VERSION 5.8 ;
BUSBITCHARS "[]" ;
DIVIDERCHAR "/" ;
UNITS
    DATABASE MICRONS 1000 ;
END UNITS

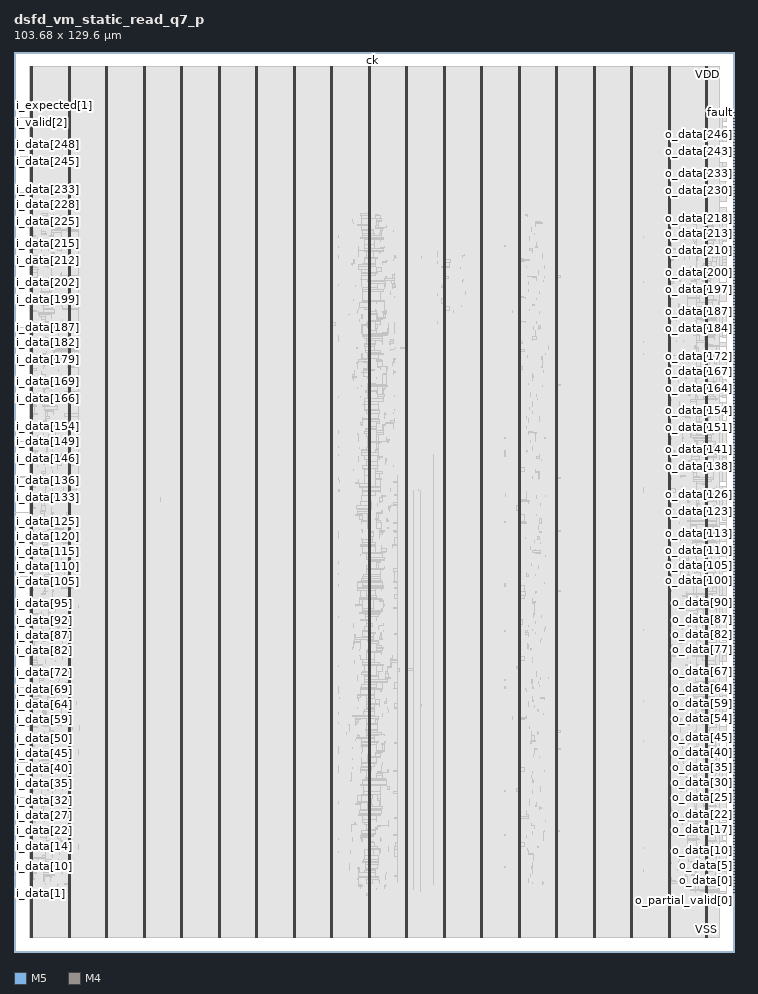
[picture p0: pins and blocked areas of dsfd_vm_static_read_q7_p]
MACRO dsfd_vm_static_read_q7_p
  FOREIGN dsfd_vm_static_read_q7_p 0 0 ;
  CLASS BLOCK ;
  SIZE 103.68 BY 129.6 ;
  PIN ck
    DIRECTION INPUT ;
    USE SIGNAL ;
    PORT
      LAYER M5 ;
        RECT  51.6 129.516 51.624 129.6 ;
    END
  END ck
  PIN fault
    DIRECTION OUTPUT ;
    USE SIGNAL ;
    PORT
      LAYER M4 ;
        RECT  103.596 120.912 103.68 120.936 ;
    END
  END fault
  PIN i_data[0]
    DIRECTION INPUT ;
    USE SIGNAL ;
    PORT
      LAYER M4 ;
        RECT  0 7.968 0.084 7.992 ;
    END
  END i_data[0]
  PIN i_data[100]
    DIRECTION INPUT ;
    USE SIGNAL ;
    PORT
      LAYER M4 ;
        RECT  0 51.168 0.084 51.192 ;
    END
  END i_data[100]
  PIN i_data[101]
    DIRECTION INPUT ;
    USE SIGNAL ;
    PORT
      LAYER M4 ;
        RECT  0 51.6 0.084 51.624 ;
    END
  END i_data[101]
  PIN i_data[102]
    DIRECTION INPUT ;
    USE SIGNAL ;
    PORT
      LAYER M4 ;
        RECT  0 52.032 0.084 52.056 ;
    END
  END i_data[102]
  PIN i_data[103]
    DIRECTION INPUT ;
    USE SIGNAL ;
    PORT
      LAYER M4 ;
        RECT  0 52.464 0.084 52.488 ;
    END
  END i_data[103]
  PIN i_data[104]
    DIRECTION INPUT ;
    USE SIGNAL ;
    PORT
      LAYER M4 ;
        RECT  0 52.896 0.084 52.92 ;
    END
  END i_data[104]
  PIN i_data[105]
    DIRECTION INPUT ;
    USE SIGNAL ;
    PORT
      LAYER M4 ;
        RECT  0 53.328 0.084 53.352 ;
    END
  END i_data[105]
  PIN i_data[106]
    DIRECTION INPUT ;
    USE SIGNAL ;
    PORT
      LAYER M4 ;
        RECT  0 53.76 0.084 53.784 ;
    END
  END i_data[106]
  PIN i_data[107]
    DIRECTION INPUT ;
    USE SIGNAL ;
    PORT
      LAYER M4 ;
        RECT  0 54.192 0.084 54.216 ;
    END
  END i_data[107]
  PIN i_data[108]
    DIRECTION INPUT ;
    USE SIGNAL ;
    PORT
      LAYER M4 ;
        RECT  0 54.624 0.084 54.648 ;
    END
  END i_data[108]
  PIN i_data[109]
    DIRECTION INPUT ;
    USE SIGNAL ;
    PORT
      LAYER M4 ;
        RECT  0 55.056 0.084 55.08 ;
    END
  END i_data[109]
  PIN i_data[10]
    DIRECTION INPUT ;
    USE SIGNAL ;
    PORT
      LAYER M4 ;
        RECT  0 12.288 0.084 12.312 ;
    END
  END i_data[10]
  PIN i_data[110]
    DIRECTION INPUT ;
    USE SIGNAL ;
    PORT
      LAYER M4 ;
        RECT  0 55.488 0.084 55.512 ;
    END
  END i_data[110]
  PIN i_data[111]
    DIRECTION INPUT ;
    USE SIGNAL ;
    PORT
      LAYER M4 ;
        RECT  0 55.92 0.084 55.944 ;
    END
  END i_data[111]
  PIN i_data[112]
    DIRECTION INPUT ;
    USE SIGNAL ;
    PORT
      LAYER M4 ;
        RECT  0 56.352 0.084 56.376 ;
    END
  END i_data[112]
  PIN i_data[113]
    DIRECTION INPUT ;
    USE SIGNAL ;
    PORT
      LAYER M4 ;
        RECT  0 56.784 0.084 56.808 ;
    END
  END i_data[113]
  PIN i_data[114]
    DIRECTION INPUT ;
    USE SIGNAL ;
    PORT
      LAYER M4 ;
        RECT  0 57.216 0.084 57.24 ;
    END
  END i_data[114]
  PIN i_data[115]
    DIRECTION INPUT ;
    USE SIGNAL ;
    PORT
      LAYER M4 ;
        RECT  0 57.648 0.084 57.672 ;
    END
  END i_data[115]
  PIN i_data[116]
    DIRECTION INPUT ;
    USE SIGNAL ;
    PORT
      LAYER M4 ;
        RECT  0 58.08 0.084 58.104 ;
    END
  END i_data[116]
  PIN i_data[117]
    DIRECTION INPUT ;
    USE SIGNAL ;
    PORT
      LAYER M4 ;
        RECT  0 58.512 0.084 58.536 ;
    END
  END i_data[117]
  PIN i_data[118]
    DIRECTION INPUT ;
    USE SIGNAL ;
    PORT
      LAYER M4 ;
        RECT  0 58.944 0.084 58.968 ;
    END
  END i_data[118]
  PIN i_data[119]
    DIRECTION INPUT ;
    USE SIGNAL ;
    PORT
      LAYER M4 ;
        RECT  0 59.376 0.084 59.4 ;
    END
  END i_data[119]
  PIN i_data[11]
    DIRECTION INPUT ;
    USE SIGNAL ;
    PORT
      LAYER M4 ;
        RECT  0 12.72 0.084 12.744 ;
    END
  END i_data[11]
  PIN i_data[120]
    DIRECTION INPUT ;
    USE SIGNAL ;
    PORT
      LAYER M4 ;
        RECT  0 59.808 0.084 59.832 ;
    END
  END i_data[120]
  PIN i_data[121]
    DIRECTION INPUT ;
    USE SIGNAL ;
    PORT
      LAYER M4 ;
        RECT  0 60.24 0.084 60.264 ;
    END
  END i_data[121]
  PIN i_data[122]
    DIRECTION INPUT ;
    USE SIGNAL ;
    PORT
      LAYER M4 ;
        RECT  0 60.672 0.084 60.696 ;
    END
  END i_data[122]
  PIN i_data[123]
    DIRECTION INPUT ;
    USE SIGNAL ;
    PORT
      LAYER M4 ;
        RECT  0 61.104 0.084 61.128 ;
    END
  END i_data[123]
  PIN i_data[124]
    DIRECTION INPUT ;
    USE SIGNAL ;
    PORT
      LAYER M4 ;
        RECT  0 61.536 0.084 61.56 ;
    END
  END i_data[124]
  PIN i_data[125]
    DIRECTION INPUT ;
    USE SIGNAL ;
    PORT
      LAYER M4 ;
        RECT  0 61.968 0.084 61.992 ;
    END
  END i_data[125]
  PIN i_data[126]
    DIRECTION INPUT ;
    USE SIGNAL ;
    PORT
      LAYER M4 ;
        RECT  0 62.4 0.084 62.424 ;
    END
  END i_data[126]
  PIN i_data[127]
    DIRECTION INPUT ;
    USE SIGNAL ;
    PORT
      LAYER M4 ;
        RECT  0 62.832 0.084 62.856 ;
    END
  END i_data[127]
  PIN i_data[128]
    DIRECTION INPUT ;
    USE SIGNAL ;
    PORT
      LAYER M4 ;
        RECT  0 63.264 0.084 63.288 ;
    END
  END i_data[128]
  PIN i_data[129]
    DIRECTION INPUT ;
    USE SIGNAL ;
    PORT
      LAYER M4 ;
        RECT  0 63.696 0.084 63.72 ;
    END
  END i_data[129]
  PIN i_data[12]
    DIRECTION INPUT ;
    USE SIGNAL ;
    PORT
      LAYER M4 ;
        RECT  0 13.152 0.084 13.176 ;
    END
  END i_data[12]
  PIN i_data[130]
    DIRECTION INPUT ;
    USE SIGNAL ;
    PORT
      LAYER M4 ;
        RECT  0 64.128 0.084 64.152 ;
    END
  END i_data[130]
  PIN i_data[131]
    DIRECTION INPUT ;
    USE SIGNAL ;
    PORT
      LAYER M4 ;
        RECT  0 64.56 0.084 64.584 ;
    END
  END i_data[131]
  PIN i_data[132]
    DIRECTION INPUT ;
    USE SIGNAL ;
    PORT
      LAYER M4 ;
        RECT  0 64.992 0.084 65.016 ;
    END
  END i_data[132]
  PIN i_data[133]
    DIRECTION INPUT ;
    USE SIGNAL ;
    PORT
      LAYER M4 ;
        RECT  0 65.424 0.084 65.448 ;
    END
  END i_data[133]
  PIN i_data[134]
    DIRECTION INPUT ;
    USE SIGNAL ;
    PORT
      LAYER M4 ;
        RECT  0 65.856 0.084 65.88 ;
    END
  END i_data[134]
  PIN i_data[135]
    DIRECTION INPUT ;
    USE SIGNAL ;
    PORT
      LAYER M4 ;
        RECT  0 66.288 0.084 66.312 ;
    END
  END i_data[135]
  PIN i_data[136]
    DIRECTION INPUT ;
    USE SIGNAL ;
    PORT
      LAYER M4 ;
        RECT  0 66.72 0.084 66.744 ;
    END
  END i_data[136]
  PIN i_data[137]
    DIRECTION INPUT ;
    USE SIGNAL ;
    PORT
      LAYER M4 ;
        RECT  0 67.152 0.084 67.176 ;
    END
  END i_data[137]
  PIN i_data[138]
    DIRECTION INPUT ;
    USE SIGNAL ;
    PORT
      LAYER M4 ;
        RECT  0 67.584 0.084 67.608 ;
    END
  END i_data[138]
  PIN i_data[139]
    DIRECTION INPUT ;
    USE SIGNAL ;
    PORT
      LAYER M4 ;
        RECT  0 68.016 0.084 68.04 ;
    END
  END i_data[139]
  PIN i_data[13]
    DIRECTION INPUT ;
    USE SIGNAL ;
    PORT
      LAYER M4 ;
        RECT  0 13.584 0.084 13.608 ;
    END
  END i_data[13]
  PIN i_data[140]
    DIRECTION INPUT ;
    USE SIGNAL ;
    PORT
      LAYER M4 ;
        RECT  0 68.448 0.084 68.472 ;
    END
  END i_data[140]
  PIN i_data[141]
    DIRECTION INPUT ;
    USE SIGNAL ;
    PORT
      LAYER M4 ;
        RECT  0 68.88 0.084 68.904 ;
    END
  END i_data[141]
  PIN i_data[142]
    DIRECTION INPUT ;
    USE SIGNAL ;
    PORT
      LAYER M4 ;
        RECT  0 69.312 0.084 69.336 ;
    END
  END i_data[142]
  PIN i_data[143]
    DIRECTION INPUT ;
    USE SIGNAL ;
    PORT
      LAYER M4 ;
        RECT  0 69.744 0.084 69.768 ;
    END
  END i_data[143]
  PIN i_data[144]
    DIRECTION INPUT ;
    USE SIGNAL ;
    PORT
      LAYER M4 ;
        RECT  0 70.176 0.084 70.2 ;
    END
  END i_data[144]
  PIN i_data[145]
    DIRECTION INPUT ;
    USE SIGNAL ;
    PORT
      LAYER M4 ;
        RECT  0 70.608 0.084 70.632 ;
    END
  END i_data[145]
  PIN i_data[146]
    DIRECTION INPUT ;
    USE SIGNAL ;
    PORT
      LAYER M4 ;
        RECT  0 71.04 0.084 71.064 ;
    END
  END i_data[146]
  PIN i_data[147]
    DIRECTION INPUT ;
    USE SIGNAL ;
    PORT
      LAYER M4 ;
        RECT  0 71.472 0.084 71.496 ;
    END
  END i_data[147]
  PIN i_data[148]
    DIRECTION INPUT ;
    USE SIGNAL ;
    PORT
      LAYER M4 ;
        RECT  0 71.904 0.084 71.928 ;
    END
  END i_data[148]
  PIN i_data[149]
    DIRECTION INPUT ;
    USE SIGNAL ;
    PORT
      LAYER M4 ;
        RECT  0 72.336 0.084 72.36 ;
    END
  END i_data[149]
  PIN i_data[14]
    DIRECTION INPUT ;
    USE SIGNAL ;
    PORT
      LAYER M4 ;
        RECT  0 14.016 0.084 14.04 ;
    END
  END i_data[14]
  PIN i_data[150]
    DIRECTION INPUT ;
    USE SIGNAL ;
    PORT
      LAYER M4 ;
        RECT  0 72.768 0.084 72.792 ;
    END
  END i_data[150]
  PIN i_data[151]
    DIRECTION INPUT ;
    USE SIGNAL ;
    PORT
      LAYER M4 ;
        RECT  0 73.2 0.084 73.224 ;
    END
  END i_data[151]
  PIN i_data[152]
    DIRECTION INPUT ;
    USE SIGNAL ;
    PORT
      LAYER M4 ;
        RECT  0 73.632 0.084 73.656 ;
    END
  END i_data[152]
  PIN i_data[153]
    DIRECTION INPUT ;
    USE SIGNAL ;
    PORT
      LAYER M4 ;
        RECT  0 74.064 0.084 74.088 ;
    END
  END i_data[153]
  PIN i_data[154]
    DIRECTION INPUT ;
    USE SIGNAL ;
    PORT
      LAYER M4 ;
        RECT  0 74.496 0.084 74.52 ;
    END
  END i_data[154]
  PIN i_data[155]
    DIRECTION INPUT ;
    USE SIGNAL ;
    PORT
      LAYER M4 ;
        RECT  0 74.928 0.084 74.952 ;
    END
  END i_data[155]
  PIN i_data[156]
    DIRECTION INPUT ;
    USE SIGNAL ;
    PORT
      LAYER M4 ;
        RECT  0 75.36 0.084 75.384 ;
    END
  END i_data[156]
  PIN i_data[157]
    DIRECTION INPUT ;
    USE SIGNAL ;
    PORT
      LAYER M4 ;
        RECT  0 75.792 0.084 75.816 ;
    END
  END i_data[157]
  PIN i_data[158]
    DIRECTION INPUT ;
    USE SIGNAL ;
    PORT
      LAYER M4 ;
        RECT  0 76.224 0.084 76.248 ;
    END
  END i_data[158]
  PIN i_data[159]
    DIRECTION INPUT ;
    USE SIGNAL ;
    PORT
      LAYER M4 ;
        RECT  0 76.656 0.084 76.68 ;
    END
  END i_data[159]
  PIN i_data[15]
    DIRECTION INPUT ;
    USE SIGNAL ;
    PORT
      LAYER M4 ;
        RECT  0 14.448 0.084 14.472 ;
    END
  END i_data[15]
  PIN i_data[160]
    DIRECTION INPUT ;
    USE SIGNAL ;
    PORT
      LAYER M4 ;
        RECT  0 77.088 0.084 77.112 ;
    END
  END i_data[160]
  PIN i_data[161]
    DIRECTION INPUT ;
    USE SIGNAL ;
    PORT
      LAYER M4 ;
        RECT  0 77.52 0.084 77.544 ;
    END
  END i_data[161]
  PIN i_data[162]
    DIRECTION INPUT ;
    USE SIGNAL ;
    PORT
      LAYER M4 ;
        RECT  0 77.952 0.084 77.976 ;
    END
  END i_data[162]
  PIN i_data[163]
    DIRECTION INPUT ;
    USE SIGNAL ;
    PORT
      LAYER M4 ;
        RECT  0 78.384 0.084 78.408 ;
    END
  END i_data[163]
  PIN i_data[164]
    DIRECTION INPUT ;
    USE SIGNAL ;
    PORT
      LAYER M4 ;
        RECT  0 78.816 0.084 78.84 ;
    END
  END i_data[164]
  PIN i_data[165]
    DIRECTION INPUT ;
    USE SIGNAL ;
    PORT
      LAYER M4 ;
        RECT  0 79.248 0.084 79.272 ;
    END
  END i_data[165]
  PIN i_data[166]
    DIRECTION INPUT ;
    USE SIGNAL ;
    PORT
      LAYER M4 ;
        RECT  0 79.68 0.084 79.704 ;
    END
  END i_data[166]
  PIN i_data[167]
    DIRECTION INPUT ;
    USE SIGNAL ;
    PORT
      LAYER M4 ;
        RECT  0 80.112 0.084 80.136 ;
    END
  END i_data[167]
  PIN i_data[168]
    DIRECTION INPUT ;
    USE SIGNAL ;
    PORT
      LAYER M4 ;
        RECT  0 80.544 0.084 80.568 ;
    END
  END i_data[168]
  PIN i_data[169]
    DIRECTION INPUT ;
    USE SIGNAL ;
    PORT
      LAYER M4 ;
        RECT  0 80.976 0.084 81 ;
    END
  END i_data[169]
  PIN i_data[16]
    DIRECTION INPUT ;
    USE SIGNAL ;
    PORT
      LAYER M4 ;
        RECT  0 14.88 0.084 14.904 ;
    END
  END i_data[16]
  PIN i_data[170]
    DIRECTION INPUT ;
    USE SIGNAL ;
    PORT
      LAYER M4 ;
        RECT  0 81.408 0.084 81.432 ;
    END
  END i_data[170]
  PIN i_data[171]
    DIRECTION INPUT ;
    USE SIGNAL ;
    PORT
      LAYER M4 ;
        RECT  0 81.84 0.084 81.864 ;
    END
  END i_data[171]
  PIN i_data[172]
    DIRECTION INPUT ;
    USE SIGNAL ;
    PORT
      LAYER M4 ;
        RECT  0 82.272 0.084 82.296 ;
    END
  END i_data[172]
  PIN i_data[173]
    DIRECTION INPUT ;
    USE SIGNAL ;
    PORT
      LAYER M4 ;
        RECT  0 82.704 0.084 82.728 ;
    END
  END i_data[173]
  PIN i_data[174]
    DIRECTION INPUT ;
    USE SIGNAL ;
    PORT
      LAYER M4 ;
        RECT  0 83.136 0.084 83.16 ;
    END
  END i_data[174]
  PIN i_data[175]
    DIRECTION INPUT ;
    USE SIGNAL ;
    PORT
      LAYER M4 ;
        RECT  0 83.568 0.084 83.592 ;
    END
  END i_data[175]
  PIN i_data[176]
    DIRECTION INPUT ;
    USE SIGNAL ;
    PORT
      LAYER M4 ;
        RECT  0 84 0.084 84.024 ;
    END
  END i_data[176]
  PIN i_data[177]
    DIRECTION INPUT ;
    USE SIGNAL ;
    PORT
      LAYER M4 ;
        RECT  0 84.432 0.084 84.456 ;
    END
  END i_data[177]
  PIN i_data[178]
    DIRECTION INPUT ;
    USE SIGNAL ;
    PORT
      LAYER M4 ;
        RECT  0 84.864 0.084 84.888 ;
    END
  END i_data[178]
  PIN i_data[179]
    DIRECTION INPUT ;
    USE SIGNAL ;
    PORT
      LAYER M4 ;
        RECT  0 85.296 0.084 85.32 ;
    END
  END i_data[179]
  PIN i_data[17]
    DIRECTION INPUT ;
    USE SIGNAL ;
    PORT
      LAYER M4 ;
        RECT  0 15.312 0.084 15.336 ;
    END
  END i_data[17]
  PIN i_data[180]
    DIRECTION INPUT ;
    USE SIGNAL ;
    PORT
      LAYER M4 ;
        RECT  0 85.728 0.084 85.752 ;
    END
  END i_data[180]
  PIN i_data[181]
    DIRECTION INPUT ;
    USE SIGNAL ;
    PORT
      LAYER M4 ;
        RECT  0 86.16 0.084 86.184 ;
    END
  END i_data[181]
  PIN i_data[182]
    DIRECTION INPUT ;
    USE SIGNAL ;
    PORT
      LAYER M4 ;
        RECT  0 86.592 0.084 86.616 ;
    END
  END i_data[182]
  PIN i_data[183]
    DIRECTION INPUT ;
    USE SIGNAL ;
    PORT
      LAYER M4 ;
        RECT  0 87.024 0.084 87.048 ;
    END
  END i_data[183]
  PIN i_data[184]
    DIRECTION INPUT ;
    USE SIGNAL ;
    PORT
      LAYER M4 ;
        RECT  0 87.456 0.084 87.48 ;
    END
  END i_data[184]
  PIN i_data[185]
    DIRECTION INPUT ;
    USE SIGNAL ;
    PORT
      LAYER M4 ;
        RECT  0 87.888 0.084 87.912 ;
    END
  END i_data[185]
  PIN i_data[186]
    DIRECTION INPUT ;
    USE SIGNAL ;
    PORT
      LAYER M4 ;
        RECT  0 88.32 0.084 88.344 ;
    END
  END i_data[186]
  PIN i_data[187]
    DIRECTION INPUT ;
    USE SIGNAL ;
    PORT
      LAYER M4 ;
        RECT  0 88.752 0.084 88.776 ;
    END
  END i_data[187]
  PIN i_data[188]
    DIRECTION INPUT ;
    USE SIGNAL ;
    PORT
      LAYER M4 ;
        RECT  0 89.184 0.084 89.208 ;
    END
  END i_data[188]
  PIN i_data[189]
    DIRECTION INPUT ;
    USE SIGNAL ;
    PORT
      LAYER M4 ;
        RECT  0 89.616 0.084 89.64 ;
    END
  END i_data[189]
  PIN i_data[18]
    DIRECTION INPUT ;
    USE SIGNAL ;
    PORT
      LAYER M4 ;
        RECT  0 15.744 0.084 15.768 ;
    END
  END i_data[18]
  PIN i_data[190]
    DIRECTION INPUT ;
    USE SIGNAL ;
    PORT
      LAYER M4 ;
        RECT  0 90.048 0.084 90.072 ;
    END
  END i_data[190]
  PIN i_data[191]
    DIRECTION INPUT ;
    USE SIGNAL ;
    PORT
      LAYER M4 ;
        RECT  0 90.48 0.084 90.504 ;
    END
  END i_data[191]
  PIN i_data[192]
    DIRECTION INPUT ;
    USE SIGNAL ;
    PORT
      LAYER M4 ;
        RECT  0 90.912 0.084 90.936 ;
    END
  END i_data[192]
  PIN i_data[193]
    DIRECTION INPUT ;
    USE SIGNAL ;
    PORT
      LAYER M4 ;
        RECT  0 91.344 0.084 91.368 ;
    END
  END i_data[193]
  PIN i_data[194]
    DIRECTION INPUT ;
    USE SIGNAL ;
    PORT
      LAYER M4 ;
        RECT  0 91.776 0.084 91.8 ;
    END
  END i_data[194]
  PIN i_data[195]
    DIRECTION INPUT ;
    USE SIGNAL ;
    PORT
      LAYER M4 ;
        RECT  0 92.208 0.084 92.232 ;
    END
  END i_data[195]
  PIN i_data[196]
    DIRECTION INPUT ;
    USE SIGNAL ;
    PORT
      LAYER M4 ;
        RECT  0 92.64 0.084 92.664 ;
    END
  END i_data[196]
  PIN i_data[197]
    DIRECTION INPUT ;
    USE SIGNAL ;
    PORT
      LAYER M4 ;
        RECT  0 93.072 0.084 93.096 ;
    END
  END i_data[197]
  PIN i_data[198]
    DIRECTION INPUT ;
    USE SIGNAL ;
    PORT
      LAYER M4 ;
        RECT  0 93.504 0.084 93.528 ;
    END
  END i_data[198]
  PIN i_data[199]
    DIRECTION INPUT ;
    USE SIGNAL ;
    PORT
      LAYER M4 ;
        RECT  0 93.936 0.084 93.96 ;
    END
  END i_data[199]
  PIN i_data[19]
    DIRECTION INPUT ;
    USE SIGNAL ;
    PORT
      LAYER M4 ;
        RECT  0 16.176 0.084 16.2 ;
    END
  END i_data[19]
  PIN i_data[1]
    DIRECTION INPUT ;
    USE SIGNAL ;
    PORT
      LAYER M4 ;
        RECT  0 8.4 0.084 8.424 ;
    END
  END i_data[1]
  PIN i_data[200]
    DIRECTION INPUT ;
    USE SIGNAL ;
    PORT
      LAYER M4 ;
        RECT  0 94.368 0.084 94.392 ;
    END
  END i_data[200]
  PIN i_data[201]
    DIRECTION INPUT ;
    USE SIGNAL ;
    PORT
      LAYER M4 ;
        RECT  0 94.8 0.084 94.824 ;
    END
  END i_data[201]
  PIN i_data[202]
    DIRECTION INPUT ;
    USE SIGNAL ;
    PORT
      LAYER M4 ;
        RECT  0 95.232 0.084 95.256 ;
    END
  END i_data[202]
  PIN i_data[203]
    DIRECTION INPUT ;
    USE SIGNAL ;
    PORT
      LAYER M4 ;
        RECT  0 95.664 0.084 95.688 ;
    END
  END i_data[203]
  PIN i_data[204]
    DIRECTION INPUT ;
    USE SIGNAL ;
    PORT
      LAYER M4 ;
        RECT  0 96.096 0.084 96.12 ;
    END
  END i_data[204]
  PIN i_data[205]
    DIRECTION INPUT ;
    USE SIGNAL ;
    PORT
      LAYER M4 ;
        RECT  0 96.528 0.084 96.552 ;
    END
  END i_data[205]
  PIN i_data[206]
    DIRECTION INPUT ;
    USE SIGNAL ;
    PORT
      LAYER M4 ;
        RECT  0 96.96 0.084 96.984 ;
    END
  END i_data[206]
  PIN i_data[207]
    DIRECTION INPUT ;
    USE SIGNAL ;
    PORT
      LAYER M4 ;
        RECT  0 97.392 0.084 97.416 ;
    END
  END i_data[207]
  PIN i_data[208]
    DIRECTION INPUT ;
    USE SIGNAL ;
    PORT
      LAYER M4 ;
        RECT  0 97.824 0.084 97.848 ;
    END
  END i_data[208]
  PIN i_data[209]
    DIRECTION INPUT ;
    USE SIGNAL ;
    PORT
      LAYER M4 ;
        RECT  0 98.256 0.084 98.28 ;
    END
  END i_data[209]
  PIN i_data[20]
    DIRECTION INPUT ;
    USE SIGNAL ;
    PORT
      LAYER M4 ;
        RECT  0 16.608 0.084 16.632 ;
    END
  END i_data[20]
  PIN i_data[210]
    DIRECTION INPUT ;
    USE SIGNAL ;
    PORT
      LAYER M4 ;
        RECT  0 98.688 0.084 98.712 ;
    END
  END i_data[210]
  PIN i_data[211]
    DIRECTION INPUT ;
    USE SIGNAL ;
    PORT
      LAYER M4 ;
        RECT  0 99.12 0.084 99.144 ;
    END
  END i_data[211]
  PIN i_data[212]
    DIRECTION INPUT ;
    USE SIGNAL ;
    PORT
      LAYER M4 ;
        RECT  0 99.552 0.084 99.576 ;
    END
  END i_data[212]
  PIN i_data[213]
    DIRECTION INPUT ;
    USE SIGNAL ;
    PORT
      LAYER M4 ;
        RECT  0 99.984 0.084 100.008 ;
    END
  END i_data[213]
  PIN i_data[214]
    DIRECTION INPUT ;
    USE SIGNAL ;
    PORT
      LAYER M4 ;
        RECT  0 100.416 0.084 100.44 ;
    END
  END i_data[214]
  PIN i_data[215]
    DIRECTION INPUT ;
    USE SIGNAL ;
    PORT
      LAYER M4 ;
        RECT  0 100.848 0.084 100.872 ;
    END
  END i_data[215]
  PIN i_data[216]
    DIRECTION INPUT ;
    USE SIGNAL ;
    PORT
      LAYER M4 ;
        RECT  0 101.28 0.084 101.304 ;
    END
  END i_data[216]
  PIN i_data[217]
    DIRECTION INPUT ;
    USE SIGNAL ;
    PORT
      LAYER M4 ;
        RECT  0 101.712 0.084 101.736 ;
    END
  END i_data[217]
  PIN i_data[218]
    DIRECTION INPUT ;
    USE SIGNAL ;
    PORT
      LAYER M4 ;
        RECT  0 102.144 0.084 102.168 ;
    END
  END i_data[218]
  PIN i_data[219]
    DIRECTION INPUT ;
    USE SIGNAL ;
    PORT
      LAYER M4 ;
        RECT  0 102.576 0.084 102.6 ;
    END
  END i_data[219]
  PIN i_data[21]
    DIRECTION INPUT ;
    USE SIGNAL ;
    PORT
      LAYER M4 ;
        RECT  0 17.04 0.084 17.064 ;
    END
  END i_data[21]
  PIN i_data[220]
    DIRECTION INPUT ;
    USE SIGNAL ;
    PORT
      LAYER M4 ;
        RECT  0 103.008 0.084 103.032 ;
    END
  END i_data[220]
  PIN i_data[221]
    DIRECTION INPUT ;
    USE SIGNAL ;
    PORT
      LAYER M4 ;
        RECT  0 103.44 0.084 103.464 ;
    END
  END i_data[221]
  PIN i_data[222]
    DIRECTION INPUT ;
    USE SIGNAL ;
    PORT
      LAYER M4 ;
        RECT  0 103.872 0.084 103.896 ;
    END
  END i_data[222]
  PIN i_data[223]
    DIRECTION INPUT ;
    USE SIGNAL ;
    PORT
      LAYER M4 ;
        RECT  0 104.304 0.084 104.328 ;
    END
  END i_data[223]
  PIN i_data[224]
    DIRECTION INPUT ;
    USE SIGNAL ;
    PORT
      LAYER M4 ;
        RECT  0 104.736 0.084 104.76 ;
    END
  END i_data[224]
  PIN i_data[225]
    DIRECTION INPUT ;
    USE SIGNAL ;
    PORT
      LAYER M4 ;
        RECT  0 105.168 0.084 105.192 ;
    END
  END i_data[225]
  PIN i_data[226]
    DIRECTION INPUT ;
    USE SIGNAL ;
    PORT
      LAYER M4 ;
        RECT  0 105.6 0.084 105.624 ;
    END
  END i_data[226]
  PIN i_data[227]
    DIRECTION INPUT ;
    USE SIGNAL ;
    PORT
      LAYER M4 ;
        RECT  0 106.032 0.084 106.056 ;
    END
  END i_data[227]
  PIN i_data[228]
    DIRECTION INPUT ;
    USE SIGNAL ;
    PORT
      LAYER M4 ;
        RECT  0 106.464 0.084 106.488 ;
    END
  END i_data[228]
  PIN i_data[229]
    DIRECTION INPUT ;
    USE SIGNAL ;
    PORT
      LAYER M4 ;
        RECT  0 106.896 0.084 106.92 ;
    END
  END i_data[229]
  PIN i_data[22]
    DIRECTION INPUT ;
    USE SIGNAL ;
    PORT
      LAYER M4 ;
        RECT  0 17.472 0.084 17.496 ;
    END
  END i_data[22]
  PIN i_data[230]
    DIRECTION INPUT ;
    USE SIGNAL ;
    PORT
      LAYER M4 ;
        RECT  0 107.328 0.084 107.352 ;
    END
  END i_data[230]
  PIN i_data[231]
    DIRECTION INPUT ;
    USE SIGNAL ;
    PORT
      LAYER M4 ;
        RECT  0 107.76 0.084 107.784 ;
    END
  END i_data[231]
  PIN i_data[232]
    DIRECTION INPUT ;
    USE SIGNAL ;
    PORT
      LAYER M4 ;
        RECT  0 108.192 0.084 108.216 ;
    END
  END i_data[232]
  PIN i_data[233]
    DIRECTION INPUT ;
    USE SIGNAL ;
    PORT
      LAYER M4 ;
        RECT  0 108.624 0.084 108.648 ;
    END
  END i_data[233]
  PIN i_data[234]
    DIRECTION INPUT ;
    USE SIGNAL ;
    PORT
      LAYER M4 ;
        RECT  0 109.056 0.084 109.08 ;
    END
  END i_data[234]
  PIN i_data[235]
    DIRECTION INPUT ;
    USE SIGNAL ;
    PORT
      LAYER M4 ;
        RECT  0 109.488 0.084 109.512 ;
    END
  END i_data[235]
  PIN i_data[236]
    DIRECTION INPUT ;
    USE SIGNAL ;
    PORT
      LAYER M4 ;
        RECT  0 109.92 0.084 109.944 ;
    END
  END i_data[236]
  PIN i_data[237]
    DIRECTION INPUT ;
    USE SIGNAL ;
    PORT
      LAYER M4 ;
        RECT  0 110.352 0.084 110.376 ;
    END
  END i_data[237]
  PIN i_data[238]
    DIRECTION INPUT ;
    USE SIGNAL ;
    PORT
      LAYER M4 ;
        RECT  0 110.784 0.084 110.808 ;
    END
  END i_data[238]
  PIN i_data[239]
    DIRECTION INPUT ;
    USE SIGNAL ;
    PORT
      LAYER M4 ;
        RECT  0 111.216 0.084 111.24 ;
    END
  END i_data[239]
  PIN i_data[23]
    DIRECTION INPUT ;
    USE SIGNAL ;
    PORT
      LAYER M4 ;
        RECT  0 17.904 0.084 17.928 ;
    END
  END i_data[23]
  PIN i_data[240]
    DIRECTION INPUT ;
    USE SIGNAL ;
    PORT
      LAYER M4 ;
        RECT  0 111.648 0.084 111.672 ;
    END
  END i_data[240]
  PIN i_data[241]
    DIRECTION INPUT ;
    USE SIGNAL ;
    PORT
      LAYER M4 ;
        RECT  0 112.08 0.084 112.104 ;
    END
  END i_data[241]
  PIN i_data[242]
    DIRECTION INPUT ;
    USE SIGNAL ;
    PORT
      LAYER M4 ;
        RECT  0 112.512 0.084 112.536 ;
    END
  END i_data[242]
  PIN i_data[243]
    DIRECTION INPUT ;
    USE SIGNAL ;
    PORT
      LAYER M4 ;
        RECT  0 112.944 0.084 112.968 ;
    END
  END i_data[243]
  PIN i_data[244]
    DIRECTION INPUT ;
    USE SIGNAL ;
    PORT
      LAYER M4 ;
        RECT  0 113.376 0.084 113.4 ;
    END
  END i_data[244]
  PIN i_data[245]
    DIRECTION INPUT ;
    USE SIGNAL ;
    PORT
      LAYER M4 ;
        RECT  0 113.808 0.084 113.832 ;
    END
  END i_data[245]
  PIN i_data[246]
    DIRECTION INPUT ;
    USE SIGNAL ;
    PORT
      LAYER M4 ;
        RECT  0 114.24 0.084 114.264 ;
    END
  END i_data[246]
  PIN i_data[247]
    DIRECTION INPUT ;
    USE SIGNAL ;
    PORT
      LAYER M4 ;
        RECT  0 114.672 0.084 114.696 ;
    END
  END i_data[247]
  PIN i_data[248]
    DIRECTION INPUT ;
    USE SIGNAL ;
    PORT
      LAYER M4 ;
        RECT  0 115.104 0.084 115.128 ;
    END
  END i_data[248]
  PIN i_data[249]
    DIRECTION INPUT ;
    USE SIGNAL ;
    PORT
      LAYER M4 ;
        RECT  0 115.536 0.084 115.56 ;
    END
  END i_data[249]
  PIN i_data[24]
    DIRECTION INPUT ;
    USE SIGNAL ;
    PORT
      LAYER M4 ;
        RECT  0 18.336 0.084 18.36 ;
    END
  END i_data[24]
  PIN i_data[250]
    DIRECTION INPUT ;
    USE SIGNAL ;
    PORT
      LAYER M4 ;
        RECT  0 115.968 0.084 115.992 ;
    END
  END i_data[250]
  PIN i_data[251]
    DIRECTION INPUT ;
    USE SIGNAL ;
    PORT
      LAYER M4 ;
        RECT  0 116.4 0.084 116.424 ;
    END
  END i_data[251]
  PIN i_data[252]
    DIRECTION INPUT ;
    USE SIGNAL ;
    PORT
      LAYER M4 ;
        RECT  0 116.832 0.084 116.856 ;
    END
  END i_data[252]
  PIN i_data[253]
    DIRECTION INPUT ;
    USE SIGNAL ;
    PORT
      LAYER M4 ;
        RECT  0 117.264 0.084 117.288 ;
    END
  END i_data[253]
  PIN i_data[254]
    DIRECTION INPUT ;
    USE SIGNAL ;
    PORT
      LAYER M4 ;
        RECT  0 117.696 0.084 117.72 ;
    END
  END i_data[254]
  PIN i_data[255]
    DIRECTION INPUT ;
    USE SIGNAL ;
    PORT
      LAYER M4 ;
        RECT  0 118.128 0.084 118.152 ;
    END
  END i_data[255]
  PIN i_data[25]
    DIRECTION INPUT ;
    USE SIGNAL ;
    PORT
      LAYER M4 ;
        RECT  0 18.768 0.084 18.792 ;
    END
  END i_data[25]
  PIN i_data[26]
    DIRECTION INPUT ;
    USE SIGNAL ;
    PORT
      LAYER M4 ;
        RECT  0 19.2 0.084 19.224 ;
    END
  END i_data[26]
  PIN i_data[27]
    DIRECTION INPUT ;
    USE SIGNAL ;
    PORT
      LAYER M4 ;
        RECT  0 19.632 0.084 19.656 ;
    END
  END i_data[27]
  PIN i_data[28]
    DIRECTION INPUT ;
    USE SIGNAL ;
    PORT
      LAYER M4 ;
        RECT  0 20.064 0.084 20.088 ;
    END
  END i_data[28]
  PIN i_data[29]
    DIRECTION INPUT ;
    USE SIGNAL ;
    PORT
      LAYER M4 ;
        RECT  0 20.496 0.084 20.52 ;
    END
  END i_data[29]
  PIN i_data[2]
    DIRECTION INPUT ;
    USE SIGNAL ;
    PORT
      LAYER M4 ;
        RECT  0 8.832 0.084 8.856 ;
    END
  END i_data[2]
  PIN i_data[30]
    DIRECTION INPUT ;
    USE SIGNAL ;
    PORT
      LAYER M4 ;
        RECT  0 20.928 0.084 20.952 ;
    END
  END i_data[30]
  PIN i_data[31]
    DIRECTION INPUT ;
    USE SIGNAL ;
    PORT
      LAYER M4 ;
        RECT  0 21.36 0.084 21.384 ;
    END
  END i_data[31]
  PIN i_data[32]
    DIRECTION INPUT ;
    USE SIGNAL ;
    PORT
      LAYER M4 ;
        RECT  0 21.792 0.084 21.816 ;
    END
  END i_data[32]
  PIN i_data[33]
    DIRECTION INPUT ;
    USE SIGNAL ;
    PORT
      LAYER M4 ;
        RECT  0 22.224 0.084 22.248 ;
    END
  END i_data[33]
  PIN i_data[34]
    DIRECTION INPUT ;
    USE SIGNAL ;
    PORT
      LAYER M4 ;
        RECT  0 22.656 0.084 22.68 ;
    END
  END i_data[34]
  PIN i_data[35]
    DIRECTION INPUT ;
    USE SIGNAL ;
    PORT
      LAYER M4 ;
        RECT  0 23.088 0.084 23.112 ;
    END
  END i_data[35]
  PIN i_data[36]
    DIRECTION INPUT ;
    USE SIGNAL ;
    PORT
      LAYER M4 ;
        RECT  0 23.52 0.084 23.544 ;
    END
  END i_data[36]
  PIN i_data[37]
    DIRECTION INPUT ;
    USE SIGNAL ;
    PORT
      LAYER M4 ;
        RECT  0 23.952 0.084 23.976 ;
    END
  END i_data[37]
  PIN i_data[38]
    DIRECTION INPUT ;
    USE SIGNAL ;
    PORT
      LAYER M4 ;
        RECT  0 24.384 0.084 24.408 ;
    END
  END i_data[38]
  PIN i_data[39]
    DIRECTION INPUT ;
    USE SIGNAL ;
    PORT
      LAYER M4 ;
        RECT  0 24.816 0.084 24.84 ;
    END
  END i_data[39]
  PIN i_data[3]
    DIRECTION INPUT ;
    USE SIGNAL ;
    PORT
      LAYER M4 ;
        RECT  0 9.264 0.084 9.288 ;
    END
  END i_data[3]
  PIN i_data[40]
    DIRECTION INPUT ;
    USE SIGNAL ;
    PORT
      LAYER M4 ;
        RECT  0 25.248 0.084 25.272 ;
    END
  END i_data[40]
  PIN i_data[41]
    DIRECTION INPUT ;
    USE SIGNAL ;
    PORT
      LAYER M4 ;
        RECT  0 25.68 0.084 25.704 ;
    END
  END i_data[41]
  PIN i_data[42]
    DIRECTION INPUT ;
    USE SIGNAL ;
    PORT
      LAYER M4 ;
        RECT  0 26.112 0.084 26.136 ;
    END
  END i_data[42]
  PIN i_data[43]
    DIRECTION INPUT ;
    USE SIGNAL ;
    PORT
      LAYER M4 ;
        RECT  0 26.544 0.084 26.568 ;
    END
  END i_data[43]
  PIN i_data[44]
    DIRECTION INPUT ;
    USE SIGNAL ;
    PORT
      LAYER M4 ;
        RECT  0 26.976 0.084 27 ;
    END
  END i_data[44]
  PIN i_data[45]
    DIRECTION INPUT ;
    USE SIGNAL ;
    PORT
      LAYER M4 ;
        RECT  0 27.408 0.084 27.432 ;
    END
  END i_data[45]
  PIN i_data[46]
    DIRECTION INPUT ;
    USE SIGNAL ;
    PORT
      LAYER M4 ;
        RECT  0 27.84 0.084 27.864 ;
    END
  END i_data[46]
  PIN i_data[47]
    DIRECTION INPUT ;
    USE SIGNAL ;
    PORT
      LAYER M4 ;
        RECT  0 28.272 0.084 28.296 ;
    END
  END i_data[47]
  PIN i_data[48]
    DIRECTION INPUT ;
    USE SIGNAL ;
    PORT
      LAYER M4 ;
        RECT  0 28.704 0.084 28.728 ;
    END
  END i_data[48]
  PIN i_data[49]
    DIRECTION INPUT ;
    USE SIGNAL ;
    PORT
      LAYER M4 ;
        RECT  0 29.136 0.084 29.16 ;
    END
  END i_data[49]
  PIN i_data[4]
    DIRECTION INPUT ;
    USE SIGNAL ;
    PORT
      LAYER M4 ;
        RECT  0 9.696 0.084 9.72 ;
    END
  END i_data[4]
  PIN i_data[50]
    DIRECTION INPUT ;
    USE SIGNAL ;
    PORT
      LAYER M4 ;
        RECT  0 29.568 0.084 29.592 ;
    END
  END i_data[50]
  PIN i_data[51]
    DIRECTION INPUT ;
    USE SIGNAL ;
    PORT
      LAYER M4 ;
        RECT  0 30 0.084 30.024 ;
    END
  END i_data[51]
  PIN i_data[52]
    DIRECTION INPUT ;
    USE SIGNAL ;
    PORT
      LAYER M4 ;
        RECT  0 30.432 0.084 30.456 ;
    END
  END i_data[52]
  PIN i_data[53]
    DIRECTION INPUT ;
    USE SIGNAL ;
    PORT
      LAYER M4 ;
        RECT  0 30.864 0.084 30.888 ;
    END
  END i_data[53]
  PIN i_data[54]
    DIRECTION INPUT ;
    USE SIGNAL ;
    PORT
      LAYER M4 ;
        RECT  0 31.296 0.084 31.32 ;
    END
  END i_data[54]
  PIN i_data[55]
    DIRECTION INPUT ;
    USE SIGNAL ;
    PORT
      LAYER M4 ;
        RECT  0 31.728 0.084 31.752 ;
    END
  END i_data[55]
  PIN i_data[56]
    DIRECTION INPUT ;
    USE SIGNAL ;
    PORT
      LAYER M4 ;
        RECT  0 32.16 0.084 32.184 ;
    END
  END i_data[56]
  PIN i_data[57]
    DIRECTION INPUT ;
    USE SIGNAL ;
    PORT
      LAYER M4 ;
        RECT  0 32.592 0.084 32.616 ;
    END
  END i_data[57]
  PIN i_data[58]
    DIRECTION INPUT ;
    USE SIGNAL ;
    PORT
      LAYER M4 ;
        RECT  0 33.024 0.084 33.048 ;
    END
  END i_data[58]
  PIN i_data[59]
    DIRECTION INPUT ;
    USE SIGNAL ;
    PORT
      LAYER M4 ;
        RECT  0 33.456 0.084 33.48 ;
    END
  END i_data[59]
  PIN i_data[5]
    DIRECTION INPUT ;
    USE SIGNAL ;
    PORT
      LAYER M4 ;
        RECT  0 10.128 0.084 10.152 ;
    END
  END i_data[5]
  PIN i_data[60]
    DIRECTION INPUT ;
    USE SIGNAL ;
    PORT
      LAYER M4 ;
        RECT  0 33.888 0.084 33.912 ;
    END
  END i_data[60]
  PIN i_data[61]
    DIRECTION INPUT ;
    USE SIGNAL ;
    PORT
      LAYER M4 ;
        RECT  0 34.32 0.084 34.344 ;
    END
  END i_data[61]
  PIN i_data[62]
    DIRECTION INPUT ;
    USE SIGNAL ;
    PORT
      LAYER M4 ;
        RECT  0 34.752 0.084 34.776 ;
    END
  END i_data[62]
  PIN i_data[63]
    DIRECTION INPUT ;
    USE SIGNAL ;
    PORT
      LAYER M4 ;
        RECT  0 35.184 0.084 35.208 ;
    END
  END i_data[63]
  PIN i_data[64]
    DIRECTION INPUT ;
    USE SIGNAL ;
    PORT
      LAYER M4 ;
        RECT  0 35.616 0.084 35.64 ;
    END
  END i_data[64]
  PIN i_data[65]
    DIRECTION INPUT ;
    USE SIGNAL ;
    PORT
      LAYER M4 ;
        RECT  0 36.048 0.084 36.072 ;
    END
  END i_data[65]
  PIN i_data[66]
    DIRECTION INPUT ;
    USE SIGNAL ;
    PORT
      LAYER M4 ;
        RECT  0 36.48 0.084 36.504 ;
    END
  END i_data[66]
  PIN i_data[67]
    DIRECTION INPUT ;
    USE SIGNAL ;
    PORT
      LAYER M4 ;
        RECT  0 36.912 0.084 36.936 ;
    END
  END i_data[67]
  PIN i_data[68]
    DIRECTION INPUT ;
    USE SIGNAL ;
    PORT
      LAYER M4 ;
        RECT  0 37.344 0.084 37.368 ;
    END
  END i_data[68]
  PIN i_data[69]
    DIRECTION INPUT ;
    USE SIGNAL ;
    PORT
      LAYER M4 ;
        RECT  0 37.776 0.084 37.8 ;
    END
  END i_data[69]
  PIN i_data[6]
    DIRECTION INPUT ;
    USE SIGNAL ;
    PORT
      LAYER M4 ;
        RECT  0 10.56 0.084 10.584 ;
    END
  END i_data[6]
  PIN i_data[70]
    DIRECTION INPUT ;
    USE SIGNAL ;
    PORT
      LAYER M4 ;
        RECT  0 38.208 0.084 38.232 ;
    END
  END i_data[70]
  PIN i_data[71]
    DIRECTION INPUT ;
    USE SIGNAL ;
    PORT
      LAYER M4 ;
        RECT  0 38.64 0.084 38.664 ;
    END
  END i_data[71]
  PIN i_data[72]
    DIRECTION INPUT ;
    USE SIGNAL ;
    PORT
      LAYER M4 ;
        RECT  0 39.072 0.084 39.096 ;
    END
  END i_data[72]
  PIN i_data[73]
    DIRECTION INPUT ;
    USE SIGNAL ;
    PORT
      LAYER M4 ;
        RECT  0 39.504 0.084 39.528 ;
    END
  END i_data[73]
  PIN i_data[74]
    DIRECTION INPUT ;
    USE SIGNAL ;
    PORT
      LAYER M4 ;
        RECT  0 39.936 0.084 39.96 ;
    END
  END i_data[74]
  PIN i_data[75]
    DIRECTION INPUT ;
    USE SIGNAL ;
    PORT
      LAYER M4 ;
        RECT  0 40.368 0.084 40.392 ;
    END
  END i_data[75]
  PIN i_data[76]
    DIRECTION INPUT ;
    USE SIGNAL ;
    PORT
      LAYER M4 ;
        RECT  0 40.8 0.084 40.824 ;
    END
  END i_data[76]
  PIN i_data[77]
    DIRECTION INPUT ;
    USE SIGNAL ;
    PORT
      LAYER M4 ;
        RECT  0 41.232 0.084 41.256 ;
    END
  END i_data[77]
  PIN i_data[78]
    DIRECTION INPUT ;
    USE SIGNAL ;
    PORT
      LAYER M4 ;
        RECT  0 41.664 0.084 41.688 ;
    END
  END i_data[78]
  PIN i_data[79]
    DIRECTION INPUT ;
    USE SIGNAL ;
    PORT
      LAYER M4 ;
        RECT  0 42.096 0.084 42.12 ;
    END
  END i_data[79]
  PIN i_data[7]
    DIRECTION INPUT ;
    USE SIGNAL ;
    PORT
      LAYER M4 ;
        RECT  0 10.992 0.084 11.016 ;
    END
  END i_data[7]
  PIN i_data[80]
    DIRECTION INPUT ;
    USE SIGNAL ;
    PORT
      LAYER M4 ;
        RECT  0 42.528 0.084 42.552 ;
    END
  END i_data[80]
  PIN i_data[81]
    DIRECTION INPUT ;
    USE SIGNAL ;
    PORT
      LAYER M4 ;
        RECT  0 42.96 0.084 42.984 ;
    END
  END i_data[81]
  PIN i_data[82]
    DIRECTION INPUT ;
    USE SIGNAL ;
    PORT
      LAYER M4 ;
        RECT  0 43.392 0.084 43.416 ;
    END
  END i_data[82]
  PIN i_data[83]
    DIRECTION INPUT ;
    USE SIGNAL ;
    PORT
      LAYER M4 ;
        RECT  0 43.824 0.084 43.848 ;
    END
  END i_data[83]
  PIN i_data[84]
    DIRECTION INPUT ;
    USE SIGNAL ;
    PORT
      LAYER M4 ;
        RECT  0 44.256 0.084 44.28 ;
    END
  END i_data[84]
  PIN i_data[85]
    DIRECTION INPUT ;
    USE SIGNAL ;
    PORT
      LAYER M4 ;
        RECT  0 44.688 0.084 44.712 ;
    END
  END i_data[85]
  PIN i_data[86]
    DIRECTION INPUT ;
    USE SIGNAL ;
    PORT
      LAYER M4 ;
        RECT  0 45.12 0.084 45.144 ;
    END
  END i_data[86]
  PIN i_data[87]
    DIRECTION INPUT ;
    USE SIGNAL ;
    PORT
      LAYER M4 ;
        RECT  0 45.552 0.084 45.576 ;
    END
  END i_data[87]
  PIN i_data[88]
    DIRECTION INPUT ;
    USE SIGNAL ;
    PORT
      LAYER M4 ;
        RECT  0 45.984 0.084 46.008 ;
    END
  END i_data[88]
  PIN i_data[89]
    DIRECTION INPUT ;
    USE SIGNAL ;
    PORT
      LAYER M4 ;
        RECT  0 46.416 0.084 46.44 ;
    END
  END i_data[89]
  PIN i_data[8]
    DIRECTION INPUT ;
    USE SIGNAL ;
    PORT
      LAYER M4 ;
        RECT  0 11.424 0.084 11.448 ;
    END
  END i_data[8]
  PIN i_data[90]
    DIRECTION INPUT ;
    USE SIGNAL ;
    PORT
      LAYER M4 ;
        RECT  0 46.848 0.084 46.872 ;
    END
  END i_data[90]
  PIN i_data[91]
    DIRECTION INPUT ;
    USE SIGNAL ;
    PORT
      LAYER M4 ;
        RECT  0 47.28 0.084 47.304 ;
    END
  END i_data[91]
  PIN i_data[92]
    DIRECTION INPUT ;
    USE SIGNAL ;
    PORT
      LAYER M4 ;
        RECT  0 47.712 0.084 47.736 ;
    END
  END i_data[92]
  PIN i_data[93]
    DIRECTION INPUT ;
    USE SIGNAL ;
    PORT
      LAYER M4 ;
        RECT  0 48.144 0.084 48.168 ;
    END
  END i_data[93]
  PIN i_data[94]
    DIRECTION INPUT ;
    USE SIGNAL ;
    PORT
      LAYER M4 ;
        RECT  0 48.576 0.084 48.6 ;
    END
  END i_data[94]
  PIN i_data[95]
    DIRECTION INPUT ;
    USE SIGNAL ;
    PORT
      LAYER M4 ;
        RECT  0 49.008 0.084 49.032 ;
    END
  END i_data[95]
  PIN i_data[96]
    DIRECTION INPUT ;
    USE SIGNAL ;
    PORT
      LAYER M4 ;
        RECT  0 49.44 0.084 49.464 ;
    END
  END i_data[96]
  PIN i_data[97]
    DIRECTION INPUT ;
    USE SIGNAL ;
    PORT
      LAYER M4 ;
        RECT  0 49.872 0.084 49.896 ;
    END
  END i_data[97]
  PIN i_data[98]
    DIRECTION INPUT ;
    USE SIGNAL ;
    PORT
      LAYER M4 ;
        RECT  0 50.304 0.084 50.328 ;
    END
  END i_data[98]
  PIN i_data[99]
    DIRECTION INPUT ;
    USE SIGNAL ;
    PORT
      LAYER M4 ;
        RECT  0 50.736 0.084 50.76 ;
    END
  END i_data[99]
  PIN i_data[9]
    DIRECTION INPUT ;
    USE SIGNAL ;
    PORT
      LAYER M4 ;
        RECT  0 11.856 0.084 11.88 ;
    END
  END i_data[9]
  PIN i_expected[0]
    DIRECTION INPUT ;
    USE SIGNAL ;
    PORT
      LAYER M4 ;
        RECT  0 120.288 0.084 120.312 ;
    END
  END i_expected[0]
  PIN i_expected[1]
    DIRECTION INPUT ;
    USE SIGNAL ;
    PORT
      LAYER M4 ;
        RECT  0 120.72 0.084 120.744 ;
    END
  END i_expected[1]
  PIN i_expected[2]
    DIRECTION INPUT ;
    USE SIGNAL ;
    PORT
      LAYER M4 ;
        RECT  0 121.152 0.084 121.176 ;
    END
  END i_expected[2]
  PIN i_expected[3]
    DIRECTION INPUT ;
    USE SIGNAL ;
    PORT
      LAYER M4 ;
        RECT  0 121.584 0.084 121.608 ;
    END
  END i_expected[3]
  PIN i_valid[0]
    DIRECTION INPUT ;
    USE SIGNAL ;
    PORT
      LAYER M4 ;
        RECT  0 118.56 0.084 118.584 ;
    END
  END i_valid[0]
  PIN i_valid[1]
    DIRECTION INPUT ;
    USE SIGNAL ;
    PORT
      LAYER M4 ;
        RECT  0 118.992 0.084 119.016 ;
    END
  END i_valid[1]
  PIN i_valid[2]
    DIRECTION INPUT ;
    USE SIGNAL ;
    PORT
      LAYER M4 ;
        RECT  0 119.424 0.084 119.448 ;
    END
  END i_valid[2]
  PIN i_valid[3]
    DIRECTION INPUT ;
    USE SIGNAL ;
    PORT
      LAYER M4 ;
        RECT  0 119.856 0.084 119.88 ;
    END
  END i_valid[3]
  PIN o_data[0]
    DIRECTION OUTPUT ;
    USE SIGNAL ;
    PORT
      LAYER M4 ;
        RECT  103.596 10.32 103.68 10.344 ;
    END
  END o_data[0]
  PIN o_data[100]
    DIRECTION OUTPUT ;
    USE SIGNAL ;
    PORT
      LAYER M4 ;
        RECT  103.596 53.52 103.68 53.544 ;
    END
  END o_data[100]
  PIN o_data[101]
    DIRECTION OUTPUT ;
    USE SIGNAL ;
    PORT
      LAYER M4 ;
        RECT  103.596 53.952 103.68 53.976 ;
    END
  END o_data[101]
  PIN o_data[102]
    DIRECTION OUTPUT ;
    USE SIGNAL ;
    PORT
      LAYER M4 ;
        RECT  103.596 54.384 103.68 54.408 ;
    END
  END o_data[102]
  PIN o_data[103]
    DIRECTION OUTPUT ;
    USE SIGNAL ;
    PORT
      LAYER M4 ;
        RECT  103.596 54.816 103.68 54.84 ;
    END
  END o_data[103]
  PIN o_data[104]
    DIRECTION OUTPUT ;
    USE SIGNAL ;
    PORT
      LAYER M4 ;
        RECT  103.596 55.248 103.68 55.272 ;
    END
  END o_data[104]
  PIN o_data[105]
    DIRECTION OUTPUT ;
    USE SIGNAL ;
    PORT
      LAYER M4 ;
        RECT  103.596 55.68 103.68 55.704 ;
    END
  END o_data[105]
  PIN o_data[106]
    DIRECTION OUTPUT ;
    USE SIGNAL ;
    PORT
      LAYER M4 ;
        RECT  103.596 56.112 103.68 56.136 ;
    END
  END o_data[106]
  PIN o_data[107]
    DIRECTION OUTPUT ;
    USE SIGNAL ;
    PORT
      LAYER M4 ;
        RECT  103.596 56.544 103.68 56.568 ;
    END
  END o_data[107]
  PIN o_data[108]
    DIRECTION OUTPUT ;
    USE SIGNAL ;
    PORT
      LAYER M4 ;
        RECT  103.596 56.976 103.68 57 ;
    END
  END o_data[108]
  PIN o_data[109]
    DIRECTION OUTPUT ;
    USE SIGNAL ;
    PORT
      LAYER M4 ;
        RECT  103.596 57.408 103.68 57.432 ;
    END
  END o_data[109]
  PIN o_data[10]
    DIRECTION OUTPUT ;
    USE SIGNAL ;
    PORT
      LAYER M4 ;
        RECT  103.596 14.64 103.68 14.664 ;
    END
  END o_data[10]
  PIN o_data[110]
    DIRECTION OUTPUT ;
    USE SIGNAL ;
    PORT
      LAYER M4 ;
        RECT  103.596 57.84 103.68 57.864 ;
    END
  END o_data[110]
  PIN o_data[111]
    DIRECTION OUTPUT ;
    USE SIGNAL ;
    PORT
      LAYER M4 ;
        RECT  103.596 58.272 103.68 58.296 ;
    END
  END o_data[111]
  PIN o_data[112]
    DIRECTION OUTPUT ;
    USE SIGNAL ;
    PORT
      LAYER M4 ;
        RECT  103.596 58.704 103.68 58.728 ;
    END
  END o_data[112]
  PIN o_data[113]
    DIRECTION OUTPUT ;
    USE SIGNAL ;
    PORT
      LAYER M4 ;
        RECT  103.596 59.136 103.68 59.16 ;
    END
  END o_data[113]
  PIN o_data[114]
    DIRECTION OUTPUT ;
    USE SIGNAL ;
    PORT
      LAYER M4 ;
        RECT  103.596 59.568 103.68 59.592 ;
    END
  END o_data[114]
  PIN o_data[115]
    DIRECTION OUTPUT ;
    USE SIGNAL ;
    PORT
      LAYER M4 ;
        RECT  103.596 60 103.68 60.024 ;
    END
  END o_data[115]
  PIN o_data[116]
    DIRECTION OUTPUT ;
    USE SIGNAL ;
    PORT
      LAYER M4 ;
        RECT  103.596 60.432 103.68 60.456 ;
    END
  END o_data[116]
  PIN o_data[117]
    DIRECTION OUTPUT ;
    USE SIGNAL ;
    PORT
      LAYER M4 ;
        RECT  103.596 60.864 103.68 60.888 ;
    END
  END o_data[117]
  PIN o_data[118]
    DIRECTION OUTPUT ;
    USE SIGNAL ;
    PORT
      LAYER M4 ;
        RECT  103.596 61.296 103.68 61.32 ;
    END
  END o_data[118]
  PIN o_data[119]
    DIRECTION OUTPUT ;
    USE SIGNAL ;
    PORT
      LAYER M4 ;
        RECT  103.596 61.728 103.68 61.752 ;
    END
  END o_data[119]
  PIN o_data[11]
    DIRECTION OUTPUT ;
    USE SIGNAL ;
    PORT
      LAYER M4 ;
        RECT  103.596 15.072 103.68 15.096 ;
    END
  END o_data[11]
  PIN o_data[120]
    DIRECTION OUTPUT ;
    USE SIGNAL ;
    PORT
      LAYER M4 ;
        RECT  103.596 62.16 103.68 62.184 ;
    END
  END o_data[120]
  PIN o_data[121]
    DIRECTION OUTPUT ;
    USE SIGNAL ;
    PORT
      LAYER M4 ;
        RECT  103.596 62.592 103.68 62.616 ;
    END
  END o_data[121]
  PIN o_data[122]
    DIRECTION OUTPUT ;
    USE SIGNAL ;
    PORT
      LAYER M4 ;
        RECT  103.596 63.024 103.68 63.048 ;
    END
  END o_data[122]
  PIN o_data[123]
    DIRECTION OUTPUT ;
    USE SIGNAL ;
    PORT
      LAYER M4 ;
        RECT  103.596 63.456 103.68 63.48 ;
    END
  END o_data[123]
  PIN o_data[124]
    DIRECTION OUTPUT ;
    USE SIGNAL ;
    PORT
      LAYER M4 ;
        RECT  103.596 63.888 103.68 63.912 ;
    END
  END o_data[124]
  PIN o_data[125]
    DIRECTION OUTPUT ;
    USE SIGNAL ;
    PORT
      LAYER M4 ;
        RECT  103.596 64.32 103.68 64.344 ;
    END
  END o_data[125]
  PIN o_data[126]
    DIRECTION OUTPUT ;
    USE SIGNAL ;
    PORT
      LAYER M4 ;
        RECT  103.596 64.752 103.68 64.776 ;
    END
  END o_data[126]
  PIN o_data[127]
    DIRECTION OUTPUT ;
    USE SIGNAL ;
    PORT
      LAYER M4 ;
        RECT  103.596 65.184 103.68 65.208 ;
    END
  END o_data[127]
  PIN o_data[128]
    DIRECTION OUTPUT ;
    USE SIGNAL ;
    PORT
      LAYER M4 ;
        RECT  103.596 65.616 103.68 65.64 ;
    END
  END o_data[128]
  PIN o_data[129]
    DIRECTION OUTPUT ;
    USE SIGNAL ;
    PORT
      LAYER M4 ;
        RECT  103.596 66.048 103.68 66.072 ;
    END
  END o_data[129]
  PIN o_data[12]
    DIRECTION OUTPUT ;
    USE SIGNAL ;
    PORT
      LAYER M4 ;
        RECT  103.596 15.504 103.68 15.528 ;
    END
  END o_data[12]
  PIN o_data[130]
    DIRECTION OUTPUT ;
    USE SIGNAL ;
    PORT
      LAYER M4 ;
        RECT  103.596 66.48 103.68 66.504 ;
    END
  END o_data[130]
  PIN o_data[131]
    DIRECTION OUTPUT ;
    USE SIGNAL ;
    PORT
      LAYER M4 ;
        RECT  103.596 66.912 103.68 66.936 ;
    END
  END o_data[131]
  PIN o_data[132]
    DIRECTION OUTPUT ;
    USE SIGNAL ;
    PORT
      LAYER M4 ;
        RECT  103.596 67.344 103.68 67.368 ;
    END
  END o_data[132]
  PIN o_data[133]
    DIRECTION OUTPUT ;
    USE SIGNAL ;
    PORT
      LAYER M4 ;
        RECT  103.596 67.776 103.68 67.8 ;
    END
  END o_data[133]
  PIN o_data[134]
    DIRECTION OUTPUT ;
    USE SIGNAL ;
    PORT
      LAYER M4 ;
        RECT  103.596 68.208 103.68 68.232 ;
    END
  END o_data[134]
  PIN o_data[135]
    DIRECTION OUTPUT ;
    USE SIGNAL ;
    PORT
      LAYER M4 ;
        RECT  103.596 68.64 103.68 68.664 ;
    END
  END o_data[135]
  PIN o_data[136]
    DIRECTION OUTPUT ;
    USE SIGNAL ;
    PORT
      LAYER M4 ;
        RECT  103.596 69.072 103.68 69.096 ;
    END
  END o_data[136]
  PIN o_data[137]
    DIRECTION OUTPUT ;
    USE SIGNAL ;
    PORT
      LAYER M4 ;
        RECT  103.596 69.504 103.68 69.528 ;
    END
  END o_data[137]
  PIN o_data[138]
    DIRECTION OUTPUT ;
    USE SIGNAL ;
    PORT
      LAYER M4 ;
        RECT  103.596 69.936 103.68 69.96 ;
    END
  END o_data[138]
  PIN o_data[139]
    DIRECTION OUTPUT ;
    USE SIGNAL ;
    PORT
      LAYER M4 ;
        RECT  103.596 70.368 103.68 70.392 ;
    END
  END o_data[139]
  PIN o_data[13]
    DIRECTION OUTPUT ;
    USE SIGNAL ;
    PORT
      LAYER M4 ;
        RECT  103.596 15.936 103.68 15.96 ;
    END
  END o_data[13]
  PIN o_data[140]
    DIRECTION OUTPUT ;
    USE SIGNAL ;
    PORT
      LAYER M4 ;
        RECT  103.596 70.8 103.68 70.824 ;
    END
  END o_data[140]
  PIN o_data[141]
    DIRECTION OUTPUT ;
    USE SIGNAL ;
    PORT
      LAYER M4 ;
        RECT  103.596 71.232 103.68 71.256 ;
    END
  END o_data[141]
  PIN o_data[142]
    DIRECTION OUTPUT ;
    USE SIGNAL ;
    PORT
      LAYER M4 ;
        RECT  103.596 71.664 103.68 71.688 ;
    END
  END o_data[142]
  PIN o_data[143]
    DIRECTION OUTPUT ;
    USE SIGNAL ;
    PORT
      LAYER M4 ;
        RECT  103.596 72.096 103.68 72.12 ;
    END
  END o_data[143]
  PIN o_data[144]
    DIRECTION OUTPUT ;
    USE SIGNAL ;
    PORT
      LAYER M4 ;
        RECT  103.596 72.528 103.68 72.552 ;
    END
  END o_data[144]
  PIN o_data[145]
    DIRECTION OUTPUT ;
    USE SIGNAL ;
    PORT
      LAYER M4 ;
        RECT  103.596 72.96 103.68 72.984 ;
    END
  END o_data[145]
  PIN o_data[146]
    DIRECTION OUTPUT ;
    USE SIGNAL ;
    PORT
      LAYER M4 ;
        RECT  103.596 73.392 103.68 73.416 ;
    END
  END o_data[146]
  PIN o_data[147]
    DIRECTION OUTPUT ;
    USE SIGNAL ;
    PORT
      LAYER M4 ;
        RECT  103.596 73.824 103.68 73.848 ;
    END
  END o_data[147]
  PIN o_data[148]
    DIRECTION OUTPUT ;
    USE SIGNAL ;
    PORT
      LAYER M4 ;
        RECT  103.596 74.256 103.68 74.28 ;
    END
  END o_data[148]
  PIN o_data[149]
    DIRECTION OUTPUT ;
    USE SIGNAL ;
    PORT
      LAYER M4 ;
        RECT  103.596 74.688 103.68 74.712 ;
    END
  END o_data[149]
  PIN o_data[14]
    DIRECTION OUTPUT ;
    USE SIGNAL ;
    PORT
      LAYER M4 ;
        RECT  103.596 16.368 103.68 16.392 ;
    END
  END o_data[14]
  PIN o_data[150]
    DIRECTION OUTPUT ;
    USE SIGNAL ;
    PORT
      LAYER M4 ;
        RECT  103.596 75.12 103.68 75.144 ;
    END
  END o_data[150]
  PIN o_data[151]
    DIRECTION OUTPUT ;
    USE SIGNAL ;
    PORT
      LAYER M4 ;
        RECT  103.596 75.552 103.68 75.576 ;
    END
  END o_data[151]
  PIN o_data[152]
    DIRECTION OUTPUT ;
    USE SIGNAL ;
    PORT
      LAYER M4 ;
        RECT  103.596 75.984 103.68 76.008 ;
    END
  END o_data[152]
  PIN o_data[153]
    DIRECTION OUTPUT ;
    USE SIGNAL ;
    PORT
      LAYER M4 ;
        RECT  103.596 76.416 103.68 76.44 ;
    END
  END o_data[153]
  PIN o_data[154]
    DIRECTION OUTPUT ;
    USE SIGNAL ;
    PORT
      LAYER M4 ;
        RECT  103.596 76.848 103.68 76.872 ;
    END
  END o_data[154]
  PIN o_data[155]
    DIRECTION OUTPUT ;
    USE SIGNAL ;
    PORT
      LAYER M4 ;
        RECT  103.596 77.28 103.68 77.304 ;
    END
  END o_data[155]
  PIN o_data[156]
    DIRECTION OUTPUT ;
    USE SIGNAL ;
    PORT
      LAYER M4 ;
        RECT  103.596 77.712 103.68 77.736 ;
    END
  END o_data[156]
  PIN o_data[157]
    DIRECTION OUTPUT ;
    USE SIGNAL ;
    PORT
      LAYER M4 ;
        RECT  103.596 78.144 103.68 78.168 ;
    END
  END o_data[157]
  PIN o_data[158]
    DIRECTION OUTPUT ;
    USE SIGNAL ;
    PORT
      LAYER M4 ;
        RECT  103.596 78.576 103.68 78.6 ;
    END
  END o_data[158]
  PIN o_data[159]
    DIRECTION OUTPUT ;
    USE SIGNAL ;
    PORT
      LAYER M4 ;
        RECT  103.596 79.008 103.68 79.032 ;
    END
  END o_data[159]
  PIN o_data[15]
    DIRECTION OUTPUT ;
    USE SIGNAL ;
    PORT
      LAYER M4 ;
        RECT  103.596 16.8 103.68 16.824 ;
    END
  END o_data[15]
  PIN o_data[160]
    DIRECTION OUTPUT ;
    USE SIGNAL ;
    PORT
      LAYER M4 ;
        RECT  103.596 79.44 103.68 79.464 ;
    END
  END o_data[160]
  PIN o_data[161]
    DIRECTION OUTPUT ;
    USE SIGNAL ;
    PORT
      LAYER M4 ;
        RECT  103.596 79.872 103.68 79.896 ;
    END
  END o_data[161]
  PIN o_data[162]
    DIRECTION OUTPUT ;
    USE SIGNAL ;
    PORT
      LAYER M4 ;
        RECT  103.596 80.304 103.68 80.328 ;
    END
  END o_data[162]
  PIN o_data[163]
    DIRECTION OUTPUT ;
    USE SIGNAL ;
    PORT
      LAYER M4 ;
        RECT  103.596 80.736 103.68 80.76 ;
    END
  END o_data[163]
  PIN o_data[164]
    DIRECTION OUTPUT ;
    USE SIGNAL ;
    PORT
      LAYER M4 ;
        RECT  103.596 81.168 103.68 81.192 ;
    END
  END o_data[164]
  PIN o_data[165]
    DIRECTION OUTPUT ;
    USE SIGNAL ;
    PORT
      LAYER M4 ;
        RECT  103.596 81.6 103.68 81.624 ;
    END
  END o_data[165]
  PIN o_data[166]
    DIRECTION OUTPUT ;
    USE SIGNAL ;
    PORT
      LAYER M4 ;
        RECT  103.596 82.032 103.68 82.056 ;
    END
  END o_data[166]
  PIN o_data[167]
    DIRECTION OUTPUT ;
    USE SIGNAL ;
    PORT
      LAYER M4 ;
        RECT  103.596 82.464 103.68 82.488 ;
    END
  END o_data[167]
  PIN o_data[168]
    DIRECTION OUTPUT ;
    USE SIGNAL ;
    PORT
      LAYER M4 ;
        RECT  103.596 82.896 103.68 82.92 ;
    END
  END o_data[168]
  PIN o_data[169]
    DIRECTION OUTPUT ;
    USE SIGNAL ;
    PORT
      LAYER M4 ;
        RECT  103.596 83.328 103.68 83.352 ;
    END
  END o_data[169]
  PIN o_data[16]
    DIRECTION OUTPUT ;
    USE SIGNAL ;
    PORT
      LAYER M4 ;
        RECT  103.596 17.232 103.68 17.256 ;
    END
  END o_data[16]
  PIN o_data[170]
    DIRECTION OUTPUT ;
    USE SIGNAL ;
    PORT
      LAYER M4 ;
        RECT  103.596 83.76 103.68 83.784 ;
    END
  END o_data[170]
  PIN o_data[171]
    DIRECTION OUTPUT ;
    USE SIGNAL ;
    PORT
      LAYER M4 ;
        RECT  103.596 84.192 103.68 84.216 ;
    END
  END o_data[171]
  PIN o_data[172]
    DIRECTION OUTPUT ;
    USE SIGNAL ;
    PORT
      LAYER M4 ;
        RECT  103.596 84.624 103.68 84.648 ;
    END
  END o_data[172]
  PIN o_data[173]
    DIRECTION OUTPUT ;
    USE SIGNAL ;
    PORT
      LAYER M4 ;
        RECT  103.596 85.056 103.68 85.08 ;
    END
  END o_data[173]
  PIN o_data[174]
    DIRECTION OUTPUT ;
    USE SIGNAL ;
    PORT
      LAYER M4 ;
        RECT  103.596 85.488 103.68 85.512 ;
    END
  END o_data[174]
  PIN o_data[175]
    DIRECTION OUTPUT ;
    USE SIGNAL ;
    PORT
      LAYER M4 ;
        RECT  103.596 85.92 103.68 85.944 ;
    END
  END o_data[175]
  PIN o_data[176]
    DIRECTION OUTPUT ;
    USE SIGNAL ;
    PORT
      LAYER M4 ;
        RECT  103.596 86.352 103.68 86.376 ;
    END
  END o_data[176]
  PIN o_data[177]
    DIRECTION OUTPUT ;
    USE SIGNAL ;
    PORT
      LAYER M4 ;
        RECT  103.596 86.784 103.68 86.808 ;
    END
  END o_data[177]
  PIN o_data[178]
    DIRECTION OUTPUT ;
    USE SIGNAL ;
    PORT
      LAYER M4 ;
        RECT  103.596 87.216 103.68 87.24 ;
    END
  END o_data[178]
  PIN o_data[179]
    DIRECTION OUTPUT ;
    USE SIGNAL ;
    PORT
      LAYER M4 ;
        RECT  103.596 87.648 103.68 87.672 ;
    END
  END o_data[179]
  PIN o_data[17]
    DIRECTION OUTPUT ;
    USE SIGNAL ;
    PORT
      LAYER M4 ;
        RECT  103.596 17.664 103.68 17.688 ;
    END
  END o_data[17]
  PIN o_data[180]
    DIRECTION OUTPUT ;
    USE SIGNAL ;
    PORT
      LAYER M4 ;
        RECT  103.596 88.08 103.68 88.104 ;
    END
  END o_data[180]
  PIN o_data[181]
    DIRECTION OUTPUT ;
    USE SIGNAL ;
    PORT
      LAYER M4 ;
        RECT  103.596 88.512 103.68 88.536 ;
    END
  END o_data[181]
  PIN o_data[182]
    DIRECTION OUTPUT ;
    USE SIGNAL ;
    PORT
      LAYER M4 ;
        RECT  103.596 88.944 103.68 88.968 ;
    END
  END o_data[182]
  PIN o_data[183]
    DIRECTION OUTPUT ;
    USE SIGNAL ;
    PORT
      LAYER M4 ;
        RECT  103.596 89.376 103.68 89.4 ;
    END
  END o_data[183]
  PIN o_data[184]
    DIRECTION OUTPUT ;
    USE SIGNAL ;
    PORT
      LAYER M4 ;
        RECT  103.596 89.808 103.68 89.832 ;
    END
  END o_data[184]
  PIN o_data[185]
    DIRECTION OUTPUT ;
    USE SIGNAL ;
    PORT
      LAYER M4 ;
        RECT  103.596 90.24 103.68 90.264 ;
    END
  END o_data[185]
  PIN o_data[186]
    DIRECTION OUTPUT ;
    USE SIGNAL ;
    PORT
      LAYER M4 ;
        RECT  103.596 90.672 103.68 90.696 ;
    END
  END o_data[186]
  PIN o_data[187]
    DIRECTION OUTPUT ;
    USE SIGNAL ;
    PORT
      LAYER M4 ;
        RECT  103.596 91.104 103.68 91.128 ;
    END
  END o_data[187]
  PIN o_data[188]
    DIRECTION OUTPUT ;
    USE SIGNAL ;
    PORT
      LAYER M4 ;
        RECT  103.596 91.536 103.68 91.56 ;
    END
  END o_data[188]
  PIN o_data[189]
    DIRECTION OUTPUT ;
    USE SIGNAL ;
    PORT
      LAYER M4 ;
        RECT  103.596 91.968 103.68 91.992 ;
    END
  END o_data[189]
  PIN o_data[18]
    DIRECTION OUTPUT ;
    USE SIGNAL ;
    PORT
      LAYER M4 ;
        RECT  103.596 18.096 103.68 18.12 ;
    END
  END o_data[18]
  PIN o_data[190]
    DIRECTION OUTPUT ;
    USE SIGNAL ;
    PORT
      LAYER M4 ;
        RECT  103.596 92.4 103.68 92.424 ;
    END
  END o_data[190]
  PIN o_data[191]
    DIRECTION OUTPUT ;
    USE SIGNAL ;
    PORT
      LAYER M4 ;
        RECT  103.596 92.832 103.68 92.856 ;
    END
  END o_data[191]
  PIN o_data[192]
    DIRECTION OUTPUT ;
    USE SIGNAL ;
    PORT
      LAYER M4 ;
        RECT  103.596 93.264 103.68 93.288 ;
    END
  END o_data[192]
  PIN o_data[193]
    DIRECTION OUTPUT ;
    USE SIGNAL ;
    PORT
      LAYER M4 ;
        RECT  103.596 93.696 103.68 93.72 ;
    END
  END o_data[193]
  PIN o_data[194]
    DIRECTION OUTPUT ;
    USE SIGNAL ;
    PORT
      LAYER M4 ;
        RECT  103.596 94.128 103.68 94.152 ;
    END
  END o_data[194]
  PIN o_data[195]
    DIRECTION OUTPUT ;
    USE SIGNAL ;
    PORT
      LAYER M4 ;
        RECT  103.596 94.56 103.68 94.584 ;
    END
  END o_data[195]
  PIN o_data[196]
    DIRECTION OUTPUT ;
    USE SIGNAL ;
    PORT
      LAYER M4 ;
        RECT  103.596 94.992 103.68 95.016 ;
    END
  END o_data[196]
  PIN o_data[197]
    DIRECTION OUTPUT ;
    USE SIGNAL ;
    PORT
      LAYER M4 ;
        RECT  103.596 95.424 103.68 95.448 ;
    END
  END o_data[197]
  PIN o_data[198]
    DIRECTION OUTPUT ;
    USE SIGNAL ;
    PORT
      LAYER M4 ;
        RECT  103.596 95.856 103.68 95.88 ;
    END
  END o_data[198]
  PIN o_data[199]
    DIRECTION OUTPUT ;
    USE SIGNAL ;
    PORT
      LAYER M4 ;
        RECT  103.596 96.288 103.68 96.312 ;
    END
  END o_data[199]
  PIN o_data[19]
    DIRECTION OUTPUT ;
    USE SIGNAL ;
    PORT
      LAYER M4 ;
        RECT  103.596 18.528 103.68 18.552 ;
    END
  END o_data[19]
  PIN o_data[1]
    DIRECTION OUTPUT ;
    USE SIGNAL ;
    PORT
      LAYER M4 ;
        RECT  103.596 10.752 103.68 10.776 ;
    END
  END o_data[1]
  PIN o_data[200]
    DIRECTION OUTPUT ;
    USE SIGNAL ;
    PORT
      LAYER M4 ;
        RECT  103.596 96.72 103.68 96.744 ;
    END
  END o_data[200]
  PIN o_data[201]
    DIRECTION OUTPUT ;
    USE SIGNAL ;
    PORT
      LAYER M4 ;
        RECT  103.596 97.152 103.68 97.176 ;
    END
  END o_data[201]
  PIN o_data[202]
    DIRECTION OUTPUT ;
    USE SIGNAL ;
    PORT
      LAYER M4 ;
        RECT  103.596 97.584 103.68 97.608 ;
    END
  END o_data[202]
  PIN o_data[203]
    DIRECTION OUTPUT ;
    USE SIGNAL ;
    PORT
      LAYER M4 ;
        RECT  103.596 98.016 103.68 98.04 ;
    END
  END o_data[203]
  PIN o_data[204]
    DIRECTION OUTPUT ;
    USE SIGNAL ;
    PORT
      LAYER M4 ;
        RECT  103.596 98.448 103.68 98.472 ;
    END
  END o_data[204]
  PIN o_data[205]
    DIRECTION OUTPUT ;
    USE SIGNAL ;
    PORT
      LAYER M4 ;
        RECT  103.596 98.88 103.68 98.904 ;
    END
  END o_data[205]
  PIN o_data[206]
    DIRECTION OUTPUT ;
    USE SIGNAL ;
    PORT
      LAYER M4 ;
        RECT  103.596 99.312 103.68 99.336 ;
    END
  END o_data[206]
  PIN o_data[207]
    DIRECTION OUTPUT ;
    USE SIGNAL ;
    PORT
      LAYER M4 ;
        RECT  103.596 99.744 103.68 99.768 ;
    END
  END o_data[207]
  PIN o_data[208]
    DIRECTION OUTPUT ;
    USE SIGNAL ;
    PORT
      LAYER M4 ;
        RECT  103.596 100.176 103.68 100.2 ;
    END
  END o_data[208]
  PIN o_data[209]
    DIRECTION OUTPUT ;
    USE SIGNAL ;
    PORT
      LAYER M4 ;
        RECT  103.596 100.608 103.68 100.632 ;
    END
  END o_data[209]
  PIN o_data[20]
    DIRECTION OUTPUT ;
    USE SIGNAL ;
    PORT
      LAYER M4 ;
        RECT  103.596 18.96 103.68 18.984 ;
    END
  END o_data[20]
  PIN o_data[210]
    DIRECTION OUTPUT ;
    USE SIGNAL ;
    PORT
      LAYER M4 ;
        RECT  103.596 101.04 103.68 101.064 ;
    END
  END o_data[210]
  PIN o_data[211]
    DIRECTION OUTPUT ;
    USE SIGNAL ;
    PORT
      LAYER M4 ;
        RECT  103.596 101.472 103.68 101.496 ;
    END
  END o_data[211]
  PIN o_data[212]
    DIRECTION OUTPUT ;
    USE SIGNAL ;
    PORT
      LAYER M4 ;
        RECT  103.596 101.904 103.68 101.928 ;
    END
  END o_data[212]
  PIN o_data[213]
    DIRECTION OUTPUT ;
    USE SIGNAL ;
    PORT
      LAYER M4 ;
        RECT  103.596 102.336 103.68 102.36 ;
    END
  END o_data[213]
  PIN o_data[214]
    DIRECTION OUTPUT ;
    USE SIGNAL ;
    PORT
      LAYER M4 ;
        RECT  103.596 102.768 103.68 102.792 ;
    END
  END o_data[214]
  PIN o_data[215]
    DIRECTION OUTPUT ;
    USE SIGNAL ;
    PORT
      LAYER M4 ;
        RECT  103.596 103.2 103.68 103.224 ;
    END
  END o_data[215]
  PIN o_data[216]
    DIRECTION OUTPUT ;
    USE SIGNAL ;
    PORT
      LAYER M4 ;
        RECT  103.596 103.632 103.68 103.656 ;
    END
  END o_data[216]
  PIN o_data[217]
    DIRECTION OUTPUT ;
    USE SIGNAL ;
    PORT
      LAYER M4 ;
        RECT  103.596 104.064 103.68 104.088 ;
    END
  END o_data[217]
  PIN o_data[218]
    DIRECTION OUTPUT ;
    USE SIGNAL ;
    PORT
      LAYER M4 ;
        RECT  103.596 104.496 103.68 104.52 ;
    END
  END o_data[218]
  PIN o_data[219]
    DIRECTION OUTPUT ;
    USE SIGNAL ;
    PORT
      LAYER M4 ;
        RECT  103.596 104.928 103.68 104.952 ;
    END
  END o_data[219]
  PIN o_data[21]
    DIRECTION OUTPUT ;
    USE SIGNAL ;
    PORT
      LAYER M4 ;
        RECT  103.596 19.392 103.68 19.416 ;
    END
  END o_data[21]
  PIN o_data[220]
    DIRECTION OUTPUT ;
    USE SIGNAL ;
    PORT
      LAYER M4 ;
        RECT  103.596 105.36 103.68 105.384 ;
    END
  END o_data[220]
  PIN o_data[221]
    DIRECTION OUTPUT ;
    USE SIGNAL ;
    PORT
      LAYER M4 ;
        RECT  103.596 105.792 103.68 105.816 ;
    END
  END o_data[221]
  PIN o_data[222]
    DIRECTION OUTPUT ;
    USE SIGNAL ;
    PORT
      LAYER M4 ;
        RECT  103.596 106.224 103.68 106.248 ;
    END
  END o_data[222]
  PIN o_data[223]
    DIRECTION OUTPUT ;
    USE SIGNAL ;
    PORT
      LAYER M4 ;
        RECT  103.596 106.656 103.68 106.68 ;
    END
  END o_data[223]
  PIN o_data[224]
    DIRECTION OUTPUT ;
    USE SIGNAL ;
    PORT
      LAYER M4 ;
        RECT  103.596 107.088 103.68 107.112 ;
    END
  END o_data[224]
  PIN o_data[225]
    DIRECTION OUTPUT ;
    USE SIGNAL ;
    PORT
      LAYER M4 ;
        RECT  103.596 107.52 103.68 107.544 ;
    END
  END o_data[225]
  PIN o_data[226]
    DIRECTION OUTPUT ;
    USE SIGNAL ;
    PORT
      LAYER M4 ;
        RECT  103.596 107.952 103.68 107.976 ;
    END
  END o_data[226]
  PIN o_data[227]
    DIRECTION OUTPUT ;
    USE SIGNAL ;
    PORT
      LAYER M4 ;
        RECT  103.596 108.384 103.68 108.408 ;
    END
  END o_data[227]
  PIN o_data[228]
    DIRECTION OUTPUT ;
    USE SIGNAL ;
    PORT
      LAYER M4 ;
        RECT  103.596 108.816 103.68 108.84 ;
    END
  END o_data[228]
  PIN o_data[229]
    DIRECTION OUTPUT ;
    USE SIGNAL ;
    PORT
      LAYER M4 ;
        RECT  103.596 109.248 103.68 109.272 ;
    END
  END o_data[229]
  PIN o_data[22]
    DIRECTION OUTPUT ;
    USE SIGNAL ;
    PORT
      LAYER M4 ;
        RECT  103.596 19.824 103.68 19.848 ;
    END
  END o_data[22]
  PIN o_data[230]
    DIRECTION OUTPUT ;
    USE SIGNAL ;
    PORT
      LAYER M4 ;
        RECT  103.596 109.68 103.68 109.704 ;
    END
  END o_data[230]
  PIN o_data[231]
    DIRECTION OUTPUT ;
    USE SIGNAL ;
    PORT
      LAYER M4 ;
        RECT  103.596 110.112 103.68 110.136 ;
    END
  END o_data[231]
  PIN o_data[232]
    DIRECTION OUTPUT ;
    USE SIGNAL ;
    PORT
      LAYER M4 ;
        RECT  103.596 110.544 103.68 110.568 ;
    END
  END o_data[232]
  PIN o_data[233]
    DIRECTION OUTPUT ;
    USE SIGNAL ;
    PORT
      LAYER M4 ;
        RECT  103.596 110.976 103.68 111 ;
    END
  END o_data[233]
  PIN o_data[234]
    DIRECTION OUTPUT ;
    USE SIGNAL ;
    PORT
      LAYER M4 ;
        RECT  103.596 111.408 103.68 111.432 ;
    END
  END o_data[234]
  PIN o_data[235]
    DIRECTION OUTPUT ;
    USE SIGNAL ;
    PORT
      LAYER M4 ;
        RECT  103.596 111.84 103.68 111.864 ;
    END
  END o_data[235]
  PIN o_data[236]
    DIRECTION OUTPUT ;
    USE SIGNAL ;
    PORT
      LAYER M4 ;
        RECT  103.596 112.272 103.68 112.296 ;
    END
  END o_data[236]
  PIN o_data[237]
    DIRECTION OUTPUT ;
    USE SIGNAL ;
    PORT
      LAYER M4 ;
        RECT  103.596 112.704 103.68 112.728 ;
    END
  END o_data[237]
  PIN o_data[238]
    DIRECTION OUTPUT ;
    USE SIGNAL ;
    PORT
      LAYER M4 ;
        RECT  103.596 113.136 103.68 113.16 ;
    END
  END o_data[238]
  PIN o_data[239]
    DIRECTION OUTPUT ;
    USE SIGNAL ;
    PORT
      LAYER M4 ;
        RECT  103.596 113.568 103.68 113.592 ;
    END
  END o_data[239]
  PIN o_data[23]
    DIRECTION OUTPUT ;
    USE SIGNAL ;
    PORT
      LAYER M4 ;
        RECT  103.596 20.256 103.68 20.28 ;
    END
  END o_data[23]
  PIN o_data[240]
    DIRECTION OUTPUT ;
    USE SIGNAL ;
    PORT
      LAYER M4 ;
        RECT  103.596 114 103.68 114.024 ;
    END
  END o_data[240]
  PIN o_data[241]
    DIRECTION OUTPUT ;
    USE SIGNAL ;
    PORT
      LAYER M4 ;
        RECT  103.596 114.432 103.68 114.456 ;
    END
  END o_data[241]
  PIN o_data[242]
    DIRECTION OUTPUT ;
    USE SIGNAL ;
    PORT
      LAYER M4 ;
        RECT  103.596 114.864 103.68 114.888 ;
    END
  END o_data[242]
  PIN o_data[243]
    DIRECTION OUTPUT ;
    USE SIGNAL ;
    PORT
      LAYER M4 ;
        RECT  103.596 115.296 103.68 115.32 ;
    END
  END o_data[243]
  PIN o_data[244]
    DIRECTION OUTPUT ;
    USE SIGNAL ;
    PORT
      LAYER M4 ;
        RECT  103.596 115.728 103.68 115.752 ;
    END
  END o_data[244]
  PIN o_data[245]
    DIRECTION OUTPUT ;
    USE SIGNAL ;
    PORT
      LAYER M4 ;
        RECT  103.596 116.16 103.68 116.184 ;
    END
  END o_data[245]
  PIN o_data[246]
    DIRECTION OUTPUT ;
    USE SIGNAL ;
    PORT
      LAYER M4 ;
        RECT  103.596 116.592 103.68 116.616 ;
    END
  END o_data[246]
  PIN o_data[247]
    DIRECTION OUTPUT ;
    USE SIGNAL ;
    PORT
      LAYER M4 ;
        RECT  103.596 117.024 103.68 117.048 ;
    END
  END o_data[247]
  PIN o_data[248]
    DIRECTION OUTPUT ;
    USE SIGNAL ;
    PORT
      LAYER M4 ;
        RECT  103.596 117.456 103.68 117.48 ;
    END
  END o_data[248]
  PIN o_data[249]
    DIRECTION OUTPUT ;
    USE SIGNAL ;
    PORT
      LAYER M4 ;
        RECT  103.596 117.888 103.68 117.912 ;
    END
  END o_data[249]
  PIN o_data[24]
    DIRECTION OUTPUT ;
    USE SIGNAL ;
    PORT
      LAYER M4 ;
        RECT  103.596 20.688 103.68 20.712 ;
    END
  END o_data[24]
  PIN o_data[250]
    DIRECTION OUTPUT ;
    USE SIGNAL ;
    PORT
      LAYER M4 ;
        RECT  103.596 118.32 103.68 118.344 ;
    END
  END o_data[250]
  PIN o_data[251]
    DIRECTION OUTPUT ;
    USE SIGNAL ;
    PORT
      LAYER M4 ;
        RECT  103.596 118.752 103.68 118.776 ;
    END
  END o_data[251]
  PIN o_data[252]
    DIRECTION OUTPUT ;
    USE SIGNAL ;
    PORT
      LAYER M4 ;
        RECT  103.596 119.184 103.68 119.208 ;
    END
  END o_data[252]
  PIN o_data[253]
    DIRECTION OUTPUT ;
    USE SIGNAL ;
    PORT
      LAYER M4 ;
        RECT  103.596 119.616 103.68 119.64 ;
    END
  END o_data[253]
  PIN o_data[254]
    DIRECTION OUTPUT ;
    USE SIGNAL ;
    PORT
      LAYER M4 ;
        RECT  103.596 120.048 103.68 120.072 ;
    END
  END o_data[254]
  PIN o_data[255]
    DIRECTION OUTPUT ;
    USE SIGNAL ;
    PORT
      LAYER M4 ;
        RECT  103.596 120.48 103.68 120.504 ;
    END
  END o_data[255]
  PIN o_data[25]
    DIRECTION OUTPUT ;
    USE SIGNAL ;
    PORT
      LAYER M4 ;
        RECT  103.596 21.12 103.68 21.144 ;
    END
  END o_data[25]
  PIN o_data[26]
    DIRECTION OUTPUT ;
    USE SIGNAL ;
    PORT
      LAYER M4 ;
        RECT  103.596 21.552 103.68 21.576 ;
    END
  END o_data[26]
  PIN o_data[27]
    DIRECTION OUTPUT ;
    USE SIGNAL ;
    PORT
      LAYER M4 ;
        RECT  103.596 21.984 103.68 22.008 ;
    END
  END o_data[27]
  PIN o_data[28]
    DIRECTION OUTPUT ;
    USE SIGNAL ;
    PORT
      LAYER M4 ;
        RECT  103.596 22.416 103.68 22.44 ;
    END
  END o_data[28]
  PIN o_data[29]
    DIRECTION OUTPUT ;
    USE SIGNAL ;
    PORT
      LAYER M4 ;
        RECT  103.596 22.848 103.68 22.872 ;
    END
  END o_data[29]
  PIN o_data[2]
    DIRECTION OUTPUT ;
    USE SIGNAL ;
    PORT
      LAYER M4 ;
        RECT  103.596 11.184 103.68 11.208 ;
    END
  END o_data[2]
  PIN o_data[30]
    DIRECTION OUTPUT ;
    USE SIGNAL ;
    PORT
      LAYER M4 ;
        RECT  103.596 23.28 103.68 23.304 ;
    END
  END o_data[30]
  PIN o_data[31]
    DIRECTION OUTPUT ;
    USE SIGNAL ;
    PORT
      LAYER M4 ;
        RECT  103.596 23.712 103.68 23.736 ;
    END
  END o_data[31]
  PIN o_data[32]
    DIRECTION OUTPUT ;
    USE SIGNAL ;
    PORT
      LAYER M4 ;
        RECT  103.596 24.144 103.68 24.168 ;
    END
  END o_data[32]
  PIN o_data[33]
    DIRECTION OUTPUT ;
    USE SIGNAL ;
    PORT
      LAYER M4 ;
        RECT  103.596 24.576 103.68 24.6 ;
    END
  END o_data[33]
  PIN o_data[34]
    DIRECTION OUTPUT ;
    USE SIGNAL ;
    PORT
      LAYER M4 ;
        RECT  103.596 25.008 103.68 25.032 ;
    END
  END o_data[34]
  PIN o_data[35]
    DIRECTION OUTPUT ;
    USE SIGNAL ;
    PORT
      LAYER M4 ;
        RECT  103.596 25.44 103.68 25.464 ;
    END
  END o_data[35]
  PIN o_data[36]
    DIRECTION OUTPUT ;
    USE SIGNAL ;
    PORT
      LAYER M4 ;
        RECT  103.596 25.872 103.68 25.896 ;
    END
  END o_data[36]
  PIN o_data[37]
    DIRECTION OUTPUT ;
    USE SIGNAL ;
    PORT
      LAYER M4 ;
        RECT  103.596 26.304 103.68 26.328 ;
    END
  END o_data[37]
  PIN o_data[38]
    DIRECTION OUTPUT ;
    USE SIGNAL ;
    PORT
      LAYER M4 ;
        RECT  103.596 26.736 103.68 26.76 ;
    END
  END o_data[38]
  PIN o_data[39]
    DIRECTION OUTPUT ;
    USE SIGNAL ;
    PORT
      LAYER M4 ;
        RECT  103.596 27.168 103.68 27.192 ;
    END
  END o_data[39]
  PIN o_data[3]
    DIRECTION OUTPUT ;
    USE SIGNAL ;
    PORT
      LAYER M4 ;
        RECT  103.596 11.616 103.68 11.64 ;
    END
  END o_data[3]
  PIN o_data[40]
    DIRECTION OUTPUT ;
    USE SIGNAL ;
    PORT
      LAYER M4 ;
        RECT  103.596 27.6 103.68 27.624 ;
    END
  END o_data[40]
  PIN o_data[41]
    DIRECTION OUTPUT ;
    USE SIGNAL ;
    PORT
      LAYER M4 ;
        RECT  103.596 28.032 103.68 28.056 ;
    END
  END o_data[41]
  PIN o_data[42]
    DIRECTION OUTPUT ;
    USE SIGNAL ;
    PORT
      LAYER M4 ;
        RECT  103.596 28.464 103.68 28.488 ;
    END
  END o_data[42]
  PIN o_data[43]
    DIRECTION OUTPUT ;
    USE SIGNAL ;
    PORT
      LAYER M4 ;
        RECT  103.596 28.896 103.68 28.92 ;
    END
  END o_data[43]
  PIN o_data[44]
    DIRECTION OUTPUT ;
    USE SIGNAL ;
    PORT
      LAYER M4 ;
        RECT  103.596 29.328 103.68 29.352 ;
    END
  END o_data[44]
  PIN o_data[45]
    DIRECTION OUTPUT ;
    USE SIGNAL ;
    PORT
      LAYER M4 ;
        RECT  103.596 29.76 103.68 29.784 ;
    END
  END o_data[45]
  PIN o_data[46]
    DIRECTION OUTPUT ;
    USE SIGNAL ;
    PORT
      LAYER M4 ;
        RECT  103.596 30.192 103.68 30.216 ;
    END
  END o_data[46]
  PIN o_data[47]
    DIRECTION OUTPUT ;
    USE SIGNAL ;
    PORT
      LAYER M4 ;
        RECT  103.596 30.624 103.68 30.648 ;
    END
  END o_data[47]
  PIN o_data[48]
    DIRECTION OUTPUT ;
    USE SIGNAL ;
    PORT
      LAYER M4 ;
        RECT  103.596 31.056 103.68 31.08 ;
    END
  END o_data[48]
  PIN o_data[49]
    DIRECTION OUTPUT ;
    USE SIGNAL ;
    PORT
      LAYER M4 ;
        RECT  103.596 31.488 103.68 31.512 ;
    END
  END o_data[49]
  PIN o_data[4]
    DIRECTION OUTPUT ;
    USE SIGNAL ;
    PORT
      LAYER M4 ;
        RECT  103.596 12.048 103.68 12.072 ;
    END
  END o_data[4]
  PIN o_data[50]
    DIRECTION OUTPUT ;
    USE SIGNAL ;
    PORT
      LAYER M4 ;
        RECT  103.596 31.92 103.68 31.944 ;
    END
  END o_data[50]
  PIN o_data[51]
    DIRECTION OUTPUT ;
    USE SIGNAL ;
    PORT
      LAYER M4 ;
        RECT  103.596 32.352 103.68 32.376 ;
    END
  END o_data[51]
  PIN o_data[52]
    DIRECTION OUTPUT ;
    USE SIGNAL ;
    PORT
      LAYER M4 ;
        RECT  103.596 32.784 103.68 32.808 ;
    END
  END o_data[52]
  PIN o_data[53]
    DIRECTION OUTPUT ;
    USE SIGNAL ;
    PORT
      LAYER M4 ;
        RECT  103.596 33.216 103.68 33.24 ;
    END
  END o_data[53]
  PIN o_data[54]
    DIRECTION OUTPUT ;
    USE SIGNAL ;
    PORT
      LAYER M4 ;
        RECT  103.596 33.648 103.68 33.672 ;
    END
  END o_data[54]
  PIN o_data[55]
    DIRECTION OUTPUT ;
    USE SIGNAL ;
    PORT
      LAYER M4 ;
        RECT  103.596 34.08 103.68 34.104 ;
    END
  END o_data[55]
  PIN o_data[56]
    DIRECTION OUTPUT ;
    USE SIGNAL ;
    PORT
      LAYER M4 ;
        RECT  103.596 34.512 103.68 34.536 ;
    END
  END o_data[56]
  PIN o_data[57]
    DIRECTION OUTPUT ;
    USE SIGNAL ;
    PORT
      LAYER M4 ;
        RECT  103.596 34.944 103.68 34.968 ;
    END
  END o_data[57]
  PIN o_data[58]
    DIRECTION OUTPUT ;
    USE SIGNAL ;
    PORT
      LAYER M4 ;
        RECT  103.596 35.376 103.68 35.4 ;
    END
  END o_data[58]
  PIN o_data[59]
    DIRECTION OUTPUT ;
    USE SIGNAL ;
    PORT
      LAYER M4 ;
        RECT  103.596 35.808 103.68 35.832 ;
    END
  END o_data[59]
  PIN o_data[5]
    DIRECTION OUTPUT ;
    USE SIGNAL ;
    PORT
      LAYER M4 ;
        RECT  103.596 12.48 103.68 12.504 ;
    END
  END o_data[5]
  PIN o_data[60]
    DIRECTION OUTPUT ;
    USE SIGNAL ;
    PORT
      LAYER M4 ;
        RECT  103.596 36.24 103.68 36.264 ;
    END
  END o_data[60]
  PIN o_data[61]
    DIRECTION OUTPUT ;
    USE SIGNAL ;
    PORT
      LAYER M4 ;
        RECT  103.596 36.672 103.68 36.696 ;
    END
  END o_data[61]
  PIN o_data[62]
    DIRECTION OUTPUT ;
    USE SIGNAL ;
    PORT
      LAYER M4 ;
        RECT  103.596 37.104 103.68 37.128 ;
    END
  END o_data[62]
  PIN o_data[63]
    DIRECTION OUTPUT ;
    USE SIGNAL ;
    PORT
      LAYER M4 ;
        RECT  103.596 37.536 103.68 37.56 ;
    END
  END o_data[63]
  PIN o_data[64]
    DIRECTION OUTPUT ;
    USE SIGNAL ;
    PORT
      LAYER M4 ;
        RECT  103.596 37.968 103.68 37.992 ;
    END
  END o_data[64]
  PIN o_data[65]
    DIRECTION OUTPUT ;
    USE SIGNAL ;
    PORT
      LAYER M4 ;
        RECT  103.596 38.4 103.68 38.424 ;
    END
  END o_data[65]
  PIN o_data[66]
    DIRECTION OUTPUT ;
    USE SIGNAL ;
    PORT
      LAYER M4 ;
        RECT  103.596 38.832 103.68 38.856 ;
    END
  END o_data[66]
  PIN o_data[67]
    DIRECTION OUTPUT ;
    USE SIGNAL ;
    PORT
      LAYER M4 ;
        RECT  103.596 39.264 103.68 39.288 ;
    END
  END o_data[67]
  PIN o_data[68]
    DIRECTION OUTPUT ;
    USE SIGNAL ;
    PORT
      LAYER M4 ;
        RECT  103.596 39.696 103.68 39.72 ;
    END
  END o_data[68]
  PIN o_data[69]
    DIRECTION OUTPUT ;
    USE SIGNAL ;
    PORT
      LAYER M4 ;
        RECT  103.596 40.128 103.68 40.152 ;
    END
  END o_data[69]
  PIN o_data[6]
    DIRECTION OUTPUT ;
    USE SIGNAL ;
    PORT
      LAYER M4 ;
        RECT  103.596 12.912 103.68 12.936 ;
    END
  END o_data[6]
  PIN o_data[70]
    DIRECTION OUTPUT ;
    USE SIGNAL ;
    PORT
      LAYER M4 ;
        RECT  103.596 40.56 103.68 40.584 ;
    END
  END o_data[70]
  PIN o_data[71]
    DIRECTION OUTPUT ;
    USE SIGNAL ;
    PORT
      LAYER M4 ;
        RECT  103.596 40.992 103.68 41.016 ;
    END
  END o_data[71]
  PIN o_data[72]
    DIRECTION OUTPUT ;
    USE SIGNAL ;
    PORT
      LAYER M4 ;
        RECT  103.596 41.424 103.68 41.448 ;
    END
  END o_data[72]
  PIN o_data[73]
    DIRECTION OUTPUT ;
    USE SIGNAL ;
    PORT
      LAYER M4 ;
        RECT  103.596 41.856 103.68 41.88 ;
    END
  END o_data[73]
  PIN o_data[74]
    DIRECTION OUTPUT ;
    USE SIGNAL ;
    PORT
      LAYER M4 ;
        RECT  103.596 42.288 103.68 42.312 ;
    END
  END o_data[74]
  PIN o_data[75]
    DIRECTION OUTPUT ;
    USE SIGNAL ;
    PORT
      LAYER M4 ;
        RECT  103.596 42.72 103.68 42.744 ;
    END
  END o_data[75]
  PIN o_data[76]
    DIRECTION OUTPUT ;
    USE SIGNAL ;
    PORT
      LAYER M4 ;
        RECT  103.596 43.152 103.68 43.176 ;
    END
  END o_data[76]
  PIN o_data[77]
    DIRECTION OUTPUT ;
    USE SIGNAL ;
    PORT
      LAYER M4 ;
        RECT  103.596 43.584 103.68 43.608 ;
    END
  END o_data[77]
  PIN o_data[78]
    DIRECTION OUTPUT ;
    USE SIGNAL ;
    PORT
      LAYER M4 ;
        RECT  103.596 44.016 103.68 44.04 ;
    END
  END o_data[78]
  PIN o_data[79]
    DIRECTION OUTPUT ;
    USE SIGNAL ;
    PORT
      LAYER M4 ;
        RECT  103.596 44.448 103.68 44.472 ;
    END
  END o_data[79]
  PIN o_data[7]
    DIRECTION OUTPUT ;
    USE SIGNAL ;
    PORT
      LAYER M4 ;
        RECT  103.596 13.344 103.68 13.368 ;
    END
  END o_data[7]
  PIN o_data[80]
    DIRECTION OUTPUT ;
    USE SIGNAL ;
    PORT
      LAYER M4 ;
        RECT  103.596 44.88 103.68 44.904 ;
    END
  END o_data[80]
  PIN o_data[81]
    DIRECTION OUTPUT ;
    USE SIGNAL ;
    PORT
      LAYER M4 ;
        RECT  103.596 45.312 103.68 45.336 ;
    END
  END o_data[81]
  PIN o_data[82]
    DIRECTION OUTPUT ;
    USE SIGNAL ;
    PORT
      LAYER M4 ;
        RECT  103.596 45.744 103.68 45.768 ;
    END
  END o_data[82]
  PIN o_data[83]
    DIRECTION OUTPUT ;
    USE SIGNAL ;
    PORT
      LAYER M4 ;
        RECT  103.596 46.176 103.68 46.2 ;
    END
  END o_data[83]
  PIN o_data[84]
    DIRECTION OUTPUT ;
    USE SIGNAL ;
    PORT
      LAYER M4 ;
        RECT  103.596 46.608 103.68 46.632 ;
    END
  END o_data[84]
  PIN o_data[85]
    DIRECTION OUTPUT ;
    USE SIGNAL ;
    PORT
      LAYER M4 ;
        RECT  103.596 47.04 103.68 47.064 ;
    END
  END o_data[85]
  PIN o_data[86]
    DIRECTION OUTPUT ;
    USE SIGNAL ;
    PORT
      LAYER M4 ;
        RECT  103.596 47.472 103.68 47.496 ;
    END
  END o_data[86]
  PIN o_data[87]
    DIRECTION OUTPUT ;
    USE SIGNAL ;
    PORT
      LAYER M4 ;
        RECT  103.596 47.904 103.68 47.928 ;
    END
  END o_data[87]
  PIN o_data[88]
    DIRECTION OUTPUT ;
    USE SIGNAL ;
    PORT
      LAYER M4 ;
        RECT  103.596 48.336 103.68 48.36 ;
    END
  END o_data[88]
  PIN o_data[89]
    DIRECTION OUTPUT ;
    USE SIGNAL ;
    PORT
      LAYER M4 ;
        RECT  103.596 48.768 103.68 48.792 ;
    END
  END o_data[89]
  PIN o_data[8]
    DIRECTION OUTPUT ;
    USE SIGNAL ;
    PORT
      LAYER M4 ;
        RECT  103.596 13.776 103.68 13.8 ;
    END
  END o_data[8]
  PIN o_data[90]
    DIRECTION OUTPUT ;
    USE SIGNAL ;
    PORT
      LAYER M4 ;
        RECT  103.596 49.2 103.68 49.224 ;
    END
  END o_data[90]
  PIN o_data[91]
    DIRECTION OUTPUT ;
    USE SIGNAL ;
    PORT
      LAYER M4 ;
        RECT  103.596 49.632 103.68 49.656 ;
    END
  END o_data[91]
  PIN o_data[92]
    DIRECTION OUTPUT ;
    USE SIGNAL ;
    PORT
      LAYER M4 ;
        RECT  103.596 50.064 103.68 50.088 ;
    END
  END o_data[92]
  PIN o_data[93]
    DIRECTION OUTPUT ;
    USE SIGNAL ;
    PORT
      LAYER M4 ;
        RECT  103.596 50.496 103.68 50.52 ;
    END
  END o_data[93]
  PIN o_data[94]
    DIRECTION OUTPUT ;
    USE SIGNAL ;
    PORT
      LAYER M4 ;
        RECT  103.596 50.928 103.68 50.952 ;
    END
  END o_data[94]
  PIN o_data[95]
    DIRECTION OUTPUT ;
    USE SIGNAL ;
    PORT
      LAYER M4 ;
        RECT  103.596 51.36 103.68 51.384 ;
    END
  END o_data[95]
  PIN o_data[96]
    DIRECTION OUTPUT ;
    USE SIGNAL ;
    PORT
      LAYER M4 ;
        RECT  103.596 51.792 103.68 51.816 ;
    END
  END o_data[96]
  PIN o_data[97]
    DIRECTION OUTPUT ;
    USE SIGNAL ;
    PORT
      LAYER M4 ;
        RECT  103.596 52.224 103.68 52.248 ;
    END
  END o_data[97]
  PIN o_data[98]
    DIRECTION OUTPUT ;
    USE SIGNAL ;
    PORT
      LAYER M4 ;
        RECT  103.596 52.656 103.68 52.68 ;
    END
  END o_data[98]
  PIN o_data[99]
    DIRECTION OUTPUT ;
    USE SIGNAL ;
    PORT
      LAYER M4 ;
        RECT  103.596 53.088 103.68 53.112 ;
    END
  END o_data[99]
  PIN o_data[9]
    DIRECTION OUTPUT ;
    USE SIGNAL ;
    PORT
      LAYER M4 ;
        RECT  103.596 14.208 103.68 14.232 ;
    END
  END o_data[9]
  PIN o_partial_valid[0]
    DIRECTION OUTPUT ;
    USE SIGNAL ;
    PORT
      LAYER M4 ;
        RECT  103.596 8.592 103.68 8.616 ;
    END
  END o_partial_valid[0]
  PIN o_partial_valid[1]
    DIRECTION OUTPUT ;
    USE SIGNAL ;
    PORT
      LAYER M4 ;
        RECT  103.596 9.024 103.68 9.048 ;
    END
  END o_partial_valid[1]
  PIN o_partial_valid[2]
    DIRECTION OUTPUT ;
    USE SIGNAL ;
    PORT
      LAYER M4 ;
        RECT  103.596 9.456 103.68 9.48 ;
    END
  END o_partial_valid[2]
  PIN o_partial_valid[3]
    DIRECTION OUTPUT ;
    USE SIGNAL ;
    PORT
      LAYER M4 ;
        RECT  103.596 9.888 103.68 9.912 ;
    END
  END o_partial_valid[3]
  PIN rst_n
    DIRECTION INPUT ;
    USE SIGNAL ;
    PORT
      LAYER M5 ;
        RECT  52.032 129.516 52.056 129.6 ;
    END
  END rst_n
  PIN VDD
    DIRECTION INOUT ;
    USE POWER ;
    PORT
      LAYER M5 ;
        RECT  99.792 2.151 99.912 127.449 ;
        RECT  94.392 2.151 94.512 127.449 ;
        RECT  88.992 2.151 89.112 127.449 ;
        RECT  83.592 2.151 83.712 127.449 ;
        RECT  78.192 2.151 78.312 127.449 ;
        RECT  72.792 2.151 72.912 127.449 ;
        RECT  67.392 2.151 67.512 127.449 ;
        RECT  61.992 2.151 62.112 127.449 ;
        RECT  56.592 2.151 56.712 127.449 ;
        RECT  51.192 2.151 51.312 127.449 ;
        RECT  45.792 2.151 45.912 127.449 ;
        RECT  40.392 2.151 40.512 127.449 ;
        RECT  34.992 2.151 35.112 127.449 ;
        RECT  29.592 2.151 29.712 127.449 ;
        RECT  24.192 2.151 24.312 127.449 ;
        RECT  18.792 2.151 18.912 127.449 ;
        RECT  13.392 2.151 13.512 127.449 ;
        RECT  7.992 2.151 8.112 127.449 ;
        RECT  2.592 2.151 2.712 127.449 ;
    END
  END VDD
  PIN VSS
    DIRECTION INOUT ;
    USE GROUND ;
    PORT
      LAYER M5 ;
        RECT  99.6 2.137 99.72 127.463 ;
        RECT  94.2 2.137 94.32 127.463 ;
        RECT  88.8 2.137 88.92 127.463 ;
        RECT  83.4 2.137 83.52 127.463 ;
        RECT  78 2.137 78.12 127.463 ;
        RECT  72.6 2.137 72.72 127.463 ;
        RECT  67.2 2.137 67.32 127.463 ;
        RECT  61.8 2.137 61.92 127.463 ;
        RECT  56.4 2.137 56.52 127.463 ;
        RECT  51 2.137 51.12 127.463 ;
        RECT  45.6 2.137 45.72 127.463 ;
        RECT  40.2 2.137 40.32 127.463 ;
        RECT  34.8 2.137 34.92 127.463 ;
        RECT  29.4 2.137 29.52 127.463 ;
        RECT  24 2.137 24.12 127.463 ;
        RECT  18.6 2.137 18.72 127.463 ;
        RECT  13.2 2.137 13.32 127.463 ;
        RECT  7.8 2.137 7.92 127.463 ;
        RECT  2.4 2.137 2.52 127.463 ;
    END
  END VSS
  # OT_OBS_CLOSED layer=M5 d_um=1.536 added=145
  OBS
    LAYER RVTN ;
     RECT  2.16 2.16 101.52 2.295 ;
     RECT  2.16 2.565 101.52 2.835 ;
     RECT  2.16 3.105 101.52 3.375 ;
     RECT  2.16 3.645 101.52 3.915 ;
     RECT  2.16 4.185 101.52 4.455 ;
     RECT  2.16 4.725 101.52 4.995 ;
     RECT  2.16 5.265 101.52 5.535 ;
     RECT  2.16 5.805 101.52 6.075 ;
     RECT  2.16 6.345 101.52 6.615 ;
     RECT  2.16 6.885 101.52 7.155 ;
     RECT  2.16 7.425 101.52 7.695 ;
     RECT  2.16 7.965 101.52 8.235 ;
     RECT  2.16 8.505 101.52 8.775 ;
     RECT  2.16 9.045 101.52 9.315 ;
     RECT  2.16 9.585 101.52 9.855 ;
     RECT  2.16 10.125 101.52 10.395 ;
     RECT  2.16 10.665 101.52 10.935 ;
     RECT  2.16 11.205 101.52 11.475 ;
     RECT  2.16 11.745 101.52 12.015 ;
     RECT  2.16 12.285 101.52 12.555 ;
     RECT  2.16 12.825 101.52 13.095 ;
     RECT  2.16 13.365 101.52 13.635 ;
     RECT  2.16 13.905 101.52 14.175 ;
     RECT  2.16 14.445 101.52 14.715 ;
     RECT  2.16 14.985 101.52 15.255 ;
     RECT  2.16 15.525 101.52 15.795 ;
     RECT  2.16 16.065 101.52 16.335 ;
     RECT  2.16 16.605 101.52 16.875 ;
     RECT  2.16 17.145 101.52 17.415 ;
     RECT  2.16 17.685 101.52 17.955 ;
     RECT  2.16 18.225 101.52 18.495 ;
     RECT  2.16 18.765 101.52 19.035 ;
     RECT  2.16 19.305 101.52 19.575 ;
     RECT  2.16 19.845 101.52 20.115 ;
     RECT  2.16 20.385 101.52 20.655 ;
     RECT  2.16 20.925 101.52 21.195 ;
     RECT  2.16 21.465 101.52 21.735 ;
     RECT  2.16 22.005 101.52 22.275 ;
     RECT  2.16 22.545 101.52 22.815 ;
     RECT  2.16 23.085 101.52 23.355 ;
     RECT  2.16 23.625 101.52 23.895 ;
     RECT  2.16 24.165 101.52 24.435 ;
     RECT  2.16 24.705 101.52 24.975 ;
     RECT  2.16 25.245 101.52 25.515 ;
     RECT  2.16 25.785 101.52 26.055 ;
     RECT  2.16 26.325 101.52 26.595 ;
     RECT  2.16 26.865 101.52 27.135 ;
     RECT  2.16 27.405 101.52 27.675 ;
     RECT  2.16 27.945 101.52 28.215 ;
     RECT  2.16 28.485 101.52 28.755 ;
     RECT  2.16 29.025 101.52 29.295 ;
     RECT  2.16 29.565 101.52 29.835 ;
     RECT  2.16 30.105 101.52 30.375 ;
     RECT  2.16 30.645 101.52 30.915 ;
     RECT  2.16 31.185 101.52 31.455 ;
     RECT  2.16 31.725 101.52 31.995 ;
     RECT  2.16 32.265 101.52 32.535 ;
     RECT  2.16 32.805 101.52 33.075 ;
     RECT  2.16 33.345 101.52 33.615 ;
     RECT  2.16 33.885 101.52 34.155 ;
     RECT  2.16 34.425 101.52 34.695 ;
     RECT  2.16 34.965 101.52 35.235 ;
     RECT  2.16 35.505 101.52 35.775 ;
     RECT  2.16 36.045 101.52 36.315 ;
     RECT  2.16 36.585 101.52 36.855 ;
     RECT  2.16 37.125 101.52 37.395 ;
     RECT  2.16 37.665 101.52 37.935 ;
     RECT  2.16 38.205 101.52 38.475 ;
     RECT  2.16 38.745 101.52 39.015 ;
     RECT  2.16 39.285 101.52 39.555 ;
     RECT  2.16 39.825 101.52 40.095 ;
     RECT  2.16 40.365 101.52 40.635 ;
     RECT  2.16 40.905 101.52 41.175 ;
     RECT  2.16 41.445 101.52 41.715 ;
     RECT  2.16 41.985 101.52 42.255 ;
     RECT  2.16 42.525 101.52 42.795 ;
     RECT  2.16 43.065 101.52 43.335 ;
     RECT  2.16 43.605 101.52 43.875 ;
     RECT  2.16 44.145 101.52 44.415 ;
     RECT  2.16 44.685 101.52 44.955 ;
     RECT  2.16 45.225 101.52 45.495 ;
     RECT  2.16 45.765 101.52 46.035 ;
     RECT  2.16 46.305 101.52 46.575 ;
     RECT  2.16 46.845 101.52 47.115 ;
     RECT  2.16 47.385 101.52 47.655 ;
     RECT  2.16 47.925 101.52 48.195 ;
     RECT  2.16 48.465 101.52 48.735 ;
     RECT  2.16 49.005 101.52 49.275 ;
     RECT  2.16 49.545 101.52 49.815 ;
     RECT  2.16 50.085 101.52 50.355 ;
     RECT  2.16 50.625 101.52 50.895 ;
     RECT  2.16 51.165 101.52 51.435 ;
     RECT  2.16 51.705 101.52 51.975 ;
     RECT  2.16 52.245 101.52 52.515 ;
     RECT  2.16 52.785 101.52 53.055 ;
     RECT  2.16 53.325 101.52 53.595 ;
     RECT  2.16 53.865 101.52 54.135 ;
     RECT  2.16 54.405 101.52 54.675 ;
     RECT  2.16 54.945 101.52 55.215 ;
     RECT  2.16 55.485 101.52 55.755 ;
     RECT  2.16 56.025 101.52 56.295 ;
     RECT  2.16 56.565 101.52 56.835 ;
     RECT  2.16 57.105 101.52 57.375 ;
     RECT  2.16 57.645 101.52 57.915 ;
     RECT  2.16 58.185 101.52 58.455 ;
     RECT  2.16 58.725 101.52 58.995 ;
     RECT  2.16 59.265 101.52 59.535 ;
     RECT  2.16 59.805 101.52 60.075 ;
     RECT  2.16 60.345 101.52 60.615 ;
     RECT  2.16 60.885 101.52 61.155 ;
     RECT  2.16 61.425 101.52 61.695 ;
     RECT  2.16 61.965 101.52 62.235 ;
     RECT  2.16 62.505 101.52 62.775 ;
     RECT  2.16 63.045 101.52 63.315 ;
     RECT  2.16 63.585 101.52 63.855 ;
     RECT  2.16 64.125 101.52 64.395 ;
     RECT  2.16 64.665 101.52 64.935 ;
     RECT  2.16 65.205 101.52 65.475 ;
     RECT  2.16 65.745 101.52 66.015 ;
     RECT  2.16 66.285 101.52 66.555 ;
     RECT  2.16 66.825 101.52 67.095 ;
     RECT  2.16 67.365 101.52 67.635 ;
     RECT  2.16 67.905 101.52 68.175 ;
     RECT  2.16 68.445 101.52 68.715 ;
     RECT  2.16 68.985 101.52 69.255 ;
     RECT  2.16 69.525 101.52 69.795 ;
     RECT  2.16 70.065 101.52 70.335 ;
     RECT  2.16 70.605 101.52 70.875 ;
     RECT  2.16 71.145 101.52 71.415 ;
     RECT  2.16 71.685 101.52 71.955 ;
     RECT  2.16 72.225 101.52 72.495 ;
     RECT  2.16 72.765 101.52 73.035 ;
     RECT  2.16 73.305 101.52 73.575 ;
     RECT  2.16 73.845 101.52 74.115 ;
     RECT  2.16 74.385 101.52 74.655 ;
     RECT  2.16 74.925 101.52 75.195 ;
     RECT  2.16 75.465 101.52 75.735 ;
     RECT  2.16 76.005 101.52 76.275 ;
     RECT  2.16 76.545 101.52 76.815 ;
     RECT  2.16 77.085 101.52 77.355 ;
     RECT  2.16 77.625 101.52 77.895 ;
     RECT  2.16 78.165 101.52 78.435 ;
     RECT  2.16 78.705 101.52 78.975 ;
     RECT  2.16 79.245 101.52 79.515 ;
     RECT  2.16 79.785 101.52 80.055 ;
     RECT  2.16 80.325 101.52 80.595 ;
     RECT  2.16 80.865 101.52 81.135 ;
     RECT  2.16 81.405 101.52 81.675 ;
     RECT  2.16 81.945 101.52 82.215 ;
     RECT  2.16 82.485 101.52 82.755 ;
     RECT  2.16 83.025 101.52 83.295 ;
     RECT  2.16 83.565 101.52 83.835 ;
     RECT  2.16 84.105 101.52 84.375 ;
     RECT  2.16 84.645 101.52 84.915 ;
     RECT  2.16 85.185 101.52 85.455 ;
     RECT  2.16 85.725 101.52 85.995 ;
     RECT  2.16 86.265 101.52 86.535 ;
     RECT  2.16 86.805 101.52 87.075 ;
     RECT  2.16 87.345 101.52 87.615 ;
     RECT  2.16 87.885 101.52 88.155 ;
     RECT  2.16 88.425 101.52 88.695 ;
     RECT  2.16 88.965 101.52 89.235 ;
     RECT  2.16 89.505 101.52 89.775 ;
     RECT  2.16 90.045 101.52 90.315 ;
     RECT  2.16 90.585 101.52 90.855 ;
     RECT  2.16 91.125 101.52 91.395 ;
     RECT  2.16 91.665 101.52 91.935 ;
     RECT  2.16 92.205 101.52 92.475 ;
     RECT  2.16 92.745 101.52 93.015 ;
     RECT  2.16 93.285 101.52 93.555 ;
     RECT  2.16 93.825 101.52 94.095 ;
     RECT  2.16 94.365 101.52 94.635 ;
     RECT  2.16 94.905 101.52 95.175 ;
     RECT  2.16 95.445 101.52 95.715 ;
     RECT  2.16 95.985 101.52 96.255 ;
     RECT  2.16 96.525 101.52 96.795 ;
     RECT  2.16 97.065 101.52 97.335 ;
     RECT  2.16 97.605 101.52 97.875 ;
     RECT  2.16 98.145 101.52 98.415 ;
     RECT  2.16 98.685 101.52 98.955 ;
     RECT  2.16 99.225 101.52 99.495 ;
     RECT  2.16 99.765 101.52 100.035 ;
     RECT  2.16 100.305 101.52 100.575 ;
     RECT  2.16 100.845 101.52 101.115 ;
     RECT  2.16 101.385 101.52 101.655 ;
     RECT  2.16 101.925 101.52 102.195 ;
     RECT  2.16 102.465 101.52 102.735 ;
     RECT  2.16 103.005 101.52 103.275 ;
     RECT  2.16 103.545 101.52 103.815 ;
     RECT  2.16 104.085 101.52 104.355 ;
     RECT  2.16 104.625 101.52 104.895 ;
     RECT  2.16 105.165 101.52 105.435 ;
     RECT  2.16 105.705 101.52 105.975 ;
     RECT  2.16 106.245 101.52 106.515 ;
     RECT  2.16 106.785 101.52 107.055 ;
     RECT  2.16 107.325 101.52 107.595 ;
     RECT  2.16 107.865 101.52 108.135 ;
     RECT  2.16 108.405 101.52 108.675 ;
     RECT  2.16 108.945 101.52 109.215 ;
     RECT  2.16 109.485 101.52 109.755 ;
     RECT  2.16 110.025 101.52 110.295 ;
     RECT  2.16 110.565 101.52 110.835 ;
     RECT  2.16 111.105 101.52 111.375 ;
     RECT  2.16 111.645 101.52 111.915 ;
     RECT  2.16 112.185 101.52 112.455 ;
     RECT  2.16 112.725 101.52 112.995 ;
     RECT  2.16 113.265 101.52 113.535 ;
     RECT  2.16 113.805 101.52 114.075 ;
     RECT  2.16 114.345 101.52 114.615 ;
     RECT  2.16 114.885 101.52 115.155 ;
     RECT  2.16 115.425 101.52 115.695 ;
     RECT  2.16 115.965 101.52 116.235 ;
     RECT  2.16 116.505 101.52 116.775 ;
     RECT  2.16 117.045 101.52 117.315 ;
     RECT  2.16 117.585 101.52 117.855 ;
     RECT  2.16 118.125 101.52 118.395 ;
     RECT  2.16 118.665 101.52 118.935 ;
     RECT  2.16 119.205 101.52 119.475 ;
     RECT  2.16 119.745 101.52 120.015 ;
     RECT  2.16 120.285 101.52 120.555 ;
     RECT  2.16 120.825 101.52 121.095 ;
     RECT  2.16 121.365 101.52 121.635 ;
     RECT  2.16 121.905 101.52 122.175 ;
     RECT  2.16 122.445 101.52 122.715 ;
     RECT  2.16 122.985 101.52 123.255 ;
     RECT  2.16 123.525 101.52 123.795 ;
     RECT  2.16 124.065 101.52 124.335 ;
     RECT  2.16 124.605 101.52 124.875 ;
     RECT  2.16 125.145 101.52 125.415 ;
     RECT  2.16 125.685 101.52 125.955 ;
     RECT  2.16 126.225 101.52 126.495 ;
     RECT  2.16 126.765 101.52 127.035 ;
     RECT  2.16 127.305 101.52 127.44 ;
    LAYER RVTP ;
     RECT  2.16 2.295 101.52 2.565 ;
     RECT  2.16 2.835 101.52 3.105 ;
     RECT  2.16 3.375 101.52 3.645 ;
     RECT  2.16 3.915 101.52 4.185 ;
     RECT  2.16 4.455 101.52 4.725 ;
     RECT  2.16 4.995 101.52 5.265 ;
     RECT  2.16 5.535 101.52 5.805 ;
     RECT  2.16 6.075 101.52 6.345 ;
     RECT  2.16 6.615 101.52 6.885 ;
     RECT  2.16 7.155 101.52 7.425 ;
     RECT  2.16 7.695 101.52 7.965 ;
     RECT  2.16 8.235 101.52 8.505 ;
     RECT  2.16 8.775 101.52 9.045 ;
     RECT  2.16 9.315 101.52 9.585 ;
     RECT  2.16 9.855 101.52 10.125 ;
     RECT  2.16 10.395 101.52 10.665 ;
     RECT  2.16 10.935 101.52 11.205 ;
     RECT  2.16 11.475 101.52 11.745 ;
     RECT  2.16 12.015 101.52 12.285 ;
     RECT  2.16 12.555 101.52 12.825 ;
     RECT  2.16 13.095 101.52 13.365 ;
     RECT  2.16 13.635 101.52 13.905 ;
     RECT  2.16 14.175 101.52 14.445 ;
     RECT  2.16 14.715 101.52 14.985 ;
     RECT  2.16 15.255 101.52 15.525 ;
     RECT  2.16 15.795 101.52 16.065 ;
     RECT  2.16 16.335 101.52 16.605 ;
     RECT  2.16 16.875 101.52 17.145 ;
     RECT  2.16 17.415 101.52 17.685 ;
     RECT  2.16 17.955 101.52 18.225 ;
     RECT  2.16 18.495 101.52 18.765 ;
     RECT  2.16 19.035 101.52 19.305 ;
     RECT  2.16 19.575 101.52 19.845 ;
     RECT  2.16 20.115 101.52 20.385 ;
     RECT  2.16 20.655 101.52 20.925 ;
     RECT  2.16 21.195 101.52 21.465 ;
     RECT  2.16 21.735 101.52 22.005 ;
     RECT  2.16 22.275 101.52 22.545 ;
     RECT  2.16 22.815 101.52 23.085 ;
     RECT  2.16 23.355 101.52 23.625 ;
     RECT  2.16 23.895 101.52 24.165 ;
     RECT  2.16 24.435 101.52 24.705 ;
     RECT  2.16 24.975 101.52 25.245 ;
     RECT  2.16 25.515 101.52 25.785 ;
     RECT  2.16 26.055 101.52 26.325 ;
     RECT  2.16 26.595 101.52 26.865 ;
     RECT  2.16 27.135 101.52 27.405 ;
     RECT  2.16 27.675 101.52 27.945 ;
     RECT  2.16 28.215 101.52 28.485 ;
     RECT  2.16 28.755 101.52 29.025 ;
     RECT  2.16 29.295 101.52 29.565 ;
     RECT  2.16 29.835 101.52 30.105 ;
     RECT  2.16 30.375 101.52 30.645 ;
     RECT  2.16 30.915 101.52 31.185 ;
     RECT  2.16 31.455 101.52 31.725 ;
     RECT  2.16 31.995 101.52 32.265 ;
     RECT  2.16 32.535 101.52 32.805 ;
     RECT  2.16 33.075 101.52 33.345 ;
     RECT  2.16 33.615 101.52 33.885 ;
     RECT  2.16 34.155 101.52 34.425 ;
     RECT  2.16 34.695 101.52 34.965 ;
     RECT  2.16 35.235 101.52 35.505 ;
     RECT  2.16 35.775 101.52 36.045 ;
     RECT  2.16 36.315 101.52 36.585 ;
     RECT  2.16 36.855 101.52 37.125 ;
     RECT  2.16 37.395 101.52 37.665 ;
     RECT  2.16 37.935 101.52 38.205 ;
     RECT  2.16 38.475 101.52 38.745 ;
     RECT  2.16 39.015 101.52 39.285 ;
     RECT  2.16 39.555 101.52 39.825 ;
     RECT  2.16 40.095 101.52 40.365 ;
     RECT  2.16 40.635 101.52 40.905 ;
     RECT  2.16 41.175 101.52 41.445 ;
     RECT  2.16 41.715 101.52 41.985 ;
     RECT  2.16 42.255 101.52 42.525 ;
     RECT  2.16 42.795 101.52 43.065 ;
     RECT  2.16 43.335 101.52 43.605 ;
     RECT  2.16 43.875 101.52 44.145 ;
     RECT  2.16 44.415 101.52 44.685 ;
     RECT  2.16 44.955 101.52 45.225 ;
     RECT  2.16 45.495 101.52 45.765 ;
     RECT  2.16 46.035 101.52 46.305 ;
     RECT  2.16 46.575 101.52 46.845 ;
     RECT  2.16 47.115 101.52 47.385 ;
     RECT  2.16 47.655 101.52 47.925 ;
     RECT  2.16 48.195 101.52 48.465 ;
     RECT  2.16 48.735 101.52 49.005 ;
     RECT  2.16 49.275 101.52 49.545 ;
     RECT  2.16 49.815 101.52 50.085 ;
     RECT  2.16 50.355 101.52 50.625 ;
     RECT  2.16 50.895 101.52 51.165 ;
     RECT  2.16 51.435 101.52 51.705 ;
     RECT  2.16 51.975 101.52 52.245 ;
     RECT  2.16 52.515 101.52 52.785 ;
     RECT  2.16 53.055 101.52 53.325 ;
     RECT  2.16 53.595 101.52 53.865 ;
     RECT  2.16 54.135 101.52 54.405 ;
     RECT  2.16 54.675 101.52 54.945 ;
     RECT  2.16 55.215 101.52 55.485 ;
     RECT  2.16 55.755 101.52 56.025 ;
     RECT  2.16 56.295 101.52 56.565 ;
     RECT  2.16 56.835 101.52 57.105 ;
     RECT  2.16 57.375 101.52 57.645 ;
     RECT  2.16 57.915 101.52 58.185 ;
     RECT  2.16 58.455 101.52 58.725 ;
     RECT  2.16 58.995 101.52 59.265 ;
     RECT  2.16 59.535 101.52 59.805 ;
     RECT  2.16 60.075 101.52 60.345 ;
     RECT  2.16 60.615 101.52 60.885 ;
     RECT  2.16 61.155 101.52 61.425 ;
     RECT  2.16 61.695 101.52 61.965 ;
     RECT  2.16 62.235 101.52 62.505 ;
     RECT  2.16 62.775 101.52 63.045 ;
     RECT  2.16 63.315 101.52 63.585 ;
     RECT  2.16 63.855 101.52 64.125 ;
     RECT  2.16 64.395 101.52 64.665 ;
     RECT  2.16 64.935 101.52 65.205 ;
     RECT  2.16 65.475 101.52 65.745 ;
     RECT  2.16 66.015 101.52 66.285 ;
     RECT  2.16 66.555 101.52 66.825 ;
     RECT  2.16 67.095 101.52 67.365 ;
     RECT  2.16 67.635 101.52 67.905 ;
     RECT  2.16 68.175 101.52 68.445 ;
     RECT  2.16 68.715 101.52 68.985 ;
     RECT  2.16 69.255 101.52 69.525 ;
     RECT  2.16 69.795 101.52 70.065 ;
     RECT  2.16 70.335 101.52 70.605 ;
     RECT  2.16 70.875 101.52 71.145 ;
     RECT  2.16 71.415 101.52 71.685 ;
     RECT  2.16 71.955 101.52 72.225 ;
     RECT  2.16 72.495 101.52 72.765 ;
     RECT  2.16 73.035 101.52 73.305 ;
     RECT  2.16 73.575 101.52 73.845 ;
     RECT  2.16 74.115 101.52 74.385 ;
     RECT  2.16 74.655 101.52 74.925 ;
     RECT  2.16 75.195 101.52 75.465 ;
     RECT  2.16 75.735 101.52 76.005 ;
     RECT  2.16 76.275 101.52 76.545 ;
     RECT  2.16 76.815 101.52 77.085 ;
     RECT  2.16 77.355 101.52 77.625 ;
     RECT  2.16 77.895 101.52 78.165 ;
     RECT  2.16 78.435 101.52 78.705 ;
     RECT  2.16 78.975 101.52 79.245 ;
     RECT  2.16 79.515 101.52 79.785 ;
     RECT  2.16 80.055 101.52 80.325 ;
     RECT  2.16 80.595 101.52 80.865 ;
     RECT  2.16 81.135 101.52 81.405 ;
     RECT  2.16 81.675 101.52 81.945 ;
     RECT  2.16 82.215 101.52 82.485 ;
     RECT  2.16 82.755 101.52 83.025 ;
     RECT  2.16 83.295 101.52 83.565 ;
     RECT  2.16 83.835 101.52 84.105 ;
     RECT  2.16 84.375 101.52 84.645 ;
     RECT  2.16 84.915 101.52 85.185 ;
     RECT  2.16 85.455 101.52 85.725 ;
     RECT  2.16 85.995 101.52 86.265 ;
     RECT  2.16 86.535 101.52 86.805 ;
     RECT  2.16 87.075 101.52 87.345 ;
     RECT  2.16 87.615 101.52 87.885 ;
     RECT  2.16 88.155 101.52 88.425 ;
     RECT  2.16 88.695 101.52 88.965 ;
     RECT  2.16 89.235 101.52 89.505 ;
     RECT  2.16 89.775 101.52 90.045 ;
     RECT  2.16 90.315 101.52 90.585 ;
     RECT  2.16 90.855 101.52 91.125 ;
     RECT  2.16 91.395 101.52 91.665 ;
     RECT  2.16 91.935 101.52 92.205 ;
     RECT  2.16 92.475 101.52 92.745 ;
     RECT  2.16 93.015 101.52 93.285 ;
     RECT  2.16 93.555 101.52 93.825 ;
     RECT  2.16 94.095 101.52 94.365 ;
     RECT  2.16 94.635 101.52 94.905 ;
     RECT  2.16 95.175 101.52 95.445 ;
     RECT  2.16 95.715 101.52 95.985 ;
     RECT  2.16 96.255 101.52 96.525 ;
     RECT  2.16 96.795 101.52 97.065 ;
     RECT  2.16 97.335 101.52 97.605 ;
     RECT  2.16 97.875 101.52 98.145 ;
     RECT  2.16 98.415 101.52 98.685 ;
     RECT  2.16 98.955 101.52 99.225 ;
     RECT  2.16 99.495 101.52 99.765 ;
     RECT  2.16 100.035 101.52 100.305 ;
     RECT  2.16 100.575 101.52 100.845 ;
     RECT  2.16 101.115 101.52 101.385 ;
     RECT  2.16 101.655 101.52 101.925 ;
     RECT  2.16 102.195 101.52 102.465 ;
     RECT  2.16 102.735 101.52 103.005 ;
     RECT  2.16 103.275 101.52 103.545 ;
     RECT  2.16 103.815 101.52 104.085 ;
     RECT  2.16 104.355 101.52 104.625 ;
     RECT  2.16 104.895 101.52 105.165 ;
     RECT  2.16 105.435 101.52 105.705 ;
     RECT  2.16 105.975 101.52 106.245 ;
     RECT  2.16 106.515 101.52 106.785 ;
     RECT  2.16 107.055 101.52 107.325 ;
     RECT  2.16 107.595 101.52 107.865 ;
     RECT  2.16 108.135 101.52 108.405 ;
     RECT  2.16 108.675 101.52 108.945 ;
     RECT  2.16 109.215 101.52 109.485 ;
     RECT  2.16 109.755 101.52 110.025 ;
     RECT  2.16 110.295 101.52 110.565 ;
     RECT  2.16 110.835 101.52 111.105 ;
     RECT  2.16 111.375 101.52 111.645 ;
     RECT  2.16 111.915 101.52 112.185 ;
     RECT  2.16 112.455 101.52 112.725 ;
     RECT  2.16 112.995 101.52 113.265 ;
     RECT  2.16 113.535 101.52 113.805 ;
     RECT  2.16 114.075 101.52 114.345 ;
     RECT  2.16 114.615 101.52 114.885 ;
     RECT  2.16 115.155 101.52 115.425 ;
     RECT  2.16 115.695 101.52 115.965 ;
     RECT  2.16 116.235 101.52 116.505 ;
     RECT  2.16 116.775 101.52 117.045 ;
     RECT  2.16 117.315 101.52 117.585 ;
     RECT  2.16 117.855 101.52 118.125 ;
     RECT  2.16 118.395 101.52 118.665 ;
     RECT  2.16 118.935 101.52 119.205 ;
     RECT  2.16 119.475 101.52 119.745 ;
     RECT  2.16 120.015 101.52 120.285 ;
     RECT  2.16 120.555 101.52 120.825 ;
     RECT  2.16 121.095 101.52 121.365 ;
     RECT  2.16 121.635 101.52 121.905 ;
     RECT  2.16 122.175 101.52 122.445 ;
     RECT  2.16 122.715 101.52 122.985 ;
     RECT  2.16 123.255 101.52 123.525 ;
     RECT  2.16 123.795 101.52 124.065 ;
     RECT  2.16 124.335 101.52 124.605 ;
     RECT  2.16 124.875 101.52 125.145 ;
     RECT  2.16 125.415 101.52 125.685 ;
     RECT  2.16 125.955 101.52 126.225 ;
     RECT  2.16 126.495 101.52 126.765 ;
     RECT  2.16 127.035 101.52 127.305 ;
    LAYER M1 ;
     RECT  2.16 2.151 101.52 127.449 ;
    LAYER M2 ;
     RECT  0.103 7.902 2.16 7.92 ;
     RECT  0.103 22.212 2.16 22.23 ;
     RECT  0.535 27.342 2.16 27.36 ;
     RECT  0.103 32.472 2.16 32.49 ;
     RECT  0.103 38.142 2.16 38.16 ;
     RECT  0.103 54.108 2.16 54.126 ;
     RECT  0.103 63.252 2.16 63.27 ;
     RECT  0.535 68.382 2.16 68.4 ;
     RECT  0.103 73.512 2.16 73.53 ;
     RECT  0.103 79.182 2.16 79.2 ;
     RECT  0.535 89.982 2.16 90 ;
     RECT  0.535 104.292 2.16 104.31 ;
     RECT  0.535 109.422 2.16 109.44 ;
     RECT  0.103 114.552 2.16 114.57 ;
     RECT  0.103 120.222 2.16 120.24 ;
     RECT  2.16 2.151 101.52 127.449 ;
     RECT  101.52 57.006 101.651 60.534 ;
     RECT  101.52 88.596 101.651 95.094 ;
     RECT  101.52 33.246 102.011 35.964 ;
     RECT  101.52 15.966 102.047 18.684 ;
     RECT  101.52 41.886 102.047 43.254 ;
     RECT  101.52 48.366 102.047 50.544 ;
     RECT  101.52 51.336 102.047 56.214 ;
     RECT  101.651 57.006 102.047 58.374 ;
     RECT  101.52 62.676 102.047 67.014 ;
     RECT  101.52 67.806 102.047 72.144 ;
     RECT  101.52 72.936 102.047 79.164 ;
     RECT  101.52 81.576 102.047 82.854 ;
     RECT  101.651 88.596 102.047 92.844 ;
     RECT  101.52 97.236 102.047 98.064 ;
     RECT  101.52 98.856 102.047 100.764 ;
     RECT  101.52 101.556 102.047 105.084 ;
     RECT  101.52 111.816 102.047 113.724 ;
     RECT  101.52 114.516 102.047 115.884 ;
     RECT  101.52 116.676 102.047 120.114 ;
     RECT  101.52 121.266 102.047 121.392 ;
     RECT  101.52 23.796 102.083 27.198 ;
     RECT  101.52 110.196 102.515 111.024 ;
     RECT  101.52 19.476 102.551 23.004 ;
     RECT  102.083 23.796 102.551 25.974 ;
     RECT  101.52 28.116 102.551 29.484 ;
     RECT  101.52 30.276 102.551 32.454 ;
     RECT  101.52 44.046 102.551 44.604 ;
     RECT  102.047 57.816 102.551 58.374 ;
     RECT  102.047 66.186 102.551 67.014 ;
     RECT  102.047 67.806 102.551 69.174 ;
     RECT  102.047 72.936 102.551 76.464 ;
     RECT  102.047 77.256 102.551 79.164 ;
     RECT  102.047 81.576 102.551 82.404 ;
     RECT  101.52 83.736 102.551 86.364 ;
     RECT  102.047 98.856 102.551 99.414 ;
     RECT  102.047 114.786 102.551 115.884 ;
     RECT  102.047 116.676 102.551 118.854 ;
     RECT  101.52 8.406 102.587 8.694 ;
     RECT  101.52 9.666 102.587 11.664 ;
     RECT  101.52 12.456 102.587 15.174 ;
     RECT  102.047 15.966 102.587 15.984 ;
     RECT  102.047 16.776 102.587 17.334 ;
     RECT  102.047 18.126 102.587 18.684 ;
     RECT  102.551 19.476 102.587 20.844 ;
     RECT  102.551 21.906 102.587 23.004 ;
     RECT  102.551 23.796 102.587 23.814 ;
     RECT  102.551 24.606 102.587 25.974 ;
     RECT  102.083 27.18 102.587 27.198 ;
     RECT  102.551 28.656 102.587 29.484 ;
     RECT  102.551 30.276 102.587 31.644 ;
     RECT  102.551 32.436 102.587 32.454 ;
     RECT  102.011 33.246 102.587 33.804 ;
     RECT  102.011 34.596 102.587 35.964 ;
     RECT  101.52 36.756 102.587 37.584 ;
     RECT  101.52 38.376 102.587 41.094 ;
     RECT  102.047 41.886 102.587 42.444 ;
     RECT  102.047 43.236 102.587 43.254 ;
     RECT  102.551 44.316 102.587 44.604 ;
     RECT  101.52 45.396 102.587 47.574 ;
     RECT  102.047 48.366 102.587 49.734 ;
     RECT  102.047 50.526 102.587 50.544 ;
     RECT  102.047 51.336 102.587 54.054 ;
     RECT  102.047 54.846 102.587 55.404 ;
     RECT  102.047 56.196 102.587 56.214 ;
     RECT  102.047 57.006 102.587 57.024 ;
     RECT  102.551 57.816 102.587 58.104 ;
     RECT  101.651 59.166 102.587 60.534 ;
     RECT  101.52 61.596 102.587 61.884 ;
     RECT  102.047 62.676 102.587 65.394 ;
     RECT  102.551 66.186 102.587 66.204 ;
     RECT  102.551 66.996 102.587 67.014 ;
     RECT  102.551 68.076 102.587 69.174 ;
     RECT  102.047 70.236 102.587 70.254 ;
     RECT  102.047 71.316 102.587 72.144 ;
     RECT  102.551 72.936 102.587 74.844 ;
     RECT  102.551 75.906 102.587 76.464 ;
     RECT  102.551 77.256 102.587 77.274 ;
     RECT  102.551 78.066 102.587 79.164 ;
     RECT  101.52 79.956 102.587 80.784 ;
     RECT  102.551 81.576 102.587 81.594 ;
     RECT  102.551 82.386 102.587 82.404 ;
     RECT  102.551 83.736 102.587 84.204 ;
     RECT  102.551 85.086 102.587 86.364 ;
     RECT  101.52 87.246 102.587 87.804 ;
     RECT  102.047 88.596 102.587 88.614 ;
     RECT  102.047 89.406 102.587 92.844 ;
     RECT  101.651 93.726 102.587 95.094 ;
     RECT  101.52 95.886 102.587 96.444 ;
     RECT  102.047 97.236 102.587 97.254 ;
     RECT  102.047 98.046 102.587 98.064 ;
     RECT  102.551 98.856 102.587 98.874 ;
     RECT  102.047 100.206 102.587 100.764 ;
     RECT  102.047 101.556 102.587 101.574 ;
     RECT  102.047 102.366 102.587 105.084 ;
     RECT  101.52 105.876 102.587 107.244 ;
     RECT  101.52 108.036 102.587 109.404 ;
     RECT  102.515 110.196 102.587 110.214 ;
     RECT  102.515 111.006 102.587 111.024 ;
     RECT  102.047 111.816 102.587 112.374 ;
     RECT  102.047 113.166 102.587 113.724 ;
     RECT  102.551 115.326 102.587 115.884 ;
     RECT  102.551 116.676 102.587 118.044 ;
     RECT  102.551 118.836 102.587 118.854 ;
     RECT  102.047 119.646 102.587 120.114 ;
     RECT  102.047 121.266 102.587 121.284 ;
     RECT  102.587 8.406 102.623 8.424 ;
     RECT  102.587 9.666 102.623 9.684 ;
     RECT  102.587 13.644 102.623 13.662 ;
     RECT  102.587 35.316 102.623 35.334 ;
     RECT  102.587 37.026 102.623 37.044 ;
     RECT  102.587 47.286 102.623 47.304 ;
     RECT  102.587 49.554 102.623 49.572 ;
     RECT  102.587 58.086 102.623 58.104 ;
     RECT  102.587 65.376 102.623 65.394 ;
     RECT  102.587 90.486 102.623 90.504 ;
     RECT  102.587 104.256 102.623 104.274 ;
    LAYER M3 ;
     RECT  2.415 2.143 2.505 2.413 ;
     RECT  7.815 2.143 7.905 2.413 ;
     RECT  13.215 2.143 13.305 2.413 ;
     RECT  18.615 2.143 18.705 2.413 ;
     RECT  24.015 2.143 24.105 2.413 ;
     RECT  29.415 2.143 29.505 2.413 ;
     RECT  34.815 2.143 34.905 2.413 ;
     RECT  40.215 2.143 40.305 2.413 ;
     RECT  45.615 2.143 45.705 2.413 ;
     RECT  51.015 2.143 51.105 2.413 ;
     RECT  56.415 2.143 56.505 2.413 ;
     RECT  61.815 2.143 61.905 2.413 ;
     RECT  67.215 2.143 67.305 2.413 ;
     RECT  72.615 2.143 72.705 2.413 ;
     RECT  78.015 2.143 78.105 2.413 ;
     RECT  83.415 2.143 83.505 2.413 ;
     RECT  88.815 2.143 88.905 2.413 ;
     RECT  94.215 2.143 94.305 2.413 ;
     RECT  99.615 2.143 99.705 2.413 ;
     RECT  0.108 7.897 0.126 7.997 ;
     RECT  51.015 2.413 51.297 8.131 ;
     RECT  3.744 7.861 3.762 8.195 ;
     RECT  101.196 8.275 101.214 8.311 ;
     RECT  2.415 2.413 2.697 8.395 ;
     RECT  101.196 8.311 101.394 8.401 ;
     RECT  50.724 8.131 51.297 8.429 ;
     RECT  51.015 8.429 51.297 8.509 ;
     RECT  99.615 2.413 99.897 8.509 ;
     RECT  100.728 8.401 101.394 8.509 ;
     RECT  4.176 8.275 4.266 8.581 ;
     RECT  99.615 8.509 101.394 8.581 ;
     RECT  102.6 8.401 102.618 8.587 ;
     RECT  4.176 8.581 4.914 8.699 ;
     RECT  102.564 8.587 102.618 8.699 ;
     RECT  4.176 8.699 4.194 8.735 ;
     RECT  99.576 8.581 101.394 8.779 ;
     RECT  98.892 8.779 101.394 8.851 ;
     RECT  98.1 8.581 98.118 8.923 ;
     RECT  98.856 8.851 101.394 8.923 ;
     RECT  97.416 8.923 101.394 8.969 ;
     RECT  98.1 8.969 101.394 9.041 ;
     RECT  5.688 8.401 5.706 9.085 ;
     RECT  52.236 9.067 52.254 9.113 ;
     RECT  5.364 9.085 5.706 9.149 ;
     RECT  5.364 9.149 5.382 9.275 ;
     RECT  53.28 9.121 53.298 9.355 ;
     RECT  49.932 9.121 49.95 9.391 ;
     RECT  53.28 9.355 53.406 9.391 ;
     RECT  99.615 9.041 101.394 9.485 ;
     RECT  49.644 9.391 50.166 9.509 ;
     RECT  53.28 9.391 53.478 9.545 ;
     RECT  6.264 9.247 6.282 9.661 ;
     RECT  7.815 2.413 8.097 9.661 ;
     RECT  51.015 8.509 51.354 9.661 ;
     RECT  49.644 9.509 49.986 9.677 ;
     RECT  6.264 9.661 6.354 9.689 ;
     RECT  6.336 9.689 6.354 9.779 ;
     RECT  53.46 9.545 53.478 9.779 ;
     RECT  99.615 9.485 101.214 9.779 ;
     RECT  4.536 9.661 4.554 9.815 ;
     RECT  51.015 9.661 51.39 9.823 ;
     RECT  7.2 9.661 8.097 9.851 ;
     RECT  94.215 2.413 94.497 9.872 ;
     RECT  95.4 9.859 95.418 9.872 ;
     RECT  94.215 9.872 95.418 9.883 ;
     RECT  50.724 9.823 51.39 9.895 ;
     RECT  94.212 9.883 95.418 9.895 ;
     RECT  102.6 8.699 102.618 9.917 ;
     RECT  76.068 9.787 76.086 9.931 ;
     RECT  98.1 9.041 98.514 9.931 ;
     RECT  74.664 9.931 74.682 10.049 ;
     RECT  76.068 9.931 76.266 10.049 ;
     RECT  76.068 10.049 76.086 10.085 ;
     RECT  94.212 9.895 96.102 10.085 ;
     RECT  94.215 10.085 96.102 10.129 ;
     RECT  2.304 8.395 2.697 10.157 ;
     RECT  2.34 10.157 2.697 10.193 ;
     RECT  4.284 10.165 4.41 10.201 ;
     RECT  99.615 9.779 101.178 10.201 ;
     RECT  94.215 10.129 96.606 10.205 ;
     RECT  95.976 10.205 96.606 10.219 ;
     RECT  94.215 10.205 95.202 10.253 ;
     RECT  52.56 9.931 52.578 10.315 ;
     RECT  52.416 10.315 52.578 10.319 ;
     RECT  94.215 10.253 95.022 10.355 ;
     RECT  95.976 10.219 97.038 10.355 ;
     RECT  2.415 10.193 2.697 10.471 ;
     RECT  49.644 9.677 49.662 10.471 ;
     RECT  50.724 9.895 51.606 10.471 ;
     RECT  52.416 10.319 52.434 10.471 ;
     RECT  49.5 10.471 49.662 10.589 ;
     RECT  99.432 10.201 101.178 10.589 ;
     RECT  2.415 10.471 2.934 10.625 ;
     RECT  74.124 10.057 74.142 10.625 ;
     RECT  99.432 10.589 101.034 10.661 ;
     RECT  49.572 10.589 49.662 10.669 ;
     RECT  50.724 10.471 52.434 10.669 ;
     RECT  0.108 10.555 0.126 10.685 ;
     RECT  5.256 10.201 5.274 10.705 ;
     RECT  94.215 10.355 94.662 10.733 ;
     RECT  98.064 9.931 98.514 10.741 ;
     RECT  99.432 10.661 100.062 10.741 ;
     RECT  49.572 10.669 52.434 10.829 ;
     RECT  4.176 10.201 4.41 10.831 ;
     RECT  5.256 10.705 5.382 10.831 ;
     RECT  55.26 10.021 55.278 10.831 ;
     RECT  96.66 10.355 97.038 10.859 ;
     RECT  98.064 10.741 100.062 10.859 ;
     RECT  98.064 10.859 98.55 10.895 ;
     RECT  2.415 10.625 2.862 10.987 ;
     RECT  4.176 10.831 5.382 11.011 ;
     RECT  98.064 10.895 98.262 11.011 ;
     RECT  54.72 10.831 55.278 11.039 ;
     RECT  4.176 11.011 5.814 11.165 ;
     RECT  53.424 10.471 53.442 11.165 ;
     RECT  74.376 10.831 74.394 11.165 ;
     RECT  97.596 11.011 98.262 11.165 ;
     RECT  6.768 11.245 6.786 11.281 ;
     RECT  6.768 11.281 6.966 11.309 ;
     RECT  2.34 10.987 2.862 11.371 ;
     RECT  6.948 11.309 6.966 11.399 ;
     RECT  53.568 11.281 53.586 11.399 ;
     RECT  101.016 10.661 101.034 11.399 ;
     RECT  2.34 11.371 3.294 11.407 ;
     RECT  4.248 11.165 5.814 11.435 ;
     RECT  49.572 10.829 52.038 11.453 ;
     RECT  99.615 10.859 100.062 11.641 ;
     RECT  2.304 11.407 3.294 11.669 ;
     RECT  5.688 11.435 5.814 11.669 ;
     RECT  50.508 11.453 52.038 11.705 ;
     RECT  74.664 11.371 74.682 11.705 ;
     RECT  96.66 10.859 96.822 11.749 ;
     RECT  90.648 11.641 90.666 11.813 ;
     RECT  96.3 11.749 96.822 11.821 ;
     RECT  95.508 11.677 95.526 11.885 ;
     RECT  99.615 11.641 100.602 11.911 ;
     RECT  48.24 11.677 48.258 11.939 ;
     RECT  50.58 11.705 52.038 11.939 ;
     RECT  96.3 11.821 97.074 11.939 ;
     RECT  2.304 11.669 2.697 11.975 ;
     RECT  96.444 11.939 97.074 11.975 ;
     RECT  97.02 11.975 97.074 11.981 ;
     RECT  50.616 11.939 52.038 12.055 ;
     RECT  4.248 11.435 4.446 12.091 ;
     RECT  49.572 11.453 49.77 12.091 ;
     RECT  74.628 11.911 74.646 12.091 ;
     RECT  49.392 12.091 49.77 12.209 ;
     RECT  74.448 12.091 74.646 12.209 ;
     RECT  4.14 12.091 4.446 12.245 ;
     RECT  74.448 12.209 74.61 12.245 ;
     RECT  99.432 11.911 100.602 12.245 ;
     RECT  98.064 11.165 98.262 12.325 ;
     RECT  70.704 12.217 70.722 12.353 ;
     RECT  5.688 11.669 5.706 12.361 ;
     RECT  99.432 12.245 99.897 12.361 ;
     RECT  102.564 10.315 102.582 12.475 ;
     RECT  5.472 12.361 5.706 12.631 ;
     RECT  50.616 12.055 52.398 12.631 ;
     RECT  5.4 12.631 6.354 12.659 ;
     RECT  2.415 11.975 2.697 12.715 ;
     RECT  94.215 10.733 94.497 12.721 ;
     RECT  48.348 11.947 48.366 12.749 ;
     RECT  4.536 12.361 4.554 12.785 ;
     RECT  96.588 12.715 96.606 12.785 ;
     RECT  99.072 12.361 99.897 12.785 ;
     RECT  74.592 12.245 74.61 12.821 ;
     RECT  49.176 12.856 49.194 12.893 ;
     RECT  94.215 12.721 94.662 12.893 ;
     RECT  50.616 12.631 52.542 12.901 ;
     RECT  97.668 12.325 98.262 12.901 ;
     RECT  50.112 12.901 52.542 12.929 ;
     RECT  97.524 12.901 98.262 12.991 ;
     RECT  99.615 12.785 99.897 12.991 ;
     RECT  100.908 12.361 101.178 12.991 ;
     RECT  50.112 12.929 52.47 13.055 ;
     RECT  95.724 12.715 95.742 13.055 ;
     RECT  97.164 12.991 98.262 13.055 ;
     RECT  5.4 12.659 5.418 13.063 ;
     RECT  6.3 12.659 6.354 13.063 ;
     RECT  6.3 13.063 6.39 13.085 ;
     RECT  98.244 13.055 98.262 13.099 ;
     RECT  6.372 13.085 6.39 13.289 ;
     RECT  95.868 13.171 95.886 13.289 ;
     RECT  102.528 12.475 102.582 13.289 ;
     RECT  4.572 13.063 5.418 13.325 ;
     RECT  50.364 13.055 52.47 13.325 ;
     RECT  97.164 13.055 97.182 13.325 ;
     RECT  2.304 12.715 2.697 13.441 ;
     RECT  3.564 12.901 3.582 13.441 ;
     RECT  102.564 13.289 102.582 13.469 ;
     RECT  2.304 13.441 3.582 13.525 ;
     RECT  4.572 13.325 4.59 13.525 ;
     RECT  2.304 13.525 4.59 13.559 ;
     RECT  2.304 13.559 3.042 13.631 ;
     RECT  99.615 12.991 101.178 13.675 ;
     RECT  55.26 11.039 55.278 13.801 ;
     RECT  74.772 13.171 74.79 13.801 ;
     RECT  102.6 13.639 102.618 13.805 ;
     RECT  99.615 13.675 101.214 13.829 ;
     RECT  4.032 13.559 4.59 13.865 ;
     RECT  50.4 13.325 52.47 13.865 ;
     RECT  99.615 13.829 100.746 13.901 ;
     RECT  74.772 13.801 74.826 14.071 ;
     RECT  98.244 13.099 98.766 14.071 ;
     RECT  99.615 13.901 100.35 14.071 ;
     RECT  74.124 14.071 74.826 14.135 ;
     RECT  98.244 14.071 100.35 14.215 ;
     RECT  97.56 14.215 100.35 14.251 ;
     RECT  6.48 13.981 6.498 14.279 ;
     RECT  97.236 14.251 100.35 14.285 ;
     RECT  5.544 13.675 5.562 14.341 ;
     RECT  7.815 9.851 8.097 14.341 ;
     RECT  52.632 13.981 52.65 14.341 ;
     RECT  48.42 14.251 48.438 14.369 ;
     RECT  5.292 14.341 5.562 14.381 ;
     RECT  46.764 14.377 46.782 14.477 ;
     RECT  74.124 14.135 74.142 14.611 ;
     RECT  5.292 14.381 5.454 14.639 ;
     RECT  48.492 14.521 48.51 14.639 ;
     RECT  52.632 14.341 52.758 14.647 ;
     RECT  4.464 13.865 4.482 14.675 ;
     RECT  7.815 14.341 8.298 14.675 ;
     RECT  73.908 14.611 74.142 14.675 ;
     RECT  5.292 14.639 5.382 14.791 ;
     RECT  7.815 14.675 8.097 14.791 ;
     RECT  50.4 13.865 51.786 14.791 ;
     RECT  52.632 14.647 52.794 14.791 ;
     RECT  98.244 14.285 100.35 14.791 ;
     RECT  50.4 14.791 52.794 14.813 ;
     RECT  54.72 13.801 55.278 14.819 ;
     RECT  94.215 12.893 94.497 14.827 ;
     RECT  7.38 14.791 8.097 14.909 ;
     RECT  51.015 14.813 52.794 14.909 ;
     RECT  98.244 14.791 100.674 14.909 ;
     RECT  51.015 14.909 52.65 14.945 ;
     RECT  73.908 14.675 73.926 14.945 ;
     RECT  94.215 14.827 94.878 14.945 ;
     RECT  97.236 14.285 97.254 14.957 ;
     RECT  90.684 14.881 90.702 15.053 ;
     RECT  75.312 15.025 75.33 15.061 ;
     RECT  51.015 14.945 52.362 15.179 ;
     RECT  53.964 14.521 53.982 15.179 ;
     RECT  75.312 15.061 75.51 15.179 ;
     RECT  2.304 13.631 2.697 15.215 ;
     RECT  75.312 15.179 75.33 15.215 ;
     RECT  96.696 15.025 96.714 15.215 ;
     RECT  72.615 2.413 72.897 15.223 ;
     RECT  54.792 14.819 55.278 15.251 ;
     RECT  4.068 15.151 4.194 15.295 ;
     RECT  2.415 15.215 2.697 15.307 ;
     RECT  4.032 15.295 4.194 15.307 ;
     RECT  53.82 15.295 53.838 15.341 ;
     RECT  98.244 14.909 100.602 15.359 ;
     RECT  2.415 15.307 4.194 15.389 ;
     RECT  2.415 15.389 3.33 15.485 ;
     RECT  4.068 15.389 4.194 15.485 ;
     RECT  9.252 14.791 9.27 15.485 ;
     RECT  5.004 14.791 5.382 15.601 ;
     RECT  51.015 15.179 51.93 15.719 ;
     RECT  54.9 15.251 55.278 15.755 ;
     RECT  72.615 15.223 73.566 15.755 ;
     RECT  51.015 15.719 51.786 15.869 ;
     RECT  99.615 15.359 100.602 15.871 ;
     RECT  102.564 14.203 102.582 15.931 ;
     RECT  50.148 15.871 50.166 15.961 ;
     RECT  6.336 15.601 6.354 15.979 ;
     RECT  55.152 15.755 55.278 15.989 ;
     RECT  4.716 15.601 5.382 16.025 ;
     RECT  6.336 15.979 6.966 16.025 ;
     RECT  99.615 15.871 101.142 16.025 ;
     RECT  102.024 15.931 102.582 16.097 ;
     RECT  52.74 15.871 52.758 16.105 ;
     RECT  96.912 15.691 96.93 16.105 ;
     RECT  98.244 15.359 98.262 16.105 ;
     RECT  96.912 16.105 98.262 16.141 ;
     RECT  2.415 15.485 2.697 16.171 ;
     RECT  47.808 16.141 47.826 16.259 ;
     RECT  52.74 16.105 52.866 16.259 ;
     RECT  96.912 16.141 98.658 16.259 ;
     RECT  6.336 16.025 6.75 16.295 ;
     RECT  52.74 16.259 52.794 16.295 ;
     RECT  96.912 16.259 98.586 16.295 ;
     RECT  50.004 15.961 50.166 16.339 ;
     RECT  46.764 16.267 46.782 16.367 ;
     RECT  49.968 16.339 50.166 16.411 ;
     RECT  4.5 16.411 4.698 16.501 ;
     RECT  49.932 16.411 50.166 16.501 ;
     RECT  51.015 15.869 51.39 16.501 ;
     RECT  48.78 15.961 48.798 16.529 ;
     RECT  52.776 16.295 52.794 16.529 ;
     RECT  49.932 16.501 51.39 16.681 ;
     RECT  94.215 14.945 94.497 16.795 ;
     RECT  6.228 16.411 6.246 16.799 ;
     RECT  49.932 16.681 51.822 16.799 ;
     RECT  96.912 16.295 98.262 16.799 ;
     RECT  3.852 16.501 4.698 16.835 ;
     RECT  73.836 16.501 73.854 16.835 ;
     RECT  96.912 16.799 96.93 16.835 ;
     RECT  55.26 15.989 55.278 16.843 ;
     RECT  50.004 16.799 51.822 16.915 ;
     RECT  70.704 16.843 70.722 16.943 ;
     RECT  54.684 16.843 55.278 16.979 ;
     RECT  99.615 16.025 101.034 17.041 ;
     RECT  97.776 16.799 98.262 17.069 ;
     RECT  102.528 16.097 102.582 17.069 ;
     RECT  95.58 16.951 95.598 17.105 ;
     RECT  97.848 17.069 98.262 17.105 ;
     RECT  50.004 16.915 52.038 17.117 ;
     RECT  76.176 15.997 76.194 17.311 ;
     RECT  94.215 16.795 94.662 17.311 ;
     RECT  5.472 16.501 5.49 17.339 ;
     RECT  4.176 16.835 4.698 17.347 ;
     RECT  94.215 17.311 94.698 17.347 ;
     RECT  99.615 17.041 101.178 17.371 ;
     RECT  2.304 16.171 2.697 17.375 ;
     RECT  74.664 16.915 74.682 17.375 ;
     RECT  76.176 17.311 76.374 17.375 ;
     RECT  78.015 2.413 78.297 17.383 ;
     RECT  99.324 17.371 101.178 17.411 ;
     RECT  76.356 17.375 76.374 17.447 ;
     RECT  2.412 17.375 2.697 17.455 ;
     RECT  50.076 17.117 52.038 17.491 ;
     RECT  2.412 17.455 2.79 17.501 ;
     RECT  4.176 17.347 5.418 17.501 ;
     RECT  50.076 17.491 52.11 17.519 ;
     RECT  78.015 17.383 78.606 17.519 ;
     RECT  48.528 17.347 48.546 17.581 ;
     RECT  50.724 17.519 52.11 17.581 ;
     RECT  4.932 17.501 5.418 17.609 ;
     RECT  48.528 17.581 48.618 17.609 ;
     RECT  94.215 17.347 94.77 17.609 ;
     RECT  4.176 17.501 4.194 17.645 ;
     RECT  5.004 17.609 5.418 17.645 ;
     RECT  50.724 17.581 52.29 17.681 ;
     RECT  7.815 14.909 8.097 17.761 ;
     RECT  52.092 17.681 52.29 17.761 ;
     RECT  52.092 17.761 52.362 17.915 ;
     RECT  6.588 17.725 6.606 18.031 ;
     RECT  7.74 17.761 8.097 18.031 ;
     RECT  52.344 17.915 52.362 18.031 ;
     RECT  97.416 17.803 97.434 18.031 ;
     RECT  98.208 17.105 98.262 18.031 ;
     RECT  99.324 17.411 101.142 18.031 ;
     RECT  102.564 17.069 102.582 18.031 ;
     RECT  6.588 18.031 6.75 18.077 ;
     RECT  52.344 18.031 52.542 18.121 ;
     RECT  102.024 18.031 102.582 18.125 ;
     RECT  6.732 18.077 6.75 18.149 ;
     RECT  97.416 18.031 101.142 18.149 ;
     RECT  52.344 18.121 52.722 18.157 ;
     RECT  53.856 18.121 53.874 18.157 ;
     RECT  74.988 17.851 75.006 18.157 ;
     RECT  5.004 17.645 5.022 18.185 ;
     RECT  74.448 18.157 75.006 18.185 ;
     RECT  99.615 18.149 101.142 18.185 ;
     RECT  52.344 18.157 53.874 18.221 ;
     RECT  99.615 18.185 100.422 18.221 ;
     RECT  53.136 18.221 53.874 18.257 ;
     RECT  48.6 17.609 48.618 18.301 ;
     RECT  48.6 18.301 49.302 18.329 ;
     RECT  2.412 17.501 2.697 18.331 ;
     RECT  50.724 17.681 51.297 18.391 ;
     RECT  7.524 18.031 8.097 18.419 ;
     RECT  48.996 18.329 49.302 18.419 ;
     RECT  53.856 18.257 53.874 18.419 ;
     RECT  74.448 18.185 74.466 18.455 ;
     RECT  96.264 18.379 96.282 18.455 ;
     RECT  97.416 18.149 98.874 18.571 ;
     RECT  2.304 18.331 2.697 18.661 ;
     RECT  50.472 18.391 51.297 18.661 ;
     RECT  48.996 18.419 49.158 18.689 ;
     RECT  49.14 18.689 49.158 18.701 ;
     RECT  2.304 18.661 3.15 18.761 ;
     RECT  97.2 18.571 98.874 18.811 ;
     RECT  102.564 18.125 102.582 18.955 ;
     RECT  76.572 18.841 76.59 18.959 ;
     RECT  53.964 18.571 53.982 18.995 ;
     RECT  4.32 18.805 4.338 19.111 ;
     RECT  50.184 18.661 51.297 19.111 ;
     RECT  52.128 18.841 52.146 19.111 ;
     RECT  97.092 18.811 98.874 19.201 ;
     RECT  99.615 18.221 100.242 19.201 ;
     RECT  3.996 19.111 4.482 19.229 ;
     RECT  2.304 18.761 2.97 19.265 ;
     RECT  3.996 19.229 4.014 19.265 ;
     RECT  55.26 16.979 55.278 19.273 ;
     RECT  72.615 15.755 72.897 19.273 ;
     RECT  74.124 19.237 74.142 19.273 ;
     RECT  97.092 19.201 100.242 19.345 ;
     RECT  54.792 19.273 55.278 19.373 ;
     RECT  7.815 18.419 8.097 19.381 ;
     RECT  97.092 19.345 100.746 19.381 ;
     RECT  97.092 19.381 101.178 19.409 ;
     RECT  5.256 19.111 5.274 19.471 ;
     RECT  2.415 19.265 2.97 19.499 ;
     RECT  96.336 19.201 96.354 19.499 ;
     RECT  97.344 19.409 101.178 19.499 ;
     RECT  72.615 19.273 74.142 19.535 ;
     RECT  99.615 19.499 101.178 19.535 ;
     RECT  102.024 18.955 102.582 19.607 ;
     RECT  50.184 19.111 52.218 19.615 ;
     RECT  50.184 19.615 52.542 19.651 ;
     RECT  97.344 19.499 98.766 19.709 ;
     RECT  6.444 19.387 6.462 19.741 ;
     RECT  7.416 19.381 8.097 19.741 ;
     RECT  6.444 19.741 8.097 19.769 ;
     RECT  49.536 19.651 52.758 19.769 ;
     RECT  4.932 19.471 5.274 19.805 ;
     RECT  73.8 19.535 74.142 19.805 ;
     RECT  5.112 19.805 5.274 19.915 ;
     RECT  49.752 19.769 52.758 19.921 ;
     RECT  97.668 19.709 98.766 19.949 ;
     RECT  98.172 19.949 98.766 20.039 ;
     RECT  5.112 19.915 5.346 20.048 ;
     RECT  7.164 19.769 8.097 20.075 ;
     RECT  98.172 20.039 98.658 20.075 ;
     RECT  2.415 19.499 2.826 20.093 ;
     RECT  4.14 20.011 4.158 20.191 ;
     RECT  94.215 17.609 94.497 20.191 ;
     RECT  7.308 20.075 8.097 20.309 ;
     RECT  49.752 19.921 52.866 20.309 ;
     RECT  94.215 20.191 94.878 20.309 ;
     RECT  5.112 20.048 5.13 20.345 ;
     RECT  73.8 19.805 73.818 20.345 ;
     RECT  95.652 20.191 95.67 20.345 ;
     RECT  2.415 20.093 2.697 20.491 ;
     RECT  49.86 20.309 52.866 20.525 ;
     RECT  50.832 20.525 52.866 20.731 ;
     RECT  75.672 20.551 75.69 20.731 ;
     RECT  99.615 19.535 100.998 20.731 ;
     RECT  94.215 20.309 94.662 20.759 ;
     RECT  75.672 20.731 75.906 20.849 ;
     RECT  50.832 20.731 53.01 20.885 ;
     RECT  75.672 20.849 75.69 20.885 ;
     RECT  52.596 20.885 53.01 20.957 ;
     RECT  99.504 20.731 100.998 20.965 ;
     RECT  3.96 20.191 4.302 21.001 ;
     RECT  98.172 20.075 98.262 21.001 ;
     RECT  99.504 20.965 101.214 21.001 ;
     RECT  75.06 20.929 75.258 21.119 ;
     RECT  99.216 21.001 101.214 21.119 ;
     RECT  3.924 21.001 4.554 21.271 ;
     RECT  49.86 20.525 49.878 21.271 ;
     RECT  50.832 20.885 51.678 21.293 ;
     RECT  49.176 21.271 49.878 21.361 ;
     RECT  5.94 21.271 5.958 21.389 ;
     RECT  49.176 21.361 50.058 21.389 ;
     RECT  2.304 20.491 2.697 21.425 ;
     RECT  3.924 21.271 4.59 21.425 ;
     RECT  49.464 21.389 50.058 21.499 ;
     RECT  50.832 21.293 51.462 21.499 ;
     RECT  98.028 21.001 98.262 21.505 ;
     RECT  4.176 21.425 4.59 21.541 ;
     RECT  5.76 21.505 5.778 21.541 ;
     RECT  99.216 21.119 101.034 21.541 ;
     RECT  102.564 19.607 102.582 21.541 ;
     RECT  75.24 21.119 75.258 21.569 ;
     RECT  102.528 21.541 102.582 21.581 ;
     RECT  46.764 21.397 46.782 21.659 ;
     RECT  49.464 21.499 51.462 21.659 ;
     RECT  52.596 20.957 52.794 21.659 ;
     RECT  49.464 21.659 50.238 21.682 ;
     RECT  99.108 21.541 101.034 21.695 ;
     RECT  2.415 21.425 2.697 21.775 ;
     RECT  52.596 21.659 52.758 21.811 ;
     RECT  2.415 21.775 2.826 21.821 ;
     RECT  95.688 21.643 95.706 21.901 ;
     RECT  4.176 21.541 5.778 21.929 ;
     RECT  4.176 21.929 4.554 21.965 ;
     RECT  74.268 21.091 74.286 21.965 ;
     RECT  52.344 21.811 52.758 22.073 ;
     RECT  51.015 21.659 51.462 22.081 ;
     RECT  97.56 21.505 98.262 22.081 ;
     RECT  95.688 21.901 95.85 22.199 ;
     RECT  97.056 22.081 98.262 22.199 ;
     RECT  99.615 21.695 101.034 22.199 ;
     RECT  5.472 21.929 5.778 22.235 ;
     RECT  0.108 22.207 0.126 22.253 ;
     RECT  5.472 22.235 5.706 22.469 ;
     RECT  4.464 21.965 4.554 22.505 ;
     RECT  49.464 21.682 50.058 22.577 ;
     RECT  50.004 22.577 50.058 22.585 ;
     RECT  51.015 22.081 51.57 22.585 ;
     RECT  50.004 22.585 51.57 22.613 ;
     RECT  50.292 22.613 51.57 22.621 ;
     RECT  97.56 22.199 98.262 22.621 ;
     RECT  99.615 22.199 100.026 22.621 ;
     RECT  6.696 22.351 6.714 22.649 ;
     RECT  2.415 21.821 2.697 22.651 ;
     RECT  50.292 22.621 51.606 22.711 ;
     RECT  52.344 22.073 52.722 22.711 ;
     RECT  75.672 22.621 75.69 22.739 ;
     RECT  97.56 22.621 100.026 22.739 ;
     RECT  101.016 22.199 101.034 22.739 ;
     RECT  2.304 22.651 2.697 22.775 ;
     RECT  97.56 22.739 98.694 22.775 ;
     RECT  55.26 19.373 55.278 22.891 ;
     RECT  94.215 20.759 94.497 22.891 ;
     RECT  54.648 22.891 55.278 23.045 ;
     RECT  98.244 22.775 98.694 23.045 ;
     RECT  72.615 19.535 72.897 23.053 ;
     RECT  2.415 22.775 2.697 23.083 ;
     RECT  54.792 23.045 55.278 23.117 ;
     RECT  50.292 22.711 52.722 23.161 ;
     RECT  95.94 23.125 95.958 23.161 ;
     RECT  5.472 22.469 5.526 23.251 ;
     RECT  70.704 23.161 70.722 23.279 ;
     RECT  2.415 23.083 2.754 23.315 ;
     RECT  74.592 22.891 74.61 23.315 ;
     RECT  4.788 23.251 5.706 23.317 ;
     RECT  4.788 23.317 6.03 23.357 ;
     RECT  95.94 23.161 96.102 23.371 ;
     RECT  96.876 23.161 96.894 23.371 ;
     RECT  95.94 23.371 96.894 23.405 ;
     RECT  99.615 22.739 100.026 23.431 ;
     RECT  2.415 23.315 2.697 23.515 ;
     RECT  2.304 23.515 2.697 23.585 ;
     RECT  72.396 23.053 72.897 23.585 ;
     RECT  3.996 22.783 4.014 23.665 ;
     RECT  4.788 23.357 4.806 23.665 ;
     RECT  98.244 23.045 98.262 23.701 ;
     RECT  99.615 23.431 100.602 23.701 ;
     RECT  102.564 21.581 102.582 23.707 ;
     RECT  53.712 23.431 54.018 23.819 ;
     RECT  96.624 23.405 96.894 23.819 ;
     RECT  3.996 23.665 4.806 23.855 ;
     RECT  53.712 23.819 53.838 23.855 ;
     RECT  75.816 23.161 75.834 23.855 ;
     RECT  76.788 23.791 76.806 23.891 ;
     RECT  94.215 22.891 94.662 23.891 ;
     RECT  98.064 23.701 98.262 23.899 ;
     RECT  96.624 23.819 96.642 23.933 ;
     RECT  50.292 23.161 52.794 23.971 ;
     RECT  7.02 23.323 7.038 23.999 ;
     RECT  49.86 23.971 53.622 24.089 ;
     RECT  102.528 23.707 102.582 24.089 ;
     RECT  97.488 23.899 98.262 24.205 ;
     RECT  4.248 23.855 4.806 24.241 ;
     RECT  5.688 23.357 5.706 24.241 ;
     RECT  97.488 24.205 98.874 24.269 ;
     RECT  5.688 24.241 5.742 24.331 ;
     RECT  4.248 24.241 4.95 24.359 ;
     RECT  2.412 23.585 2.697 24.367 ;
     RECT  4.248 24.359 4.266 24.395 ;
     RECT  97.488 24.269 98.262 24.395 ;
     RECT  74.664 24.367 74.682 24.403 ;
     RECT  5.688 24.331 6.246 24.475 ;
     RECT  99.615 23.701 101.178 24.475 ;
     RECT  5.256 24.475 6.894 24.512 ;
     RECT  99.18 24.475 101.178 24.571 ;
     RECT  48.456 24.511 48.474 24.629 ;
     RECT  50.184 24.089 53.622 24.629 ;
     RECT  74.664 24.403 74.754 24.665 ;
     RECT  99.18 24.571 101.718 24.665 ;
     RECT  50.184 24.629 53.586 24.773 ;
     RECT  5.256 24.512 6.642 24.809 ;
     RECT  99.576 24.665 101.718 24.809 ;
     RECT  2.34 24.367 2.697 24.811 ;
     RECT  50.616 24.773 53.586 24.899 ;
     RECT  2.304 24.811 2.697 24.935 ;
     RECT  50.616 24.899 53.442 24.935 ;
     RECT  74.664 24.665 74.682 24.935 ;
     RECT  99.576 24.809 101.07 24.935 ;
     RECT  7.815 20.309 8.097 25.051 ;
     RECT  50.616 24.935 51.297 25.079 ;
     RECT  6.228 24.809 6.642 25.085 ;
     RECT  97.02 24.871 97.038 25.099 ;
     RECT  6.228 25.085 6.246 25.169 ;
     RECT  95.796 25.099 95.814 25.169 ;
     RECT  96.84 25.099 97.038 25.169 ;
     RECT  5.256 24.809 5.274 25.205 ;
     RECT  96.84 25.169 96.858 25.205 ;
     RECT  97.992 24.395 98.262 25.321 ;
     RECT  52.164 24.935 53.01 25.439 ;
     RECT  95.94 25.321 95.958 25.439 ;
     RECT  74.484 25.141 74.502 25.475 ;
     RECT  96.732 25.321 96.75 25.475 ;
     RECT  97.812 25.321 98.262 25.475 ;
     RECT  2.415 24.935 2.697 25.675 ;
     RECT  99.615 24.935 101.07 25.681 ;
     RECT  3.924 25.321 3.942 25.745 ;
     RECT  7.56 25.051 8.097 25.745 ;
     RECT  52.2 25.439 53.01 25.745 ;
     RECT  99.615 25.681 101.178 25.781 ;
     RECT  52.272 25.745 53.01 25.789 ;
     RECT  99.615 25.781 101.034 25.825 ;
     RECT  52.272 25.789 53.658 25.861 ;
     RECT  48.564 24.745 48.582 25.889 ;
     RECT  52.272 25.861 53.946 25.889 ;
     RECT  98.244 25.475 98.262 25.915 ;
     RECT  52.272 25.889 52.938 25.979 ;
     RECT  102.564 24.089 102.582 25.979 ;
     RECT  55.26 23.117 55.278 25.987 ;
     RECT  72.615 23.585 72.897 25.987 ;
     RECT  2.304 25.675 2.697 26.015 ;
     RECT  53.784 25.889 53.946 26.015 ;
     RECT  74.664 25.753 74.682 26.015 ;
     RECT  54.684 25.987 55.278 26.087 ;
     RECT  4.788 25.675 4.806 26.131 ;
     RECT  50.724 25.079 51.297 26.131 ;
     RECT  99.288 25.825 101.034 26.131 ;
     RECT  76.356 25.987 76.374 26.159 ;
     RECT  5.724 26.131 5.742 26.203 ;
     RECT  49.824 25.825 49.842 26.203 ;
     RECT  50.58 26.131 51.462 26.203 ;
     RECT  98.244 25.915 98.298 26.203 ;
     RECT  99.216 26.131 101.034 26.203 ;
     RECT  5.724 26.203 6.03 26.221 ;
     RECT  49.824 26.203 51.462 26.237 ;
     RECT  53.82 26.015 53.946 26.249 ;
     RECT  4.392 26.131 4.95 26.285 ;
     RECT  53.82 26.249 53.838 26.285 ;
     RECT  5.724 26.221 6.102 26.519 ;
     RECT  48.78 26.401 48.798 26.519 ;
     RECT  49.932 26.237 51.462 26.519 ;
     RECT  98.244 26.203 101.034 26.519 ;
     RECT  2.34 26.015 2.697 26.527 ;
     RECT  72.615 25.987 73.53 26.555 ;
     RECT  2.34 26.527 2.826 26.573 ;
     RECT  99.615 26.519 101.034 26.635 ;
     RECT  4.5 26.285 4.95 26.671 ;
     RECT  5.724 26.519 6.03 26.671 ;
     RECT  49.968 26.519 51.462 26.671 ;
     RECT  97.452 26.203 97.47 26.671 ;
     RECT  6.804 26.527 6.858 26.699 ;
     RECT  4.5 26.671 6.03 26.789 ;
     RECT  46.764 25.789 46.782 26.789 ;
     RECT  97.128 26.671 97.47 26.789 ;
     RECT  98.244 26.519 98.73 26.789 ;
     RECT  102.024 26.299 102.078 26.789 ;
     RECT  52.884 25.979 52.902 26.825 ;
     RECT  2.34 26.573 2.697 26.971 ;
     RECT  6.804 26.699 6.822 27.059 ;
     RECT  95.472 26.443 95.49 27.059 ;
     RECT  2.304 26.971 2.697 27.095 ;
     RECT  97.128 26.789 97.146 27.095 ;
     RECT  99.615 26.635 101.142 27.175 ;
     RECT  53.028 26.941 53.046 27.203 ;
     RECT  4.5 26.789 5.274 27.211 ;
     RECT  49.968 26.671 51.858 27.211 ;
     RECT  98.244 26.789 98.262 27.211 ;
     RECT  49.968 27.211 52.218 27.329 ;
     RECT  53.1 27.211 53.118 27.329 ;
     RECT  95.616 27.211 95.634 27.329 ;
     RECT  98.136 27.211 98.262 27.329 ;
     RECT  96.408 27.211 96.426 27.365 ;
     RECT  0.54 27.337 0.558 27.437 ;
     RECT  98.244 27.329 98.262 27.595 ;
     RECT  3.708 27.211 5.274 27.635 ;
     RECT  6.264 27.607 6.282 27.751 ;
     RECT  99.615 27.175 101.178 27.751 ;
     RECT  3.96 27.635 5.238 27.779 ;
     RECT  2.415 27.095 2.697 27.835 ;
     RECT  48.78 27.751 48.798 27.869 ;
     RECT  2.304 27.835 2.697 27.905 ;
     RECT  7.815 25.745 8.097 27.931 ;
     RECT  49.968 27.329 49.986 27.965 ;
     RECT  50.94 27.329 52.218 28.021 ;
     RECT  94.215 23.891 94.497 28.021 ;
     RECT  102.564 27.163 102.582 28.027 ;
     RECT  50.94 28.021 52.722 28.139 ;
     RECT  75.708 28.021 75.726 28.139 ;
     RECT  94.215 28.021 94.662 28.139 ;
     RECT  3.96 27.779 3.978 28.175 ;
     RECT  98.244 27.595 98.334 28.183 ;
     RECT  98.136 28.183 98.334 28.211 ;
     RECT  2.415 27.905 2.697 28.291 ;
     RECT  6.192 27.751 6.282 28.291 ;
     RECT  99.252 27.751 101.178 28.291 ;
     RECT  6.156 28.291 6.282 28.381 ;
     RECT  2.415 28.291 2.79 28.409 ;
     RECT  7.815 27.931 8.298 28.445 ;
     RECT  50.94 28.139 51.297 28.445 ;
     RECT  74.772 28.111 74.79 28.445 ;
     RECT  97.128 28.411 97.146 28.451 ;
     RECT  102.528 28.027 102.582 28.453 ;
     RECT  101.988 28.453 102.582 28.493 ;
     RECT  52.02 28.139 52.722 28.561 ;
     RECT  98.136 28.211 98.262 28.561 ;
     RECT  6.156 28.381 6.822 28.589 ;
     RECT  6.804 28.589 6.822 28.679 ;
     RECT  50.04 28.561 50.058 28.679 ;
     RECT  5.112 27.779 5.238 28.715 ;
     RECT  52.02 28.561 52.758 28.715 ;
     RECT  99.108 28.291 101.178 28.715 ;
     RECT  52.128 28.715 52.758 28.759 ;
     RECT  3.996 28.789 4.374 28.831 ;
     RECT  52.128 28.759 53.118 28.921 ;
     RECT  3.996 28.831 4.518 28.985 ;
     RECT  52.128 28.921 53.406 28.985 ;
     RECT  74.916 28.651 74.934 29.101 ;
     RECT  99.108 28.715 101.034 29.101 ;
     RECT  2.415 28.409 2.697 29.131 ;
     RECT  9.288 28.417 9.306 29.219 ;
     RECT  74.916 29.101 75.402 29.219 ;
     RECT  99 29.101 101.034 29.219 ;
     RECT  78.015 17.519 78.297 29.227 ;
     RECT  74.916 29.219 75.222 29.255 ;
     RECT  78.015 29.227 78.642 29.327 ;
     RECT  98.1 28.561 98.262 29.335 ;
     RECT  98.1 29.335 98.874 29.371 ;
     RECT  5.292 28.831 5.31 29.399 ;
     RECT  50.112 28.831 50.13 29.461 ;
     RECT  48.744 29.371 48.762 29.489 ;
     RECT  97.92 29.371 98.874 29.525 ;
     RECT  2.304 29.131 2.697 29.563 ;
     RECT  46.764 28.525 46.782 29.597 ;
     RECT  99.615 29.219 101.034 29.605 ;
     RECT  50.004 29.461 50.13 29.641 ;
     RECT  51.015 28.445 51.297 29.641 ;
     RECT  96.192 29.335 96.21 29.645 ;
     RECT  98.244 29.525 98.874 29.645 ;
     RECT  49.968 29.641 51.297 29.755 ;
     RECT  99.615 29.605 101.214 29.759 ;
     RECT  2.304 29.563 3.006 29.795 ;
     RECT  4.536 29.605 4.554 29.795 ;
     RECT  49.824 29.755 51.297 29.795 ;
     RECT  50.004 29.795 51.297 29.875 ;
     RECT  52.128 28.985 52.146 29.875 ;
     RECT  53.064 28.985 53.406 29.911 ;
     RECT  97.164 29.371 97.182 29.995 ;
     RECT  5.652 29.461 5.706 30.001 ;
     RECT  2.304 29.795 2.697 30.065 ;
     RECT  52.92 29.911 53.406 30.065 ;
     RECT  97.164 29.995 97.362 30.065 ;
     RECT  55.26 26.087 55.278 30.073 ;
     RECT  74.376 30.037 74.394 30.073 ;
     RECT  99.615 29.759 101.034 30.109 ;
     RECT  5.652 30.001 6.246 30.136 ;
     RECT  50.004 29.875 52.146 30.145 ;
     RECT  53.316 30.065 53.406 30.145 ;
     RECT  5.652 30.136 6.75 30.173 ;
     RECT  4.788 29.911 4.806 30.181 ;
     RECT  5.652 30.173 6.606 30.181 ;
     RECT  7.815 28.445 8.097 30.181 ;
     RECT  102.564 28.493 102.582 30.187 ;
     RECT  54.792 30.073 55.278 30.209 ;
     RECT  94.215 28.139 94.497 30.271 ;
     RECT  94.215 30.271 94.662 30.283 ;
     RECT  4.788 30.181 6.606 30.299 ;
     RECT  50.004 30.145 52.542 30.299 ;
     RECT  53.316 30.145 53.478 30.299 ;
     RECT  4.788 30.299 5.526 30.335 ;
     RECT  50.004 30.299 52.47 30.335 ;
     RECT  53.316 30.299 53.334 30.335 ;
     RECT  74.376 30.073 74.466 30.335 ;
     RECT  94.215 30.283 95.202 30.335 ;
     RECT  99.324 30.109 101.034 30.335 ;
     RECT  74.448 30.335 74.466 30.343 ;
     RECT  74.448 30.343 75.114 30.371 ;
     RECT  98.244 29.645 98.586 30.379 ;
     RECT  99.324 30.335 100.962 30.379 ;
     RECT  102.024 30.187 102.582 30.407 ;
     RECT  74.556 30.371 75.114 30.443 ;
     RECT  96.912 30.181 96.93 30.451 ;
     RECT  6.588 30.299 6.606 30.479 ;
     RECT  90.648 30.343 90.666 30.479 ;
     RECT  49.176 30.451 49.194 30.569 ;
     RECT  96.12 30.451 96.93 30.569 ;
     RECT  98.244 30.379 100.962 30.569 ;
     RECT  96.12 30.569 96.138 30.605 ;
     RECT  96.912 30.569 96.93 30.677 ;
     RECT  98.244 30.569 100.062 30.677 ;
     RECT  50.004 30.335 51.858 30.721 ;
     RECT  49.248 30.721 51.858 30.845 ;
     RECT  3.816 30.721 3.834 30.875 ;
     RECT  7.668 30.181 8.097 30.875 ;
     RECT  5.508 30.335 5.526 30.911 ;
     RECT  49.248 30.845 49.77 30.911 ;
     RECT  98.244 30.677 98.37 30.949 ;
     RECT  4.572 30.685 4.734 30.991 ;
     RECT  49.392 30.911 49.77 31.109 ;
     RECT  98.208 30.949 98.37 31.109 ;
     RECT  4.284 30.991 4.734 31.145 ;
     RECT  74.556 30.443 74.934 31.145 ;
     RECT  99.144 30.677 100.062 31.145 ;
     RECT  4.356 31.145 4.734 31.225 ;
     RECT  50.796 30.845 51.858 31.225 ;
     RECT  100.944 30.569 100.962 31.225 ;
     RECT  4.356 31.225 5.274 31.253 ;
     RECT  49.392 31.109 49.41 31.253 ;
     RECT  50.796 31.225 52.47 31.261 ;
     RECT  53.316 31.189 53.334 31.261 ;
     RECT  2.412 30.065 2.697 31.291 ;
     RECT  99.504 31.145 100.062 31.351 ;
     RECT  100.944 31.225 101.07 31.351 ;
     RECT  6.084 31.261 6.102 31.379 ;
     RECT  50.796 31.261 53.334 31.379 ;
     RECT  99.504 31.351 101.07 31.379 ;
     RECT  99.504 31.379 100.422 31.451 ;
     RECT  75.312 31.351 75.33 31.531 ;
     RECT  98.208 31.109 98.262 31.531 ;
     RECT  50.796 31.379 52.974 31.559 ;
     RECT  78.015 29.327 78.297 31.621 ;
     RECT  47.916 31.387 47.934 31.649 ;
     RECT  75.312 31.531 75.51 31.649 ;
     RECT  97.02 31.495 97.038 31.661 ;
     RECT  4.356 31.253 4.374 31.685 ;
     RECT  74.556 31.145 74.574 31.685 ;
     RECT  75.312 31.649 75.33 31.685 ;
     RECT  97.956 31.531 98.262 31.685 ;
     RECT  94.215 30.335 94.662 31.793 ;
     RECT  5.112 31.253 5.274 31.801 ;
     RECT  78.015 31.621 78.642 31.829 ;
     RECT  50.796 31.559 52.326 31.915 ;
     RECT  5.112 31.801 5.706 31.955 ;
     RECT  98.136 31.685 98.262 31.955 ;
     RECT  99.504 31.451 100.134 31.955 ;
     RECT  7.815 30.875 8.097 32.035 ;
     RECT  50.652 31.915 52.326 32.063 ;
     RECT  2.304 31.291 2.697 32.225 ;
     RECT  7.815 32.035 8.478 32.333 ;
     RECT  2.415 32.225 2.697 32.341 ;
     RECT  99.615 31.955 100.134 32.341 ;
     RECT  101.16 32.305 101.178 32.341 ;
     RECT  102.564 30.407 102.582 32.341 ;
     RECT  102.528 32.341 102.582 32.381 ;
     RECT  4.248 32.431 4.266 32.443 ;
     RECT  5.112 31.955 5.31 32.443 ;
     RECT  2.415 32.341 3.33 32.459 ;
     RECT  74.268 32.197 74.286 32.495 ;
     RECT  4.248 32.443 5.31 32.611 ;
     RECT  6.84 32.443 6.858 32.611 ;
     RECT  0.108 32.467 0.126 32.621 ;
     RECT  9.396 31.891 9.414 32.639 ;
     RECT  94.215 31.793 94.497 32.701 ;
     RECT  48.24 31.801 48.258 32.728 ;
     RECT  3.96 32.611 5.31 32.729 ;
     RECT  48.096 32.728 48.258 32.729 ;
     RECT  49.104 32.611 49.122 32.729 ;
     RECT  97.056 32.611 97.254 32.729 ;
     RECT  99.615 32.341 101.178 32.729 ;
     RECT  50.724 32.063 52.326 32.737 ;
     RECT  3.96 32.729 5.13 32.765 ;
     RECT  48.096 32.729 48.114 32.765 ;
     RECT  97.056 32.729 97.074 32.765 ;
     RECT  99.615 32.729 101.142 32.809 ;
     RECT  50.724 32.737 52.398 32.873 ;
     RECT  6.3 32.611 6.858 32.881 ;
     RECT  49.176 32.731 49.338 32.881 ;
     RECT  6.228 32.881 6.858 32.971 ;
     RECT  4.248 32.765 5.13 32.999 ;
     RECT  46.764 32.881 46.782 32.999 ;
     RECT  98.244 31.955 98.262 33.007 ;
     RECT  99.072 32.809 101.142 33.007 ;
     RECT  4.248 32.999 4.266 33.035 ;
     RECT  102.564 32.381 102.582 33.211 ;
     RECT  49.176 32.881 49.41 33.241 ;
     RECT  6.192 32.971 6.858 33.269 ;
     RECT  5.112 32.999 5.13 33.305 ;
     RECT  97.812 33.007 101.142 33.305 ;
     RECT  99 33.305 101.142 33.341 ;
     RECT  49.176 33.241 49.662 33.421 ;
     RECT  2.415 32.459 2.697 33.451 ;
     RECT  52.02 32.873 52.398 33.511 ;
     RECT  72.615 26.555 72.897 33.511 ;
     RECT  95.94 31.627 95.958 33.511 ;
     RECT  97.812 33.305 98.262 33.583 ;
     RECT  49.176 33.421 49.878 33.595 ;
     RECT  50.724 32.873 51.297 33.595 ;
     RECT  94.215 32.701 94.662 33.611 ;
     RECT  95.94 33.511 96.138 33.643 ;
     RECT  97.596 33.583 98.262 33.643 ;
     RECT  95.58 33.643 96.138 33.677 ;
     RECT  49.176 33.595 51.297 33.691 ;
     RECT  52.02 33.511 52.542 33.691 ;
     RECT  72.615 33.511 73.53 33.691 ;
     RECT  97.38 33.643 98.262 33.739 ;
     RECT  72.615 33.691 73.854 33.809 ;
     RECT  97.056 33.739 98.262 33.809 ;
     RECT  49.176 33.691 52.542 33.845 ;
     RECT  71.82 33.547 71.838 33.845 ;
     RECT  101.16 33.781 101.178 33.881 ;
     RECT  6.84 33.269 6.858 33.961 ;
     RECT  7.815 32.333 8.097 33.961 ;
     RECT  49.176 33.845 51.858 33.961 ;
     RECT  48.744 33.961 51.858 33.989 ;
     RECT  95.58 33.677 95.598 34.051 ;
     RECT  102.024 33.211 102.582 34.075 ;
     RECT  6.84 33.961 8.097 34.079 ;
     RECT  48.744 33.989 49.338 34.079 ;
     RECT  95.508 34.051 95.598 34.079 ;
     RECT  49.32 34.079 49.338 34.115 ;
     RECT  73.836 33.809 73.854 34.115 ;
     RECT  97.272 33.809 98.262 34.115 ;
     RECT  101.988 34.075 102.582 34.115 ;
     RECT  4.536 34.087 4.554 34.123 ;
     RECT  95.508 34.079 95.526 34.151 ;
     RECT  99 33.341 100.278 34.159 ;
     RECT  98.064 34.115 98.262 34.171 ;
     RECT  99 34.159 101.034 34.171 ;
     RECT  4.536 34.123 4.626 34.231 ;
     RECT  5.472 33.961 5.49 34.231 ;
     RECT  4.284 34.231 4.626 34.321 ;
     RECT  76.248 34.231 76.266 34.349 ;
     RECT  53.1 33.961 53.118 34.385 ;
     RECT  97.272 34.115 97.29 34.385 ;
     RECT  46.764 34.231 46.782 34.457 ;
     RECT  98.064 34.171 101.034 34.493 ;
     RECT  4.212 34.321 4.626 34.501 ;
     RECT  5.472 34.231 5.526 34.591 ;
     RECT  4.032 34.501 4.626 34.619 ;
     RECT  50.328 33.989 51.858 34.655 ;
     RECT  99 34.493 101.034 34.735 ;
     RECT  75.492 34.627 75.51 34.771 ;
     RECT  4.032 34.619 4.554 34.829 ;
     RECT  5.472 34.591 5.886 34.889 ;
     RECT  50.472 34.655 51.858 34.889 ;
     RECT  53.928 34.501 53.946 34.889 ;
     RECT  75.312 34.771 75.51 34.889 ;
     RECT  99 34.735 101.214 34.889 ;
     RECT  75.312 34.889 75.33 34.925 ;
     RECT  99 34.889 101.178 34.925 ;
     RECT  50.76 34.889 51.858 35.041 ;
     RECT  55.26 30.209 55.278 35.041 ;
     RECT  5.472 34.889 5.562 35.069 ;
     RECT  49.428 35.041 49.446 35.159 ;
     RECT  53.748 35.005 53.766 35.165 ;
     RECT  3.96 35.041 3.978 35.195 ;
     RECT  6.84 34.079 6.858 35.195 ;
     RECT  50.76 35.041 51.93 35.195 ;
     RECT  54.72 35.041 55.278 35.195 ;
     RECT  99.216 34.925 100.242 35.195 ;
     RECT  7.815 34.079 8.097 35.311 ;
     RECT  102.564 34.115 102.582 35.311 ;
     RECT  98.064 34.493 98.262 35.357 ;
     RECT  58.5 8.671 58.518 35.401 ;
     RECT  102.564 35.311 102.618 35.405 ;
     RECT  74.952 35.167 74.97 35.429 ;
     RECT  5.544 35.069 5.562 35.465 ;
     RECT  50.796 35.195 51.93 35.581 ;
     RECT  52.668 35.311 52.686 35.581 ;
     RECT  58.5 35.401 58.698 35.609 ;
     RECT  7.776 35.311 8.097 35.699 ;
     RECT  8.928 35.581 9.018 35.699 ;
     RECT  50.796 35.581 52.686 35.735 ;
     RECT  54.792 35.195 55.278 35.735 ;
     RECT  99.216 35.195 99.897 35.735 ;
     RECT  94.215 33.611 94.497 35.947 ;
     RECT  8.928 35.699 8.946 36.005 ;
     RECT  53.388 35.851 53.694 36.005 ;
     RECT  74.124 35.401 74.142 36.005 ;
     RECT  94.215 35.947 94.59 36.077 ;
     RECT  3.816 35.947 3.834 36.121 ;
     RECT  50.796 35.735 51.297 36.121 ;
     RECT  101.088 34.925 101.178 36.121 ;
     RECT  74.664 36.049 74.862 36.149 ;
     RECT  90.648 36.049 90.666 36.149 ;
     RECT  102.564 35.405 102.582 36.235 ;
     RECT  100.728 36.121 101.178 36.239 ;
     RECT  53.64 36.005 53.694 36.275 ;
     RECT  95.22 36.121 95.238 36.275 ;
     RECT  52.02 35.735 52.614 36.311 ;
     RECT  99.288 35.735 99.897 36.355 ;
     RECT  100.728 36.239 100.926 36.355 ;
     RECT  2.304 33.451 2.697 36.391 ;
     RECT  3.564 36.121 3.978 36.391 ;
     RECT  49.572 36.121 49.59 36.475 ;
     RECT  76.356 36.391 76.374 36.481 ;
     RECT  98.244 35.357 98.262 36.481 ;
     RECT  53.676 36.275 53.694 36.509 ;
     RECT  98.1 36.481 98.262 36.517 ;
     RECT  2.304 36.391 3.978 36.545 ;
     RECT  50.724 36.121 51.297 36.553 ;
     RECT  46.8 36.481 46.818 36.581 ;
     RECT  75.852 36.481 76.374 36.617 ;
     RECT  4.752 36.121 4.77 36.625 ;
     RECT  5.868 36.475 5.886 36.625 ;
     RECT  98.028 36.517 98.262 36.625 ;
     RECT  99.288 36.355 100.926 36.625 ;
     RECT  75.852 36.617 76.05 36.653 ;
     RECT  49.5 36.475 49.59 36.661 ;
     RECT  6.84 36.589 6.858 36.689 ;
     RECT  76.032 36.653 76.05 36.689 ;
     RECT  98.028 36.625 100.926 36.751 ;
     RECT  97.92 36.751 100.926 36.763 ;
     RECT  2.415 36.545 3.978 36.779 ;
     RECT  4.752 36.625 5.886 36.779 ;
     RECT  5.868 36.779 5.886 36.815 ;
     RECT  74.664 36.149 74.682 36.815 ;
     RECT  7.815 35.699 8.097 36.907 ;
     RECT  3.42 36.779 3.978 36.931 ;
     RECT  49.5 36.661 49.95 36.931 ;
     RECT  50.724 36.553 51.93 36.931 ;
     RECT  102.024 36.235 102.582 36.959 ;
     RECT  3.42 36.931 4.014 37.021 ;
     RECT  6.804 36.931 6.822 37.021 ;
     RECT  102.564 36.959 102.582 37.021 ;
     RECT  6.012 36.931 6.03 37.049 ;
     RECT  7.815 36.907 8.442 37.049 ;
     RECT  49.5 36.931 51.93 37.049 ;
     RECT  97.848 36.763 100.926 37.049 ;
     RECT  102.564 37.021 102.618 37.133 ;
     RECT  6.768 37.021 6.822 37.193 ;
     RECT  7.815 37.049 8.37 37.229 ;
     RECT  6.768 37.193 6.786 37.319 ;
     RECT  101.016 37.165 101.142 37.319 ;
     RECT  52.704 37.471 52.722 37.561 ;
     RECT  96.408 37.561 96.426 37.579 ;
     RECT  3.42 37.021 4.59 37.589 ;
     RECT  96.408 37.579 96.498 37.625 ;
     RECT  96.408 37.625 96.426 37.733 ;
     RECT  3.924 37.589 4.59 37.741 ;
     RECT  73.836 37.561 73.854 37.741 ;
     RECT  2.415 36.779 2.697 37.771 ;
     RECT  49.932 37.049 51.93 37.831 ;
     RECT  52.704 37.561 52.974 37.831 ;
     RECT  73.62 37.741 73.854 37.859 ;
     RECT  101.016 37.319 101.034 37.859 ;
     RECT  2.304 37.771 2.697 37.895 ;
     RECT  49.932 37.831 53.118 37.895 ;
     RECT  73.62 37.859 73.638 37.895 ;
     RECT  98.244 37.049 100.278 37.895 ;
     RECT  55.26 35.735 55.278 37.903 ;
     RECT  97.488 37.561 97.506 37.975 ;
     RECT  98.244 37.895 100.062 37.975 ;
     RECT  54.684 37.903 55.278 38.003 ;
     RECT  70.776 37.903 70.794 38.011 ;
     RECT  6.264 37.975 6.282 38.107 ;
     RECT  49.932 37.895 52.254 38.129 ;
     RECT  74.664 38.011 74.826 38.129 ;
     RECT  3.924 37.741 4.878 38.137 ;
     RECT  3.924 38.137 5.346 38.165 ;
     RECT  70.704 38.011 70.794 38.165 ;
     RECT  5.328 38.165 5.346 38.189 ;
     RECT  46.764 37.165 46.782 38.201 ;
     RECT  0.108 38.137 0.126 38.237 ;
     RECT  6.264 38.107 6.426 38.281 ;
     RECT  7.815 37.229 8.097 38.281 ;
     RECT  102.564 37.133 102.582 38.395 ;
     RECT  6.228 38.281 6.426 38.399 ;
     RECT  75.708 38.281 75.726 38.399 ;
     RECT  4.536 38.165 4.554 38.435 ;
     RECT  74.664 38.129 74.682 38.435 ;
     RECT  50.004 38.129 52.254 38.579 ;
     RECT  2.415 37.895 2.697 38.635 ;
     RECT  2.304 38.635 2.697 38.705 ;
     RECT  54.72 38.003 55.278 38.741 ;
     RECT  97.488 37.975 100.062 38.749 ;
     RECT  97.236 38.749 100.062 38.777 ;
     RECT  50.472 38.579 52.254 38.821 ;
     RECT  52.992 37.895 53.118 38.821 ;
     RECT  98.172 38.777 100.062 38.821 ;
     RECT  101.16 38.371 101.178 38.821 ;
     RECT  7.344 38.281 8.097 38.849 ;
     RECT  3.6 38.641 3.618 38.939 ;
     RECT  6.408 38.399 6.426 38.939 ;
     RECT  50.472 38.821 53.73 38.939 ;
     RECT  75.564 38.677 75.582 38.975 ;
     RECT  98.172 38.821 101.178 39.011 ;
     RECT  97.236 38.777 97.254 39.101 ;
     RECT  6.516 39.091 6.534 39.209 ;
     RECT  70.704 39.091 70.722 39.209 ;
     RECT  102.528 38.395 102.582 39.209 ;
     RECT  5.22 39.091 5.238 39.245 ;
     RECT  50.508 38.939 53.73 39.245 ;
     RECT  74.448 38.641 74.646 39.245 ;
     RECT  53.244 39.245 53.73 39.281 ;
     RECT  74.556 39.245 74.646 39.281 ;
     RECT  3.708 39.163 4.23 39.361 ;
     RECT  53.424 39.281 53.73 39.361 ;
     RECT  53.424 39.361 54.162 39.479 ;
     RECT  76.968 39.361 76.986 39.479 ;
     RECT  95.76 39.253 95.778 39.479 ;
     RECT  2.415 38.705 2.697 39.487 ;
     RECT  3.708 39.361 4.374 39.515 ;
     RECT  75.816 39.181 75.834 39.515 ;
     RECT  2.415 39.487 2.79 39.533 ;
     RECT  98.172 39.011 100.746 39.631 ;
     RECT  98.136 39.631 100.746 39.632 ;
     RECT  5.184 39.289 5.202 39.659 ;
     RECT  50.508 39.245 52.434 39.721 ;
     RECT  49.464 39.091 49.482 39.739 ;
     RECT  50.436 39.721 52.434 39.749 ;
     RECT  98.136 39.632 98.55 39.749 ;
     RECT  99.432 39.632 100.746 39.749 ;
     RECT  4.14 39.515 4.374 39.785 ;
     RECT  97.2 39.631 97.218 39.785 ;
     RECT  49.464 39.739 49.518 39.857 ;
     RECT  99.468 39.749 100.746 39.865 ;
     RECT  96.264 39.595 96.282 39.883 ;
     RECT  7.815 38.849 8.097 39.901 ;
     RECT  4.212 39.785 4.374 39.917 ;
     RECT  96.264 39.883 96.642 39.917 ;
     RECT  2.415 39.533 2.697 39.931 ;
     RECT  50.436 39.749 51.297 39.991 ;
     RECT  99.468 39.865 101.034 40.019 ;
     RECT  99.468 40.019 100.818 40.091 ;
     RECT  53.424 39.479 53.91 40.127 ;
     RECT  7.488 39.901 8.097 40.171 ;
     RECT  50.04 39.991 51.297 40.289 ;
     RECT  4.824 40.171 4.842 40.325 ;
     RECT  53.424 40.127 53.838 40.325 ;
     RECT  75.24 39.721 75.258 40.325 ;
     RECT  99.468 40.091 100.062 40.325 ;
     RECT  50.112 40.289 51.297 40.361 ;
     RECT  6.48 40.171 6.642 40.405 ;
     RECT  7.416 40.171 8.097 40.405 ;
     RECT  6.48 40.405 8.097 40.433 ;
     RECT  7.056 40.433 8.097 40.441 ;
     RECT  52.2 39.749 52.434 40.441 ;
     RECT  7.056 40.441 8.154 40.445 ;
     RECT  96.624 39.917 96.642 40.445 ;
     RECT  55.26 38.741 55.278 40.459 ;
     RECT  56.415 2.413 56.697 40.555 ;
     RECT  57.564 9.013 57.582 40.555 ;
     RECT  6.228 40.441 6.246 40.559 ;
     RECT  5.364 40.441 5.382 40.595 ;
     RECT  7.416 40.445 8.154 40.829 ;
     RECT  55.26 40.459 55.566 40.829 ;
     RECT  72.615 33.809 72.897 40.873 ;
     RECT  56.415 40.555 57.582 40.877 ;
     RECT  53.82 40.325 53.838 40.945 ;
     RECT  100.8 40.091 100.818 40.945 ;
     RECT  53.82 40.945 53.982 40.981 ;
     RECT  3.564 40.981 3.582 41.035 ;
     RECT  99.54 40.325 100.062 41.071 ;
     RECT  100.8 40.945 101.178 41.071 ;
     RECT  102.564 39.209 102.582 41.099 ;
     RECT  7.815 40.829 8.154 41.135 ;
     RECT  53.82 40.981 54.306 41.135 ;
     RECT  72.396 40.873 72.897 41.135 ;
     RECT  99.54 41.071 101.178 41.135 ;
     RECT  50.436 40.361 51.297 41.215 ;
     RECT  2.304 39.931 2.697 41.251 ;
     RECT  3.564 41.035 3.906 41.251 ;
     RECT  50.184 41.215 51.297 41.251 ;
     RECT  52.2 40.441 53.046 41.251 ;
     RECT  98.244 39.749 98.55 41.251 ;
     RECT  2.304 41.251 4.05 41.261 ;
     RECT  46.764 41.107 46.782 41.279 ;
     RECT  95.796 41.251 95.814 41.309 ;
     RECT  2.415 41.261 4.05 41.369 ;
     RECT  50.184 41.251 53.226 41.369 ;
     RECT  98.244 41.251 98.586 41.369 ;
     RECT  99.612 41.135 101.178 41.369 ;
     RECT  2.415 41.369 3.582 41.405 ;
     RECT  50.184 41.369 53.046 41.405 ;
     RECT  96.732 41.251 97.038 41.405 ;
     RECT  54.144 41.135 54.306 41.521 ;
     RECT  54.144 41.521 54.378 41.647 ;
     RECT  2.415 41.405 3.402 41.675 ;
     RECT  54.144 41.647 54.522 41.683 ;
     RECT  55.26 40.829 55.278 41.683 ;
     RECT  98.244 41.369 98.262 41.735 ;
     RECT  50.184 41.405 52.614 41.747 ;
     RECT  97.38 41.521 97.47 41.789 ;
     RECT  102.024 41.419 102.042 41.851 ;
     RECT  94.215 36.077 94.497 41.881 ;
     RECT  5.904 41.791 5.922 41.909 ;
     RECT  48.996 41.611 49.014 41.909 ;
     RECT  2.415 41.675 3.33 41.945 ;
     RECT  54.144 41.683 55.278 41.945 ;
     RECT  74.664 41.683 74.682 41.945 ;
     RECT  72.615 41.135 72.897 41.953 ;
     RECT  99.612 41.369 101.034 41.989 ;
     RECT  54.252 41.945 55.278 42.053 ;
     RECT  50.184 41.747 51.93 42.061 ;
     RECT  2.415 41.945 3.186 42.091 ;
     RECT  4.572 41.611 4.59 42.173 ;
     RECT  49.932 42.061 51.93 42.179 ;
     RECT  54.252 42.053 54.522 42.215 ;
     RECT  74.628 42.331 74.646 42.449 ;
     RECT  96.912 42.331 96.93 42.449 ;
     RECT  5.364 42.151 5.382 42.485 ;
     RECT  72.615 41.953 73.566 42.485 ;
     RECT  94.215 41.881 94.662 42.565 ;
     RECT  99.18 41.989 101.034 42.565 ;
     RECT  94.215 42.565 95.022 42.601 ;
     RECT  98.208 41.735 98.262 42.601 ;
     RECT  99.18 42.565 101.178 42.601 ;
     RECT  49.932 42.179 49.95 42.691 ;
     RECT  49.788 42.691 49.95 42.719 ;
     RECT  54.504 42.215 54.522 42.719 ;
     RECT  94.215 42.601 95.202 42.719 ;
     RECT  49.788 42.719 49.806 42.749 ;
     RECT  94.215 42.719 95.022 42.749 ;
     RECT  96.732 42.565 96.75 42.749 ;
     RECT  102.024 41.851 102.582 42.749 ;
     RECT  95.976 42.601 95.994 42.755 ;
     RECT  97.704 42.601 101.178 42.755 ;
     RECT  2.304 42.091 3.186 42.961 ;
     RECT  96.048 42.871 96.066 42.989 ;
     RECT  2.304 42.961 3.258 43.025 ;
     RECT  2.415 43.025 3.258 43.105 ;
     RECT  2.415 43.105 3.978 43.141 ;
     RECT  50.724 42.179 51.93 43.141 ;
     RECT  52.956 42.871 52.974 43.141 ;
     RECT  7.02 42.187 7.038 43.231 ;
     RECT  2.415 43.141 4.698 43.259 ;
     RECT  6.84 43.231 7.038 43.259 ;
     RECT  2.415 43.259 4.662 43.295 ;
     RECT  50.724 43.141 52.974 43.325 ;
     RECT  5.472 43.291 5.49 43.331 ;
     RECT  98.244 42.755 101.178 43.331 ;
     RECT  6.84 43.259 7.002 43.339 ;
     RECT  50.724 43.325 51.297 43.367 ;
     RECT  52.2 43.325 52.974 43.375 ;
     RECT  98.244 43.331 100.746 43.483 ;
     RECT  4.644 43.295 4.662 43.529 ;
     RECT  49.752 43.411 49.77 43.529 ;
     RECT  50.832 43.367 51.297 43.529 ;
     RECT  74.34 43.411 74.358 43.537 ;
     RECT  94.215 42.749 94.497 43.537 ;
     RECT  50.94 43.529 51.297 43.601 ;
     RECT  6.336 43.339 7.002 43.673 ;
     RECT  52.2 43.375 53.046 43.681 ;
     RECT  74.34 43.537 74.538 43.709 ;
     RECT  6.516 43.673 7.002 43.799 ;
     RECT  48.78 43.537 48.798 43.799 ;
     RECT  2.415 43.295 3.87 43.835 ;
     RECT  52.2 43.681 53.19 43.835 ;
     RECT  97.74 43.483 100.746 43.835 ;
     RECT  50.976 43.601 51.297 43.853 ;
     RECT  102.564 42.749 102.582 44.011 ;
     RECT  52.2 43.835 52.866 44.069 ;
     RECT  102.528 44.011 102.582 44.069 ;
     RECT  52.2 44.069 52.722 44.105 ;
     RECT  6.984 43.799 7.002 44.221 ;
     RECT  7.815 41.135 8.097 44.221 ;
     RECT  94.215 43.537 94.662 44.221 ;
     RECT  2.415 43.835 3.006 44.251 ;
     RECT  6.984 44.221 8.154 44.339 ;
     RECT  73.908 43.771 74.106 44.339 ;
     RECT  94.215 44.221 94.77 44.339 ;
     RECT  98.244 43.835 100.746 44.339 ;
     RECT  3.96 44.221 3.978 44.375 ;
     RECT  73.908 44.339 73.926 44.375 ;
     RECT  5.58 43.622 5.598 44.455 ;
     RECT  51.015 43.853 51.297 44.455 ;
     RECT  52.2 44.105 52.47 44.455 ;
     RECT  48.888 43.843 48.906 44.491 ;
     RECT  95.868 44.383 95.886 44.491 ;
     RECT  7.815 44.339 8.154 44.519 ;
     RECT  48.888 44.491 49.014 44.581 ;
     RECT  49.86 43.681 49.878 44.581 ;
     RECT  99.615 44.339 100.746 44.581 ;
     RECT  5.256 44.455 5.598 44.609 ;
     RECT  95.868 44.491 96.102 44.609 ;
     RECT  95.868 44.609 95.886 44.645 ;
     RECT  97.488 44.419 97.506 44.645 ;
     RECT  48.888 44.581 49.878 44.717 ;
     RECT  2.304 44.251 3.006 44.753 ;
     RECT  2.412 44.753 3.006 44.761 ;
     RECT  51.015 44.455 52.47 44.761 ;
     RECT  102.564 44.069 102.582 44.875 ;
     RECT  98.244 44.339 98.838 44.879 ;
     RECT  2.412 44.761 3.366 44.915 ;
     RECT  50.832 44.761 52.47 44.915 ;
     RECT  75.78 44.581 75.798 44.915 ;
     RECT  48.996 44.717 49.878 44.971 ;
     RECT  50.832 44.915 51.822 44.971 ;
     RECT  6.984 44.339 7.002 45.031 ;
     RECT  6.552 45.031 7.002 45.149 ;
     RECT  75.996 45.031 76.014 45.149 ;
     RECT  98.244 44.879 98.658 45.149 ;
     RECT  2.412 44.915 3.15 45.185 ;
     RECT  6.984 45.149 7.002 45.185 ;
     RECT  52.668 44.995 53.01 45.185 ;
     RECT  4.14 44.761 4.482 45.301 ;
     RECT  5.472 44.609 5.598 45.301 ;
     RECT  7.815 44.519 8.097 45.301 ;
     RECT  99.615 44.581 101.178 45.301 ;
     RECT  2.415 45.185 3.15 45.329 ;
     RECT  48.996 44.971 51.822 45.329 ;
     RECT  98.244 45.149 98.514 45.341 ;
     RECT  7.164 45.301 8.097 45.419 ;
     RECT  48.996 45.329 49.23 45.419 ;
     RECT  52.668 45.185 52.938 45.419 ;
     RECT  4.14 45.301 4.59 45.455 ;
     RECT  50.184 45.329 51.822 45.455 ;
     RECT  99.432 45.301 101.214 45.455 ;
     RECT  5.472 45.301 5.778 45.599 ;
     RECT  102.024 44.875 102.582 45.599 ;
     RECT  55.26 42.053 55.278 45.661 ;
     RECT  74.124 45.391 74.142 45.661 ;
     RECT  49.068 45.419 49.23 45.689 ;
     RECT  49.068 45.689 49.086 45.725 ;
     RECT  54.72 45.661 55.278 45.797 ;
     RECT  4.14 45.455 4.302 45.841 ;
     RECT  51.015 45.455 51.822 45.841 ;
     RECT  3.636 45.841 4.302 45.959 ;
     RECT  75.06 45.841 75.078 45.959 ;
     RECT  97.02 45.841 97.038 45.959 ;
     RECT  2.415 45.329 2.697 45.967 ;
     RECT  51.015 45.841 52.002 45.995 ;
     RECT  52.776 45.419 52.938 45.995 ;
     RECT  73.692 45.661 74.142 45.995 ;
     RECT  6.228 45.967 6.246 46.069 ;
     RECT  98.244 45.341 98.262 46.111 ;
     RECT  99.432 45.455 101.07 46.111 ;
     RECT  96.84 46.075 96.858 46.205 ;
     RECT  50.184 45.455 50.202 46.219 ;
     RECT  51.015 45.995 51.39 46.219 ;
     RECT  3.708 45.959 4.302 46.229 ;
     RECT  7.344 45.419 8.097 46.229 ;
     RECT  53.172 46.111 53.19 46.229 ;
     RECT  95.256 46.171 95.274 46.229 ;
     RECT  3.708 46.229 3.906 46.265 ;
     RECT  50.184 46.219 51.39 46.265 ;
     RECT  73.692 45.995 73.89 46.265 ;
     RECT  98.244 46.111 101.07 46.265 ;
     RECT  70.704 46.201 70.722 46.337 ;
     RECT  73.872 46.265 73.89 46.337 ;
     RECT  99.108 46.265 101.07 46.345 ;
     RECT  74.664 46.309 74.682 46.409 ;
     RECT  90.648 46.309 90.666 46.409 ;
     RECT  76.392 46.201 76.41 46.535 ;
     RECT  96.192 46.381 96.21 46.535 ;
     RECT  2.304 45.967 2.697 46.651 ;
     RECT  6.228 46.069 6.426 46.741 ;
     RECT  2.304 46.651 2.862 46.769 ;
     RECT  50.4 46.265 51.39 46.805 ;
     RECT  52.416 46.381 52.434 46.805 ;
     RECT  5.076 45.841 5.274 46.849 ;
     RECT  6.228 46.741 6.534 46.849 ;
     RECT  94.215 44.339 94.497 46.849 ;
     RECT  76.572 46.651 76.59 46.877 ;
     RECT  50.724 46.805 51.39 46.885 ;
     RECT  50.724 46.885 51.534 46.921 ;
     RECT  97.164 46.747 97.182 46.921 ;
     RECT  98.244 46.265 98.262 46.921 ;
     RECT  52.596 46.921 52.614 47.011 ;
     RECT  97.164 46.921 97.362 47.039 ;
     RECT  3.888 46.265 3.906 47.075 ;
     RECT  52.596 47.011 53.226 47.075 ;
     RECT  74.052 46.849 74.07 47.075 ;
     RECT  98.136 46.921 98.262 47.075 ;
     RECT  99.108 46.345 101.178 47.075 ;
     RECT  99.504 47.075 101.178 47.147 ;
     RECT  5.076 46.849 6.534 47.191 ;
     RECT  72.615 42.485 72.897 47.191 ;
     RECT  98.244 47.075 98.262 47.281 ;
     RECT  102.564 45.599 102.582 47.281 ;
     RECT  5.076 47.191 6.822 47.309 ;
     RECT  48.852 46.777 48.87 47.309 ;
     RECT  3.996 47.191 4.014 47.345 ;
     RECT  50.724 46.921 51.606 47.345 ;
     RECT  53.208 47.075 53.226 47.345 ;
     RECT  49.644 47.317 49.662 47.357 ;
     RECT  6.228 47.309 6.822 47.461 ;
     RECT  7.815 46.229 8.097 47.461 ;
     RECT  94.215 46.849 94.662 47.467 ;
     RECT  96.48 47.425 96.642 47.501 ;
     RECT  102.564 47.281 102.618 47.501 ;
     RECT  6.228 47.461 8.097 47.579 ;
     RECT  96.624 47.501 96.642 47.579 ;
     RECT  4.536 47.461 4.554 47.615 ;
     RECT  75.096 47.281 75.114 47.615 ;
     RECT  50.724 47.345 51.297 47.695 ;
     RECT  6.804 47.579 8.097 47.723 ;
     RECT  6.804 47.723 6.822 47.759 ;
     RECT  2.304 46.769 2.697 47.821 ;
     RECT  49.932 47.695 51.297 47.849 ;
     RECT  72.615 47.191 73.206 47.885 ;
     RECT  94.215 47.467 94.77 47.885 ;
     RECT  94.215 47.885 94.698 47.993 ;
     RECT  98.244 47.281 98.658 48.043 ;
     RECT  95.76 47.821 95.778 48.155 ;
     RECT  2.304 47.821 2.862 48.271 ;
     RECT  50.58 47.849 51.297 48.271 ;
     RECT  52.2 47.731 52.254 48.271 ;
     RECT  98.244 48.043 98.838 48.271 ;
     RECT  99.576 47.147 101.178 48.271 ;
     RECT  46.764 48.127 46.782 48.299 ;
     RECT  50.58 48.271 52.254 48.361 ;
     RECT  98.244 48.271 101.502 48.365 ;
     RECT  4.248 48.379 4.266 48.425 ;
     RECT  75.888 48.127 75.906 48.425 ;
     RECT  98.244 48.365 101.178 48.425 ;
     RECT  98.244 48.425 101.106 48.497 ;
     RECT  2.304 48.271 3.474 48.541 ;
     RECT  5.004 48.379 5.022 48.541 ;
     RECT  50.58 48.361 52.47 48.541 ;
     RECT  50.58 48.541 52.686 48.619 ;
     RECT  2.304 48.541 4.194 48.659 ;
     RECT  74.772 48.163 74.79 48.667 ;
     RECT  2.304 48.659 3.978 48.695 ;
     RECT  74.772 48.667 74.97 48.695 ;
     RECT  50.4 48.619 52.686 48.811 ;
     RECT  97.452 48.001 97.47 48.811 ;
     RECT  98.244 48.497 98.478 48.811 ;
     RECT  5.004 48.541 5.202 48.839 ;
     RECT  49.752 48.811 52.794 48.929 ;
     RECT  3.888 48.695 3.906 48.965 ;
     RECT  50.148 48.929 52.794 49.081 ;
     RECT  74.952 48.695 74.97 49.171 ;
     RECT  97.452 48.811 98.478 49.207 ;
     RECT  50.148 49.081 53.118 49.235 ;
     RECT  96.768 49.207 98.478 49.235 ;
     RECT  5.94 49.081 5.958 49.351 ;
     RECT  98.244 49.235 98.478 49.351 ;
     RECT  99.324 48.497 101.106 49.351 ;
     RECT  55.26 45.797 55.278 49.441 ;
     RECT  74.952 49.171 75.006 49.441 ;
     RECT  50.148 49.235 51.822 49.469 ;
     RECT  2.304 48.695 2.697 49.505 ;
     RECT  52.884 49.235 53.118 49.505 ;
     RECT  74.88 49.441 75.006 49.505 ;
     RECT  98.244 49.351 101.106 49.505 ;
     RECT  7.815 47.723 8.097 49.531 ;
     RECT  102.564 47.501 102.582 49.549 ;
     RECT  7.815 49.531 8.298 49.577 ;
     RECT  54.684 49.441 55.278 49.577 ;
     RECT  96.768 49.235 96.822 49.577 ;
     RECT  102.564 49.549 102.618 49.661 ;
     RECT  5.004 48.839 5.022 49.711 ;
     RECT  5.94 49.351 5.994 49.711 ;
     RECT  5.004 49.711 5.994 49.747 ;
     RECT  94.215 47.993 94.497 49.747 ;
     RECT  3.564 49.621 3.582 49.775 ;
     RECT  5.004 49.747 6.138 49.811 ;
     RECT  5.436 49.811 6.138 49.891 ;
     RECT  49.212 49.747 49.23 49.891 ;
     RECT  50.148 49.469 50.202 49.891 ;
     RECT  53.208 49.621 53.226 49.891 ;
     RECT  9.288 49.549 9.306 49.919 ;
     RECT  5.436 49.891 6.678 50.009 ;
     RECT  49.212 49.891 50.202 50.009 ;
     RECT  53.208 49.891 53.37 50.009 ;
     RECT  94.215 49.747 94.662 50.009 ;
     RECT  4.572 49.891 4.626 50.045 ;
     RECT  74.88 49.505 74.898 50.251 ;
     RECT  74.664 50.251 74.898 50.287 ;
     RECT  98.244 49.505 98.442 50.287 ;
     RECT  5.436 50.009 5.598 50.315 ;
     RECT  99.216 49.505 101.106 50.315 ;
     RECT  99.54 50.315 101.106 50.395 ;
     RECT  53.208 50.009 53.262 50.431 ;
     RECT  102.564 49.661 102.582 50.431 ;
     RECT  74.664 50.287 75.078 50.459 ;
     RECT  102.024 50.431 102.582 50.525 ;
     RECT  52.596 50.431 53.262 50.549 ;
     RECT  4.608 50.045 4.626 50.585 ;
     RECT  99.54 50.395 101.142 50.665 ;
     RECT  49.716 50.009 50.202 50.701 ;
     RECT  51.015 49.469 51.822 50.701 ;
     RECT  52.596 50.549 53.046 50.701 ;
     RECT  2.415 49.505 2.697 50.731 ;
     RECT  96.768 49.577 96.786 50.791 ;
     RECT  49.716 50.701 53.046 50.819 ;
     RECT  99.54 50.665 101.178 50.819 ;
     RECT  6.372 50.009 6.678 50.855 ;
     RECT  49.716 50.819 52.866 50.855 ;
     RECT  74.664 50.459 74.682 50.855 ;
     RECT  55.26 49.577 55.278 50.863 ;
     RECT  72.615 47.885 72.897 50.863 ;
     RECT  6.372 50.855 6.39 50.891 ;
     RECT  7.815 49.577 8.097 50.971 ;
     RECT  7.815 50.971 8.442 51.089 ;
     RECT  49.716 50.855 52.218 51.089 ;
     RECT  7.815 51.089 8.097 51.097 ;
     RECT  7.488 51.097 8.097 51.149 ;
     RECT  96.768 50.791 96.93 51.241 ;
     RECT  98.244 50.287 98.478 51.241 ;
     RECT  99.54 50.819 100.602 51.241 ;
     RECT  102.564 50.525 102.582 51.355 ;
     RECT  50.724 51.089 52.218 51.359 ;
     RECT  72.615 50.863 73.566 51.394 ;
     RECT  50.724 51.359 52.11 51.395 ;
     RECT  96.3 51.241 96.93 51.395 ;
     RECT  54.72 50.863 55.278 51.503 ;
     RECT  96.876 51.395 96.93 51.511 ;
     RECT  98.244 51.241 100.602 51.511 ;
     RECT  96.876 51.511 100.602 51.601 ;
     RECT  96.876 51.601 101.178 51.629 ;
     RECT  102.528 51.355 102.582 51.629 ;
     RECT  2.304 50.731 2.697 51.665 ;
     RECT  3.96 51.511 4.59 51.665 ;
     RECT  96.876 51.629 98.262 51.665 ;
     RECT  99 51.629 101.178 51.665 ;
     RECT  75.096 51.601 75.114 51.709 ;
     RECT  4.284 51.665 4.59 51.883 ;
     RECT  5.58 50.315 5.598 51.883 ;
     RECT  75.096 51.709 75.222 51.899 ;
     RECT  4.284 51.883 4.806 51.935 ;
     RECT  72.615 51.394 73.602 51.935 ;
     RECT  75.096 51.899 75.114 51.935 ;
     RECT  96.876 51.665 96.894 51.935 ;
     RECT  99.54 51.665 101.178 51.935 ;
     RECT  78.015 31.829 78.297 51.943 ;
     RECT  94.215 50.009 94.497 51.943 ;
     RECT  2.415 51.665 2.697 52.051 ;
     RECT  49.896 51.089 49.914 52.051 ;
     RECT  50.724 51.395 52.002 52.051 ;
     RECT  78.015 51.943 78.642 52.079 ;
     RECT  94.215 51.943 94.662 52.079 ;
     RECT  2.415 52.051 2.826 52.169 ;
     RECT  52.92 52.051 52.938 52.285 ;
     RECT  5.58 51.883 5.634 52.321 ;
     RECT  7.815 51.149 8.097 52.321 ;
     RECT  49.428 52.051 52.002 52.321 ;
     RECT  52.92 52.285 53.154 52.321 ;
     RECT  55.26 51.503 55.278 52.321 ;
     RECT  5.544 52.321 5.67 52.411 ;
     RECT  6.804 52.321 6.822 52.411 ;
     RECT  7.815 52.321 8.406 52.411 ;
     RECT  6.804 52.411 8.406 52.439 ;
     RECT  49.428 52.321 53.154 52.439 ;
     RECT  54.72 52.321 55.278 52.439 ;
     RECT  100.62 51.935 101.178 52.439 ;
     RECT  2.415 52.169 2.697 52.447 ;
     RECT  99.54 51.935 99.897 52.475 ;
     RECT  6.804 52.439 8.262 52.589 ;
     RECT  50.184 52.439 53.154 52.591 ;
     RECT  7.815 52.589 8.262 52.592 ;
     RECT  5.544 52.411 5.742 52.709 ;
     RECT  6.804 52.589 6.822 52.709 ;
     RECT  7.815 52.592 8.154 52.709 ;
     RECT  9.18 52.591 9.27 52.709 ;
     RECT  50.184 52.591 53.226 52.709 ;
     RECT  5.544 52.709 5.562 52.745 ;
     RECT  72.615 51.935 73.566 52.745 ;
     RECT  99.615 52.475 99.897 52.789 ;
     RECT  97.848 51.665 98.262 52.861 ;
     RECT  46.764 52.591 46.782 52.889 ;
     RECT  2.412 52.447 2.697 52.891 ;
     RECT  9.18 52.709 9.198 52.979 ;
     RECT  97.632 52.861 98.874 52.979 ;
     RECT  96.696 52.825 96.714 52.987 ;
     RECT  2.304 52.891 2.697 53.015 ;
     RECT  70.704 52.681 70.722 53.015 ;
     RECT  97.632 52.979 98.262 53.015 ;
     RECT  96.084 52.987 96.714 53.021 ;
     RECT  94.215 52.079 94.497 53.131 ;
     RECT  49.428 52.439 49.446 53.221 ;
     RECT  50.184 52.709 53.046 53.221 ;
     RECT  55.26 52.439 55.278 53.221 ;
     RECT  4.428 51.935 4.59 53.249 ;
     RECT  5.364 53.131 5.382 53.249 ;
     RECT  76.32 53.131 76.338 53.249 ;
     RECT  96.876 53.131 96.894 53.249 ;
     RECT  3.564 53.131 3.582 53.285 ;
     RECT  49.428 53.221 53.046 53.285 ;
     RECT  96.084 53.021 96.102 53.285 ;
     RECT  2.415 53.015 2.697 53.32 ;
     RECT  99.615 52.789 100.17 53.32 ;
     RECT  2.415 53.32 2.79 53.357 ;
     RECT  54.684 53.221 55.278 53.357 ;
     RECT  99 53.32 100.17 53.357 ;
     RECT  49.428 53.285 52.974 53.393 ;
     RECT  4.428 53.249 4.446 53.401 ;
     RECT  99.615 53.357 100.17 53.401 ;
     RECT  50.004 53.393 52.974 53.519 ;
     RECT  99.615 53.401 100.206 53.527 ;
     RECT  101.16 52.439 101.178 53.527 ;
     RECT  99.615 53.527 101.178 53.635 ;
     RECT  50.004 53.519 52.758 53.789 ;
     RECT  99.615 53.635 101.214 53.789 ;
     RECT  3.6 53.401 4.446 53.825 ;
     RECT  72.615 52.745 72.99 53.825 ;
     RECT  98.244 53.015 98.262 53.941 ;
     RECT  7.815 52.709 8.097 54.031 ;
     RECT  4.356 53.825 4.446 54.043 ;
     RECT  5.4 53.941 5.418 54.043 ;
     RECT  3.6 53.825 3.618 54.059 ;
     RECT  50.22 53.789 52.758 54.059 ;
     RECT  97.956 53.941 98.838 54.059 ;
     RECT  102.564 51.629 102.582 54.059 ;
     RECT  74.124 54.031 74.142 54.067 ;
     RECT  6.3 54.043 6.318 54.095 ;
     RECT  97.956 54.059 98.802 54.095 ;
     RECT  97.02 53.755 97.038 54.211 ;
     RECT  0.108 54.103 0.126 54.221 ;
     RECT  6.372 54.103 6.39 54.329 ;
     RECT  50.364 54.059 52.758 54.329 ;
     RECT  75.024 54.211 75.042 54.329 ;
     RECT  97.02 54.211 97.254 54.329 ;
     RECT  4.356 54.043 5.418 54.365 ;
     RECT  73.836 54.067 74.142 54.365 ;
     RECT  97.02 54.329 97.11 54.365 ;
     RECT  46.764 54.373 46.782 54.473 ;
     RECT  98.028 54.095 98.802 54.599 ;
     RECT  102.024 54.379 102.042 54.599 ;
     RECT  2.415 53.357 2.697 54.607 ;
     RECT  94.215 53.131 94.662 54.607 ;
     RECT  99.615 53.789 100.71 54.607 ;
     RECT  73.836 54.365 73.854 54.635 ;
     RECT  98.028 54.599 98.262 54.635 ;
     RECT  2.415 54.607 2.826 54.653 ;
     RECT  94.215 54.607 94.77 54.701 ;
     RECT  97.092 54.365 97.11 54.749 ;
     RECT  54.792 53.357 55.278 54.751 ;
     RECT  95.976 54.571 95.994 54.751 ;
     RECT  7.236 54.031 8.097 54.869 ;
     RECT  95.976 54.751 96.21 54.869 ;
     RECT  3.996 54.751 4.014 54.905 ;
     RECT  95.976 54.869 95.994 54.905 ;
     RECT  99.615 54.607 100.998 54.985 ;
     RECT  4.896 54.365 5.418 55.021 ;
     RECT  50.724 54.329 52.758 55.021 ;
     RECT  2.415 54.653 2.697 55.051 ;
     RECT  4.896 55.021 5.598 55.111 ;
     RECT  50.724 55.021 53.226 55.175 ;
     RECT  54.684 54.751 55.278 55.175 ;
     RECT  4.464 55.111 5.598 55.319 ;
     RECT  75.528 55.291 75.546 55.409 ;
     RECT  4.464 55.319 4.914 55.445 ;
     RECT  53.388 55.291 53.406 55.445 ;
     RECT  98.244 54.635 98.262 55.525 ;
     RECT  99.615 54.985 101.07 55.525 ;
     RECT  97.128 55.525 97.146 55.561 ;
     RECT  98.208 55.525 98.262 55.561 ;
     RECT  99.615 55.525 101.178 55.561 ;
     RECT  97.128 55.561 97.29 55.565 ;
     RECT  50.724 55.175 51.297 55.679 ;
     RECT  97.272 55.565 97.29 55.679 ;
     RECT  99.18 55.561 101.178 55.679 ;
     RECT  2.304 55.051 2.697 55.715 ;
     RECT  75.456 55.417 75.474 55.715 ;
     RECT  98.064 55.561 98.262 55.715 ;
     RECT  98.136 55.715 98.262 55.831 ;
     RECT  99.18 55.679 100.782 55.831 ;
     RECT  5.832 55.561 5.85 55.921 ;
     RECT  98.136 55.831 100.782 55.949 ;
     RECT  5.832 55.921 6.138 55.957 ;
     RECT  74.484 55.651 74.502 55.985 ;
     RECT  99.18 55.949 100.782 55.985 ;
     RECT  4.536 55.445 4.914 55.997 ;
     RECT  7.815 54.869 8.097 56.029 ;
     RECT  5.832 55.957 6.21 56.093 ;
     RECT  2.415 55.715 2.697 56.101 ;
     RECT  52.128 55.175 52.542 56.101 ;
     RECT  102.564 54.811 102.582 56.101 ;
     RECT  5.832 56.093 5.85 56.129 ;
     RECT  7.164 56.029 8.097 56.129 ;
     RECT  102.024 56.101 102.582 56.141 ;
     RECT  94.215 54.701 94.497 56.155 ;
     RECT  96.444 56.101 96.462 56.189 ;
     RECT  52.128 56.101 52.83 56.191 ;
     RECT  94.215 56.155 94.734 56.219 ;
     RECT  97.38 56.101 97.398 56.255 ;
     RECT  50.976 55.679 51.297 56.263 ;
     RECT  52.02 56.191 52.83 56.263 ;
     RECT  46.764 55.957 46.782 56.291 ;
     RECT  99.615 55.985 100.782 56.291 ;
     RECT  50.976 56.263 52.83 56.371 ;
     RECT  94.215 56.219 94.497 56.371 ;
     RECT  6.804 56.227 6.858 56.489 ;
     RECT  94.068 56.371 94.497 56.489 ;
     RECT  5.328 56.371 5.346 56.525 ;
     RECT  50.976 56.371 53.334 56.533 ;
     RECT  4.428 56.605 4.518 56.641 ;
     RECT  6.84 56.489 6.858 56.669 ;
     RECT  96.84 56.443 97.182 56.717 ;
     RECT  2.415 56.101 2.718 56.767 ;
     RECT  4.068 56.641 4.518 56.795 ;
     RECT  50.796 56.533 53.334 56.795 ;
     RECT  95.76 56.371 95.778 56.795 ;
     RECT  2.415 56.767 2.826 56.813 ;
     RECT  4.248 56.795 4.518 56.911 ;
     RECT  102.564 56.141 102.582 56.971 ;
     RECT  98.244 55.949 98.262 57.019 ;
     RECT  76.536 56.911 76.554 57.029 ;
     RECT  97.164 56.717 97.182 57.053 ;
     RECT  4.248 56.911 4.59 57.065 ;
     RECT  99.615 56.291 100.386 57.145 ;
     RECT  5.364 56.911 5.382 57.173 ;
     RECT  7.815 56.129 8.097 57.181 ;
     RECT  102.024 56.971 102.582 57.209 ;
     RECT  2.415 56.813 2.697 57.211 ;
     RECT  7.128 57.181 8.097 57.299 ;
     RECT  49.932 57.145 49.95 57.299 ;
     RECT  99.18 57.145 100.818 57.299 ;
     RECT  6.12 57.307 6.138 57.451 ;
     RECT  50.796 56.795 53.118 57.451 ;
     RECT  100.62 57.299 100.818 57.451 ;
     RECT  75.132 57.451 75.798 57.541 ;
     RECT  98.064 57.019 98.262 57.541 ;
     RECT  6.12 57.451 6.354 57.569 ;
     RECT  50.184 57.451 53.118 57.569 ;
     RECT  99.18 57.299 99.897 57.581 ;
     RECT  52.848 57.569 53.118 57.595 ;
     RECT  4.932 57.451 4.95 57.605 ;
     RECT  52.848 57.595 53.514 57.721 ;
     RECT  100.62 57.451 100.962 57.721 ;
     RECT  97.128 57.721 97.146 57.787 ;
     RECT  74.664 57.541 75.798 57.839 ;
     RECT  96.984 57.787 97.146 57.839 ;
     RECT  74.664 57.839 75.15 57.875 ;
     RECT  99.216 57.581 99.897 57.875 ;
     RECT  75.132 57.875 75.15 57.983 ;
     RECT  98.028 57.541 98.262 57.991 ;
     RECT  102.528 57.209 102.582 58.081 ;
     RECT  52.848 57.721 53.658 58.109 ;
     RECT  95.58 57.787 95.598 58.109 ;
     RECT  97.92 57.991 98.37 58.109 ;
     RECT  2.304 57.211 2.697 58.145 ;
     RECT  5.04 57.991 5.058 58.145 ;
     RECT  52.848 58.109 53.514 58.145 ;
     RECT  6.12 57.569 6.138 58.157 ;
     RECT  99.615 57.875 99.897 58.225 ;
     RECT  100.62 57.721 101.034 58.225 ;
     RECT  7.815 57.299 8.097 58.261 ;
     RECT  94.215 56.489 94.497 58.261 ;
     RECT  102.528 58.081 102.618 58.301 ;
     RECT  50.184 57.569 52.038 58.351 ;
     RECT  99.615 58.225 101.034 58.351 ;
     RECT  52.848 58.145 52.974 58.379 ;
     RECT  94.215 58.261 94.662 58.379 ;
     RECT  102.528 58.301 102.582 58.379 ;
     RECT  74.34 57.991 74.358 58.415 ;
     RECT  97.164 58.117 97.182 58.415 ;
     RECT  52.956 58.379 52.974 58.523 ;
     RECT  4.284 58.261 4.302 58.531 ;
     RECT  54.504 58.261 54.522 58.531 ;
     RECT  55.26 55.175 55.278 58.531 ;
     RECT  49.86 58.351 52.038 58.559 ;
     RECT  49.86 58.559 52.002 58.649 ;
     RECT  54.504 58.531 55.278 58.685 ;
     RECT  4.284 58.531 4.77 58.693 ;
     RECT  97.92 58.109 98.262 58.729 ;
     RECT  7.092 58.261 8.097 58.891 ;
     RECT  4.032 58.693 4.77 58.919 ;
     RECT  50.112 58.649 52.002 58.919 ;
     RECT  75.78 58.801 75.798 58.919 ;
     RECT  2.415 58.145 2.697 58.927 ;
     RECT  4.032 58.919 4.05 58.955 ;
     RECT  2.415 58.927 2.826 58.973 ;
     RECT  7.056 58.891 8.097 59.035 ;
     RECT  97.632 58.729 98.262 59.035 ;
     RECT  99.615 58.351 101.178 59.035 ;
     RECT  97.632 59.035 101.178 59.071 ;
     RECT  6.876 59.035 8.097 59.099 ;
     RECT  97.632 59.071 101.646 59.165 ;
     RECT  6.876 59.099 7.074 59.189 ;
     RECT  3.96 59.071 3.978 59.225 ;
     RECT  74.88 58.927 74.898 59.225 ;
     RECT  97.632 59.165 100.962 59.225 ;
     RECT  7.815 59.099 8.097 59.275 ;
     RECT  6.876 59.189 6.894 59.309 ;
     RECT  97.632 59.225 100.602 59.309 ;
     RECT  50.112 58.919 51.57 59.369 ;
     RECT  2.415 58.973 2.697 59.371 ;
     RECT  50.112 59.369 50.13 59.419 ;
     RECT  94.215 58.379 94.497 59.431 ;
     RECT  50.04 59.419 50.13 59.459 ;
     RECT  50.04 59.459 50.058 59.495 ;
     RECT  98.064 59.309 100.602 59.495 ;
     RECT  94.215 59.431 94.698 59.575 ;
     RECT  96.012 59.275 96.03 59.575 ;
     RECT  7.815 59.275 8.478 59.611 ;
     RECT  9.468 59.341 9.486 59.611 ;
     RECT  9.396 59.611 9.486 59.639 ;
     RECT  54.72 58.685 55.278 59.639 ;
     RECT  94.215 59.575 96.03 59.639 ;
     RECT  7.815 59.611 8.622 59.729 ;
     RECT  73.656 59.575 73.674 59.729 ;
     RECT  95.256 59.639 95.418 59.729 ;
     RECT  6.192 59.611 6.21 59.765 ;
     RECT  75.42 59.467 75.618 59.765 ;
     RECT  96.948 59.611 96.966 59.765 ;
     RECT  51.015 59.369 51.57 59.809 ;
     RECT  96.372 59.809 96.57 59.999 ;
     RECT  52.56 59.611 52.578 60.035 ;
     RECT  96.372 59.999 96.39 60.035 ;
     RECT  2.304 59.371 2.697 60.151 ;
     RECT  99.615 59.495 100.602 60.151 ;
     RECT  99.615 60.151 100.638 60.241 ;
     RECT  2.304 60.151 3.402 60.269 ;
     RECT  9.396 59.639 9.414 60.269 ;
     RECT  2.304 60.269 2.826 60.305 ;
     RECT  99.615 60.241 101.178 60.341 ;
     RECT  4.536 60.235 4.554 60.385 ;
     RECT  51.015 59.809 51.714 60.385 ;
     RECT  3.672 60.385 4.554 60.421 ;
     RECT  51.015 60.385 51.822 60.421 ;
     RECT  52.668 60.151 53.046 60.421 ;
     RECT  55.26 59.639 55.278 60.421 ;
     RECT  98.064 59.495 98.262 60.421 ;
     RECT  78.015 52.079 78.297 60.511 ;
     RECT  75.672 60.421 75.906 60.539 ;
     RECT  52.668 60.421 53.226 60.547 ;
     RECT  3.672 60.421 4.698 60.575 ;
     RECT  50.976 60.421 51.822 60.575 ;
     RECT  75.672 60.539 75.69 60.575 ;
     RECT  46.764 59.611 46.782 60.611 ;
     RECT  5.508 60.385 5.526 60.619 ;
     RECT  54.72 60.421 55.278 60.619 ;
     RECT  52.668 60.547 53.406 60.647 ;
     RECT  97.92 60.421 98.262 60.655 ;
     RECT  5.472 60.619 5.526 60.691 ;
     RECT  2.415 60.305 2.826 60.701 ;
     RECT  97.776 60.655 98.874 60.701 ;
     RECT  54.684 60.619 55.278 60.719 ;
     RECT  78.015 60.511 78.642 60.719 ;
     RECT  50.148 60.421 50.166 60.763 ;
     RECT  4.752 60.691 5.706 60.781 ;
     RECT  4.752 60.781 6.858 60.809 ;
     RECT  50.004 60.763 50.166 60.809 ;
     RECT  5.04 60.809 6.858 60.811 ;
     RECT  3.672 60.575 3.69 60.845 ;
     RECT  97.776 60.701 98.73 60.845 ;
     RECT  5.04 60.811 7.074 60.953 ;
     RECT  50.976 60.575 51.297 60.961 ;
     RECT  52.668 60.647 52.866 60.961 ;
     RECT  97.776 60.845 98.262 60.961 ;
     RECT  5.04 60.953 6.246 61.079 ;
     RECT  53.712 60.961 53.91 61.079 ;
     RECT  2.415 60.701 2.697 61.099 ;
     RECT  53.712 61.079 53.73 61.115 ;
     RECT  99.615 60.341 101.07 61.195 ;
     RECT  99.615 61.195 101.286 61.231 ;
     RECT  99.615 61.231 101.502 61.325 ;
     RECT  99.615 61.325 101.286 61.349 ;
     RECT  5.04 61.079 5.49 61.385 ;
     RECT  75.564 60.817 75.582 61.385 ;
     RECT  97.452 60.961 98.262 61.465 ;
     RECT  7.815 59.729 8.097 61.501 ;
     RECT  50.94 60.961 51.297 61.501 ;
     RECT  99.615 61.349 101.178 61.501 ;
     RECT  2.34 61.099 2.697 61.531 ;
     RECT  7.056 60.953 7.074 61.565 ;
     RECT  5.04 61.385 5.274 61.579 ;
     RECT  97.416 61.465 98.262 61.579 ;
     RECT  99.324 61.501 101.178 61.579 ;
     RECT  50.94 61.501 51.354 61.619 ;
     RECT  2.304 61.531 2.697 61.655 ;
     RECT  55.26 60.719 55.278 61.663 ;
     RECT  72.615 53.825 72.897 61.663 ;
     RECT  4.32 61.579 5.274 61.771 ;
     RECT  72.615 61.663 73.602 61.771 ;
     RECT  7.815 61.501 8.154 61.799 ;
     RECT  54.648 61.663 55.278 61.799 ;
     RECT  6.228 61.079 6.246 61.889 ;
     RECT  52.128 60.961 52.866 61.889 ;
     RECT  72.615 61.771 73.782 61.889 ;
     RECT  95.76 61.771 95.778 61.889 ;
     RECT  3.996 61.771 5.274 61.925 ;
     RECT  72.615 61.889 73.602 61.925 ;
     RECT  70.704 61.897 70.722 61.997 ;
     RECT  50.04 61.771 50.058 62.041 ;
     RECT  50.94 61.619 51.297 62.041 ;
     RECT  97.416 61.579 101.178 62.041 ;
     RECT  95.616 62.005 95.634 62.045 ;
     RECT  52.128 61.889 52.722 62.141 ;
     RECT  102.564 58.379 102.582 62.155 ;
     RECT  4.14 61.925 5.274 62.159 ;
     RECT  50.04 62.041 51.297 62.159 ;
     RECT  53.64 62.041 53.946 62.159 ;
     RECT  4.14 62.159 4.374 62.195 ;
     RECT  53.64 62.159 53.838 62.195 ;
     RECT  97.02 62.041 101.178 62.195 ;
     RECT  52.128 62.141 52.47 62.275 ;
     RECT  5.148 62.159 5.274 62.311 ;
     RECT  50.04 62.159 50.13 62.311 ;
     RECT  2.415 61.655 2.697 62.395 ;
     RECT  52.092 62.275 52.47 62.429 ;
     RECT  53.676 62.195 53.838 62.429 ;
     RECT  75.672 61.735 75.906 62.429 ;
     RECT  6.516 62.395 6.534 62.465 ;
     RECT  53.676 62.429 53.694 62.465 ;
     RECT  75.672 62.429 75.69 62.465 ;
     RECT  7.815 61.799 8.097 62.581 ;
     RECT  6.66 62.581 6.678 62.699 ;
     RECT  5.148 62.311 5.49 62.735 ;
     RECT  97.416 62.195 101.178 62.735 ;
     RECT  2.34 62.395 2.697 62.827 ;
     RECT  49.752 62.311 50.13 62.851 ;
     RECT  7.452 62.581 8.097 62.879 ;
     RECT  49.104 62.851 50.13 62.969 ;
     RECT  75.168 62.851 75.186 62.969 ;
     RECT  72.615 61.925 73.566 63.005 ;
     RECT  5.328 62.735 5.49 63.121 ;
     RECT  49.5 62.969 50.13 63.121 ;
     RECT  50.904 62.159 51.297 63.121 ;
     RECT  52.128 62.429 52.47 63.121 ;
     RECT  97.596 62.735 98.658 63.149 ;
     RECT  101.988 62.155 102.582 63.149 ;
     RECT  4.356 62.195 4.374 63.211 ;
     RECT  52.128 63.121 53.01 63.239 ;
     RECT  98.316 63.149 98.658 63.239 ;
     RECT  99.615 62.735 101.178 63.239 ;
     RECT  5.328 63.121 5.706 63.275 ;
     RECT  7.596 62.879 8.097 63.275 ;
     RECT  52.128 63.239 52.146 63.275 ;
     RECT  98.316 63.239 98.586 63.275 ;
     RECT  0.108 63.247 0.126 63.293 ;
     RECT  94.215 59.639 94.497 63.355 ;
     RECT  3.816 63.211 4.374 63.391 ;
     RECT  49.5 63.121 51.297 63.391 ;
     RECT  94.215 63.355 94.662 63.391 ;
     RECT  52.884 63.239 53.01 63.509 ;
     RECT  3.816 63.391 4.518 63.545 ;
     RECT  52.884 63.509 52.902 63.545 ;
     RECT  96.156 63.211 96.174 63.545 ;
     RECT  72.615 63.005 72.897 63.625 ;
     RECT  54.108 63.391 54.126 63.661 ;
     RECT  94.215 63.391 94.806 63.739 ;
     RECT  49.5 63.391 51.354 63.751 ;
     RECT  94.215 63.739 95.058 63.779 ;
     RECT  2.304 62.827 2.697 63.815 ;
     RECT  53.856 63.661 54.126 63.815 ;
     RECT  2.415 63.815 2.697 63.823 ;
     RECT  49.5 63.751 51.498 63.835 ;
     RECT  53.928 63.815 54.126 64.021 ;
     RECT  2.415 63.823 3.114 64.049 ;
     RECT  5.328 63.275 5.346 64.049 ;
     RECT  53.928 64.021 54.198 64.085 ;
     RECT  98.316 63.275 98.442 64.123 ;
     RECT  99.615 63.239 101.034 64.165 ;
     RECT  99.615 64.165 101.178 64.201 ;
     RECT  54.144 64.085 54.198 64.291 ;
     RECT  55.26 61.799 55.278 64.291 ;
     RECT  3.96 63.545 4.518 64.319 ;
     RECT  49.356 63.835 51.498 64.319 ;
     RECT  54.144 64.291 55.278 64.319 ;
     RECT  72.396 63.625 72.897 64.319 ;
     RECT  99.216 64.201 101.178 64.319 ;
     RECT  2.415 64.049 2.79 64.355 ;
     RECT  99.216 64.319 101.106 64.355 ;
     RECT  54.648 64.319 55.278 64.391 ;
     RECT  98.244 64.123 98.442 64.471 ;
     RECT  2.415 64.355 2.697 64.555 ;
     RECT  98.244 64.471 98.694 64.589 ;
     RECT  52.344 64.201 52.362 64.625 ;
     RECT  75.816 64.327 75.834 64.625 ;
     RECT  54.684 64.391 55.278 64.697 ;
     RECT  94.215 63.779 94.662 64.705 ;
     RECT  3.96 64.319 4.374 64.741 ;
     RECT  102.564 63.149 102.582 64.747 ;
     RECT  49.86 64.319 51.462 64.859 ;
     RECT  99.468 64.355 101.106 64.859 ;
     RECT  74.016 64.561 74.034 64.867 ;
     RECT  94.215 64.705 94.77 64.895 ;
     RECT  96.912 64.741 97.29 64.895 ;
     RECT  99.468 64.859 99.897 64.895 ;
     RECT  72.615 64.319 72.897 64.903 ;
     RECT  74.016 64.867 74.214 64.903 ;
     RECT  94.215 64.895 94.698 64.931 ;
     RECT  52.632 64.741 52.794 64.939 ;
     RECT  95.868 64.741 95.886 64.973 ;
     RECT  72.615 64.903 74.214 65.039 ;
     RECT  102.528 64.747 102.582 65.179 ;
     RECT  72.615 65.039 73.746 65.201 ;
     RECT  5.364 64.705 5.382 65.371 ;
     RECT  102.024 65.179 102.582 65.371 ;
     RECT  96.912 64.895 97.11 65.399 ;
     RECT  3.636 64.741 4.374 65.407 ;
     RECT  52.632 64.939 53.046 65.419 ;
     RECT  21.096 64.831 21.114 65.435 ;
     RECT  52.56 65.419 53.046 65.471 ;
     RECT  102.024 65.371 102.618 65.507 ;
     RECT  100.764 64.859 101.106 65.515 ;
     RECT  3.42 65.407 4.374 65.551 ;
     RECT  5.364 65.371 5.85 65.551 ;
     RECT  52.956 65.471 53.046 65.551 ;
     RECT  98.244 64.589 98.586 65.551 ;
     RECT  100.764 65.515 101.214 65.641 ;
     RECT  102.564 65.507 102.618 65.645 ;
     RECT  3.42 65.551 5.85 65.669 ;
     RECT  50.04 64.859 51.297 65.669 ;
     RECT  76.464 65.551 76.482 65.669 ;
     RECT  100.728 65.641 101.214 65.669 ;
     RECT  55.26 64.697 55.278 65.677 ;
     RECT  3.42 65.669 3.438 65.705 ;
     RECT  4.248 65.669 4.554 65.705 ;
     RECT  52.956 65.551 53.442 65.705 ;
     RECT  75.24 65.371 75.258 65.705 ;
     RECT  50.112 65.669 51.297 65.749 ;
     RECT  5.364 65.669 5.85 65.777 ;
     RECT  99.615 64.895 99.897 65.821 ;
     RECT  4.392 65.705 4.554 65.849 ;
     RECT  54.72 65.677 55.278 65.849 ;
     RECT  94.215 64.931 94.497 65.947 ;
     RECT  70.74 65.641 70.758 65.975 ;
     RECT  96.912 65.399 96.93 65.975 ;
     RECT  99.54 65.821 99.897 65.975 ;
     RECT  7.056 64.843 7.074 66.091 ;
     RECT  98.244 65.551 98.766 66.091 ;
     RECT  99.615 65.975 99.897 66.091 ;
     RECT  100.728 65.669 101.178 66.091 ;
     RECT  5.364 65.777 5.562 66.125 ;
     RECT  5.472 66.125 5.562 66.209 ;
     RECT  6.336 66.091 7.074 66.209 ;
     RECT  94.215 65.947 94.662 66.235 ;
     RECT  73.728 65.201 73.746 66.245 ;
     RECT  98.244 66.091 98.802 66.245 ;
     RECT  50.112 65.749 52.002 66.253 ;
     RECT  52.74 66.217 52.758 66.253 ;
     RECT  46.8 66.325 46.818 66.361 ;
     RECT  50.112 66.253 52.758 66.451 ;
     RECT  57.564 40.877 57.582 66.479 ;
     RECT  58.5 35.609 58.518 66.479 ;
     RECT  96.408 66.361 96.426 66.515 ;
     RECT  46.764 66.361 46.818 66.551 ;
     RECT  7.815 63.275 8.097 66.631 ;
     RECT  9 66.523 9.018 66.631 ;
     RECT  46.764 66.551 46.782 66.659 ;
     RECT  58.248 66.487 58.266 66.659 ;
     RECT  4.536 65.849 4.554 66.715 ;
     RECT  54.216 66.361 54.234 66.749 ;
     RECT  99.615 66.091 101.178 66.749 ;
     RECT  2.304 64.555 2.697 66.785 ;
     RECT  5.472 66.209 5.49 66.785 ;
     RECT  94.215 66.235 95.202 66.785 ;
     RECT  7.056 66.209 7.074 66.893 ;
     RECT  90.648 66.217 90.666 66.893 ;
     RECT  2.415 66.785 2.697 66.901 ;
     RECT  4.464 66.715 4.554 66.901 ;
     RECT  50.112 66.451 52.83 66.901 ;
     RECT  102.564 65.645 102.582 66.901 ;
     RECT  102.528 66.901 102.582 66.941 ;
     RECT  101.088 66.749 101.178 67.019 ;
     RECT  2.415 66.901 3.15 67.055 ;
     RECT  49.752 66.901 52.83 67.055 ;
     RECT  96.12 66.901 96.138 67.055 ;
     RECT  101.16 67.019 101.178 67.055 ;
     RECT  99.615 66.749 99.897 67.261 ;
     RECT  2.415 67.055 2.79 67.325 ;
     RECT  49.752 67.055 51.297 67.405 ;
     RECT  49.464 67.405 51.297 67.433 ;
     RECT  4.464 66.901 4.626 67.441 ;
     RECT  49.464 67.433 49.626 67.441 ;
     RECT  5.4 66.901 5.418 67.469 ;
     RECT  98.244 66.245 98.262 67.531 ;
     RECT  99.18 67.261 99.897 67.531 ;
     RECT  49.212 67.441 49.626 67.559 ;
     RECT  2.415 67.325 2.697 67.567 ;
     RECT  4.284 67.441 4.626 67.595 ;
     RECT  7.815 66.631 9.018 67.603 ;
     RECT  55.26 65.849 55.278 67.639 ;
     RECT  4.536 67.595 4.626 67.669 ;
     RECT  6.552 67.603 6.57 67.672 ;
     RECT  98.244 67.531 99.897 67.711 ;
     RECT  54.684 67.639 55.278 67.739 ;
     RECT  98.244 67.711 100.422 67.771 ;
     RECT  102.564 66.941 102.582 67.771 ;
     RECT  46.8 67.567 46.818 67.829 ;
     RECT  49.536 67.559 49.626 67.829 ;
     RECT  102.528 67.771 102.582 67.829 ;
     RECT  4.536 67.669 4.698 67.865 ;
     RECT  6.408 67.672 6.57 67.867 ;
     RECT  7.38 67.603 9.018 67.867 ;
     RECT  6.408 67.867 9.018 67.901 ;
     RECT  52.02 67.055 52.83 67.981 ;
     RECT  49.608 67.829 49.626 68.009 ;
     RECT  2.412 67.567 2.697 68.011 ;
     RECT  97.776 67.771 100.422 68.071 ;
     RECT  94.215 66.785 94.497 68.107 ;
     RECT  2.304 68.011 2.697 68.135 ;
     RECT  7.092 67.901 9.018 68.135 ;
     RECT  52.02 67.981 52.866 68.135 ;
     RECT  75.528 68.071 75.546 68.251 ;
     RECT  78.015 60.719 78.297 68.251 ;
     RECT  94.215 68.107 94.662 68.279 ;
     RECT  7.272 68.135 9.018 68.369 ;
     RECT  46.764 68.071 46.782 68.369 ;
     RECT  78.015 68.251 78.642 68.369 ;
     RECT  97.776 68.071 100.746 68.369 ;
     RECT  97.776 68.369 98.73 68.381 ;
     RECT  5.22 68.251 5.238 68.405 ;
     RECT  74.664 68.251 74.682 68.405 ;
     RECT  75.528 68.251 75.726 68.405 ;
     RECT  97.884 68.381 98.73 68.405 ;
     RECT  0.54 68.377 0.558 68.477 ;
     RECT  94.215 68.279 94.59 68.513 ;
     RECT  95.976 68.341 95.994 68.521 ;
     RECT  55.26 67.739 55.278 68.639 ;
     RECT  95.976 68.521 96.642 68.639 ;
     RECT  50.4 67.433 51.297 68.675 ;
     RECT  95.976 68.639 95.994 68.675 ;
     RECT  7.815 68.369 9.018 68.683 ;
     RECT  2.415 68.135 2.697 68.875 ;
     RECT  4.248 68.377 4.266 68.875 ;
     RECT  4.248 68.875 4.59 68.953 ;
     RECT  52.02 68.135 52.686 68.953 ;
     RECT  75.528 68.405 75.618 69.061 ;
     RECT  97.884 68.405 98.262 69.115 ;
     RECT  99.615 68.369 100.746 69.151 ;
     RECT  75.024 69.061 75.618 69.179 ;
     RECT  3.96 68.953 4.59 69.215 ;
     RECT  52.02 68.953 53.01 69.215 ;
     RECT  72.615 65.201 72.897 69.223 ;
     RECT  99.615 69.151 101.178 69.251 ;
     RECT  97.74 69.115 98.262 69.331 ;
     RECT  99.615 69.251 100.782 69.331 ;
     RECT  5.508 69.061 5.526 69.359 ;
     RECT  50.436 68.675 51.297 69.421 ;
     RECT  48.852 69.331 48.87 69.449 ;
     RECT  75.024 69.179 75.042 69.485 ;
     RECT  97.74 69.331 100.782 69.521 ;
     RECT  4.5 69.215 4.59 69.533 ;
     RECT  50.364 69.421 51.297 69.601 ;
     RECT  52.02 69.215 52.398 69.601 ;
     RECT  4.5 69.533 4.518 69.755 ;
     RECT  72.615 69.223 73.566 69.755 ;
     RECT  98.064 69.521 100.782 69.755 ;
     RECT  102.564 67.829 102.582 69.871 ;
     RECT  5.436 69.601 5.454 69.961 ;
     RECT  3.42 69.871 3.438 69.989 ;
     RECT  50.22 69.601 52.398 69.997 ;
     RECT  50.22 69.997 52.434 70.061 ;
     RECT  6.192 69.421 6.246 70.069 ;
     RECT  7.815 68.683 9.342 70.069 ;
     RECT  50.796 70.061 52.398 70.097 ;
     RECT  54.684 69.871 54.702 70.097 ;
     RECT  99.108 69.755 100.782 70.141 ;
     RECT  99.108 70.141 101.178 70.295 ;
     RECT  98.064 69.755 98.262 70.405 ;
     RECT  4.248 70.219 4.41 70.411 ;
     RECT  94.215 68.513 94.497 70.501 ;
     RECT  3.96 70.411 4.41 70.529 ;
     RECT  50.796 70.097 52.29 70.565 ;
     RECT  72.615 69.755 72.99 70.565 ;
     RECT  99.108 70.295 100.674 70.565 ;
     RECT  3.96 70.529 4.086 70.637 ;
     RECT  53.424 70.141 53.442 70.645 ;
     RECT  2.304 68.875 2.697 70.673 ;
     RECT  97.776 70.405 98.262 70.681 ;
     RECT  3.96 70.637 4.014 70.709 ;
     RECT  96.156 70.537 96.174 70.733 ;
     RECT  53.424 70.645 53.658 70.807 ;
     RECT  3.996 70.709 4.014 70.835 ;
     RECT  97.092 70.681 98.262 70.835 ;
     RECT  53.424 70.807 53.694 70.907 ;
     RECT  94.215 70.501 94.662 70.907 ;
     RECT  5.328 69.961 5.454 70.915 ;
     RECT  53.424 70.907 53.658 70.943 ;
     RECT  5.22 70.915 5.454 70.951 ;
     RECT  6.192 70.069 6.858 70.951 ;
     RECT  50.796 70.565 51.354 70.951 ;
     RECT  52.272 70.565 52.29 70.951 ;
     RECT  97.488 70.835 98.262 70.951 ;
     RECT  5.22 70.951 6.858 70.973 ;
     RECT  75.924 70.807 75.942 70.979 ;
     RECT  53.424 70.943 53.622 71.069 ;
     RECT  99.615 70.565 100.674 71.185 ;
     RECT  5.328 70.973 6.858 71.221 ;
     RECT  7.776 70.069 9.342 71.221 ;
     RECT  52.272 70.951 52.578 71.221 ;
     RECT  99.615 71.185 100.962 71.221 ;
     RECT  102.024 69.871 102.582 71.261 ;
     RECT  5.328 71.221 9.342 71.339 ;
     RECT  49.608 70.645 49.626 71.339 ;
     RECT  52.272 71.221 53.082 71.339 ;
     RECT  5.328 71.339 6.858 71.375 ;
     RECT  75.24 71.041 75.618 71.375 ;
     RECT  97.488 70.951 98.694 71.375 ;
     RECT  99.615 71.221 101.142 71.411 ;
     RECT  2.415 70.673 2.697 71.455 ;
     RECT  50.4 70.951 51.354 71.455 ;
     RECT  52.272 71.339 52.542 71.455 ;
     RECT  2.304 71.455 2.697 71.491 ;
     RECT  99.615 71.411 99.897 71.491 ;
     RECT  5.58 71.375 6.858 71.519 ;
     RECT  5.58 71.519 5.706 71.549 ;
     RECT  46.764 71.491 46.782 71.609 ;
     RECT  60.336 9.751 60.354 71.609 ;
     RECT  75.6 71.375 75.618 71.609 ;
     RECT  97.488 71.375 98.622 71.609 ;
     RECT  99.468 71.491 99.897 71.645 ;
     RECT  100.728 71.411 101.142 71.681 ;
     RECT  100.764 71.681 101.142 71.725 ;
     RECT  6.84 71.519 6.858 71.789 ;
     RECT  94.215 70.907 94.497 71.803 ;
     RECT  97.488 71.609 97.506 71.837 ;
     RECT  98.244 71.609 98.622 71.879 ;
     RECT  100.764 71.725 101.214 71.879 ;
     RECT  50.076 71.455 52.542 71.915 ;
     RECT  98.244 71.879 98.478 71.915 ;
     RECT  2.304 71.491 3.15 72.031 ;
     RECT  73.728 71.887 73.746 72.031 ;
     RECT  94.215 71.803 95.166 72.031 ;
     RECT  73.728 72.031 73.962 72.149 ;
     RECT  94.215 72.031 95.31 72.149 ;
     RECT  2.304 72.031 3.402 72.185 ;
     RECT  52.02 71.915 52.542 72.185 ;
     RECT  73.728 72.149 73.746 72.185 ;
     RECT  50.076 71.915 51.297 72.229 ;
     RECT  70.704 71.311 70.722 72.257 ;
     RECT  49.968 72.229 51.297 72.419 ;
     RECT  52.02 72.185 52.506 72.419 ;
     RECT  96.732 72.301 96.966 72.419 ;
     RECT  52.128 72.419 52.506 72.455 ;
     RECT  96.732 72.419 96.75 72.455 ;
     RECT  4.644 72.031 4.806 72.571 ;
     RECT  99.615 71.645 99.897 72.571 ;
     RECT  100.764 71.879 100.782 72.571 ;
     RECT  5.58 71.549 5.598 72.599 ;
     RECT  50.724 72.419 51.297 72.599 ;
     RECT  98.244 71.915 98.262 72.661 ;
     RECT  49.716 72.571 49.734 72.689 ;
     RECT  4.608 72.571 4.806 72.725 ;
     RECT  74.664 72.229 74.682 72.725 ;
     RECT  46.764 72.697 46.782 72.797 ;
     RECT  98.244 72.661 98.478 72.805 ;
     RECT  99.615 72.571 100.782 72.841 ;
     RECT  5.328 72.805 5.346 72.845 ;
     RECT  98.244 72.805 98.874 72.845 ;
     RECT  7.815 71.339 9.342 72.931 ;
     RECT  102.564 71.261 102.582 72.955 ;
     RECT  94.215 72.149 94.662 72.959 ;
     RECT  6.228 72.955 6.318 72.967 ;
     RECT  7.236 72.931 9.342 72.967 ;
     RECT  2.304 72.185 2.697 72.995 ;
     RECT  6.228 72.967 9.342 73.037 ;
     RECT  99.615 72.841 101.034 73.039 ;
     RECT  52.2 72.455 52.506 73.201 ;
     RECT  6.228 73.037 6.246 73.229 ;
     RECT  2.412 72.995 2.697 73.265 ;
     RECT  4.536 72.931 4.554 73.265 ;
     RECT  50.832 72.599 51.297 73.381 ;
     RECT  52.2 73.201 52.686 73.381 ;
     RECT  53.712 73.345 53.73 73.381 ;
     RECT  54.72 73.309 54.738 73.409 ;
     RECT  102.528 72.955 102.582 73.409 ;
     RECT  50.832 73.381 52.902 73.471 ;
     RECT  53.712 73.381 53.874 73.471 ;
     RECT  98.244 72.845 98.478 73.471 ;
     RECT  50.832 73.471 53.874 73.499 ;
     RECT  2.415 73.265 2.697 73.507 ;
     RECT  74.376 73.381 74.394 73.507 ;
     RECT  5.904 73.381 5.922 73.535 ;
     RECT  74.304 73.507 74.394 73.535 ;
     RECT  99.288 73.039 101.034 73.535 ;
     RECT  99.288 73.535 100.746 73.571 ;
     RECT  74.304 73.535 74.322 73.607 ;
     RECT  53.568 73.499 53.874 73.651 ;
     RECT  97.992 73.471 98.478 73.651 ;
     RECT  99.288 73.571 100.422 73.651 ;
     RECT  0.108 73.507 0.126 73.661 ;
     RECT  7.236 73.037 9.342 73.769 ;
     RECT  53.568 73.651 54.018 73.769 ;
     RECT  53.568 73.769 53.874 73.805 ;
     RECT  94.215 72.959 94.497 73.849 ;
     RECT  96.228 73.507 96.246 73.921 ;
     RECT  97.992 73.651 100.422 73.921 ;
     RECT  2.415 73.507 2.97 74.011 ;
     RECT  2.415 74.011 3.474 74.039 ;
     RECT  50.832 73.499 51.318 74.039 ;
     RECT  53.568 73.805 53.586 74.039 ;
     RECT  70.704 73.921 70.722 74.039 ;
     RECT  76.32 73.921 76.482 74.039 ;
     RECT  96.228 73.921 96.39 74.039 ;
     RECT  96.228 74.039 96.246 74.047 ;
     RECT  97.848 73.921 100.422 74.059 ;
     RECT  76.32 74.039 76.338 74.075 ;
     RECT  94.215 73.849 94.662 74.075 ;
     RECT  3.42 74.039 3.474 74.191 ;
     RECT  50.832 74.039 51.297 74.281 ;
     RECT  3.42 74.191 3.618 74.309 ;
     RECT  97.416 74.059 100.422 74.309 ;
     RECT  3.42 74.309 3.438 74.345 ;
     RECT  5.004 74.059 5.022 74.461 ;
     RECT  52.128 73.499 52.47 74.461 ;
     RECT  98.244 74.309 100.422 74.461 ;
     RECT  2.415 74.039 2.697 74.491 ;
     RECT  52.128 74.461 52.686 74.551 ;
     RECT  98.244 74.461 100.638 74.551 ;
     RECT  5.004 74.461 5.166 74.579 ;
     RECT  49.572 73.507 49.59 74.579 ;
     RECT  98.244 74.551 100.71 74.579 ;
     RECT  4.176 74.461 4.194 74.615 ;
     RECT  97.416 74.309 97.506 74.615 ;
     RECT  100.62 74.579 100.71 74.615 ;
     RECT  49.5 74.587 49.518 74.624 ;
     RECT  100.692 74.615 100.71 74.651 ;
     RECT  75.132 73.579 75.15 74.695 ;
     RECT  50.724 74.281 51.297 74.731 ;
     RECT  74.916 74.695 75.15 74.731 ;
     RECT  52.128 74.551 53.262 74.759 ;
     RECT  74.124 74.587 74.142 74.821 ;
     RECT  74.916 74.731 75.258 74.821 ;
     RECT  52.128 74.759 53.19 74.849 ;
     RECT  74.124 74.821 75.258 74.849 ;
     RECT  98.244 74.579 99.897 74.849 ;
     RECT  50.436 74.731 51.297 74.885 ;
     RECT  98.244 74.849 98.802 74.885 ;
     RECT  74.124 74.849 74.718 74.921 ;
     RECT  74.124 74.921 74.142 74.957 ;
     RECT  5.94 74.461 5.958 74.965 ;
     RECT  96.192 74.047 96.246 74.965 ;
     RECT  5.616 74.965 5.958 75.001 ;
     RECT  50.58 74.885 51.297 75.001 ;
     RECT  46.764 74.731 46.782 75.029 ;
     RECT  52.128 74.849 53.154 75.155 ;
     RECT  96.048 74.965 96.246 75.211 ;
     RECT  96.048 75.211 96.75 75.245 ;
     RECT  50.58 75.001 51.354 75.271 ;
     RECT  52.128 75.155 52.254 75.271 ;
     RECT  5.616 75.001 6.462 75.299 ;
     RECT  50.58 75.271 52.254 75.389 ;
     RECT  2.304 74.491 2.697 75.425 ;
     RECT  97.488 74.615 97.506 75.425 ;
     RECT  2.415 75.425 2.697 75.541 ;
     RECT  4.536 75.001 4.806 75.541 ;
     RECT  5.616 75.299 6.03 75.541 ;
     RECT  101.16 75.505 101.178 75.541 ;
     RECT  102.564 73.409 102.582 75.541 ;
     RECT  102.528 75.541 102.582 75.581 ;
     RECT  4.32 75.541 6.03 75.659 ;
     RECT  51.015 75.389 52.254 75.659 ;
     RECT  101.016 75.541 101.178 75.659 ;
     RECT  2.415 75.541 3.15 75.695 ;
     RECT  73.836 75.397 73.854 75.695 ;
     RECT  53.064 75.155 53.154 75.811 ;
     RECT  98.244 74.885 98.262 75.811 ;
     RECT  4.32 75.659 5.886 75.821 ;
     RECT  6.804 75.541 6.822 75.839 ;
     RECT  96.732 75.245 96.75 75.869 ;
     RECT  94.215 74.075 94.497 75.901 ;
     RECT  50.04 75.811 50.202 75.937 ;
     RECT  53.064 75.811 53.55 75.965 ;
     RECT  97.704 75.811 98.262 75.965 ;
     RECT  101.016 75.659 101.142 75.965 ;
     RECT  99.615 74.849 99.897 76.009 ;
     RECT  98.244 75.965 98.262 76.045 ;
     RECT  99.615 76.009 100.278 76.045 ;
     RECT  52.128 75.659 52.254 76.081 ;
     RECT  4.32 75.821 5.742 76.109 ;
     RECT  94.215 75.901 94.662 76.109 ;
     RECT  53.532 75.965 53.55 76.171 ;
     RECT  54.684 75.397 54.702 76.171 ;
     RECT  5.58 76.109 5.742 76.199 ;
     RECT  49.86 75.937 50.202 76.199 ;
     RECT  98.244 76.045 100.278 76.199 ;
     RECT  53.532 76.171 54.702 76.207 ;
     RECT  53.532 76.207 54.738 76.235 ;
     RECT  2.415 75.695 2.826 76.253 ;
     RECT  4.32 76.109 4.698 76.351 ;
     RECT  50.184 76.199 50.202 76.351 ;
     RECT  5.58 76.199 5.598 76.397 ;
     RECT  98.244 76.199 100.062 76.397 ;
     RECT  102.564 75.581 102.582 76.411 ;
     RECT  51.015 75.659 51.297 76.441 ;
     RECT  52.128 76.081 52.578 76.441 ;
     RECT  4.284 76.351 4.698 76.505 ;
     RECT  54.252 76.235 54.738 76.505 ;
     RECT  101.124 75.965 101.142 76.505 ;
     RECT  50.184 76.351 50.238 76.577 ;
     RECT  102.024 76.411 102.582 76.577 ;
     RECT  50.22 76.577 50.238 76.621 ;
     RECT  51.015 76.441 52.578 76.621 ;
     RECT  2.415 76.253 2.697 76.651 ;
     RECT  50.22 76.621 52.578 76.739 ;
     RECT  2.304 76.651 2.697 76.775 ;
     RECT  50.22 76.739 52.434 76.775 ;
     RECT  74.124 76.207 74.142 76.775 ;
     RECT  54.72 76.505 54.738 76.811 ;
     RECT  4.572 76.505 4.698 76.891 ;
     RECT  50.22 76.775 50.238 76.919 ;
     RECT  97.344 76.855 97.362 76.939 ;
     RECT  96.696 76.939 97.362 76.973 ;
     RECT  99.615 76.397 100.062 76.981 ;
     RECT  4.572 76.891 5.166 77.045 ;
     RECT  73.836 76.783 73.854 77.045 ;
     RECT  75.672 76.441 75.69 77.045 ;
     RECT  2.415 76.775 2.697 77.083 ;
     RECT  95.724 76.981 95.742 77.117 ;
     RECT  7.815 73.769 9.342 77.161 ;
     RECT  96.696 76.973 97.254 77.161 ;
     RECT  98.244 76.397 98.694 77.161 ;
     RECT  99.615 76.981 100.242 77.161 ;
     RECT  6.336 77.125 6.354 77.165 ;
     RECT  95.256 77.161 95.274 77.213 ;
     RECT  96.192 77.161 97.254 77.315 ;
     RECT  53.388 76.891 53.406 77.359 ;
     RECT  98.244 77.161 100.242 77.359 ;
     RECT  101.016 77.161 101.034 77.359 ;
     RECT  2.415 77.083 2.754 77.431 ;
     RECT  53.388 77.359 53.622 77.459 ;
     RECT  96.696 77.315 97.254 77.459 ;
     RECT  2.415 77.431 3.438 77.515 ;
     RECT  51.015 76.775 52.434 77.521 ;
     RECT  98.244 77.359 101.034 77.521 ;
     RECT  7.308 77.161 9.342 77.549 ;
     RECT  53.388 77.459 53.514 77.549 ;
     RECT  96.912 77.459 97.254 77.555 ;
     RECT  51.015 77.521 52.578 77.563 ;
     RECT  2.304 77.515 3.438 77.585 ;
     RECT  53.388 77.549 53.442 77.585 ;
     RECT  53.424 77.585 53.442 77.693 ;
     RECT  54.684 77.593 54.702 77.729 ;
     RECT  74.592 77.593 74.61 77.855 ;
     RECT  96.912 77.555 96.93 77.855 ;
     RECT  4.572 77.045 4.806 77.863 ;
     RECT  5.652 77.431 5.67 77.863 ;
     RECT  4.572 77.863 5.67 77.971 ;
     RECT  50.688 77.563 52.578 77.971 ;
     RECT  54.72 77.971 54.738 78.089 ;
     RECT  4.356 77.971 5.67 78.091 ;
     RECT  50.472 77.971 52.578 78.125 ;
     RECT  98.244 77.521 101.178 78.125 ;
     RECT  102.528 76.577 102.582 78.139 ;
     RECT  74.232 78.061 74.25 78.395 ;
     RECT  95.724 78.469 95.742 78.509 ;
     RECT  2.34 77.585 2.934 78.511 ;
     RECT  4.356 78.091 6.21 78.601 ;
     RECT  4.032 78.601 6.21 78.629 ;
     RECT  102.024 78.139 102.582 78.629 ;
     RECT  2.34 78.511 3.258 78.665 ;
     RECT  5.292 78.629 6.21 78.665 ;
     RECT  96.66 78.511 96.678 78.665 ;
     RECT  99.615 78.125 101.034 78.665 ;
     RECT  99.615 78.665 100.314 78.701 ;
     RECT  50.472 78.125 52.506 78.781 ;
     RECT  2.34 78.665 3.042 78.811 ;
     RECT  50.184 78.781 52.506 78.899 ;
     RECT  2.304 78.811 3.042 78.935 ;
     RECT  74.7 78.601 74.718 79.205 ;
     RECT  95.832 78.667 95.85 79.205 ;
     RECT  4.032 78.629 4.374 79.213 ;
     RECT  2.415 78.935 3.042 79.241 ;
     RECT  0.108 79.177 0.126 79.277 ;
     RECT  50.508 78.899 52.506 79.321 ;
     RECT  97.38 79.141 97.398 79.321 ;
     RECT  98.244 78.125 98.334 79.321 ;
     RECT  94.215 76.109 94.497 79.411 ;
     RECT  3.852 79.213 4.374 79.475 ;
     RECT  94.215 79.411 94.662 79.547 ;
     RECT  97.38 79.321 98.334 79.547 ;
     RECT  98.136 79.547 98.334 79.555 ;
     RECT  99.615 78.701 99.897 79.555 ;
     RECT  5.292 78.665 5.706 79.591 ;
     RECT  98.136 79.555 99.897 79.591 ;
     RECT  101.052 79.411 101.07 79.591 ;
     RECT  98.136 79.591 101.286 79.613 ;
     RECT  4.536 79.591 5.706 79.661 ;
     RECT  50.508 79.321 53.154 79.661 ;
     RECT  2.415 79.241 2.697 79.675 ;
     RECT  50.508 79.661 51.354 79.709 ;
     RECT  99.216 79.613 101.286 79.709 ;
     RECT  2.304 79.675 2.697 79.745 ;
     RECT  75.42 79.591 75.438 79.745 ;
     RECT  5.292 79.661 5.706 79.853 ;
     RECT  102.564 78.629 102.582 79.867 ;
     RECT  52.344 79.661 53.154 79.951 ;
     RECT  49.86 79.861 49.878 79.979 ;
     RECT  98.136 79.613 98.442 79.979 ;
     RECT  54.72 79.951 54.738 79.987 ;
     RECT  4.536 79.661 4.554 80.015 ;
     RECT  99.216 79.709 101.034 80.015 ;
     RECT  46.764 79.825 46.782 80.051 ;
     RECT  54.72 79.987 54.81 80.051 ;
     RECT  102.024 79.867 102.582 80.087 ;
     RECT  2.415 79.745 2.697 80.095 ;
     RECT  5.58 79.853 5.706 80.095 ;
     RECT  5.58 80.095 5.778 80.141 ;
     RECT  54.792 80.051 54.81 80.159 ;
     RECT  52.344 79.951 53.298 80.249 ;
     RECT  97.164 80.095 97.362 80.249 ;
     RECT  98.136 79.979 98.334 80.249 ;
     RECT  52.344 80.249 53.262 80.285 ;
     RECT  75.204 79.951 75.222 80.285 ;
     RECT  98.136 80.249 98.262 80.285 ;
     RECT  99.216 80.015 100.746 80.285 ;
     RECT  6.696 80.131 6.714 80.429 ;
     RECT  50.832 79.709 51.354 80.527 ;
     RECT  5.58 80.141 5.598 80.555 ;
     RECT  74.376 79.987 74.394 80.555 ;
     RECT  95.292 80.395 95.31 80.555 ;
     RECT  99.615 80.285 100.746 80.555 ;
     RECT  2.415 80.095 2.826 80.573 ;
     RECT  100.728 80.555 100.746 80.591 ;
     RECT  7.815 77.549 9.342 80.635 ;
     RECT  4.428 80.635 4.446 80.671 ;
     RECT  50.58 80.527 51.354 80.671 ;
     RECT  52.2 80.401 52.326 80.671 ;
     RECT  7.2 80.635 9.342 80.672 ;
     RECT  50.58 80.671 52.326 80.789 ;
     RECT  101.016 80.761 101.034 80.933 ;
     RECT  4.248 80.671 4.446 80.941 ;
     RECT  2.415 80.573 2.697 80.971 ;
     RECT  53.064 80.285 53.262 81.031 ;
     RECT  2.304 80.971 2.697 81.095 ;
     RECT  4.248 80.941 4.59 81.095 ;
     RECT  5.364 80.905 5.382 81.211 ;
     RECT  53.064 81.031 53.334 81.211 ;
     RECT  4.68 81.211 5.382 81.239 ;
     RECT  96.264 80.671 96.282 81.301 ;
     RECT  49.5 81.211 49.518 81.329 ;
     RECT  4.68 81.239 4.698 81.365 ;
     RECT  50.832 80.789 52.326 81.409 ;
     RECT  53.064 81.211 53.55 81.409 ;
     RECT  99.615 80.555 99.897 81.409 ;
     RECT  96.264 81.301 96.426 81.437 ;
     RECT  97.164 80.249 97.182 81.445 ;
     RECT  99.615 81.409 100.998 81.445 ;
     RECT  50.832 81.409 53.55 81.481 ;
     RECT  97.164 81.445 97.254 81.481 ;
     RECT  98.244 80.285 98.262 81.481 ;
     RECT  99.396 81.445 100.998 81.481 ;
     RECT  50.832 81.481 53.766 81.485 ;
     RECT  98.244 81.481 100.998 81.485 ;
     RECT  50.004 81.451 50.022 81.509 ;
     RECT  97.164 81.481 97.398 81.509 ;
     RECT  102.564 80.087 102.582 81.595 ;
     RECT  6.804 81.481 6.822 81.599 ;
     RECT  50.94 81.485 53.766 81.599 ;
     RECT  76.14 81.409 76.158 81.599 ;
     RECT  102.528 81.595 102.582 81.599 ;
     RECT  78.015 68.369 78.297 81.607 ;
     RECT  97.38 81.509 97.398 81.635 ;
     RECT  98.244 81.485 98.802 81.635 ;
     RECT  50.94 81.599 53.658 81.743 ;
     RECT  2.415 81.095 2.697 81.751 ;
     RECT  78.015 81.607 78.642 81.779 ;
     RECT  5.868 81.307 5.886 81.841 ;
     RECT  50.94 81.743 52.038 81.869 ;
     RECT  50.94 81.869 51.966 81.905 ;
     RECT  74.052 81.679 74.07 81.905 ;
     RECT  2.415 81.751 2.79 81.931 ;
     RECT  0.108 81.835 0.126 81.965 ;
     RECT  7.815 80.672 9.342 81.985 ;
     RECT  5.868 81.841 6.318 82.021 ;
     RECT  98.244 81.635 98.262 82.021 ;
     RECT  99.615 81.485 100.998 82.021 ;
     RECT  102.528 81.599 102.546 82.027 ;
     RECT  7.092 81.985 9.342 82.061 ;
     RECT  99.615 82.021 101.178 82.139 ;
     RECT  2.415 81.931 2.898 82.175 ;
     RECT  5.472 82.021 6.318 82.175 ;
     RECT  97.92 82.021 98.262 82.175 ;
     RECT  100.728 82.139 101.178 82.175 ;
     RECT  100.728 82.175 101.142 82.211 ;
     RECT  2.415 82.175 2.697 82.267 ;
     RECT  6.156 82.175 6.318 82.349 ;
     RECT  102.024 82.027 102.546 82.381 ;
     RECT  6.3 82.349 6.318 82.409 ;
     RECT  4.932 82.291 4.95 82.445 ;
     RECT  102.024 82.381 102.582 82.493 ;
     RECT  95.724 81.985 95.742 82.525 ;
     RECT  95.508 82.525 95.742 82.553 ;
     RECT  98.064 82.175 98.262 82.561 ;
     RECT  95.508 82.553 95.526 82.637 ;
     RECT  48.852 82.291 48.87 82.651 ;
     RECT  50.976 81.905 51.297 82.651 ;
     RECT  3.996 82.561 4.014 82.687 ;
     RECT  52.2 82.651 52.218 82.715 ;
     RECT  96.624 82.561 96.858 82.715 ;
     RECT  74.664 82.291 74.682 82.723 ;
     RECT  48.78 82.651 48.87 82.795 ;
     RECT  50.832 82.651 51.297 82.831 ;
     RECT  98.064 82.561 98.622 82.831 ;
     RECT  99.615 82.139 99.897 82.831 ;
     RECT  48.78 82.795 49.302 82.877 ;
     RECT  98.064 82.831 99.897 82.877 ;
     RECT  102.024 82.493 102.042 82.925 ;
     RECT  98.208 82.877 99.897 82.949 ;
     RECT  74.664 82.723 74.754 82.985 ;
     RECT  98.244 82.949 99.897 82.985 ;
     RECT  52.992 81.743 53.658 83.129 ;
     RECT  99.615 82.985 99.897 83.191 ;
     RECT  100.764 82.211 101.142 83.191 ;
     RECT  3.996 82.687 4.59 83.219 ;
     RECT  48.78 82.877 49.05 83.219 ;
     RECT  75.492 83.101 75.51 83.219 ;
     RECT  97.2 83.101 97.362 83.219 ;
     RECT  2.304 82.267 2.697 83.255 ;
     RECT  3.996 83.219 4.086 83.255 ;
     RECT  53.172 83.129 53.658 83.255 ;
     RECT  74.664 82.985 74.682 83.255 ;
     RECT  50.256 82.831 51.297 83.419 ;
     RECT  50.004 83.419 51.297 83.489 ;
     RECT  54.576 83.101 54.594 83.497 ;
     RECT  3.996 83.255 4.014 83.525 ;
     RECT  99.615 83.191 101.142 83.525 ;
     RECT  54.576 83.497 54.882 83.597 ;
     RECT  101.124 83.525 101.142 83.641 ;
     RECT  5.436 83.605 5.454 83.645 ;
     RECT  49.032 83.219 49.05 83.669 ;
     RECT  50.256 83.489 51.297 83.731 ;
     RECT  98.244 82.985 98.802 83.731 ;
     RECT  99.615 83.525 100.314 83.731 ;
     RECT  98.244 83.731 100.314 83.755 ;
     RECT  102.564 83.323 102.582 83.755 ;
     RECT  54.576 83.597 54.702 83.759 ;
     RECT  2.34 83.255 2.697 83.767 ;
     RECT  50.256 83.731 51.858 83.795 ;
     RECT  54.576 83.759 54.594 83.795 ;
     RECT  76.284 83.497 76.302 83.795 ;
     RECT  97.776 83.755 100.314 83.795 ;
     RECT  101.124 83.641 101.214 83.795 ;
     RECT  50.292 83.795 51.858 83.831 ;
     RECT  53.568 83.255 53.658 83.875 ;
     RECT  6.372 83.641 6.39 83.903 ;
     RECT  72.615 70.565 72.897 83.911 ;
     RECT  2.34 83.767 3.222 83.995 ;
     RECT  2.304 83.995 3.222 84.029 ;
     RECT  50.292 83.831 51.297 84.029 ;
     RECT  2.304 84.029 2.697 84.065 ;
     RECT  95.724 83.995 95.742 84.065 ;
     RECT  98.244 83.795 100.314 84.101 ;
     RECT  7.815 82.061 9.342 84.181 ;
     RECT  52.74 83.875 52.758 84.181 ;
     RECT  96.516 84.109 96.534 84.181 ;
     RECT  53.568 83.875 53.802 84.209 ;
     RECT  52.308 84.181 52.758 84.271 ;
     RECT  53.568 84.209 53.73 84.271 ;
     RECT  52.308 84.271 53.73 84.299 ;
     RECT  95.868 84.181 96.678 84.299 ;
     RECT  97.488 84.181 97.506 84.299 ;
     RECT  98.244 84.101 100.134 84.299 ;
     RECT  4.248 84.001 4.266 84.307 ;
     RECT  72.615 83.911 73.17 84.335 ;
     RECT  75.96 84.181 76.158 84.335 ;
     RECT  96.516 84.299 96.678 84.335 ;
     RECT  7.668 84.181 9.342 84.365 ;
     RECT  4.248 84.307 4.374 84.451 ;
     RECT  5.652 84.181 5.67 84.451 ;
     RECT  4.248 84.451 4.518 84.605 ;
     RECT  101.124 83.795 101.178 84.685 ;
     RECT  4.356 84.605 4.518 84.721 ;
     RECT  49.5 84.037 49.518 84.721 ;
     RECT  5.292 84.451 5.67 84.749 ;
     RECT  4.356 84.721 4.554 84.805 ;
     RECT  5.58 84.749 5.67 84.808 ;
     RECT  49.32 84.721 49.518 84.839 ;
     RECT  54.504 84.451 54.522 84.875 ;
     RECT  50.832 84.029 51.297 84.907 ;
     RECT  49.608 84.883 49.626 84.991 ;
     RECT  50.364 84.907 51.297 84.991 ;
     RECT  52.308 84.299 53.01 84.991 ;
     RECT  54.648 84.955 54.738 84.991 ;
     RECT  102.528 83.755 102.582 85.051 ;
     RECT  99.615 84.299 100.134 85.081 ;
     RECT  100.908 84.685 101.178 85.081 ;
     RECT  76.14 84.335 76.158 85.109 ;
     RECT  98.244 84.299 98.874 85.109 ;
     RECT  52.128 84.991 53.01 85.133 ;
     RECT  5.58 84.808 5.742 85.145 ;
     RECT  99.615 85.081 101.178 85.145 ;
     RECT  99.615 85.145 100.746 85.261 ;
     RECT  4.356 84.805 4.806 85.289 ;
     RECT  49.608 84.991 51.297 85.289 ;
     RECT  52.128 85.133 52.938 85.289 ;
     RECT  2.415 84.065 2.697 85.291 ;
     RECT  5.688 85.145 5.742 85.339 ;
     RECT  97.056 84.883 97.074 85.339 ;
     RECT  54.648 84.991 54.81 85.387 ;
     RECT  2.304 85.291 2.697 85.415 ;
     RECT  54.648 85.387 54.918 85.415 ;
     RECT  50.004 85.289 51.297 85.421 ;
     RECT  97.056 85.339 97.182 85.483 ;
     RECT  54.9 85.415 54.918 85.487 ;
     RECT  97.056 85.483 97.47 85.523 ;
     RECT  50.94 85.421 51.297 85.531 ;
     RECT  52.128 85.289 52.542 85.531 ;
     RECT  94.215 79.547 94.497 85.531 ;
     RECT  6.804 85.531 6.822 85.621 ;
     RECT  75.888 85.387 76.122 85.685 ;
     RECT  98.244 85.109 98.658 85.801 ;
     RECT  97.056 85.523 97.074 85.891 ;
     RECT  94.215 85.531 94.662 85.915 ;
     RECT  102.024 85.051 102.582 85.915 ;
     RECT  96.336 85.891 97.074 85.949 ;
     RECT  73.908 85.621 73.926 85.955 ;
     RECT  94.215 85.915 95.202 85.955 ;
     RECT  98.028 85.801 98.658 85.955 ;
     RECT  101.988 85.915 102.582 85.955 ;
     RECT  5.688 85.339 5.778 86.035 ;
     RECT  99.576 85.261 100.746 86.035 ;
     RECT  4.14 85.801 4.338 86.071 ;
     RECT  50.004 85.421 50.166 86.071 ;
     RECT  50.94 85.531 52.542 86.071 ;
     RECT  96.336 85.949 96.354 86.071 ;
     RECT  98.244 85.955 98.658 86.071 ;
     RECT  99.576 86.035 100.926 86.071 ;
     RECT  49.968 86.071 50.166 86.189 ;
     RECT  76.464 86.071 76.482 86.189 ;
     RECT  90.648 86.071 90.666 86.189 ;
     RECT  95.688 86.071 96.354 86.189 ;
     RECT  4.14 86.071 4.482 86.225 ;
     RECT  50.94 86.071 53.262 86.225 ;
     RECT  96.336 86.189 96.354 86.225 ;
     RECT  98.244 86.071 100.926 86.305 ;
     RECT  98.244 86.305 101.214 86.339 ;
     RECT  50.94 86.225 52.83 86.341 ;
     RECT  5.616 86.035 5.778 86.431 ;
     RECT  6.804 85.621 6.858 86.431 ;
     RECT  5.616 86.431 6.858 86.443 ;
     RECT  7.815 84.365 9.342 86.443 ;
     RECT  72.615 84.335 72.897 86.467 ;
     RECT  4.608 86.341 4.626 86.495 ;
     RECT  5.616 86.443 9.342 86.611 ;
     RECT  50.58 86.341 52.83 86.621 ;
     RECT  50.58 86.621 52.398 86.639 ;
     RECT  54.252 86.611 54.27 86.701 ;
     RECT  72.615 86.467 73.566 86.765 ;
     RECT  5.544 86.611 9.342 86.801 ;
     RECT  54.252 86.701 54.738 86.801 ;
     RECT  98.244 86.339 98.514 86.845 ;
     RECT  49.5 86.875 49.518 86.881 ;
     RECT  56.415 40.877 56.697 86.881 ;
     RECT  6.228 86.801 9.342 86.909 ;
     RECT  49.284 86.881 49.518 86.999 ;
     RECT  55.692 86.881 56.697 86.999 ;
     RECT  7.092 86.909 9.342 87.035 ;
     RECT  49.5 86.999 49.518 87.035 ;
     RECT  54.936 86.881 54.954 87.035 ;
     RECT  97.956 86.845 98.514 87.035 ;
     RECT  50.58 86.639 51.894 87.151 ;
     RECT  99.615 86.339 101.214 87.151 ;
     RECT  97.956 87.035 98.262 87.197 ;
     RECT  99.432 87.151 101.214 87.211 ;
     RECT  6.228 86.909 6.246 87.269 ;
     RECT  98.028 87.197 98.262 87.269 ;
     RECT  5.436 87.151 5.454 87.305 ;
     RECT  76.932 86.773 76.95 87.305 ;
     RECT  99.432 87.211 101.646 87.305 ;
     RECT  50.508 87.151 51.894 87.421 ;
     RECT  101.628 87.305 101.646 87.449 ;
     RECT  2.415 85.415 2.697 87.451 ;
     RECT  54.144 87.421 54.162 87.511 ;
     RECT  99.432 87.305 100.602 87.539 ;
     RECT  2.304 87.451 2.697 87.575 ;
     RECT  50.508 87.421 52.11 87.575 ;
     RECT  99.432 87.539 100.062 87.575 ;
     RECT  54.108 87.511 54.162 87.583 ;
     RECT  72.615 86.765 72.897 87.583 ;
     RECT  4.356 87.499 4.374 87.691 ;
     RECT  98.244 87.269 98.262 87.781 ;
     RECT  99.432 87.575 99.897 87.781 ;
     RECT  72.615 87.583 73.206 87.845 ;
     RECT  53.028 87.421 53.046 87.925 ;
     RECT  54.108 87.583 54.702 87.953 ;
     RECT  90.648 87.781 90.666 87.953 ;
     RECT  52.884 87.925 53.046 87.961 ;
     RECT  98.244 87.781 99.897 87.989 ;
     RECT  52.884 87.961 53.082 88.051 ;
     RECT  4.068 87.691 4.518 88.075 ;
     RECT  96.408 87.961 96.426 88.079 ;
     RECT  2.34 87.575 2.697 88.115 ;
     RECT  95.364 87.961 95.382 88.115 ;
     RECT  50.724 87.575 52.11 88.123 ;
     RECT  52.884 88.051 53.118 88.123 ;
     RECT  54.144 87.953 54.702 88.151 ;
     RECT  3.816 88.075 4.518 88.231 ;
     RECT  5.292 87.691 5.31 88.231 ;
     RECT  74.664 88.123 74.682 88.231 ;
     RECT  54.684 88.151 54.702 88.259 ;
     RECT  3.744 88.231 5.31 88.349 ;
     RECT  50.724 88.123 53.118 88.363 ;
     RECT  3.744 88.349 3.762 88.385 ;
     RECT  99.432 87.989 99.897 88.465 ;
     RECT  99.432 88.465 100.098 88.501 ;
     RECT  100.908 88.231 100.926 88.501 ;
     RECT  102.564 85.955 102.582 88.507 ;
     RECT  4.536 88.349 4.77 88.529 ;
     RECT  50.436 88.363 53.118 88.603 ;
     RECT  74.664 88.231 75.222 88.619 ;
     RECT  4.536 88.529 4.554 88.655 ;
     RECT  74.664 88.619 75.042 88.655 ;
     RECT  99.432 88.501 100.926 88.655 ;
     RECT  46.764 87.853 46.782 88.727 ;
     RECT  102.024 88.507 102.582 88.727 ;
     RECT  98.244 87.989 98.658 88.735 ;
     RECT  99.615 88.655 100.926 88.735 ;
     RECT  50.22 88.603 53.118 88.771 ;
     RECT  97.776 88.735 98.658 88.771 ;
     RECT  97.776 88.771 98.73 88.781 ;
     RECT  50.22 88.771 53.802 88.889 ;
     RECT  99.615 88.735 101.034 88.889 ;
     RECT  2.415 88.115 2.697 88.897 ;
     RECT  98.244 88.781 98.73 88.925 ;
     RECT  51.015 88.889 53.802 89.033 ;
     RECT  52.992 89.033 53.802 89.041 ;
     RECT  2.415 88.897 2.862 89.159 ;
     RECT  6.372 88.555 6.39 89.195 ;
     RECT  52.992 89.041 53.874 89.195 ;
     RECT  52.992 89.195 53.01 89.267 ;
     RECT  53.748 89.195 53.874 89.275 ;
     RECT  96.048 89.269 96.066 89.309 ;
     RECT  2.415 89.159 2.79 89.429 ;
     RECT  49.968 89.131 50.166 89.429 ;
     RECT  96.192 89.311 96.21 89.429 ;
     RECT  51.015 89.033 52.218 89.465 ;
     RECT  53.748 89.275 53.946 89.465 ;
     RECT  75.024 88.655 75.042 89.465 ;
     RECT  96.984 89.311 97.002 89.465 ;
     RECT  5.004 89.311 5.202 89.545 ;
     RECT  5.004 89.545 5.598 89.581 ;
     RECT  2.415 89.429 2.697 89.611 ;
     RECT  51.015 89.465 51.297 89.671 ;
     RECT  53.82 89.465 53.946 89.671 ;
     RECT  102.528 88.727 102.582 89.699 ;
     RECT  2.304 89.611 2.697 89.735 ;
     RECT  3.96 89.473 3.978 89.735 ;
     RECT  4.716 89.581 5.598 89.735 ;
     RECT  53.82 89.671 53.982 89.735 ;
     RECT  5.58 89.735 5.598 89.851 ;
     RECT  52.02 89.465 52.218 89.851 ;
     RECT  75.564 89.707 75.582 89.851 ;
     RECT  98.244 88.925 98.262 89.851 ;
     RECT  50.976 89.671 51.297 89.941 ;
     RECT  75.564 89.851 75.798 89.977 ;
     RECT  97.056 89.941 97.218 89.981 ;
     RECT  53.856 89.735 53.982 90.005 ;
     RECT  74.772 89.581 74.79 90.005 ;
     RECT  0.54 89.977 0.558 90.077 ;
     RECT  5.58 89.851 5.778 90.077 ;
     RECT  101.16 89.671 101.178 90.085 ;
     RECT  99.615 88.889 100.422 90.121 ;
     RECT  101.16 90.085 101.214 90.121 ;
     RECT  75.564 89.977 75.87 90.149 ;
     RECT  97.056 89.981 97.074 90.149 ;
     RECT  45.615 2.413 45.897 90.211 ;
     RECT  99.216 90.121 101.214 90.239 ;
     RECT  50.076 89.429 50.166 90.247 ;
     RECT  50.94 89.941 51.297 90.247 ;
     RECT  53.928 90.005 53.982 90.275 ;
     RECT  98.244 89.851 98.442 90.275 ;
     RECT  52.02 89.851 52.326 90.391 ;
     RECT  50.076 90.247 51.297 90.413 ;
     RECT  102.564 89.699 102.582 90.481 ;
     RECT  50.724 90.413 51.297 90.509 ;
     RECT  53.928 90.275 53.946 90.509 ;
     RECT  4.5 89.851 4.59 90.589 ;
     RECT  45.615 90.211 46.242 90.605 ;
     RECT  54.72 89.131 54.738 90.617 ;
     RECT  7.815 87.035 9.342 90.619 ;
     RECT  6.084 90.517 6.102 90.653 ;
     RECT  7.308 90.619 9.342 90.661 ;
     RECT  94.215 85.955 94.497 90.661 ;
     RECT  102.564 90.481 102.618 90.701 ;
     RECT  50.94 90.509 51.297 90.751 ;
     RECT  52.02 90.391 52.794 90.751 ;
     RECT  72.615 87.845 72.897 90.751 ;
     RECT  73.62 90.661 73.638 90.751 ;
     RECT  94.215 90.661 94.59 90.751 ;
     RECT  72.615 90.751 73.638 90.779 ;
     RECT  4.5 90.589 4.95 90.815 ;
     RECT  7.02 90.661 9.342 90.815 ;
     RECT  50.94 90.751 52.794 90.815 ;
     RECT  60.984 90.517 61.002 90.815 ;
     RECT  75.24 90.481 75.258 90.815 ;
     RECT  72.615 90.779 73.422 90.851 ;
     RECT  94.215 90.751 94.662 90.851 ;
     RECT  98.244 90.275 98.262 90.895 ;
     RECT  2.415 89.735 2.697 90.907 ;
     RECT  51.015 90.815 52.794 90.923 ;
     RECT  99.216 90.239 101.142 90.931 ;
     RECT  98.1 90.895 98.262 90.941 ;
     RECT  4.5 90.815 4.59 91.021 ;
     RECT  52.2 90.923 52.794 91.021 ;
     RECT  98.244 90.941 98.262 91.021 ;
     RECT  99.036 90.931 101.142 91.021 ;
     RECT  7.02 90.815 7.038 91.049 ;
     RECT  49.752 90.751 49.77 91.049 ;
     RECT  95.364 90.931 95.382 91.085 ;
     RECT  46.764 91.021 46.782 91.121 ;
     RECT  52.2 91.021 53.046 91.201 ;
     RECT  98.244 91.021 101.142 91.291 ;
     RECT  52.2 91.201 53.514 91.355 ;
     RECT  98.244 91.291 101.178 91.391 ;
     RECT  3.924 91.021 4.59 91.579 ;
     RECT  52.2 91.355 52.326 91.589 ;
     RECT  98.244 91.391 101.106 91.589 ;
     RECT  3.6 91.579 4.59 91.741 ;
     RECT  5.364 91.165 5.382 91.741 ;
     RECT  51.015 90.923 51.297 91.741 ;
     RECT  52.2 91.589 52.29 91.741 ;
     RECT  53.244 91.355 53.514 91.741 ;
     RECT  49.968 91.201 50.166 91.757 ;
     RECT  48.312 91.741 48.33 91.771 ;
     RECT  49.968 91.757 49.986 91.805 ;
     RECT  48.168 91.771 48.33 91.859 ;
     RECT  2.304 90.907 2.697 91.895 ;
     RECT  51.015 91.741 52.29 91.895 ;
     RECT  99.432 91.589 101.106 91.895 ;
     RECT  98.244 91.589 98.622 91.975 ;
     RECT  3.528 91.741 5.382 92.011 ;
     RECT  53.244 91.741 53.55 92.011 ;
     RECT  53.244 92.011 53.586 92.101 ;
     RECT  3.528 92.011 5.814 92.129 ;
     RECT  99.432 91.895 99.954 92.129 ;
     RECT  3.528 92.129 3.546 92.165 ;
     RECT  75.672 92.011 75.69 92.165 ;
     RECT  51.015 91.895 52.254 92.201 ;
     RECT  53.1 92.101 53.586 92.201 ;
     RECT  2.415 91.895 2.697 92.203 ;
     RECT  101.016 91.895 101.106 92.245 ;
     RECT  53.172 92.201 53.586 92.273 ;
     RECT  53.28 92.273 53.586 92.281 ;
     RECT  97.668 91.975 98.622 92.281 ;
     RECT  63.288 92.137 63.306 92.309 ;
     RECT  97.416 92.281 98.622 92.309 ;
     RECT  61.815 2.413 62.097 92.371 ;
     RECT  101.016 92.245 101.214 92.395 ;
     RECT  53.28 92.281 53.658 92.399 ;
     RECT  2.415 92.203 3.222 92.435 ;
     RECT  49.392 92.011 49.41 92.435 ;
     RECT  52.092 92.201 52.254 92.435 ;
     RECT  71.82 92.137 71.838 92.435 ;
     RECT  4.284 92.129 5.814 92.471 ;
     RECT  51.015 92.201 51.297 92.515 ;
     RECT  97.416 92.309 97.434 92.515 ;
     RECT  6.984 92.515 7.002 92.551 ;
     RECT  7.815 90.815 9.342 92.551 ;
     RECT  97.128 92.515 97.434 92.551 ;
     RECT  52.092 92.435 52.11 92.579 ;
     RECT  74.196 92.407 74.214 92.579 ;
     RECT  2.415 92.435 2.697 92.635 ;
     RECT  6.984 92.551 9.342 92.669 ;
     RECT  2.304 92.635 2.697 92.705 ;
     RECT  4.284 92.471 5.562 92.705 ;
     RECT  49.572 92.551 49.59 92.705 ;
     RECT  53.28 92.399 53.406 92.705 ;
     RECT  99.615 92.129 99.954 92.785 ;
     RECT  101.016 92.395 101.646 92.785 ;
     RECT  50.508 92.515 51.297 92.821 ;
     RECT  102.564 90.701 102.582 92.861 ;
     RECT  98.244 92.309 98.622 92.875 ;
     RECT  99.615 92.785 101.646 92.875 ;
     RECT  96.912 92.551 97.434 92.909 ;
     RECT  95.652 92.515 95.67 92.911 ;
     RECT  6.984 92.669 7.002 92.923 ;
     RECT  98.244 92.875 101.646 92.939 ;
     RECT  6.804 92.923 7.002 92.957 ;
     RECT  61.815 92.371 62.73 92.975 ;
     RECT  4.284 92.705 5.49 93.091 ;
     RECT  74.7 93.055 74.718 93.091 ;
     RECT  3.996 93.091 5.49 93.119 ;
     RECT  64.476 92.947 64.494 93.119 ;
     RECT  101.484 92.939 101.646 93.119 ;
     RECT  95.652 92.911 95.85 93.209 ;
     RECT  53.316 92.705 53.406 93.245 ;
     RECT  74.7 93.091 74.934 93.245 ;
     RECT  95.652 93.209 95.67 93.389 ;
     RECT  5.328 93.119 5.49 93.451 ;
     RECT  61.815 92.975 62.097 93.451 ;
     RECT  49.716 92.821 51.297 93.479 ;
     RECT  98.244 92.939 100.602 93.479 ;
     RECT  3.996 93.119 4.554 93.515 ;
     RECT  5.328 93.451 5.562 93.515 ;
     RECT  6.804 92.957 6.822 93.631 ;
     RECT  50.184 93.479 51.297 93.631 ;
     RECT  52.2 93.361 52.218 93.631 ;
     RECT  53.316 93.245 53.334 93.631 ;
     RECT  6.48 93.631 6.822 93.749 ;
     RECT  4.536 93.515 4.554 93.785 ;
     RECT  50.184 93.631 53.334 93.785 ;
     RECT  101.484 93.119 101.502 93.857 ;
     RECT  99.54 93.479 100.602 93.865 ;
     RECT  2.415 92.705 2.697 93.931 ;
     RECT  48.852 93.757 48.87 94.019 ;
     RECT  64.26 93.901 64.278 94.019 ;
     RECT  99.54 93.865 101.142 94.019 ;
     RECT  2.304 93.931 2.697 94.055 ;
     RECT  61.56 93.451 62.097 94.055 ;
     RECT  75.24 93.901 75.258 94.055 ;
     RECT  94.215 90.851 94.497 94.075 ;
     RECT  96.912 92.909 96.93 94.075 ;
     RECT  98.244 93.479 98.766 94.075 ;
     RECT  7.815 92.669 9.342 94.171 ;
     RECT  94.215 94.075 94.626 94.171 ;
     RECT  72.615 90.851 72.897 94.261 ;
     RECT  73.62 94.171 73.638 94.261 ;
     RECT  3.636 94.027 3.654 94.289 ;
     RECT  6.804 93.749 6.822 94.289 ;
     RECT  7.74 94.171 9.342 94.289 ;
     RECT  72.615 94.261 73.638 94.289 ;
     RECT  94.215 94.171 94.77 94.289 ;
     RECT  96.912 94.075 98.766 94.289 ;
     RECT  72.615 94.289 73.422 94.361 ;
     RECT  54.72 94.297 54.738 94.397 ;
     RECT  96.912 94.289 96.93 94.469 ;
     RECT  6.948 94.441 6.966 94.559 ;
     RECT  95.544 94.441 95.562 94.595 ;
     RECT  99.54 94.019 100.71 94.595 ;
     RECT  98.244 94.289 98.766 94.639 ;
     RECT  2.34 94.055 2.697 94.795 ;
     RECT  60.984 94.531 61.002 94.865 ;
     RECT  5.328 93.515 5.418 94.945 ;
     RECT  99.615 94.595 100.71 94.945 ;
     RECT  3.852 94.441 3.978 94.981 ;
     RECT  5.04 94.945 5.418 94.981 ;
     RECT  54.216 94.711 54.234 94.981 ;
     RECT  99.615 94.945 100.962 94.981 ;
     RECT  50.184 93.785 52.794 95.071 ;
     RECT  3.852 94.981 5.418 95.099 ;
     RECT  54.144 94.981 54.234 95.099 ;
     RECT  99.615 94.981 101.034 95.099 ;
     RECT  3.852 95.099 3.978 95.135 ;
     RECT  65.052 94.711 65.07 95.135 ;
     RECT  75.636 94.801 75.654 95.135 ;
     RECT  98.244 94.639 98.874 95.135 ;
     RECT  3.888 95.135 3.978 95.171 ;
     RECT  100.908 95.099 101.034 95.215 ;
     RECT  50.184 95.071 53.262 95.369 ;
     RECT  100.908 95.215 101.214 95.369 ;
     RECT  74.124 95.071 74.142 95.405 ;
     RECT  5.04 95.099 5.418 95.521 ;
     RECT  98.244 95.135 98.262 95.521 ;
     RECT  99.615 95.099 100.098 95.521 ;
     RECT  5.04 95.521 6.03 95.549 ;
     RECT  5.22 95.549 6.03 95.639 ;
     RECT  99.108 95.521 100.098 95.639 ;
     RECT  54.504 95.521 54.522 95.647 ;
     RECT  61.815 94.055 62.097 95.647 ;
     RECT  3.888 95.171 3.906 95.675 ;
     RECT  98.172 95.521 98.262 95.675 ;
     RECT  50.184 95.369 52.398 95.693 ;
     RECT  2.304 94.795 2.697 95.791 ;
     RECT  5.328 95.639 6.03 95.819 ;
     RECT  53.28 95.485 53.298 95.881 ;
     RECT  54.504 95.647 54.918 95.881 ;
     RECT  49.176 95.791 49.194 95.909 ;
     RECT  61.56 95.647 62.097 95.945 ;
     RECT  100.908 95.369 100.926 95.945 ;
     RECT  101.7 95.851 101.718 96.017 ;
     RECT  99.615 95.639 100.098 96.025 ;
     RECT  2.304 95.791 2.79 96.061 ;
     RECT  97.236 95.179 97.254 96.061 ;
     RECT  46.764 95.917 46.782 96.089 ;
     RECT  5.328 95.819 5.994 96.179 ;
     RECT  54.504 95.881 54.954 96.179 ;
     RECT  99.615 96.025 100.638 96.179 ;
     RECT  2.304 96.061 3.15 96.215 ;
     RECT  97.2 96.061 97.362 96.215 ;
     RECT  94.215 94.289 94.497 96.283 ;
     RECT  96.264 95.755 96.282 96.317 ;
     RECT  51.015 95.693 52.398 96.331 ;
     RECT  53.28 95.881 53.442 96.331 ;
     RECT  54.504 96.179 54.738 96.331 ;
     RECT  74.124 96.151 74.142 96.485 ;
     RECT  94.215 96.283 94.986 96.485 ;
     RECT  99.615 96.179 100.314 96.529 ;
     RECT  51.015 96.331 53.442 96.565 ;
     RECT  90.648 96.421 90.666 96.593 ;
     RECT  3.996 96.331 4.014 96.601 ;
     RECT  5.328 96.179 5.346 96.601 ;
     RECT  98.244 95.675 98.262 96.601 ;
     RECT  50.868 96.565 53.442 96.629 ;
     RECT  95.76 96.529 95.922 96.629 ;
     RECT  3.816 96.601 4.158 96.719 ;
     RECT  52.524 96.629 53.442 96.719 ;
     RECT  76.212 96.601 76.23 96.719 ;
     RECT  97.596 96.601 98.262 96.719 ;
     RECT  99.072 96.529 100.314 96.719 ;
     RECT  64.512 96.421 64.53 96.727 ;
     RECT  52.524 96.719 52.542 96.755 ;
     RECT  64.512 96.727 64.71 96.755 ;
     RECT  95.904 96.629 95.922 96.755 ;
     RECT  53.388 96.719 53.442 96.763 ;
     RECT  54.288 96.331 54.738 96.763 ;
     RECT  50.076 95.881 50.094 96.835 ;
     RECT  49.932 96.835 50.094 96.859 ;
     RECT  50.868 96.629 51.297 96.859 ;
     RECT  97.992 96.719 98.262 96.871 ;
     RECT  49.932 96.859 51.297 96.893 ;
     RECT  64.692 96.755 64.71 96.899 ;
     RECT  2.415 96.215 2.862 96.955 ;
     RECT  99.504 96.719 100.314 96.961 ;
     RECT  7.815 94.289 9.342 96.997 ;
     RECT  2.304 96.955 2.862 97.025 ;
     RECT  3.816 96.719 4.014 97.025 ;
     RECT  53.388 96.763 54.738 97.025 ;
     RECT  61.815 95.945 62.097 97.033 ;
     RECT  4.932 96.601 5.346 97.105 ;
     RECT  2.415 97.025 2.862 97.141 ;
     RECT  75.24 96.763 75.258 97.141 ;
     RECT  78.015 81.779 78.297 97.141 ;
     RECT  99.504 96.961 100.422 97.141 ;
     RECT  102.564 93.691 102.582 97.147 ;
     RECT  4.932 97.105 5.49 97.169 ;
     RECT  74.664 97.141 75.258 97.231 ;
     RECT  53.496 97.025 53.658 97.259 ;
     RECT  73.944 97.231 75.258 97.259 ;
     RECT  76.356 97.141 76.374 97.259 ;
     RECT  97.992 96.871 98.694 97.259 ;
     RECT  102.024 97.147 102.582 97.259 ;
     RECT  53.496 97.259 53.514 97.295 ;
     RECT  61.815 97.033 62.514 97.295 ;
     RECT  75.24 97.259 75.258 97.295 ;
     RECT  99.504 97.141 101.106 97.295 ;
     RECT  73.944 97.259 73.962 97.331 ;
     RECT  49.968 96.893 51.297 97.411 ;
     RECT  7.164 96.997 9.342 97.435 ;
     RECT  78.015 97.141 78.642 97.439 ;
     RECT  5.328 97.169 5.49 97.469 ;
     RECT  6.624 97.435 9.342 97.469 ;
     RECT  97.992 97.259 98.55 97.469 ;
     RECT  54.504 97.025 54.738 97.565 ;
     RECT  102.024 97.259 102.042 97.573 ;
     RECT  10.764 97.501 10.782 97.601 ;
     RECT  101.988 97.573 102.042 97.613 ;
     RECT  54.72 97.565 54.738 97.637 ;
     RECT  49.968 97.411 52.002 97.681 ;
     RECT  6.624 97.469 6.786 97.709 ;
     RECT  49.968 97.681 52.218 97.771 ;
     RECT  6.768 97.709 6.786 97.799 ;
     RECT  2.415 97.141 3.402 97.807 ;
     RECT  49.968 97.771 52.362 97.835 ;
     RECT  2.304 97.807 3.402 97.853 ;
     RECT  52.2 97.835 52.362 97.951 ;
     RECT  96.552 97.267 96.57 98.041 ;
     RECT  97.992 97.469 98.262 98.041 ;
     RECT  99.504 97.295 100.638 98.041 ;
     RECT  75.564 97.501 75.582 98.105 ;
     RECT  2.415 97.853 3.402 98.221 ;
     RECT  49.968 97.835 51.297 98.221 ;
     RECT  94.215 96.485 94.497 98.221 ;
     RECT  97.632 98.041 98.262 98.221 ;
     RECT  99.504 98.041 100.89 98.221 ;
     RECT  61.815 97.295 62.097 98.311 ;
     RECT  2.415 98.221 3.51 98.339 ;
     RECT  96.552 98.041 96.714 98.339 ;
     RECT  0.108 98.251 0.126 98.381 ;
     RECT  97.632 98.221 100.89 98.381 ;
     RECT  72.615 94.361 72.897 98.491 ;
     RECT  97.632 98.381 98.262 98.491 ;
     RECT  94.215 98.221 94.662 98.519 ;
     RECT  96.552 98.339 96.57 98.573 ;
     RECT  61.815 98.311 62.154 98.581 ;
     RECT  97.488 98.491 98.262 98.581 ;
     RECT  5.328 97.469 5.346 98.587 ;
     RECT  52.2 97.951 52.866 98.609 ;
     RECT  64.26 98.491 64.278 98.609 ;
     RECT  61.56 98.581 62.154 98.617 ;
     RECT  2.415 98.339 3.366 98.621 ;
     RECT  2.415 98.621 3.114 98.645 ;
     RECT  72.615 98.491 72.99 98.645 ;
     RECT  99.072 98.381 100.89 98.645 ;
     RECT  97.416 98.581 98.262 98.669 ;
     RECT  61.56 98.617 62.766 98.681 ;
     RECT  2.415 98.645 2.697 98.683 ;
     RECT  73.8 98.581 73.818 98.717 ;
     RECT  49.608 98.221 51.297 98.725 ;
     RECT  97.416 98.669 97.434 98.753 ;
     RECT  4.788 98.587 5.346 98.761 ;
     RECT  76.32 98.491 76.338 98.789 ;
     RECT  102.564 98.011 102.582 98.875 ;
     RECT  4.392 98.761 5.742 98.879 ;
     RECT  102.528 98.875 102.582 98.879 ;
     RECT  4.392 98.879 4.41 98.915 ;
     RECT  99.072 98.645 100.422 98.915 ;
     RECT  5.148 98.879 5.742 98.951 ;
     RECT  49.608 98.725 52.11 99.023 ;
     RECT  48.708 98.923 48.726 99.031 ;
     RECT  48.636 99.031 48.726 99.121 ;
     RECT  48.636 99.121 49.086 99.149 ;
     RECT  99.216 98.915 100.422 99.149 ;
     RECT  6.804 98.959 6.822 99.157 ;
     RECT  2.304 98.683 2.697 99.185 ;
     RECT  5.148 98.951 5.49 99.185 ;
     RECT  6.804 99.157 7.002 99.197 ;
     RECT  50.148 99.023 52.11 99.197 ;
     RECT  53.028 99.031 53.046 99.301 ;
     RECT  61.815 98.681 62.766 99.301 ;
     RECT  102.528 98.879 102.546 99.307 ;
     RECT  72.615 98.645 72.897 99.391 ;
     RECT  94.215 98.519 94.497 99.391 ;
     RECT  99.615 99.149 100.422 99.391 ;
     RECT  101.16 98.761 101.178 99.391 ;
     RECT  6.804 99.197 6.822 99.419 ;
     RECT  53.028 99.301 53.658 99.419 ;
     RECT  99.615 99.391 101.178 99.419 ;
     RECT  5.148 99.185 5.346 99.455 ;
     RECT  60.984 99.121 61.002 99.455 ;
     RECT  53.64 99.419 53.658 99.535 ;
     RECT  72.615 99.391 73.494 99.535 ;
     RECT  94.215 99.391 94.662 99.535 ;
     RECT  2.415 99.185 2.697 99.571 ;
     RECT  72.615 99.535 73.674 99.571 ;
     RECT  98.244 98.669 98.262 99.571 ;
     RECT  53.64 99.535 53.73 99.581 ;
     RECT  53.64 99.581 53.658 99.599 ;
     RECT  96.336 99.571 96.354 99.629 ;
     RECT  48.924 99.149 49.086 99.689 ;
     RECT  72.615 99.571 74.214 99.689 ;
     RECT  94.215 99.535 94.986 99.689 ;
     RECT  54.648 99.571 54.666 99.725 ;
     RECT  61.815 99.301 62.802 99.725 ;
     RECT  72.615 99.689 73.494 99.725 ;
     RECT  102.024 99.307 102.546 99.739 ;
     RECT  72.615 99.725 73.422 99.833 ;
     RECT  5.328 99.455 5.346 99.931 ;
     RECT  50.472 99.197 52.11 99.931 ;
     RECT  6.588 99.841 6.606 99.959 ;
     RECT  2.415 99.571 3.114 99.967 ;
     RECT  54.72 99.841 54.738 99.967 ;
     RECT  4.572 99.931 4.59 99.995 ;
     RECT  50.472 99.931 52.29 99.995 ;
     RECT  96.48 99.697 96.498 99.995 ;
     RECT  5.328 99.931 5.67 100.003 ;
     RECT  50.724 99.995 52.29 100.031 ;
     RECT  54.72 99.967 55.098 100.067 ;
     RECT  100.62 99.419 101.178 100.075 ;
     RECT  2.412 99.967 3.114 100.111 ;
     RECT  4.392 100.039 4.41 100.111 ;
     RECT  98.244 99.571 98.478 100.111 ;
     RECT  58.68 99.931 58.698 100.139 ;
     RECT  102.024 99.739 102.582 100.205 ;
     RECT  46.764 99.841 46.782 100.229 ;
     RECT  100.62 100.075 101.286 100.229 ;
     RECT  64.62 99.967 64.638 100.237 ;
     RECT  2.412 100.111 3.402 100.265 ;
     RECT  4.284 100.111 4.41 100.265 ;
     RECT  54.72 100.067 54.918 100.265 ;
     RECT  64.62 100.237 64.818 100.265 ;
     RECT  101.088 100.229 101.286 100.265 ;
     RECT  98.244 100.111 98.694 100.349 ;
     RECT  99.615 99.419 99.897 100.381 ;
     RECT  64.8 100.265 64.818 100.409 ;
     RECT  2.412 100.265 2.697 100.411 ;
     RECT  97.236 99.841 97.254 100.471 ;
     RECT  101.088 100.265 101.106 100.499 ;
     RECT  76.068 99.931 76.086 100.535 ;
     RECT  99.576 100.381 100.35 100.535 ;
     RECT  5.328 100.003 5.814 100.651 ;
     RECT  99.576 100.535 100.026 100.651 ;
     RECT  52.56 100.651 52.578 100.741 ;
     RECT  97.056 100.471 97.254 100.741 ;
     RECT  5.328 100.651 5.886 100.769 ;
     RECT  99.432 100.651 100.026 100.769 ;
     RECT  60.984 100.201 61.002 100.805 ;
     RECT  99.576 100.769 100.026 100.805 ;
     RECT  96.84 100.741 97.254 100.885 ;
     RECT  96.768 100.885 97.254 100.913 ;
     RECT  50.724 100.031 51.714 100.921 ;
     RECT  52.56 100.741 52.83 100.921 ;
     RECT  6.804 100.921 6.822 100.987 ;
     RECT  49.572 100.111 49.59 101.011 ;
     RECT  74.592 100.741 74.61 101.011 ;
     RECT  49.536 101.011 49.59 101.035 ;
     RECT  50.4 100.921 53.226 101.035 ;
     RECT  96.768 100.913 96.858 101.039 ;
     RECT  49.536 101.035 53.226 101.075 ;
     RECT  2.304 100.411 2.697 101.191 ;
     RECT  94.215 99.689 94.842 101.191 ;
     RECT  98.244 100.349 98.262 101.191 ;
     RECT  74.232 101.011 74.61 101.309 ;
     RECT  94.215 101.191 95.202 101.309 ;
     RECT  50.436 101.075 53.226 101.345 ;
     RECT  74.232 101.309 74.25 101.345 ;
     RECT  97.704 101.191 98.262 101.345 ;
     RECT  52.776 101.345 53.226 101.381 ;
     RECT  6.3 100.987 6.822 101.453 ;
     RECT  7.815 97.469 9.342 101.461 ;
     RECT  100.62 101.281 100.638 101.461 ;
     RECT  102.564 100.205 102.582 101.467 ;
     RECT  7.236 101.461 9.342 101.579 ;
     RECT  46.764 101.461 46.782 101.579 ;
     RECT  49.536 101.075 49.662 101.579 ;
     RECT  75.132 101.461 75.366 101.579 ;
     RECT  102.024 101.467 102.582 101.579 ;
     RECT  53.316 101.425 53.334 101.615 ;
     RECT  75.132 101.579 75.258 101.615 ;
     RECT  96.84 101.039 96.858 101.615 ;
     RECT  100.62 101.461 101.178 101.615 ;
     RECT  100.62 101.615 100.854 101.651 ;
     RECT  70.704 101.551 70.722 101.687 ;
     RECT  3.996 100.921 4.014 101.695 ;
     RECT  4.932 100.987 5.202 101.695 ;
     RECT  2.304 101.191 3.222 101.731 ;
     RECT  3.996 101.695 5.202 101.731 ;
     RECT  2.304 101.731 5.67 101.741 ;
     RECT  49.5 101.695 49.518 101.741 ;
     RECT  3.456 101.741 5.67 101.849 ;
     RECT  98.244 101.345 98.262 101.851 ;
     RECT  3.744 101.849 5.67 101.885 ;
     RECT  50.436 101.345 51.93 101.885 ;
     RECT  98.244 101.851 98.334 101.891 ;
     RECT  94.215 101.309 94.662 101.993 ;
     RECT  99.615 100.805 99.897 102.001 ;
     RECT  100.62 101.651 100.782 102.001 ;
     RECT  98.244 101.891 98.262 102.091 ;
     RECT  3.744 101.885 4.77 102.155 ;
     RECT  75.24 101.615 75.258 102.155 ;
     RECT  5.652 101.885 5.67 102.271 ;
     RECT  4.752 102.155 4.77 102.317 ;
     RECT  6.912 102.271 7.074 102.317 ;
     RECT  97.992 102.091 98.262 102.331 ;
     RECT  102.024 101.579 102.042 102.331 ;
     RECT  3.744 102.155 3.762 102.425 ;
     RECT  6.948 102.317 7.074 102.461 ;
     RECT  102.024 102.331 102.582 102.497 ;
     RECT  99.615 102.001 100.782 102.505 ;
     RECT  50.472 101.885 51.93 102.541 ;
     RECT  52.74 102.271 52.758 102.541 ;
     RECT  99.615 102.505 101.034 102.541 ;
     RECT  96.588 102.619 96.606 102.631 ;
     RECT  5.652 102.271 5.706 102.659 ;
     RECT  50.472 102.541 53.046 102.667 ;
     RECT  2.304 101.741 2.697 102.695 ;
     RECT  99.072 102.541 101.034 102.695 ;
     RECT  50.472 102.667 53.19 102.811 ;
     RECT  49.932 102.811 53.19 102.839 ;
     RECT  3.42 102.811 3.438 102.929 ;
     RECT  6.948 102.461 6.966 102.929 ;
     RECT  49.932 102.839 52.902 102.929 ;
     RECT  74.268 102.397 74.286 102.965 ;
     RECT  95.508 102.937 95.526 102.989 ;
     RECT  99.615 102.695 101.034 103.045 ;
     RECT  90.648 102.901 90.666 103.073 ;
     RECT  2.34 102.695 2.697 103.081 ;
     RECT  5.652 102.659 5.67 103.081 ;
     RECT  97.848 102.331 98.262 103.081 ;
     RECT  46.764 102.937 46.782 103.109 ;
     RECT  2.34 103.081 3.078 103.199 ;
     RECT  99.615 103.045 101.214 103.199 ;
     RECT  5.148 103.081 5.67 103.235 ;
     RECT  50.184 102.929 52.866 103.235 ;
     RECT  96.588 102.631 96.75 103.235 ;
     RECT  97.668 103.081 98.262 103.235 ;
     RECT  4.464 103.315 4.626 103.351 ;
     RECT  96.696 103.235 96.75 103.351 ;
     RECT  2.34 103.199 2.826 103.435 ;
     RECT  94.215 101.993 94.497 103.441 ;
     RECT  3.96 103.351 4.626 103.469 ;
     RECT  50.184 103.235 51.858 103.469 ;
     RECT  96.696 103.351 96.786 103.469 ;
     RECT  52.596 103.235 52.866 103.505 ;
     RECT  74.88 103.351 74.898 103.505 ;
     RECT  99.615 103.199 101.178 103.541 ;
     RECT  94.215 103.441 94.662 103.612 ;
     RECT  5.364 103.235 5.67 103.621 ;
     RECT  6.804 103.081 6.894 103.621 ;
     RECT  99.615 103.541 100.674 103.621 ;
     RECT  7.815 101.579 9.342 103.711 ;
     RECT  99.504 103.621 100.674 103.711 ;
     RECT  94.215 103.612 94.698 103.739 ;
     RECT  3.96 103.469 4.482 103.757 ;
     RECT  2.304 103.435 2.826 103.775 ;
     RECT  97.884 103.235 98.262 103.775 ;
     RECT  54.648 103.747 54.666 103.847 ;
     RECT  5.364 103.621 6.894 103.891 ;
     RECT  7.668 103.711 9.342 103.891 ;
     RECT  50.184 103.469 51.822 103.891 ;
     RECT  52.776 103.505 52.866 103.891 ;
     RECT  2.415 103.775 2.826 103.901 ;
     RECT  5.364 103.891 9.342 104.009 ;
     RECT  3.96 103.757 3.978 104.045 ;
     RECT  50.04 103.891 51.822 104.045 ;
     RECT  5.364 104.009 6.75 104.189 ;
     RECT  52.776 103.891 53.082 104.251 ;
     RECT  102.564 102.497 102.582 104.251 ;
     RECT  6.228 104.189 6.75 104.279 ;
     RECT  52.02 104.251 53.226 104.287 ;
     RECT  74.484 103.711 74.502 104.315 ;
     RECT  99.18 103.711 100.674 104.315 ;
     RECT  0.54 104.287 0.558 104.333 ;
     RECT  52.02 104.287 53.658 104.351 ;
     RECT  99.288 104.315 100.674 104.431 ;
     RECT  102.564 104.251 102.618 104.525 ;
     RECT  6.228 104.279 6.246 104.549 ;
     RECT  52.02 104.351 52.542 104.549 ;
     RECT  99.288 104.431 100.71 104.549 ;
     RECT  5.256 104.287 5.274 104.585 ;
     RECT  53.64 104.351 53.658 104.585 ;
     RECT  50.04 104.045 51.297 104.665 ;
     RECT  7.632 104.009 9.342 104.693 ;
     RECT  95.832 104.251 95.85 104.701 ;
     RECT  98.244 103.775 98.262 104.701 ;
     RECT  7.668 104.693 9.342 104.729 ;
     RECT  2.415 103.901 2.697 104.731 ;
     RECT  48.024 104.701 48.042 104.819 ;
     RECT  49.5 104.665 51.297 104.819 ;
     RECT  2.304 104.731 2.697 104.855 ;
     RECT  96.624 104.701 96.642 104.855 ;
     RECT  4.356 104.827 4.374 104.864 ;
     RECT  75.132 104.521 75.15 104.899 ;
     RECT  75.132 104.899 75.87 104.935 ;
     RECT  95.76 104.701 95.85 104.971 ;
     RECT  4.5 104.971 4.518 105.089 ;
     RECT  48.852 104.863 48.87 105.089 ;
     RECT  75.132 104.935 76.05 105.089 ;
     RECT  95.76 104.971 96.39 105.089 ;
     RECT  3.564 104.971 3.582 105.125 ;
     RECT  75.132 105.089 75.87 105.125 ;
     RECT  52.2 104.549 52.542 105.169 ;
     RECT  99.288 104.549 100.602 105.205 ;
     RECT  97.812 104.701 98.262 105.241 ;
     RECT  99.108 105.205 100.602 105.241 ;
     RECT  97.164 105.241 100.602 105.331 ;
     RECT  102.564 104.525 102.582 105.355 ;
     RECT  5.724 105.307 5.742 105.359 ;
     RECT  52.2 105.169 52.938 105.359 ;
     RECT  97.164 105.331 101.07 105.359 ;
     RECT  97.164 105.359 98.262 105.395 ;
     RECT  48.708 105.241 48.726 105.437 ;
     RECT  96.228 105.089 96.354 105.485 ;
     RECT  99.108 105.359 101.07 105.511 ;
     RECT  2.34 104.855 2.697 105.595 ;
     RECT  49.968 104.819 51.297 105.601 ;
     RECT  52.2 105.359 52.902 105.601 ;
     RECT  5.688 105.511 5.706 105.629 ;
     RECT  49.968 105.601 52.902 105.665 ;
     RECT  49.968 105.665 52.722 105.677 ;
     RECT  99.108 105.511 101.106 105.899 ;
     RECT  96.336 105.485 96.354 105.922 ;
     RECT  97.488 105.395 98.262 105.935 ;
     RECT  100.728 105.899 101.106 105.935 ;
     RECT  4.68 105.331 4.698 105.943 ;
     RECT  102.024 105.355 102.582 106.007 ;
     RECT  52.092 105.677 52.722 106.013 ;
     RECT  4.608 105.943 4.698 106.051 ;
     RECT  49.968 105.677 51.297 106.051 ;
     RECT  73.872 105.907 73.89 106.051 ;
     RECT  6.696 105.403 6.714 106.079 ;
     RECT  5.616 105.943 5.634 106.169 ;
     RECT  52.092 106.013 52.506 106.169 ;
     RECT  73.692 106.051 73.89 106.169 ;
     RECT  73.692 106.169 73.71 106.205 ;
     RECT  97.488 105.935 97.506 106.205 ;
     RECT  99.108 105.899 99.897 106.205 ;
     RECT  100.8 105.935 101.106 106.285 ;
     RECT  3.996 106.051 4.806 106.321 ;
     RECT  49.932 106.051 51.297 106.321 ;
     RECT  98.244 105.935 98.262 106.321 ;
     RECT  98.244 106.321 98.838 106.439 ;
     RECT  100.8 106.285 101.178 106.439 ;
     RECT  3.672 106.321 4.806 106.475 ;
     RECT  49.896 106.321 51.297 106.555 ;
     RECT  6.984 106.549 7.002 106.589 ;
     RECT  3.996 106.475 4.806 106.651 ;
     RECT  3.996 106.651 5.166 106.745 ;
     RECT  99.615 106.205 99.897 106.825 ;
     RECT  100.764 106.681 100.782 106.825 ;
     RECT  49.896 106.555 51.354 106.861 ;
     RECT  52.092 106.169 52.398 106.861 ;
     RECT  49.608 106.861 52.398 106.889 ;
     RECT  49.608 106.889 49.914 106.979 ;
     RECT  4.5 106.745 5.166 106.987 ;
     RECT  2.304 105.595 2.697 107.015 ;
     RECT  96.912 106.681 96.93 107.125 ;
     RECT  4.5 106.987 5.598 107.131 ;
     RECT  96.768 107.125 96.93 107.131 ;
     RECT  98.244 106.439 98.262 107.131 ;
     RECT  96.768 107.131 97.074 107.165 ;
     RECT  6.552 107.131 6.57 107.249 ;
     RECT  53.28 106.861 53.298 107.249 ;
     RECT  4.5 107.131 5.706 107.285 ;
     RECT  50.76 106.889 52.398 107.285 ;
     RECT  50.904 107.285 52.398 107.329 ;
     RECT  99.615 106.825 100.782 107.365 ;
     RECT  5.256 107.285 5.706 107.401 ;
     RECT  54 107.329 54.018 107.401 ;
     RECT  74.124 107.329 74.142 107.401 ;
     RECT  75.888 107.365 75.906 107.401 ;
     RECT  94.215 103.739 94.497 107.401 ;
     RECT  50.904 107.329 53.118 107.405 ;
     RECT  5.256 107.401 6.282 107.429 ;
     RECT  54 107.401 54.162 107.429 ;
     RECT  99.615 107.365 101.178 107.515 ;
     RECT  94.215 107.401 94.662 107.519 ;
     RECT  74.124 107.401 74.466 107.527 ;
     RECT  75.888 107.401 76.122 107.527 ;
     RECT  4.5 107.285 4.518 107.555 ;
     RECT  54.072 107.429 54.162 107.555 ;
     RECT  96.912 107.165 97.074 107.555 ;
     RECT  50.904 107.405 52.758 107.591 ;
     RECT  54.144 107.555 54.162 107.627 ;
     RECT  74.124 107.527 74.682 107.627 ;
     RECT  75.888 107.527 76.194 107.627 ;
     RECT  99.615 107.515 101.718 107.671 ;
     RECT  74.124 107.627 74.646 107.699 ;
     RECT  99.036 107.671 101.718 107.741 ;
     RECT  2.412 107.015 2.697 107.755 ;
     RECT  54.576 107.671 54.594 107.761 ;
     RECT  97.056 107.555 97.074 107.761 ;
     RECT  50.904 107.591 51.894 107.789 ;
     RECT  2.304 107.755 2.697 107.825 ;
     RECT  54.576 107.761 54.954 107.825 ;
     RECT  74.124 107.699 74.142 107.825 ;
     RECT  7.815 104.729 9.342 107.941 ;
     RECT  49.608 106.979 49.698 107.941 ;
     RECT  54.936 107.825 54.954 107.941 ;
     RECT  49.32 107.941 49.698 108.059 ;
     RECT  54.936 107.941 55.098 108.059 ;
     RECT  96.012 108.031 96.03 108.077 ;
     RECT  2.415 107.825 2.697 108.187 ;
     RECT  75.636 108.031 75.834 108.203 ;
     RECT  5.328 107.429 6.282 108.211 ;
     RECT  97.056 107.761 97.254 108.211 ;
     RECT  98.064 107.131 98.262 108.211 ;
     RECT  5.256 108.211 6.282 108.221 ;
     RECT  99.615 107.741 101.718 108.239 ;
     RECT  5.256 108.221 5.598 108.301 ;
     RECT  4.464 108.301 5.598 108.329 ;
     RECT  7.2 107.941 9.342 108.365 ;
     RECT  52.74 107.591 52.758 108.365 ;
     RECT  97.056 108.211 98.262 108.365 ;
     RECT  4.464 108.329 5.022 108.481 ;
     RECT  75.672 108.203 75.834 108.481 ;
     RECT  99.615 108.239 101.178 108.481 ;
     RECT  102.564 106.007 102.582 108.481 ;
     RECT  52.92 108.481 52.938 108.571 ;
     RECT  99.54 108.481 101.178 108.571 ;
     RECT  50.904 107.789 51.714 108.599 ;
     RECT  75.672 108.481 75.906 108.599 ;
     RECT  99.396 108.571 101.178 108.599 ;
     RECT  3.852 108.481 5.022 108.635 ;
     RECT  52.92 108.571 53.154 108.635 ;
     RECT  98.1 108.365 98.262 108.635 ;
     RECT  99.396 108.599 101.034 108.635 ;
     RECT  53.136 108.635 53.154 108.671 ;
     RECT  75.672 108.599 75.69 108.671 ;
     RECT  54.684 108.571 54.702 108.707 ;
     RECT  2.415 108.187 2.754 108.751 ;
     RECT  49.716 108.211 49.734 108.811 ;
     RECT  97.056 108.365 97.074 108.811 ;
     RECT  50.904 108.599 51.354 108.841 ;
     RECT  102.528 108.481 102.582 108.845 ;
     RECT  49.572 108.811 49.734 108.869 ;
     RECT  53.388 108.751 53.406 108.869 ;
     RECT  98.244 108.635 98.262 109.003 ;
     RECT  50.724 108.841 51.354 109.021 ;
     RECT  2.415 108.751 2.898 109.051 ;
     RECT  94.215 107.519 94.497 109.111 ;
     RECT  4.248 108.635 5.022 109.139 ;
     RECT  50.4 109.021 51.354 109.139 ;
     RECT  97.02 108.811 97.074 109.147 ;
     RECT  98.244 109.003 98.622 109.147 ;
     RECT  2.304 109.051 2.898 109.175 ;
     RECT  53.46 109.021 53.478 109.175 ;
     RECT  97.02 109.147 97.254 109.175 ;
     RECT  94.215 109.111 94.662 109.247 ;
     RECT  2.415 109.175 2.898 109.291 ;
     RECT  50.724 109.139 51.354 109.381 ;
     RECT  52.236 109.291 52.254 109.381 ;
     RECT  72.615 99.833 72.897 109.381 ;
     RECT  97.236 109.175 97.254 109.445 ;
     RECT  0.54 109.417 0.558 109.517 ;
     RECT  99.615 108.635 101.034 109.525 ;
     RECT  99.615 109.525 101.214 109.553 ;
     RECT  98.244 109.147 98.874 109.561 ;
     RECT  99.615 109.553 99.897 109.561 ;
     RECT  2.415 109.291 3.438 109.679 ;
     RECT  4.248 109.139 4.806 109.679 ;
     RECT  101.016 109.553 101.214 109.679 ;
     RECT  4.248 109.679 4.662 109.715 ;
     RECT  72.615 109.381 73.566 109.715 ;
     RECT  50.724 109.381 52.65 109.831 ;
     RECT  49.032 109.417 49.05 109.859 ;
     RECT  2.415 109.679 2.697 109.915 ;
     RECT  49.932 109.831 49.95 109.915 ;
     RECT  49.788 109.915 49.95 109.955 ;
     RECT  5.976 109.831 5.994 109.985 ;
     RECT  50.724 109.831 52.722 110.101 ;
     RECT  102.564 108.845 102.582 110.107 ;
     RECT  50.724 110.101 53.082 110.191 ;
     RECT  76.32 110.101 76.338 110.191 ;
     RECT  50.148 110.191 53.082 110.219 ;
     RECT  70.704 110.101 70.722 110.219 ;
     RECT  74.34 110.101 74.358 110.219 ;
     RECT  76.104 110.191 76.338 110.219 ;
     RECT  98.244 109.561 99.897 110.219 ;
     RECT  3.564 110.101 3.582 110.255 ;
     RECT  76.104 110.219 76.122 110.363 ;
     RECT  96.336 109.561 96.354 110.371 ;
     RECT  99.615 110.219 99.897 110.371 ;
     RECT  101.016 109.679 101.178 110.371 ;
     RECT  2.304 109.915 2.697 110.381 ;
     RECT  54.792 110.227 54.81 110.399 ;
     RECT  4.644 109.715 4.662 110.461 ;
     RECT  99.615 110.371 101.178 110.461 ;
     RECT  50.148 110.219 52.938 110.489 ;
     RECT  96.228 110.371 96.714 110.489 ;
     RECT  95.292 110.335 95.31 110.525 ;
     RECT  96.228 110.489 96.246 110.525 ;
     RECT  102.492 110.107 102.582 110.525 ;
     RECT  98.244 110.219 98.73 110.561 ;
     RECT  7.815 108.365 9.342 110.569 ;
     RECT  98.244 110.561 98.622 110.569 ;
     RECT  98.208 110.569 98.622 110.597 ;
     RECT  3.924 110.461 4.662 110.641 ;
     RECT  3.924 110.641 4.914 110.795 ;
     RECT  50.544 110.489 52.938 110.795 ;
     RECT  2.415 110.381 2.697 110.911 ;
     RECT  99.615 110.461 101.358 110.911 ;
     RECT  99.615 110.911 101.718 111.005 ;
     RECT  98.208 110.597 98.37 111.029 ;
     RECT  52.92 110.795 52.938 111.065 ;
     RECT  99.615 111.005 101.178 111.065 ;
     RECT  5.652 110.461 5.67 111.181 ;
     RECT  99.615 111.065 101.034 111.181 ;
     RECT  2.415 110.911 2.898 111.211 ;
     RECT  3.96 110.795 4.914 111.299 ;
     RECT  5.652 111.181 5.706 111.299 ;
     RECT  2.304 111.211 2.898 111.335 ;
     RECT  3.96 111.299 4.374 111.335 ;
     RECT  53.1 111.181 53.118 111.335 ;
     RECT  98.208 111.029 98.262 111.379 ;
     RECT  54.72 111.271 54.738 111.407 ;
     RECT  50.544 110.795 52.146 111.451 ;
     RECT  78.015 97.439 78.297 111.451 ;
     RECT  90.648 111.379 90.666 111.451 ;
     RECT  94.215 109.247 94.497 111.451 ;
     RECT  5.688 111.299 5.706 111.479 ;
     RECT  90.648 111.451 90.738 111.479 ;
     RECT  50.364 111.451 52.146 111.541 ;
     RECT  53.388 111.451 53.406 111.569 ;
     RECT  78.015 111.451 78.642 111.569 ;
     RECT  75.312 111.271 75.33 111.577 ;
     RECT  3.96 111.335 4.05 111.605 ;
     RECT  75.312 111.577 75.51 111.605 ;
     RECT  90.72 111.479 90.738 111.605 ;
     RECT  2.415 111.335 2.898 111.643 ;
     RECT  74.016 111.541 74.214 111.677 ;
     RECT  75.492 111.605 75.51 111.677 ;
     RECT  94.215 111.451 94.59 111.677 ;
     RECT  7.815 110.569 9.45 111.685 ;
     RECT  97.92 111.379 98.262 111.685 ;
     RECT  74.016 111.677 74.142 111.713 ;
     RECT  99.504 111.181 101.034 111.721 ;
     RECT  7.2 111.685 9.45 111.725 ;
     RECT  97.776 111.685 98.262 111.725 ;
     RECT  102.564 110.525 102.582 111.835 ;
     RECT  95.76 111.541 95.778 111.839 ;
     RECT  2.415 111.643 3.078 111.875 ;
     RECT  99 111.721 101.034 111.875 ;
     RECT  50.364 111.541 52.29 111.919 ;
     RECT  102.024 111.835 102.582 111.947 ;
     RECT  50.364 111.919 52.326 111.955 ;
     RECT  50.364 111.955 52.506 111.991 ;
     RECT  50.184 111.991 52.506 112.109 ;
     RECT  0.108 112.075 0.126 112.205 ;
     RECT  4.032 111.605 4.05 112.225 ;
     RECT  4.032 112.225 4.554 112.261 ;
     RECT  99.54 111.875 101.034 112.351 ;
     RECT  50.58 112.109 52.506 112.387 ;
     RECT  2.415 111.875 2.862 112.415 ;
     RECT  50.58 112.387 52.542 112.487 ;
     RECT  2.415 112.415 2.697 112.495 ;
     RECT  50.58 112.487 52.506 112.523 ;
     RECT  99.54 112.351 101.178 112.531 ;
     RECT  2.304 112.495 2.697 112.541 ;
     RECT  99.54 112.531 101.394 112.649 ;
     RECT  4.032 112.261 4.986 112.685 ;
     RECT  74.124 111.713 74.142 112.685 ;
     RECT  99.54 112.649 101.178 112.721 ;
     RECT  99.54 112.721 100.998 112.765 ;
     RECT  49.716 112.531 49.734 112.792 ;
     RECT  4.536 112.685 4.986 112.801 ;
     RECT  7.815 111.725 9.45 112.801 ;
     RECT  49.572 112.792 49.734 112.829 ;
     RECT  6.696 112.603 6.714 112.877 ;
     RECT  96.912 112.621 96.93 112.919 ;
     RECT  4.536 112.801 5.202 112.955 ;
     RECT  49.68 112.829 49.734 113.071 ;
     RECT  50.58 112.523 52.326 113.071 ;
     RECT  98.244 111.725 98.262 113.071 ;
     RECT  102.564 111.947 102.582 113.071 ;
     RECT  7.632 112.801 9.45 113.099 ;
     RECT  96.264 113.035 96.282 113.117 ;
     RECT  102.024 113.071 102.582 113.165 ;
     RECT  3.492 113.071 3.51 113.189 ;
     RECT  49.68 113.071 52.326 113.189 ;
     RECT  97.2 113.071 97.434 113.225 ;
     RECT  98.244 113.071 98.37 113.225 ;
     RECT  5.94 112.843 5.958 113.341 ;
     RECT  50.58 113.189 52.326 113.341 ;
     RECT  2.412 112.541 2.697 113.371 ;
     RECT  5.508 113.341 6.102 113.459 ;
     RECT  2.304 113.371 2.697 113.495 ;
     RECT  50.58 113.341 52.47 113.575 ;
     RECT  4.536 112.955 4.554 113.611 ;
     RECT  50.58 113.575 52.722 113.611 ;
     RECT  75.096 113.467 75.114 113.611 ;
     RECT  74.304 113.575 74.322 113.701 ;
     RECT  95.436 113.575 95.454 113.707 ;
     RECT  5.508 113.459 5.814 113.729 ;
     RECT  95.292 113.707 95.454 113.729 ;
     RECT  97.416 113.225 97.434 113.729 ;
     RECT  102.564 113.165 102.582 113.729 ;
     RECT  4.14 113.611 4.554 113.765 ;
     RECT  75.096 113.611 75.294 113.765 ;
     RECT  95.292 113.729 95.31 113.765 ;
     RECT  54.684 113.467 54.702 113.837 ;
     RECT  99.144 112.765 100.998 113.845 ;
     RECT  5.652 113.729 5.814 113.873 ;
     RECT  99.144 113.845 101.178 113.981 ;
     RECT  5.796 113.873 5.814 113.999 ;
     RECT  99.18 113.981 101.178 113.999 ;
     RECT  50.58 113.611 52.866 114.035 ;
     RECT  49.68 113.189 49.842 114.151 ;
     RECT  50.58 114.035 51.297 114.151 ;
     RECT  2.415 113.495 2.697 114.235 ;
     RECT  74.124 113.701 74.322 114.241 ;
     RECT  2.304 114.235 2.697 114.305 ;
     RECT  6.588 113.881 6.606 114.349 ;
     RECT  54.72 114.241 54.738 114.377 ;
     RECT  2.415 114.305 2.697 114.421 ;
     RECT  6.588 114.349 6.858 114.421 ;
     RECT  49.68 114.151 51.297 114.421 ;
     RECT  52.02 114.035 52.866 114.421 ;
     RECT  98.244 113.225 98.262 114.421 ;
     RECT  6.588 114.421 6.93 114.449 ;
     RECT  4.464 113.765 4.554 114.511 ;
     RECT  52.02 114.421 52.974 114.511 ;
     RECT  98.208 114.421 98.262 114.511 ;
     RECT  49.212 114.421 51.297 114.539 ;
     RECT  102.024 113.995 102.546 114.539 ;
     RECT  52.02 114.511 53.082 114.547 ;
     RECT  74.124 114.241 74.79 114.547 ;
     RECT  96.984 114.511 97.002 114.557 ;
     RECT  6.804 114.449 6.93 114.575 ;
     RECT  74.124 114.547 74.97 114.575 ;
     RECT  99.18 113.999 101.034 114.575 ;
     RECT  4.464 114.511 4.59 114.583 ;
     RECT  4.464 114.583 4.77 114.691 ;
     RECT  0.108 114.547 0.126 114.701 ;
     RECT  74.952 114.575 74.97 114.719 ;
     RECT  99.18 114.575 100.494 114.719 ;
     RECT  6.804 114.575 6.822 114.809 ;
     RECT  49.32 114.539 51.297 114.809 ;
     RECT  75.78 114.421 75.798 114.809 ;
     RECT  3.996 114.691 4.77 114.845 ;
     RECT  98.064 114.511 98.262 114.845 ;
     RECT  102.528 114.539 102.546 114.859 ;
     RECT  99.18 114.719 100.386 114.917 ;
     RECT  50.436 114.809 51.297 114.961 ;
     RECT  52.02 114.547 53.154 114.961 ;
     RECT  99.576 114.917 100.386 115.079 ;
     RECT  74.124 114.575 74.142 115.115 ;
     RECT  95.4 114.571 95.418 115.115 ;
     RECT  2.415 114.421 3.258 115.133 ;
     RECT  4.572 114.845 4.734 115.133 ;
     RECT  5.652 115.231 5.67 115.321 ;
     RECT  4.716 115.133 4.734 115.349 ;
     RECT  49.32 114.809 49.554 115.349 ;
     RECT  96.912 115.051 96.93 115.349 ;
     RECT  3.456 115.231 3.474 115.385 ;
     RECT  5.616 115.321 5.67 115.501 ;
     RECT  99.615 115.079 100.386 115.501 ;
     RECT  2.415 115.133 2.697 115.531 ;
     RECT  5.616 115.501 5.706 115.565 ;
     RECT  102.528 114.859 102.582 115.619 ;
     RECT  46.764 115.501 46.782 115.691 ;
     RECT  50.436 114.961 53.154 115.723 ;
     RECT  98.244 114.845 98.262 115.771 ;
     RECT  98.244 115.771 98.874 115.861 ;
     RECT  99.615 115.501 100.422 115.861 ;
     RECT  6.552 115.771 6.57 115.889 ;
     RECT  3.888 115.663 3.978 115.925 ;
     RECT  54.72 115.897 54.738 115.997 ;
     RECT  5.616 115.565 5.67 116.005 ;
     RECT  5.112 116.005 5.67 116.033 ;
     RECT  50.364 115.723 53.154 116.041 ;
     RECT  98.244 115.861 100.422 116.041 ;
     RECT  101.16 115.591 101.178 116.041 ;
     RECT  50.364 116.041 53.19 116.131 ;
     RECT  50.364 116.131 53.478 116.159 ;
     RECT  97.632 116.041 101.178 116.159 ;
     RECT  3.888 115.925 3.906 116.195 ;
     RECT  50.364 116.159 51.894 116.195 ;
     RECT  74.88 115.897 74.898 116.195 ;
     RECT  5.112 116.033 5.13 116.237 ;
     RECT  97.632 116.159 98.73 116.237 ;
     RECT  49.536 115.349 49.554 116.251 ;
     RECT  50.364 116.195 51.498 116.251 ;
     RECT  96.876 116.167 96.894 116.299 ;
     RECT  96.876 116.299 97.362 116.429 ;
     RECT  98.244 116.237 98.73 116.429 ;
     RECT  2.304 115.531 2.697 116.465 ;
     RECT  53.172 116.159 53.478 116.465 ;
     RECT  53.424 116.465 53.478 116.501 ;
     RECT  53.46 116.501 53.478 116.545 ;
     RECT  94.215 111.677 94.497 116.545 ;
     RECT  49.536 116.251 51.498 116.581 ;
     RECT  96.876 116.429 97.182 116.581 ;
     RECT  102.564 115.619 102.582 116.587 ;
     RECT  5.976 116.311 6.066 116.609 ;
     RECT  54.684 116.401 54.702 116.609 ;
     RECT  49.104 116.581 51.498 116.621 ;
     RECT  49.104 116.621 49.122 116.699 ;
     RECT  73.908 116.401 73.926 116.707 ;
     RECT  5.976 116.609 5.994 116.735 ;
     RECT  49.968 116.621 51.498 116.735 ;
     RECT  73.908 116.707 74.106 116.735 ;
     RECT  94.215 116.545 94.662 116.735 ;
     RECT  96.516 116.581 97.182 116.735 ;
     RECT  96.516 116.735 96.894 116.771 ;
     RECT  46.764 116.707 46.782 116.807 ;
     RECT  70.704 116.671 70.722 116.807 ;
     RECT  74.088 116.735 74.106 116.879 ;
     RECT  95.76 116.671 95.778 116.969 ;
     RECT  102.528 116.587 102.582 116.969 ;
     RECT  75.132 116.779 75.15 117.005 ;
     RECT  98.244 116.429 98.55 117.005 ;
     RECT  49.968 116.735 51.297 117.113 ;
     RECT  4.248 116.815 4.266 117.121 ;
     RECT  53.46 116.545 53.514 117.121 ;
     RECT  49.968 117.113 49.986 117.149 ;
     RECT  53.46 117.121 53.55 117.275 ;
     RECT  4.248 117.121 4.446 117.355 ;
     RECT  53.46 117.275 53.478 117.391 ;
     RECT  4.248 117.355 4.482 117.403 ;
     RECT  3.924 117.403 4.482 117.437 ;
     RECT  53.064 117.391 53.478 117.545 ;
     RECT  5.4 117.391 5.418 117.581 ;
     RECT  50.724 117.113 51.297 117.617 ;
     RECT  3.924 117.437 4.086 117.661 ;
     RECT  52.02 117.121 52.038 117.661 ;
     RECT  53.064 117.545 53.334 117.661 ;
     RECT  99.615 116.159 101.178 117.661 ;
     RECT  46.764 117.553 46.782 117.689 ;
     RECT  76.14 117.589 76.158 117.689 ;
     RECT  2.415 116.465 2.697 117.691 ;
     RECT  3.816 117.661 4.086 117.779 ;
     RECT  49.716 117.517 49.734 117.779 ;
     RECT  2.304 117.691 2.697 117.815 ;
     RECT  3.816 117.779 3.834 117.815 ;
     RECT  50.94 117.617 51.297 117.815 ;
     RECT  52.02 117.661 53.334 117.815 ;
     RECT  99.216 117.661 101.178 117.851 ;
     RECT  51.015 117.815 51.297 117.925 ;
     RECT  52.02 117.815 53.19 117.925 ;
     RECT  51.015 117.925 53.19 117.965 ;
     RECT  7.815 113.099 9.45 117.979 ;
     RECT  98.244 117.005 98.298 118.027 ;
     RECT  99.216 117.851 99.954 118.027 ;
     RECT  98.244 118.027 99.954 118.049 ;
     RECT  5.436 117.931 5.454 118.085 ;
     RECT  72.615 109.715 72.897 118.093 ;
     RECT  74.124 118.057 74.142 118.093 ;
     RECT  94.215 116.735 94.497 118.129 ;
     RECT  76.32 117.931 76.338 118.157 ;
     RECT  95.868 118.165 95.886 118.201 ;
     RECT  95.868 118.201 96.066 118.205 ;
     RECT  96.048 118.205 96.066 118.319 ;
     RECT  96.84 118.201 96.858 118.319 ;
     RECT  7.128 117.979 9.45 118.355 ;
     RECT  72.615 118.093 74.142 118.355 ;
     RECT  98.352 118.049 99.954 118.391 ;
     RECT  7.815 118.355 9.45 118.499 ;
     RECT  2.415 117.815 2.697 118.555 ;
     RECT  3.564 118.201 3.582 118.555 ;
     RECT  49.824 117.931 49.842 118.555 ;
     RECT  49.68 118.555 49.842 118.561 ;
     RECT  94.215 118.129 94.662 118.561 ;
     RECT  49.68 118.561 50.166 118.595 ;
     RECT  2.304 118.555 3.582 118.597 ;
     RECT  2.304 118.597 4.086 118.625 ;
     RECT  52.632 117.965 53.19 118.625 ;
     RECT  74.124 118.355 74.142 118.625 ;
     RECT  99.576 118.391 99.954 118.625 ;
     RECT  50.148 118.595 50.166 118.697 ;
     RECT  99.615 118.625 99.954 118.705 ;
     RECT  51.015 117.965 51.297 118.741 ;
     RECT  99.615 118.705 100.314 118.741 ;
     RECT  101.052 117.851 101.178 118.741 ;
     RECT  102.564 116.969 102.582 118.741 ;
     RECT  102.528 118.741 102.582 118.781 ;
     RECT  52.632 118.625 52.65 118.859 ;
     RECT  94.215 118.561 95.202 118.859 ;
     RECT  50.616 118.741 51.606 118.895 ;
     RECT  50.904 118.895 51.606 118.975 ;
     RECT  2.415 118.625 4.086 119.011 ;
     RECT  54.684 118.741 54.702 119.011 ;
     RECT  50.904 118.975 52.506 119.069 ;
     RECT  94.215 118.859 95.058 119.069 ;
     RECT  2.415 119.011 4.266 119.083 ;
     RECT  2.415 119.083 4.842 119.129 ;
     RECT  2.415 119.129 3.15 119.165 ;
     RECT  3.888 119.129 4.842 119.165 ;
     RECT  53.64 119.011 54.702 119.165 ;
     RECT  5.652 119.137 5.67 119.173 ;
     RECT  5.652 119.173 5.742 119.281 ;
     RECT  99.615 118.741 101.178 119.371 ;
     RECT  53.82 119.165 54.702 119.399 ;
     RECT  74.664 119.281 74.682 119.399 ;
     RECT  76.896 119.281 76.914 119.399 ;
     RECT  78.015 111.569 78.297 119.407 ;
     RECT  5.652 119.281 6.246 119.435 ;
     RECT  53.82 119.399 53.838 119.435 ;
     RECT  75.816 118.867 75.834 119.435 ;
     RECT  72.615 118.355 72.99 119.443 ;
     RECT  2.415 119.165 2.754 119.453 ;
     RECT  50.904 119.069 52.29 119.471 ;
     RECT  32.256 71.653 32.274 119.479 ;
     RECT  5.724 119.435 6.246 119.515 ;
     RECT  7.02 119.281 7.038 119.515 ;
     RECT  7.815 118.499 9.342 119.515 ;
     RECT  98.352 118.391 98.37 119.515 ;
     RECT  99.615 119.371 101.322 119.515 ;
     RECT  54.72 119.443 54.738 119.543 ;
     RECT  98.352 119.515 101.322 119.551 ;
     RECT  102.564 118.781 102.582 119.551 ;
     RECT  78.015 119.407 78.678 119.579 ;
     RECT  97.236 119.371 97.254 119.641 ;
     RECT  98.352 119.551 102.582 119.645 ;
     RECT  5.724 119.515 9.342 119.669 ;
     RECT  98.352 119.645 101.322 119.677 ;
     RECT  96.876 119.641 97.254 119.693 ;
     RECT  51.015 119.471 52.29 119.705 ;
     RECT  7.815 119.669 9.342 119.749 ;
     RECT  32.004 119.479 32.274 119.785 ;
     RECT  2.415 119.453 2.697 119.851 ;
     RECT  98.064 119.677 101.322 119.939 ;
     RECT  2.304 119.851 2.697 119.975 ;
     RECT  51.015 119.705 52.218 119.975 ;
     RECT  72.615 119.443 73.566 119.975 ;
     RECT  101.016 119.939 101.322 120.047 ;
     RECT  94.215 119.069 94.497 120.091 ;
     RECT  98.064 119.939 100.17 120.091 ;
     RECT  102.564 119.645 102.582 120.119 ;
     RECT  96.876 119.693 96.894 120.173 ;
     RECT  52.2 119.975 52.218 120.209 ;
     RECT  73.836 120.091 73.854 120.209 ;
     RECT  94.215 120.091 95.094 120.209 ;
     RECT  101.016 120.047 101.034 120.209 ;
     RECT  2.415 119.975 2.697 120.217 ;
     RECT  3.888 119.165 4.554 120.217 ;
     RECT  2.415 120.217 4.554 120.235 ;
     RECT  97.704 120.091 100.17 120.245 ;
     RECT  7.815 119.749 9.378 120.269 ;
     RECT  8.856 120.269 9.378 120.281 ;
     RECT  31.932 119.785 32.274 120.289 ;
     RECT  0.108 120.217 0.126 120.317 ;
     RECT  8.928 120.281 9.378 120.317 ;
     RECT  94.215 120.209 94.662 120.389 ;
     RECT  2.415 120.235 4.878 120.479 ;
     RECT  33.912 120.091 33.93 120.479 ;
     RECT  34.815 2.413 35.097 120.487 ;
     RECT  2.415 120.479 3.15 120.515 ;
     RECT  34.452 120.487 35.097 120.523 ;
     RECT  31.932 120.289 32.814 120.559 ;
     RECT  53.568 120.523 53.586 120.559 ;
     RECT  53.028 120.559 53.586 120.587 ;
     RECT  31.932 120.559 33.606 120.623 ;
     RECT  34.452 120.523 35.19 120.653 ;
     RECT  2.415 120.515 2.697 120.715 ;
     RECT  5.724 119.669 6.354 120.757 ;
     RECT  2.304 120.715 2.697 120.785 ;
     RECT  33.192 120.623 33.606 120.785 ;
     RECT  34.452 120.653 35.097 120.785 ;
     RECT  98.352 120.245 100.17 120.785 ;
     RECT  98.352 120.785 98.514 120.797 ;
     RECT  98.496 120.797 98.514 120.821 ;
     RECT  8.964 120.317 9.378 120.857 ;
     RECT  3.888 120.479 4.878 120.901 ;
     RECT  5.652 120.757 6.354 120.901 ;
     RECT  7.815 120.269 8.097 120.901 ;
     RECT  102.024 120.475 102.042 120.907 ;
     RECT  56.415 86.999 56.697 120.991 ;
     RECT  3.888 120.901 6.354 121.019 ;
     RECT  31.932 120.623 31.95 121.019 ;
     RECT  56.304 120.991 56.697 121.037 ;
     RECT  3.888 121.019 4.41 121.055 ;
     RECT  5.652 121.019 6.354 121.055 ;
     RECT  58.716 121.003 58.734 121.133 ;
     RECT  7.344 120.901 8.097 121.135 ;
     RECT  5.76 121.055 6.354 121.171 ;
     RECT  7.236 121.135 8.097 121.171 ;
     RECT  99.615 120.785 100.17 121.171 ;
     RECT  100.944 120.901 100.962 121.171 ;
     RECT  5.76 121.171 8.097 121.186 ;
     RECT  63.648 121.099 63.666 121.199 ;
     RECT  6.552 121.186 8.097 121.289 ;
     RECT  102.024 120.907 102.582 121.289 ;
     RECT  3.888 121.055 3.906 121.325 ;
     RECT  99.615 121.171 101.214 121.325 ;
     RECT  65.196 120.763 65.214 121.397 ;
     RECT  102.024 121.289 102.042 121.397 ;
     RECT  9.036 120.857 9.378 121.559 ;
     RECT  100.908 121.325 101.07 121.559 ;
     RECT  100.908 121.559 100.926 121.595 ;
     RECT  9.036 121.559 9.054 121.667 ;
     RECT  33.192 120.785 33.21 121.667 ;
     RECT  7.815 121.289 8.097 121.711 ;
     RECT  8.928 121.675 8.946 121.711 ;
     RECT  26.784 121.639 26.802 121.739 ;
     RECT  7.815 121.711 8.946 121.829 ;
     RECT  5.76 121.186 5.778 121.865 ;
     RECT  53.028 120.587 53.046 123.989 ;
     RECT  52.956 124.141 52.974 124.231 ;
     RECT  52.308 124.231 52.974 124.339 ;
     RECT  51.015 119.975 51.297 124.375 ;
     RECT  52.056 124.339 52.974 124.375 ;
     RECT  51.015 124.375 52.974 124.529 ;
     RECT  52.02 124.529 52.974 125.185 ;
     RECT  51.015 124.529 51.297 125.419 ;
     RECT  52.02 125.185 53.046 125.419 ;
     RECT  51.015 125.419 53.046 125.609 ;
     RECT  51.015 125.609 53.01 125.879 ;
     RECT  51.015 125.879 52.542 126.023 ;
     RECT  51.015 126.023 52.29 126.149 ;
     RECT  51.015 126.149 52.218 126.185 ;
     RECT  51.015 126.185 51.822 126.967 ;
     RECT  51.015 126.967 52.326 127.067 ;
     RECT  2.415 120.785 2.697 127.187 ;
     RECT  7.815 121.829 8.097 127.187 ;
     RECT  13.215 2.413 13.497 127.187 ;
     RECT  18.615 2.413 18.897 127.187 ;
     RECT  24.015 2.413 24.297 127.187 ;
     RECT  29.415 2.413 29.697 127.187 ;
     RECT  34.815 120.785 35.097 127.187 ;
     RECT  40.215 2.413 40.497 127.187 ;
     RECT  45.615 90.605 45.897 127.187 ;
     RECT  51.015 127.067 51.297 127.187 ;
     RECT  56.415 121.037 56.697 127.187 ;
     RECT  61.815 99.725 62.097 127.187 ;
     RECT  67.215 2.413 67.497 127.187 ;
     RECT  72.615 119.975 72.897 127.187 ;
     RECT  78.015 119.579 78.297 127.187 ;
     RECT  83.415 2.413 83.697 127.187 ;
     RECT  88.815 2.413 89.097 127.187 ;
     RECT  94.215 120.389 94.497 127.187 ;
     RECT  99.615 121.325 99.897 127.187 ;
     RECT  52.2 127.067 52.326 127.229 ;
     RECT  2.415 127.187 2.505 127.457 ;
     RECT  7.815 127.187 7.905 127.457 ;
     RECT  13.215 127.187 13.305 127.457 ;
     RECT  18.615 127.187 18.705 127.457 ;
     RECT  24.015 127.187 24.105 127.457 ;
     RECT  29.415 127.187 29.505 127.457 ;
     RECT  34.815 127.187 34.905 127.457 ;
     RECT  40.215 127.187 40.305 127.457 ;
     RECT  45.615 127.187 45.705 127.457 ;
     RECT  51.015 127.187 51.105 127.457 ;
     RECT  56.415 127.187 56.505 127.457 ;
     RECT  61.815 127.187 61.905 127.457 ;
     RECT  67.215 127.187 67.305 127.457 ;
     RECT  72.615 127.187 72.705 127.457 ;
     RECT  78.015 127.187 78.105 127.457 ;
     RECT  83.415 127.187 83.505 127.457 ;
     RECT  88.815 127.187 88.905 127.457 ;
     RECT  94.215 127.187 94.305 127.457 ;
     RECT  99.615 127.187 99.705 127.457 ;
     RECT  52.2 127.229 52.218 127.661 ;
    LAYER M4 ;
     RECT  0.06 7.968 0.137 121.608 ;
     RECT  0.137 8.4 2.408 121.608 ;
     RECT  2.408 2.148 2.512 127.452 ;
     RECT  2.512 2.418 2.704 127.182 ;
     RECT  2.704 23.088 2.765 23.112 ;
     RECT  2.704 43.824 2.765 43.848 ;
     RECT  2.704 75.792 2.765 77.112 ;
     RECT  2.704 108.192 2.765 108.216 ;
     RECT  2.704 117.648 2.765 120.264 ;
     RECT  2.704 17.472 2.801 17.496 ;
     RECT  2.704 39.504 2.801 39.528 ;
     RECT  2.704 53.328 2.801 53.352 ;
     RECT  2.704 64.128 2.801 64.152 ;
     RECT  2.704 67.152 2.801 67.176 ;
     RECT  2.765 75.792 2.801 76.248 ;
     RECT  2.704 20.064 2.837 20.088 ;
     RECT  2.704 21.792 2.837 21.816 ;
     RECT  2.704 26.544 2.837 26.568 ;
     RECT  2.704 54.624 2.837 54.648 ;
     RECT  2.704 56.784 2.837 56.808 ;
     RECT  2.704 58.944 2.837 58.968 ;
     RECT  2.704 60.672 2.837 60.696 ;
     RECT  2.801 76.224 2.837 76.248 ;
     RECT  2.704 80.112 2.837 80.568 ;
     RECT  2.704 101.712 2.837 101.736 ;
     RECT  2.704 103.872 2.837 103.896 ;
     RECT  2.704 115.104 2.837 115.128 ;
     RECT  2.704 10.656 2.873 10.68 ;
     RECT  2.704 97.392 2.873 98.616 ;
     RECT  2.704 111.648 2.873 112.2 ;
     RECT  2.704 81.936 2.909 81.96 ;
     RECT  2.704 29.568 3.017 29.592 ;
     RECT  2.873 111.648 3.089 111.672 ;
     RECT  2.873 98.352 3.125 98.616 ;
     RECT  2.704 91.584 3.233 92.232 ;
     RECT  2.704 15.312 3.341 15.336 ;
     RECT  2.765 117.648 3.443 118.584 ;
     RECT  3.788 35.952 3.875 35.976 ;
     RECT  3.443 117.648 3.913 117.672 ;
     RECT  3.829 37.584 3.953 37.608 ;
     RECT  3.913 117.408 3.953 117.672 ;
     RECT  3.949 70.56 4.097 70.584 ;
     RECT  3.973 39.888 4.172 39.912 ;
     RECT  4.172 39.168 4.241 39.912 ;
     RECT  4.241 39.168 4.259 39.192 ;
     RECT  4.129 20.016 4.268 20.04 ;
     RECT  4.22 8.304 4.307 8.328 ;
     RECT  4.268 19.152 4.309 20.04 ;
     RECT  3.805 88.08 4.309 88.104 ;
     RECT  4.261 10.176 4.348 10.872 ;
     RECT  4.309 18.816 4.355 20.04 ;
     RECT  4.268 85.872 4.355 85.896 ;
     RECT  4.309 87.504 4.355 88.104 ;
     RECT  3.233 91.584 4.364 91.608 ;
     RECT  4.309 84.336 4.396 84.84 ;
     RECT  4.355 87.504 4.396 87.528 ;
     RECT  4.355 18.816 4.403 18.84 ;
     RECT  4.364 91.152 4.405 91.608 ;
     RECT  4.405 91.152 4.451 91.8 ;
     RECT  4.309 83.136 4.457 83.16 ;
     RECT  3.697 43.632 4.501 43.656 ;
     RECT  4.345 79.2 4.501 79.224 ;
     RECT  4.237 70.224 4.517 70.248 ;
     RECT  4.501 79.2 4.547 79.656 ;
     RECT  3.877 41.04 4.549 41.064 ;
     RECT  4.501 42.144 4.549 42.168 ;
     RECT  4.345 104.832 4.549 104.856 ;
     RECT  4.417 106.656 4.549 106.68 ;
     RECT  4.517 69.504 4.556 70.248 ;
     RECT  3.953 117.408 4.557 117.432 ;
     RECT  4.309 75.792 4.561 75.816 ;
     RECT  4.357 16.512 4.565 17.496 ;
     RECT  4.501 43.152 4.588 43.656 ;
     RECT  4.549 41.04 4.595 42.168 ;
     RECT  4.549 104.832 4.595 106.68 ;
     RECT  4.453 66.72 4.597 66.744 ;
     RECT  4.595 41.616 4.601 42.168 ;
     RECT  4.556 68.88 4.601 70.248 ;
     RECT  4.601 41.616 4.636 41.64 ;
     RECT  4.595 105.312 4.637 106.68 ;
     RECT  4.601 68.88 4.643 68.904 ;
     RECT  4.556 115.104 4.643 115.128 ;
     RECT  4.525 58.56 4.7 58.584 ;
     RECT  4.525 60.24 4.7 60.264 ;
     RECT  4.309 61.584 4.7 61.608 ;
     RECT  4.453 101.712 4.7 101.736 ;
     RECT  4.7 58.56 4.741 58.872 ;
     RECT  4.7 101.712 4.741 102.312 ;
     RECT  4.345 23.904 4.748 23.928 ;
     RECT  4.549 26.208 4.777 26.232 ;
     RECT  4.309 27.312 4.777 27.336 ;
     RECT  4.547 79.632 4.781 79.656 ;
     RECT  4.417 56.928 4.787 56.952 ;
     RECT  4.741 58.128 4.787 58.872 ;
     RECT  4.7 60.24 4.787 61.608 ;
     RECT  4.741 101.184 4.787 102.312 ;
     RECT  4.787 101.184 4.789 101.208 ;
     RECT  4.565 17.472 4.817 17.496 ;
     RECT  4.777 27.312 4.817 27.768 ;
     RECT  3.125 98.592 4.817 98.616 ;
     RECT  4.748 23.904 4.835 24.264 ;
     RECT  2.765 120.24 4.849 120.264 ;
     RECT  4.777 25.68 4.861 26.232 ;
     RECT  4.789 119.088 4.876 119.112 ;
     RECT  4.849 120.24 4.889 120.36 ;
     RECT  4.789 100.992 4.961 101.208 ;
     RECT  3.985 96.336 4.981 96.36 ;
     RECT  4.981 95.52 5.027 96.36 ;
     RECT  2.704 48.384 5.033 48.408 ;
     RECT  5.027 95.52 5.069 96.024 ;
     RECT  4.835 23.904 5.077 23.928 ;
     RECT  4.601 70.224 5.077 70.248 ;
     RECT  5.077 23.328 5.123 23.928 ;
     RECT  5.077 70.224 5.123 70.968 ;
     RECT  2.704 65.52 5.125 65.544 ;
     RECT  4.597 66.72 5.125 67.704 ;
     RECT  4.501 116.208 5.141 116.232 ;
     RECT  5.125 65.52 5.171 67.704 ;
     RECT  4.637 106.656 5.177 106.68 ;
     RECT  4.817 27.744 5.18 27.768 ;
     RECT  4.345 28.8 5.18 28.824 ;
     RECT  5.18 27.744 5.221 28.824 ;
     RECT  5.221 27.744 5.267 29.64 ;
     RECT  5.123 70.944 5.269 70.968 ;
     RECT  4.633 72.048 5.269 72.072 ;
     RECT  4.549 99.936 5.269 99.96 ;
     RECT  4.961 100.992 5.269 101.016 ;
     RECT  4.093 13.536 5.281 13.56 ;
     RECT  5.269 70.944 5.315 72.984 ;
     RECT  2.704 74.064 5.315 74.088 ;
     RECT  5.228 108.24 5.315 108.264 ;
     RECT  4.861 26.208 5.317 26.232 ;
     RECT  4.021 15.36 5.353 15.384 ;
     RECT  4.213 38.16 5.357 38.184 ;
     RECT  5.315 72.816 5.357 72.984 ;
     RECT  5.281 13.536 5.389 14.376 ;
     RECT  5.171 65.52 5.393 66.12 ;
     RECT  4.451 91.776 5.411 91.8 ;
     RECT  4.993 49.728 5.413 49.752 ;
     RECT  5.389 13.056 5.42 14.376 ;
     RECT  5.353 15.36 5.457 16.008 ;
     RECT  4.417 51.888 5.461 51.912 ;
     RECT  5.42 12.384 5.507 14.376 ;
     RECT  5.317 93.168 5.533 93.192 ;
     RECT  5.461 51.888 5.569 52.392 ;
     RECT  5.413 49.728 5.603 50.28 ;
     RECT  4.561 75.792 5.609 76.392 ;
     RECT  5.267 29.616 5.641 29.64 ;
     RECT  4.348 10.848 5.653 10.872 ;
     RECT  5.633 12 5.653 12.024 ;
     RECT  5.569 51.888 5.664 52.44 ;
     RECT  5.641 29.616 5.681 30.168 ;
     RECT  5.269 99.936 5.681 101.016 ;
     RECT  5.653 10.848 5.699 12.024 ;
     RECT  5.507 13.056 5.699 14.376 ;
     RECT  5.664 52.368 5.699 52.44 ;
     RECT  4.787 60.96 5.699 61.032 ;
     RECT  4.396 84.816 5.708 84.84 ;
     RECT  5.699 11.28 5.717 12.024 ;
     RECT  5.315 71.28 5.74 71.544 ;
     RECT  5.269 115.536 5.74 115.704 ;
     RECT  5.425 83.616 5.747 83.64 ;
     RECT  4.417 80.64 5.749 80.664 ;
     RECT  5.708 84.816 5.749 85.368 ;
     RECT  5.603 49.728 5.753 49.752 ;
     RECT  5.749 84.816 5.753 86.04 ;
     RECT  4.637 105.312 5.753 105.336 ;
     RECT  5.753 85.344 5.795 86.04 ;
     RECT  5.749 80.112 5.797 80.664 ;
     RECT  5.393 65.52 5.825 65.544 ;
     RECT  5.069 96 5.825 96.024 ;
     RECT  5.797 80.112 5.843 81.336 ;
     RECT  3.829 34.8 5.852 34.824 ;
     RECT  5.609 75.792 5.897 75.816 ;
     RECT  5.843 80.64 5.897 81.336 ;
     RECT  5.681 100.656 5.897 101.016 ;
     RECT  5.317 26.208 5.939 26.712 ;
     RECT  4.588 43.296 5.939 43.656 ;
     RECT  5.365 90.048 5.987 90.552 ;
     RECT  5.123 23.328 6.041 23.352 ;
     RECT  4.889 120.288 6.041 120.36 ;
     RECT  5.987 90.24 6.073 90.552 ;
     RECT  5.701 82.32 6.145 82.344 ;
     RECT  4.787 58.128 6.149 58.152 ;
     RECT  5.245 78.048 6.181 78.072 ;
     RECT  6.145 82.032 6.185 82.344 ;
     RECT  5.795 86.016 6.217 86.04 ;
     RECT  6.181 78.048 6.229 78.12 ;
     RECT  6.229 77.136 6.275 78.12 ;
     RECT  5.857 36.48 6.277 36.504 ;
     RECT  5.569 107.952 6.293 108.216 ;
     RECT  6.236 9.648 6.323 9.672 ;
     RECT  6.277 36.48 6.323 36.936 ;
     RECT  5.699 13.056 6.329 13.08 ;
     RECT  4.993 54.048 6.329 54.072 ;
     RECT  5.357 72.96 6.329 72.984 ;
     RECT  5.897 100.944 6.329 101.016 ;
     RECT  6.275 77.136 6.365 77.16 ;
     RECT  4.129 45.264 6.38 45.288 ;
     RECT  5.171 67.68 6.397 67.704 ;
     RECT  6.38 45.264 6.421 46.104 ;
     RECT  4.355 19.92 6.433 20.04 ;
     RECT  6.277 38.112 6.437 38.136 ;
     RECT  6.397 67.68 6.437 67.896 ;
     RECT  6.421 45.12 6.467 46.104 ;
     RECT  6.361 47.28 6.467 47.304 ;
     RECT  5.461 97.44 6.572 97.464 ;
     RECT  6.433 19.392 6.611 20.04 ;
     RECT  6.565 18.048 6.652 18.072 ;
     RECT  6.572 97.44 6.659 97.704 ;
     RECT  4.525 112.848 6.668 112.872 ;
     RECT  6.668 112.608 6.709 112.872 ;
     RECT  6.709 111.696 6.725 112.872 ;
     RECT  6.725 111.696 6.755 112.632 ;
     RECT  5.681 30.144 6.761 30.168 ;
     RECT  4.453 103.728 6.761 103.752 ;
     RECT  5.533 93.168 6.793 93.48 ;
     RECT  5.717 11.28 6.797 11.304 ;
     RECT  5.852 34.608 6.829 34.824 ;
     RECT  6.793 92.928 6.833 93.48 ;
     RECT  6.613 25.056 6.853 25.08 ;
     RECT  5.939 43.344 6.853 43.656 ;
     RECT  5.699 60.96 6.853 60.984 ;
     RECT  6.505 62.4 6.853 62.424 ;
     RECT  6.86 102.288 6.893 102.312 ;
     RECT  5.893 40.032 7.004 40.056 ;
     RECT  6.853 60.96 7.004 62.424 ;
     RECT  7.004 60.816 7.045 62.424 ;
     RECT  6.217 86.016 7.045 86.616 ;
     RECT  7.045 86.016 7.093 86.664 ;
     RECT  5.74 71.28 7.1 71.304 ;
     RECT  7.1 71.232 7.141 71.304 ;
     RECT  5.699 52.416 7.153 52.44 ;
     RECT  4.561 32.448 7.189 32.472 ;
     RECT  5.74 115.68 7.189 115.704 ;
     RECT  5.699 14.352 7.808 14.376 ;
     RECT  5.457 15.984 7.808 16.008 ;
     RECT  6.611 20.016 7.808 20.04 ;
     RECT  6.853 24.48 7.808 25.08 ;
     RECT  5.939 26.208 7.808 26.376 ;
     RECT  7.189 32.304 7.808 32.472 ;
     RECT  6.829 34.176 7.808 34.824 ;
     RECT  6.323 36.912 7.808 36.936 ;
     RECT  7.004 40.032 7.808 40.44 ;
     RECT  7.009 42.192 7.808 42.216 ;
     RECT  6.853 43.344 7.808 43.944 ;
     RECT  6.467 45.12 7.808 45.144 ;
     RECT  7.477 49.536 7.808 49.56 ;
     RECT  7.436 51.12 7.808 51.144 ;
     RECT  7.153 52.416 7.808 52.584 ;
     RECT  4.885 55.968 7.808 55.992 ;
     RECT  6.865 59.28 7.808 59.304 ;
     RECT  7.045 60.816 7.808 63.24 ;
     RECT  7.004 64.848 7.808 64.872 ;
     RECT  6.437 67.872 7.808 67.896 ;
     RECT  7.141 71.232 7.808 71.64 ;
     RECT  6.793 73.008 7.808 73.032 ;
     RECT  5.897 80.64 7.808 80.664 ;
     RECT  6.185 82.032 7.808 82.056 ;
     RECT  7.657 84.336 7.808 84.36 ;
     RECT  7.093 85.68 7.808 86.664 ;
     RECT  6.361 88.56 7.808 88.584 ;
     RECT  6.073 90.24 7.808 90.648 ;
     RECT  6.833 92.928 7.808 92.952 ;
     RECT  6.659 97.44 7.808 97.464 ;
     RECT  6.613 99.168 7.808 99.192 ;
     RECT  6.329 100.944 7.808 100.968 ;
     RECT  6.893 102.288 7.808 102.648 ;
     RECT  6.973 106.56 7.808 106.584 ;
     RECT  6.293 108.192 7.808 108.216 ;
     RECT  7.333 109.44 7.808 109.464 ;
     RECT  6.755 111.696 7.808 111.72 ;
     RECT  7.189 114.384 7.808 114.408 ;
     RECT  7.189 115.68 7.808 116.568 ;
     RECT  7.117 117.984 7.808 118.008 ;
     RECT  6.325 121.152 7.808 121.176 ;
     RECT  7.808 2.148 7.912 127.452 ;
     RECT  7.912 2.418 8.104 127.182 ;
     RECT  8.104 99.168 8.165 99.192 ;
     RECT  8.104 26.352 8.243 26.376 ;
     RECT  8.104 35.616 8.243 35.64 ;
     RECT  8.104 120.24 8.243 121.608 ;
     RECT  8.104 52.56 8.273 52.584 ;
     RECT  8.243 120.24 8.281 120.264 ;
     RECT  8.104 27.936 8.309 27.96 ;
     RECT  8.104 49.536 8.309 49.56 ;
     RECT  8.104 114.384 8.309 114.408 ;
     RECT  8.104 116.544 8.309 116.568 ;
     RECT  8.104 73.008 8.381 73.032 ;
     RECT  8.104 36.912 8.453 36.936 ;
     RECT  8.104 32.304 8.489 32.328 ;
     RECT  8.104 59.28 8.489 59.304 ;
     RECT  8.104 40.032 13.208 40.056 ;
     RECT  8.104 90.24 13.208 90.264 ;
     RECT  13.208 2.148 13.312 127.452 ;
     RECT  13.312 2.418 13.504 127.182 ;
     RECT  13.504 40.032 18.608 40.056 ;
     RECT  13.504 90.24 18.608 90.264 ;
     RECT  18.608 2.148 18.712 127.452 ;
     RECT  18.712 2.418 18.904 127.182 ;
     RECT  18.904 40.032 24.008 40.056 ;
     RECT  18.904 90.24 24.008 90.264 ;
     RECT  24.008 2.148 24.112 127.452 ;
     RECT  24.112 2.418 24.304 127.182 ;
     RECT  24.304 40.032 29.408 40.056 ;
     RECT  24.304 90.24 29.408 90.264 ;
     RECT  29.408 2.148 29.512 127.452 ;
     RECT  29.512 2.418 29.704 127.182 ;
     RECT  29.704 40.032 34.808 40.056 ;
     RECT  29.704 90.24 34.808 90.264 ;
     RECT  32.641 120.528 34.808 120.552 ;
     RECT  34.808 2.148 34.912 127.452 ;
     RECT  34.912 2.418 35.104 127.182 ;
     RECT  35.104 120.528 35.201 120.648 ;
     RECT  35.104 40.032 40.208 40.056 ;
     RECT  35.104 90.24 40.208 90.264 ;
     RECT  35.201 120.624 40.208 120.648 ;
     RECT  40.208 2.148 40.312 127.452 ;
     RECT  40.312 2.418 40.504 127.182 ;
     RECT  40.504 40.032 45.608 40.056 ;
     RECT  40.504 90.24 45.608 90.264 ;
     RECT  40.504 120.624 45.608 120.648 ;
     RECT  45.608 2.148 45.712 127.452 ;
     RECT  45.712 2.418 45.904 127.182 ;
     RECT  45.904 90.24 46.217 90.6 ;
     RECT  46.217 90.48 47.363 90.6 ;
     RECT  48.085 32.736 49.349 32.76 ;
     RECT  49.237 30.864 49.381 30.888 ;
     RECT  45.904 40.032 49.489 40.056 ;
     RECT  49.532 108.816 49.619 108.84 ;
     RECT  49.381 30.816 49.637 30.888 ;
     RECT  49.561 10.848 49.645 11.448 ;
     RECT  49.525 116.256 49.669 116.616 ;
     RECT  49.628 118.56 49.669 118.584 ;
     RECT  45.904 120.624 49.669 120.648 ;
     RECT  49.573 107.712 49.709 107.736 ;
     RECT  49.669 118.56 49.715 119.112 ;
     RECT  49.669 120.288 49.859 120.648 ;
     RECT  49.489 22.464 49.885 22.488 ;
     RECT  49.273 82.848 49.964 82.872 ;
     RECT  49.573 9.648 49.997 9.672 ;
     RECT  49.669 116.256 49.997 117.144 ;
     RECT  47.363 90.48 50.005 90.504 ;
     RECT  49.489 39.744 50.101 40.056 ;
     RECT  48.157 91.776 50.137 91.8 ;
     RECT  49.957 27.936 50.149 27.96 ;
     RECT  50.029 59.424 50.149 59.448 ;
     RECT  49.993 60.768 50.149 60.792 ;
     RECT  49.993 85.824 50.149 85.848 ;
     RECT  48.697 105.408 50.149 105.432 ;
     RECT  49.813 29.76 50.156 29.784 ;
     RECT  49.637 30.816 50.156 30.84 ;
     RECT  49.921 19.776 50.197 19.8 ;
     RECT  49.777 42.72 50.197 42.744 ;
     RECT  49.885 21.648 50.209 22.488 ;
     RECT  49.129 18.672 50.245 18.696 ;
     RECT  49.489 101.712 50.245 101.736 ;
     RECT  50.149 85.392 50.353 85.848 ;
     RECT  49.997 116.256 50.353 117.096 ;
     RECT  49.165 12.864 50.389 12.888 ;
     RECT  49.993 53.568 50.389 53.592 ;
     RECT  50.209 88.608 50.425 88.632 ;
     RECT  49.309 34.08 50.461 34.104 ;
     RECT  50.197 19.776 50.569 20.328 ;
     RECT  50.149 60.768 50.629 60.936 ;
     RECT  47.317 95.184 50.636 95.208 ;
     RECT  50.245 101.04 50.641 101.736 ;
     RECT  49.057 44.976 50.677 45 ;
     RECT  49.345 63.84 50.677 63.864 ;
     RECT  50.641 101.04 50.677 102.648 ;
     RECT  50.005 90.384 50.725 90.504 ;
     RECT  50.137 91.728 50.725 91.8 ;
     RECT  50.569 113.952 50.725 113.976 ;
     RECT  49.964 82.848 50.773 83.448 ;
     RECT  50.101 39.744 50.808 40.344 ;
     RECT  50.641 78.624 50.821 78.648 ;
     RECT  50.725 113.952 50.849 114.264 ;
     RECT  50.353 115.728 50.849 117.096 ;
     RECT  50.677 44.592 50.869 45 ;
     RECT  50.857 57.024 50.869 57.048 ;
     RECT  49.957 72.24 50.869 72.264 ;
     RECT  50.677 66.048 50.929 66.072 ;
     RECT  49.489 74.592 50.929 74.616 ;
     RECT  50.461 33.6 51.004 34.104 ;
     RECT  49.645 11.376 51.008 11.448 ;
     RECT  50.389 12.864 51.008 13.656 ;
     RECT  50.005 14.784 51.008 14.808 ;
     RECT  49.964 15.984 51.008 16.008 ;
     RECT  49.993 17.088 51.008 17.112 ;
     RECT  50.245 18.576 51.008 18.696 ;
     RECT  50.569 19.776 51.008 20.52 ;
     RECT  50.209 21.504 51.008 22.488 ;
     RECT  50.389 24.624 51.008 24.648 ;
     RECT  49.813 26.208 51.008 26.232 ;
     RECT  50.149 27.936 51.008 28.296 ;
     RECT  50.156 29.76 51.008 30.84 ;
     RECT  50.636 31.92 51.008 31.944 ;
     RECT  51.004 33.552 51.008 34.104 ;
     RECT  49.489 36.48 51.008 36.504 ;
     RECT  50.869 38.4 51.008 38.424 ;
     RECT  50.808 39.744 51.008 40.584 ;
     RECT  50.197 42.144 51.008 42.744 ;
     RECT  50.869 43.824 51.008 45 ;
     RECT  50.425 46.224 51.008 46.248 ;
     RECT  49.633 47.328 51.008 47.352 ;
     RECT  50.101 48.624 51.008 49.464 ;
     RECT  49.705 50.544 51.008 50.568 ;
     RECT  50.389 52.944 51.008 53.592 ;
     RECT  50.869 56.352 51.008 57.048 ;
     RECT  50.149 58.656 51.008 59.592 ;
     RECT  50.629 60.768 51.008 61.128 ;
     RECT  50.101 62.16 51.008 62.184 ;
     RECT  50.677 63.84 51.008 64.2 ;
     RECT  50.929 65.52 51.008 66.072 ;
     RECT  50.029 67.248 51.008 67.272 ;
     RECT  50.209 70.032 51.008 70.056 ;
     RECT  50.869 72.24 51.008 72.84 ;
     RECT  50.929 73.872 51.008 74.616 ;
     RECT  50.677 77.568 51.008 77.592 ;
     RECT  50.821 78.624 51.008 79.272 ;
     RECT  49.993 81.456 51.008 81.48 ;
     RECT  50.773 82.656 51.008 83.448 ;
     RECT  50.353 84.912 51.008 85.848 ;
     RECT  49.489 86.88 51.008 86.904 ;
     RECT  50.425 88.368 51.008 88.632 ;
     RECT  50.725 90.384 51.008 91.8 ;
     RECT  50.713 93.216 51.008 93.24 ;
     RECT  50.636 95.184 51.008 95.688 ;
     RECT  49.921 96.864 51.008 96.888 ;
     RECT  48.913 99.168 51.008 99.192 ;
     RECT  50.677 100.848 51.008 102.648 ;
     RECT  50.569 104.304 51.008 104.328 ;
     RECT  50.149 105.408 51.008 106.44 ;
     RECT  49.573 109.92 51.008 109.944 ;
     RECT  49.561 112.8 51.008 112.824 ;
     RECT  50.849 113.952 51.008 117.096 ;
     RECT  49.715 119.088 51.008 119.112 ;
     RECT  50.389 120.864 51.008 120.888 ;
     RECT  49.813 124.272 51.008 124.296 ;
     RECT  51.008 2.148 51.112 127.452 ;
     RECT  51.112 2.418 51.304 127.452 ;
     RECT  51.304 19.632 51.329 21.528 ;
     RECT  51.304 72.912 51.329 73.896 ;
     RECT  51.304 13.632 51.365 14.088 ;
     RECT  51.304 76.896 51.365 77.592 ;
     RECT  51.304 59.424 51.437 59.592 ;
     RECT  51.304 63.504 51.443 66.504 ;
     RECT  51.443 65.52 51.484 66.504 ;
     RECT  51.484 65.52 51.635 65.544 ;
     RECT  51.329 19.632 51.731 21.288 ;
     RECT  51.304 45.552 51.731 45.576 ;
     RECT  51.304 48.624 51.731 48.648 ;
     RECT  51.304 50.256 51.731 50.28 ;
     RECT  51.304 37.296 51.82 37.32 ;
     RECT  51.304 15.312 51.827 15.864 ;
     RECT  51.731 19.632 51.827 20.52 ;
     RECT  51.304 103.728 51.827 103.752 ;
     RECT  51.365 13.68 51.875 14.088 ;
     RECT  51.827 15.312 51.875 15.768 ;
     RECT  51.304 38.352 51.875 38.808 ;
     RECT  51.304 25.872 51.923 26.712 ;
     RECT  51.437 59.424 51.923 59.448 ;
     RECT  51.304 80.928 51.977 81.24 ;
     RECT  51.304 79.248 52.012 79.656 ;
     RECT  51.977 81.216 52.019 81.24 ;
     RECT  51.304 110.88 52.019 110.904 ;
     RECT  51.304 113.616 52.019 113.64 ;
     RECT  51.304 115.584 52.019 115.608 ;
     RECT  52.012 79.248 52.021 79.272 ;
     RECT  51.304 28.512 52.049 28.536 ;
     RECT  51.304 30.192 52.057 30.216 ;
     RECT  51.875 38.352 52.085 38.376 ;
     RECT  51.827 20.304 52.193 20.52 ;
     RECT  52.193 20.304 52.229 20.328 ;
     RECT  52.021 127.632 52.229 127.656 ;
     RECT  51.304 52.416 52.259 52.44 ;
     RECT  51.304 56.976 52.259 57.624 ;
     RECT  51.304 75.792 52.265 75.816 ;
     RECT  51.304 55.056 52.301 55.08 ;
     RECT  51.304 87.456 52.307 88.92 ;
     RECT  51.304 90.24 52.345 90.648 ;
     RECT  51.304 40.32 52.364 40.872 ;
     RECT  51.304 9.072 52.403 9.096 ;
     RECT  52.357 10.32 52.405 10.344 ;
     RECT  52.364 39.888 52.405 40.872 ;
     RECT  52.405 10.32 52.445 10.824 ;
     RECT  51.304 70.032 52.445 70.056 ;
     RECT  51.365 76.896 52.445 76.92 ;
     RECT  51.875 13.68 52.451 13.704 ;
     RECT  52.405 39.888 52.451 41.016 ;
     RECT  51.304 43.296 52.451 43.32 ;
     RECT  51.329 72.912 52.481 72.936 ;
     RECT  52.445 10.8 52.489 10.824 ;
     RECT  51.304 82.656 52.499 82.968 ;
     RECT  51.304 117.936 52.499 117.96 ;
     RECT  51.304 33.552 52.517 33.576 ;
     RECT  52.451 40.32 52.517 41.016 ;
     RECT  52.508 65.424 52.595 65.448 ;
     RECT  52.345 90.24 52.595 90.6 ;
     RECT  51.304 23.328 52.661 23.352 ;
     RECT  52.517 40.32 52.691 40.872 ;
     RECT  52.453 85.056 52.691 85.08 ;
     RECT  51.304 105.552 52.693 105.672 ;
     RECT  51.304 121.008 52.693 121.032 ;
     RECT  52.693 105.552 52.733 106.008 ;
     RECT  52.413 119.04 52.739 119.064 ;
     RECT  51.304 125.424 52.739 125.448 ;
     RECT  52.307 87.456 52.757 87.48 ;
     RECT  52.307 88.896 52.769 88.92 ;
     RECT  52.757 86.592 52.796 87.48 ;
     RECT  52.441 24.48 52.835 24.504 ;
     RECT  52.733 105.6 52.835 106.008 ;
     RECT  52.796 86.4 52.841 87.48 ;
     RECT  52.595 90.576 52.849 90.6 ;
     RECT  51.923 25.872 52.877 25.896 ;
     RECT  52.693 62.112 52.883 62.136 ;
     RECT  52.841 86.4 52.883 86.424 ;
     RECT  51.443 63.504 52.924 63.528 ;
     RECT  52.837 85.104 52.949 85.272 ;
     RECT  52.841 87.456 53.057 87.48 ;
     RECT  51.304 108.192 53.077 108.216 ;
     RECT  52.835 105.984 53.123 106.008 ;
     RECT  53.077 107.376 53.123 108.216 ;
     RECT  53.123 107.376 53.164 107.4 ;
     RECT  52.513 96.72 53.228 96.744 ;
     RECT  53.228 96.288 53.315 96.744 ;
     RECT  52.259 57.6 53.525 57.624 ;
     RECT  51.304 102.24 53.603 102.264 ;
     RECT  52.499 82.656 53.669 82.68 ;
     RECT  53.269 99.552 53.741 99.576 ;
     RECT  51.304 35.136 53.777 35.16 ;
     RECT  51.875 15.312 53.849 15.336 ;
     RECT  52.691 40.464 56.408 40.872 ;
     RECT  52.729 66.24 56.408 66.264 ;
     RECT  52.949 85.104 56.408 85.128 ;
     RECT  52.693 121.008 56.408 121.08 ;
     RECT  56.408 2.148 56.512 127.452 ;
     RECT  56.512 2.418 56.704 127.182 ;
     RECT  56.704 40.56 57.125 40.872 ;
     RECT  56.704 121.008 58.705 121.08 ;
     RECT  58.705 121.008 58.745 121.128 ;
     RECT  57.125 40.56 61.808 40.584 ;
     RECT  56.704 66.24 61.808 66.264 ;
     RECT  56.704 85.104 61.808 85.128 ;
     RECT  58.745 121.056 61.808 121.128 ;
     RECT  61.808 2.148 61.912 127.452 ;
     RECT  61.912 2.418 62.104 127.182 ;
     RECT  62.104 121.056 63.677 121.128 ;
     RECT  63.677 121.056 65.185 121.08 ;
     RECT  65.185 120.768 65.225 121.08 ;
     RECT  62.104 40.56 67.208 40.584 ;
     RECT  62.104 66.24 67.208 66.264 ;
     RECT  62.104 85.104 67.208 85.128 ;
     RECT  65.225 120.768 67.208 120.792 ;
     RECT  67.208 2.148 67.312 127.452 ;
     RECT  67.312 2.418 67.504 127.182 ;
     RECT  67.504 40.56 72.608 40.584 ;
     RECT  67.504 66.24 72.608 66.264 ;
     RECT  67.504 85.104 72.608 85.128 ;
     RECT  67.504 120.768 72.608 120.792 ;
     RECT  72.608 2.148 72.712 127.452 ;
     RECT  72.712 2.418 72.904 127.182 ;
     RECT  72.904 40.56 78.008 40.584 ;
     RECT  72.904 66.24 78.008 66.264 ;
     RECT  72.904 85.104 78.008 85.128 ;
     RECT  72.904 120.768 78.008 120.792 ;
     RECT  78.008 2.148 78.112 127.452 ;
     RECT  78.112 2.418 78.304 127.182 ;
     RECT  78.304 40.56 83.408 40.584 ;
     RECT  78.304 66.24 83.408 66.264 ;
     RECT  78.304 85.104 83.408 85.128 ;
     RECT  78.304 120.768 83.408 120.792 ;
     RECT  83.408 2.148 83.512 127.452 ;
     RECT  83.512 2.418 83.704 127.182 ;
     RECT  83.704 40.56 88.808 40.584 ;
     RECT  83.704 66.24 88.808 66.264 ;
     RECT  83.704 85.104 88.808 85.128 ;
     RECT  83.704 120.768 88.808 120.792 ;
     RECT  88.808 2.148 88.912 127.452 ;
     RECT  88.912 2.418 89.104 127.182 ;
     RECT  94.201 9.888 94.208 9.912 ;
     RECT  89.104 40.56 94.208 40.584 ;
     RECT  89.104 66.24 94.208 66.264 ;
     RECT  89.104 85.104 94.208 85.128 ;
     RECT  89.104 120.768 94.208 120.792 ;
     RECT  94.208 2.148 94.312 127.452 ;
     RECT  94.312 2.418 94.504 127.182 ;
     RECT  94.504 42.72 94.739 43.752 ;
     RECT  94.504 54.672 94.825 54.696 ;
     RECT  94.504 63.744 95.075 64.2 ;
     RECT  94.504 118.176 95.075 119.064 ;
     RECT  94.504 9.888 95.213 10.248 ;
     RECT  94.504 20.208 95.219 20.232 ;
     RECT  94.504 87.84 95.219 87.864 ;
     RECT  94.504 90.912 95.219 90.936 ;
     RECT  94.504 111.696 95.363 111.72 ;
     RECT  94.504 113.712 95.363 114.6 ;
     RECT  94.504 110.496 95.365 110.616 ;
     RECT  95.363 114.576 95.429 114.6 ;
     RECT  95.213 10.176 95.537 10.248 ;
     RECT  95.497 82.608 95.581 82.632 ;
     RECT  94.504 92.544 95.605 92.568 ;
     RECT  94.504 94.08 95.605 94.104 ;
     RECT  95.605 92.544 95.651 94.104 ;
     RECT  95.651 92.544 95.692 93.384 ;
     RECT  95.075 63.792 95.701 64.2 ;
     RECT  95.497 11.856 95.713 11.88 ;
     RECT  95.701 63.792 95.747 64.968 ;
     RECT  94.504 66.24 95.747 66.264 ;
     RECT  94.504 30.288 95.749 30.312 ;
     RECT  95.509 84 95.753 84.024 ;
     RECT  94.504 40.56 95.756 40.584 ;
     RECT  95.701 78.48 95.788 78.696 ;
     RECT  95.756 40.56 95.797 41.304 ;
     RECT  94.504 26.448 95.843 26.472 ;
     RECT  95.797 40.416 95.843 41.304 ;
     RECT  95.788 78.672 95.861 78.696 ;
     RECT  95.747 64.944 95.897 64.968 ;
     RECT  95.075 118.176 95.897 118.2 ;
     RECT  95.749 29.616 95.987 30.312 ;
     RECT  95.996 89.28 96.037 89.304 ;
     RECT  96.037 89.28 96.083 89.976 ;
     RECT  96.133 70.704 96.22 70.728 ;
     RECT  95.987 29.616 96.221 29.64 ;
     RECT  95.843 40.416 96.253 40.584 ;
     RECT  94.504 96.288 96.253 96.312 ;
     RECT  96.253 95.76 96.293 96.312 ;
     RECT  96.217 105.456 96.325 105.48 ;
     RECT  96.325 105.456 96.365 105.912 ;
     RECT  94.504 46.176 96.421 46.2 ;
     RECT  94.504 47.472 96.421 47.496 ;
     RECT  94.504 99.6 96.429 99.624 ;
     RECT  94.504 35.952 96.467 35.976 ;
     RECT  96.421 37.008 96.509 37.608 ;
     RECT  96.421 46.176 96.509 47.496 ;
     RECT  95.497 102.96 96.577 102.984 ;
     RECT  95.537 10.224 96.613 10.248 ;
     RECT  95.713 11.856 96.613 12.744 ;
     RECT  95.797 23.376 96.613 23.4 ;
     RECT  96.577 102.624 96.617 102.984 ;
     RECT  96.613 23.376 96.653 23.928 ;
     RECT  96.613 10.224 96.659 12.744 ;
     RECT  94.504 77.184 96.685 77.208 ;
     RECT  96.659 10.224 96.7 11.976 ;
     RECT  96.037 75.216 96.721 75.24 ;
     RECT  96.001 108.048 96.757 108.072 ;
     RECT  96.721 75.216 96.761 75.864 ;
     RECT  96.325 100.992 96.797 101.016 ;
     RECT  96.325 98.544 96.805 98.568 ;
     RECT  94.504 56.16 96.812 56.184 ;
     RECT  96.805 98.544 96.851 98.664 ;
     RECT  95.756 25.104 96.869 25.128 ;
     RECT  96.509 46.176 96.869 46.872 ;
     RECT  95.747 63.792 96.899 63.816 ;
     RECT  94.504 16.8 96.901 16.824 ;
     RECT  96.761 75.84 96.901 75.864 ;
     RECT  96.685 76.944 96.901 77.208 ;
     RECT  94.504 120.144 96.905 120.792 ;
     RECT  96.901 75.84 96.947 77.736 ;
     RECT  94.504 52.992 96.997 53.016 ;
     RECT  96.812 56.16 96.997 56.712 ;
     RECT  95.569 57.792 96.997 57.816 ;
     RECT  95.569 33.648 97.007 33.672 ;
     RECT  96.757 107.136 97.007 108.072 ;
     RECT  96.997 52.992 97.043 53.784 ;
     RECT  96.997 56.16 97.043 57.816 ;
     RECT  97.043 53.328 97.045 53.784 ;
     RECT  97.043 56.16 97.045 57.048 ;
     RECT  96.253 18.384 97.081 18.408 ;
     RECT  97.045 19.68 97.081 19.704 ;
     RECT  97.045 53.328 97.084 57.048 ;
     RECT  94.504 85.104 97.085 85.944 ;
     RECT  97.007 107.136 97.085 108.84 ;
     RECT  96.253 39.888 97.091 40.584 ;
     RECT  95.692 92.544 97.117 92.568 ;
     RECT  97.084 54.72 97.132 57.048 ;
     RECT  94.504 80.4 97.153 80.424 ;
     RECT  97.117 92.544 97.157 92.904 ;
     RECT  97.081 18.384 97.165 19.704 ;
     RECT  96.869 46.752 97.193 46.872 ;
     RECT  97.132 55.536 97.193 57.048 ;
     RECT  97.153 80.112 97.193 80.424 ;
     RECT  97.091 39.888 97.196 39.912 ;
     RECT  94.504 14.832 97.225 14.856 ;
     RECT  96.293 95.76 97.225 95.784 ;
     RECT  97.157 92.64 97.235 92.904 ;
     RECT  97.225 95.184 97.265 95.784 ;
     RECT  97.196 39.072 97.283 39.912 ;
     RECT  97.085 85.104 97.283 85.512 ;
     RECT  97.141 100.128 97.283 100.344 ;
     RECT  97.085 108.816 97.283 108.84 ;
     RECT  97.265 95.184 97.309 95.208 ;
     RECT  97.045 41.568 97.369 41.592 ;
     RECT  94.739 42.72 97.369 42.744 ;
     RECT  96.947 76.368 97.373 77.736 ;
     RECT  97.045 116.304 97.373 116.328 ;
     RECT  97.165 19.68 97.379 19.704 ;
     RECT  96.901 16.512 97.381 16.824 ;
     RECT  97.165 18.384 97.381 18.408 ;
     RECT  97.381 16.512 97.427 18.408 ;
     RECT  97.369 41.568 97.427 42.744 ;
     RECT  97.427 41.76 97.429 42.744 ;
     RECT  97.333 26.736 97.441 26.76 ;
     RECT  95.605 62.016 97.445 62.04 ;
     RECT  97.427 16.512 97.468 17.832 ;
     RECT  97.429 41.76 97.475 43.512 ;
     RECT  96.853 48.816 97.481 48.84 ;
     RECT  96.653 23.904 97.517 23.928 ;
     RECT  94.504 71.808 97.517 71.832 ;
     RECT  96.253 113.088 97.523 113.112 ;
     RECT  96.365 105.888 97.585 105.912 ;
     RECT  97.225 14.256 97.589 14.952 ;
     RECT  94.504 21.648 97.589 21.672 ;
     RECT  96.901 64.128 97.619 64.776 ;
     RECT  96.001 59.28 97.621 59.304 ;
     RECT  97.468 16.512 97.625 17.4 ;
     RECT  97.585 105.408 97.625 105.912 ;
     RECT  96.7 11.856 97.657 11.976 ;
     RECT  97.573 63.12 97.66 63.144 ;
     RECT  97.621 59.184 97.661 59.304 ;
     RECT  94.504 68.352 97.717 68.376 ;
     RECT  97.189 83.184 97.724 83.208 ;
     RECT  97.007 33.648 97.765 33.768 ;
     RECT  97.717 68.352 97.765 69.144 ;
     RECT  97.724 83.184 97.765 83.784 ;
     RECT  97.475 43.488 97.769 43.512 ;
     RECT  97.765 67.776 97.804 69.144 ;
     RECT  97.804 67.776 97.805 68.376 ;
     RECT  97.237 70.416 97.805 70.44 ;
     RECT  97.477 111.696 97.805 111.72 ;
     RECT  97.765 33.024 97.811 34.2 ;
     RECT  97.765 82.848 97.811 84.312 ;
     RECT  96.509 37.008 97.837 37.032 ;
     RECT  96.617 102.624 97.837 102.648 ;
     RECT  97.837 36.768 97.877 37.032 ;
     RECT  97.657 11.856 98.005 12.36 ;
     RECT  97.333 30 98.005 30.024 ;
     RECT  95.9 31.632 98.005 31.656 ;
     RECT  97.837 102.336 98.012 102.648 ;
     RECT  97.873 103.728 98.012 103.752 ;
     RECT  98.005 11.856 98.051 13.128 ;
     RECT  98.005 30 98.051 31.656 ;
     RECT  97.657 19.92 98.053 19.944 ;
     RECT  97.193 57.024 98.053 57.048 ;
     RECT  97.765 88.752 98.053 88.776 ;
     RECT  96.083 89.952 98.089 89.976 ;
     RECT  98.051 11.856 98.093 11.88 ;
     RECT  98.053 57.024 98.093 57.576 ;
     RECT  97.811 82.848 98.093 82.872 ;
     RECT  98.012 102.336 98.093 103.752 ;
     RECT  98.012 35.328 98.099 35.352 ;
     RECT  98.053 88.32 98.099 88.776 ;
     RECT  98.093 102.336 98.099 103.464 ;
     RECT  97.729 38.208 98.165 38.232 ;
     RECT  98.053 19.92 98.201 20.568 ;
     RECT  98.051 30 98.237 30.984 ;
     RECT  97.475 41.76 98.237 41.784 ;
     RECT  97.193 55.536 98.237 55.56 ;
     RECT  95.365 110.592 98.237 110.616 ;
     RECT  97.441 26.208 98.269 26.76 ;
     RECT  97.193 80.112 98.269 80.136 ;
     RECT  97.619 64.128 98.273 64.152 ;
     RECT  98.261 49.056 98.293 49.08 ;
     RECT  98.099 102.336 98.293 102.36 ;
     RECT  98.269 25.92 98.3 26.76 ;
     RECT  97.117 28.416 98.3 28.44 ;
     RECT  98.089 89.952 98.339 90.936 ;
     RECT  98.293 101.856 98.339 102.36 ;
     RECT  98.293 49.056 98.345 50.568 ;
     RECT  98.345 49.872 98.38 50.568 ;
     RECT  98.339 101.856 98.38 101.88 ;
     RECT  96.905 120.768 98.381 120.792 ;
     RECT  98.3 25.92 98.387 28.44 ;
     RECT  97.081 119.664 98.449 119.688 ;
     RECT  96.7 10.224 98.525 10.248 ;
     RECT  98.099 88.32 98.525 88.344 ;
     RECT  98.444 45.312 98.531 45.336 ;
     RECT  98.449 119.664 98.561 120.168 ;
     RECT  98.237 30 98.581 30.024 ;
     RECT  97.283 39.888 98.581 39.912 ;
     RECT  97.193 46.752 98.581 46.776 ;
     RECT  98.339 90.912 98.581 90.936 ;
     RECT  97.945 87.168 98.593 87.192 ;
     RECT  97.811 34.176 98.597 34.2 ;
     RECT  98.387 28.416 98.627 28.44 ;
     RECT  98.581 29.616 98.627 30.024 ;
     RECT  98.581 39.6 98.627 39.912 ;
     RECT  98.581 46.752 98.627 46.92 ;
     RECT  98.581 90.912 98.627 91.464 ;
     RECT  97.765 60.672 98.629 60.696 ;
     RECT  98.305 72.96 98.629 72.984 ;
     RECT  98.269 80.112 98.629 80.184 ;
     RECT  97.283 85.488 98.629 85.512 ;
     RECT  98.593 87.168 98.629 87.816 ;
     RECT  96.973 114.528 98.629 114.552 ;
     RECT  98.387 25.92 98.633 26.76 ;
     RECT  97.237 94.08 98.633 94.104 ;
     RECT  98.521 97.44 98.725 97.464 ;
     RECT  96.851 98.64 98.725 98.664 ;
     RECT  98.269 117.696 98.725 117.72 ;
     RECT  99.025 107.712 99.157 107.736 ;
     RECT  98.593 109.008 99.157 109.032 ;
     RECT  97.405 8.928 99.608 8.952 ;
     RECT  98.051 13.104 99.608 13.128 ;
     RECT  97.589 14.928 99.608 14.952 ;
     RECT  97.625 17.376 99.608 17.4 ;
     RECT  98.201 19.92 99.608 19.944 ;
     RECT  97.909 24.24 99.608 24.264 ;
     RECT  98.633 25.92 99.608 26.232 ;
     RECT  98.627 29.616 99.608 29.64 ;
     RECT  97.811 33.024 99.608 33.048 ;
     RECT  97.877 36.768 99.608 36.792 ;
     RECT  98.627 39.6 99.608 39.624 ;
     RECT  97.909 43.536 99.608 43.56 ;
     RECT  98.627 46.896 99.608 46.92 ;
     RECT  98.78 48.048 99.608 48.072 ;
     RECT  98.38 49.872 99.608 49.896 ;
     RECT  98.293 51.6 99.608 51.624 ;
     RECT  97.084 53.328 99.608 53.352 ;
     RECT  98.093 57.552 99.608 57.576 ;
     RECT  97.661 59.184 99.608 59.208 ;
     RECT  98.629 60.672 99.608 61.608 ;
     RECT  97.805 67.776 99.608 67.8 ;
     RECT  98.053 69.504 99.608 69.528 ;
     RECT  98.521 71.76 99.608 71.784 ;
     RECT  98.629 72.816 99.608 72.984 ;
     RECT  96.181 74.064 99.608 74.088 ;
     RECT  97.373 76.368 99.608 76.392 ;
     RECT  97.373 77.712 99.608 77.736 ;
     RECT  98.629 79.584 99.608 80.184 ;
     RECT  97.225 81.456 99.608 81.48 ;
     RECT  97.811 84.288 99.608 84.312 ;
     RECT  98.629 85.488 99.608 87.816 ;
     RECT  98.627 91.44 99.608 91.464 ;
     RECT  97.235 92.88 99.608 92.904 ;
     RECT  98.725 97.44 99.608 98.664 ;
     RECT  97.283 100.32 99.608 100.344 ;
     RECT  97.625 105.408 99.608 105.432 ;
     RECT  99.157 107.712 99.608 109.032 ;
     RECT  98.629 113.952 99.608 114.552 ;
     RECT  97.621 116.208 99.608 116.232 ;
     RECT  98.725 117.696 99.608 118.056 ;
     RECT  98.561 119.664 99.608 119.688 ;
     RECT  99.608 2.148 99.712 127.452 ;
     RECT  99.712 2.418 99.904 127.182 ;
     RECT  101.473 93.264 101.617 93.288 ;
     RECT  101.473 61.296 101.977 61.32 ;
     RECT  101.977 34.08 102.013 34.104 ;
     RECT  101.977 85.92 102.013 85.944 ;
     RECT  101.977 97.584 102.013 97.608 ;
     RECT  101.689 110.976 102.013 111 ;
     RECT  102.013 26.304 102.049 26.328 ;
     RECT  102.013 110.976 102.481 111.864 ;
     RECT  102.013 15.936 102.517 15.96 ;
     RECT  101.689 24.576 102.517 24.6 ;
     RECT  101.977 28.464 102.517 28.488 ;
     RECT  102.013 33.216 102.517 34.104 ;
     RECT  102.013 44.88 102.517 44.904 ;
     RECT  102.013 50.496 102.517 50.52 ;
     RECT  102.013 56.112 102.517 57 ;
     RECT  102.013 65.184 102.517 65.208 ;
     RECT  102.013 76.416 102.517 76.44 ;
     RECT  102.013 78.144 102.517 78.168 ;
     RECT  102.013 82.032 102.517 82.92 ;
     RECT  102.013 88.512 102.517 88.536 ;
     RECT  102.013 99.312 102.517 100.2 ;
     RECT  102.013 113.136 102.517 114.024 ;
     RECT  102.013 119.616 102.517 120.504 ;
     RECT  101.365 9.456 102.553 9.48 ;
     RECT  102.517 12.48 102.553 12.504 ;
     RECT  102.517 15.936 102.553 16.824 ;
     RECT  102.013 18.096 102.553 18.984 ;
     RECT  102.517 21.552 102.553 21.576 ;
     RECT  102.517 23.712 102.553 24.6 ;
     RECT  102.049 26.304 102.553 26.76 ;
     RECT  102.517 28.032 102.553 28.488 ;
     RECT  102.013 30.192 102.553 30.216 ;
     RECT  102.517 32.352 102.553 34.104 ;
     RECT  102.013 36.24 102.553 36.264 ;
     RECT  102.517 38.4 102.553 38.424 ;
     RECT  102.013 41.424 102.553 41.448 ;
     RECT  102.013 42.72 102.553 42.744 ;
     RECT  102.517 44.016 102.553 44.904 ;
     RECT  101.473 48.336 102.553 48.36 ;
     RECT  102.517 50.496 102.553 51.384 ;
     RECT  102.013 54.384 102.553 54.408 ;
     RECT  102.517 56.112 102.553 57.864 ;
     RECT  101.617 59.136 102.553 59.16 ;
     RECT  101.977 61.296 102.553 62.184 ;
     RECT  102.517 64.752 102.553 65.208 ;
     RECT  102.517 66.912 102.553 67.8 ;
     RECT  102.013 69.936 102.553 71.256 ;
     RECT  102.517 72.96 102.553 72.984 ;
     RECT  102.517 75.552 102.553 78.168 ;
     RECT  102.013 79.872 102.553 79.896 ;
     RECT  102.517 81.6 102.553 83.784 ;
     RECT  102.013 85.056 102.553 85.944 ;
     RECT  101.617 87.216 102.553 87.24 ;
     RECT  102.517 88.512 102.553 89.4 ;
     RECT  101.617 92.4 102.553 93.288 ;
     RECT  101.689 95.856 102.553 95.88 ;
     RECT  102.013 97.152 102.553 97.608 ;
     RECT  102.517 98.88 102.553 100.2 ;
     RECT  102.013 101.472 102.553 101.928 ;
     RECT  102.013 105.36 102.553 105.384 ;
     RECT  101.689 107.52 102.553 107.544 ;
     RECT  102.517 108.816 102.553 108.84 ;
     RECT  102.481 110.112 102.553 111.864 ;
     RECT  102.517 113.136 102.553 115.32 ;
     RECT  102.517 116.592 102.553 116.616 ;
     RECT  102.517 118.752 102.553 120.504 ;
     RECT  102.553 8.592 103.644 120.936 ;
    LAYER M5 ;
     RECT  2.4 2.137 2.52 2.151 ;
     RECT  7.8 2.137 7.92 2.151 ;
     RECT  13.2 2.137 13.32 2.151 ;
     RECT  18.6 2.137 18.72 2.151 ;
     RECT  24 2.137 24.12 2.151 ;
     RECT  29.4 2.137 29.52 2.151 ;
     RECT  34.8 2.137 34.92 2.151 ;
     RECT  40.2 2.137 40.32 2.151 ;
     RECT  45.6 2.137 45.72 2.151 ;
     RECT  51 2.137 51.12 2.151 ;
     RECT  56.4 2.137 56.52 2.151 ;
     RECT  61.8 2.137 61.92 2.151 ;
     RECT  67.2 2.137 67.32 2.151 ;
     RECT  72.6 2.137 72.72 2.151 ;
     RECT  78 2.137 78.12 2.151 ;
     RECT  83.4 2.137 83.52 2.151 ;
     RECT  88.8 2.137 88.92 2.151 ;
     RECT  94.2 2.137 94.32 2.151 ;
     RECT  99.6 2.137 99.72 2.151 ;
     RECT  52.368 9.061 52.392 10.355 ;
     RECT  6.288 9.637 6.312 10.837 ;
     RECT  4.272 8.293 4.296 10.883 ;
     RECT  49.584 9.637 49.608 10.883 ;
     RECT  5.664 10.837 6.312 11.315 ;
     RECT  51 2.151 51.312 11.365 ;
     RECT  96.624 11.029 96.648 11.941 ;
     RECT  98.016 11.845 98.04 11.941 ;
     RECT  5.664 11.315 5.688 12.035 ;
     RECT  96.624 11.941 98.04 12.755 ;
     RECT  5.472 12.373 5.496 13.045 ;
     RECT  97.056 12.755 98.04 13.139 ;
     RECT  50.256 11.365 51.312 13.669 ;
     RECT  52.416 10.789 52.44 13.669 ;
     RECT  5.472 13.045 5.688 13.715 ;
     RECT  50.256 13.669 52.44 13.715 ;
     RECT  5.472 13.715 5.496 14.341 ;
     RECT  50.256 13.715 51.864 14.773 ;
     RECT  5.376 14.341 5.496 15.395 ;
     RECT  50.016 14.773 51.864 15.779 ;
     RECT  50.016 15.779 51.816 16.019 ;
     RECT  97.056 13.139 97.08 16.501 ;
     RECT  97.056 16.501 97.416 18.419 ;
     RECT  50.256 16.019 51.816 18.611 ;
     RECT  4.368 16.501 4.392 18.851 ;
     RECT  6.576 18.037 6.6 19.427 ;
     RECT  50.496 18.611 51.816 19.667 ;
     RECT  97.056 18.419 97.128 19.669 ;
     RECT  97.056 19.669 97.368 19.715 ;
     RECT  5.472 15.395 5.496 19.909 ;
     RECT  97.344 19.715 97.368 19.909 ;
     RECT  5.328 19.909 5.496 19.955 ;
     RECT  4.32 19.141 4.344 20.051 ;
     RECT  94.2 2.151 94.512 20.197 ;
     RECT  50.496 19.667 51.48 20.293 ;
     RECT  97.344 19.909 98.088 20.579 ;
     RECT  50.208 20.293 51.48 21.253 ;
     RECT  94.2 20.197 95.208 21.683 ;
     RECT  5.328 19.955 5.352 23.317 ;
     RECT  50.208 21.253 51.72 23.363 ;
     RECT  5.088 23.317 5.352 24.229 ;
     RECT  7.8 2.151 8.112 24.469 ;
     RECT  50.208 23.363 51.312 25.861 ;
     RECT  52.8 24.469 52.824 25.861 ;
     RECT  50.208 25.861 52.824 25.907 ;
     RECT  4.8 24.229 5.352 26.197 ;
     RECT  98.592 24.229 98.616 26.243 ;
     RECT  6.864 24.469 8.112 26.341 ;
     RECT  6.864 26.341 8.232 26.387 ;
     RECT  95.808 23.365 95.832 26.483 ;
     RECT  4.56 26.197 5.352 26.677 ;
     RECT  4.56 26.677 5.928 26.723 ;
     RECT  97.344 20.579 97.368 26.725 ;
     RECT  97.344 26.725 98.376 26.771 ;
     RECT  4.56 26.723 4.584 27.347 ;
     RECT  97.44 26.771 98.376 27.635 ;
     RECT  5.904 26.723 5.928 27.733 ;
     RECT  50.208 25.907 51.912 27.925 ;
     RECT  7.8 26.387 8.232 27.971 ;
     RECT  50.16 27.925 51.912 28.547 ;
     RECT  5.232 27.733 5.928 29.651 ;
     RECT  50.16 28.547 51.312 29.795 ;
     RECT  98.592 28.405 98.616 30.035 ;
     RECT  50.208 29.795 51.312 30.181 ;
     RECT  95.76 29.605 95.784 30.277 ;
     RECT  95.76 30.277 95.976 30.323 ;
     RECT  97.44 27.635 97.464 30.949 ;
     RECT  95.952 30.323 95.976 31.667 ;
     RECT  97.44 30.949 98.04 31.667 ;
     RECT  7.8 27.971 8.112 32.293 ;
     RECT  7.2 32.293 8.112 32.483 ;
     RECT  97.44 31.667 97.464 33.013 ;
     RECT  97.44 33.013 97.8 33.733 ;
     RECT  5.904 29.651 5.928 34.165 ;
     RECT  7.8 32.483 8.112 34.165 ;
     RECT  97.056 33.733 97.8 34.211 ;
     RECT  5.904 34.165 8.112 34.835 ;
     RECT  50.208 30.181 52.008 35.171 ;
     RECT  7.8 34.835 8.112 35.605 ;
     RECT  97.056 34.211 97.08 35.941 ;
     RECT  98.064 35.317 98.088 36.803 ;
     RECT  7.8 35.605 8.232 36.947 ;
     RECT  3.84 34.789 3.864 37.619 ;
     RECT  96.432 35.941 97.08 37.619 ;
     RECT  5.904 34.835 6.312 38.147 ;
     RECT  50.208 35.171 51.768 38.341 ;
     RECT  50.208 38.341 51.864 38.819 ;
     RECT  97.056 37.619 97.08 39.061 ;
     RECT  4.224 38.149 4.248 39.203 ;
     RECT  97.056 39.061 97.272 39.923 ;
     RECT  98.592 39.589 98.616 39.923 ;
     RECT  52.416 39.877 52.44 40.309 ;
     RECT  7.8 36.947 8.112 40.405 ;
     RECT  52.416 40.309 52.68 40.499 ;
     RECT  3.984 39.877 4.008 41.029 ;
     RECT  3.984 41.029 4.584 41.075 ;
     RECT  97.056 39.923 97.08 41.557 ;
     RECT  97.056 41.557 97.416 41.603 ;
     RECT  4.56 41.075 4.584 41.651 ;
     RECT  97.392 41.603 97.416 41.749 ;
     RECT  50.208 38.819 51.312 42.179 ;
     RECT  7.056 40.405 8.112 42.227 ;
     RECT  94.2 21.683 94.512 42.709 ;
     RECT  95.808 40.405 95.832 42.755 ;
     RECT  94.2 42.709 94.632 42.805 ;
     RECT  4.512 42.133 4.536 43.285 ;
     RECT  5.904 38.147 5.928 43.285 ;
     RECT  50.4 42.179 51.312 43.285 ;
     RECT  52.416 40.499 52.584 43.285 ;
     RECT  4.512 43.285 5.928 43.331 ;
     RECT  7.8 42.227 8.112 43.333 ;
     RECT  97.392 41.749 97.464 43.523 ;
     RECT  4.512 43.331 5.496 43.667 ;
     RECT  94.2 42.805 94.728 43.763 ;
     RECT  6.864 43.333 8.112 43.955 ;
     RECT  5.472 43.667 5.496 45.109 ;
     RECT  97.392 43.523 97.416 46.165 ;
     RECT  98.496 45.301 98.52 46.741 ;
     RECT  98.496 46.741 98.616 46.787 ;
     RECT  98.592 46.787 98.616 46.885 ;
     RECT  99.6 2.151 99.912 46.885 ;
     RECT  98.592 46.885 99.912 46.931 ;
     RECT  5.472 45.109 6.456 47.315 ;
     RECT  50.4 43.285 52.584 47.317 ;
     RECT  96.432 46.165 97.416 47.507 ;
     RECT  98.832 46.931 99.912 48.083 ;
     RECT  97.392 47.507 97.416 48.805 ;
     RECT  96.864 48.805 97.416 48.851 ;
     RECT  7.8 43.955 8.112 49.525 ;
     RECT  5.472 47.315 5.496 49.717 ;
     RECT  5.424 49.717 5.496 50.245 ;
     RECT  5.424 50.245 5.592 50.291 ;
     RECT  50.112 47.317 52.584 50.291 ;
     RECT  50.112 50.291 51.312 50.579 ;
     RECT  98.304 49.045 98.328 51.635 ;
     RECT  5.472 50.291 5.592 52.357 ;
     RECT  5.472 52.357 5.688 52.403 ;
     RECT  50.4 50.579 51.312 52.405 ;
     RECT  52.56 50.291 52.584 52.405 ;
     RECT  7.488 49.525 8.112 52.595 ;
     RECT  50.4 52.405 52.584 52.979 ;
     RECT  96.864 48.851 96.888 52.981 ;
     RECT  94.2 43.763 94.512 54.661 ;
     RECT  96.864 52.981 97.032 54.709 ;
     RECT  94.2 54.661 94.776 56.195 ;
     RECT  96.864 54.709 97.08 56.483 ;
     RECT  5.664 52.403 5.688 56.917 ;
     RECT  96.864 56.483 97.032 57.827 ;
     RECT  50.64 52.979 52.584 58.645 ;
     RECT  7.8 52.595 8.112 59.269 ;
     RECT  50.16 58.645 52.584 59.459 ;
     RECT  99.6 48.083 99.912 60.661 ;
     RECT  4.752 56.917 5.688 61.043 ;
     RECT  7.056 59.269 8.112 61.525 ;
     RECT  4.752 61.043 4.776 61.619 ;
     RECT  98.832 60.661 99.912 61.619 ;
     RECT  52.56 59.459 52.584 62.101 ;
     RECT  50.16 59.459 51.312 62.195 ;
     RECT  6.864 61.525 8.112 62.435 ;
     RECT  96.864 57.827 96.888 63.109 ;
     RECT  51 62.195 51.312 63.493 ;
     RECT  52.56 62.101 52.872 63.539 ;
     RECT  94.2 56.195 94.512 63.733 ;
     RECT  96.864 63.109 97.608 63.827 ;
     RECT  51 63.493 51.432 63.829 ;
     RECT  94.2 63.733 95.064 64.165 ;
     RECT  50.688 63.829 51.432 64.211 ;
     RECT  94.2 64.165 95.736 64.211 ;
     RECT  97.584 63.827 97.608 64.787 ;
     RECT  7.056 62.435 8.112 64.883 ;
     RECT  51 64.211 51.432 65.509 ;
     RECT  52.56 63.539 52.584 65.509 ;
     RECT  5.664 65.509 5.688 66.085 ;
     RECT  95.712 64.211 95.736 66.275 ;
     RECT  5.136 66.085 5.688 66.755 ;
     RECT  51 65.509 52.584 67.237 ;
     RECT  4.608 67.669 4.632 68.915 ;
     RECT  97.728 68.341 97.752 69.155 ;
     RECT  4.56 69.493 4.584 70.213 ;
     RECT  5.664 66.755 5.688 70.213 ;
     RECT  4.56 70.213 5.688 70.259 ;
     RECT  5.088 70.259 5.688 70.979 ;
     RECT  7.8 64.883 8.112 71.221 ;
     RECT  7.152 71.221 8.112 71.651 ;
     RECT  99.6 61.619 99.912 71.749 ;
     RECT  96.144 70.693 96.168 71.843 ;
     RECT  98.64 71.749 99.912 72.995 ;
     RECT  5.28 70.979 5.688 74.099 ;
     RECT  97.248 70.405 97.272 75.829 ;
     RECT  96.912 75.829 97.272 76.979 ;
     RECT  5.664 74.099 5.688 77.125 ;
     RECT  99.6 72.995 99.912 77.701 ;
     RECT  5.664 77.125 6.264 78.083 ;
     RECT  5.76 78.083 6.264 78.131 ;
     RECT  50.88 67.237 52.584 78.613 ;
     RECT  95.712 77.173 95.736 78.707 ;
     RECT  50.832 78.613 52.584 79.283 ;
     RECT  98.928 77.701 99.912 79.573 ;
     RECT  5.76 78.131 5.784 80.101 ;
     RECT  4.512 79.189 4.536 80.675 ;
     RECT  5.76 80.101 5.832 81.347 ;
     RECT  50.88 79.283 52.584 81.445 ;
     RECT  98.64 79.573 99.912 81.491 ;
     RECT  5.76 81.347 5.784 82.309 ;
     RECT  50.784 81.445 52.584 82.837 ;
     RECT  97.248 76.979 97.272 82.837 ;
     RECT  50.016 82.837 52.584 83.459 ;
     RECT  97.248 82.837 97.8 84.323 ;
     RECT  7.8 71.651 8.112 84.325 ;
     RECT  5.712 82.309 5.784 84.851 ;
     RECT  51 83.459 52.584 85.045 ;
     RECT  51 85.045 52.68 85.237 ;
     RECT  97.248 84.323 97.272 85.379 ;
     RECT  51 85.237 52.872 85.381 ;
     RECT  99.6 81.491 99.912 85.477 ;
     RECT  7.68 84.325 8.112 85.669 ;
     RECT  94.2 64.211 94.512 85.909 ;
     RECT  95.52 82.597 95.544 85.909 ;
     RECT  94.2 85.909 95.544 85.955 ;
     RECT  50.16 85.381 52.872 86.435 ;
     RECT  7.104 85.669 8.112 86.629 ;
     RECT  50.16 86.435 52.824 86.915 ;
     RECT  50.592 86.915 52.824 87.491 ;
     RECT  98.64 85.477 99.912 87.827 ;
     RECT  94.2 85.955 95.208 87.875 ;
     RECT  4.32 83.125 4.344 88.115 ;
     RECT  97.2 85.477 97.224 88.309 ;
     RECT  50.592 87.491 52.68 88.403 ;
     RECT  7.056 86.629 8.112 88.595 ;
     RECT  97.2 88.309 98.088 89.941 ;
     RECT  96.048 89.269 96.072 89.987 ;
     RECT  97.2 89.941 98.328 89.987 ;
     RECT  5.76 84.851 5.784 90.037 ;
     RECT  51 88.403 52.68 90.373 ;
     RECT  50.016 90.373 52.68 90.565 ;
     RECT  50.016 90.565 52.824 90.659 ;
     RECT  94.2 87.875 94.512 90.901 ;
     RECT  98.304 89.987 98.328 90.901 ;
     RECT  98.304 90.901 98.616 90.947 ;
     RECT  5.376 90.037 5.976 91.141 ;
     RECT  4.416 91.141 5.976 91.811 ;
     RECT  50.016 90.659 51.624 91.811 ;
     RECT  94.2 90.901 95.208 92.579 ;
     RECT  97.2 89.987 97.224 92.675 ;
     RECT  98.592 90.947 98.616 92.915 ;
     RECT  5.952 91.811 5.976 93.203 ;
     RECT  50.736 91.811 51.624 93.251 ;
     RECT  97.152 92.869 97.176 94.069 ;
     RECT  95.616 93.349 95.64 94.115 ;
     RECT  47.328 90.565 47.352 95.219 ;
     RECT  97.152 94.069 97.272 95.219 ;
     RECT  51 93.251 51.624 95.653 ;
     RECT  52.8 90.659 52.824 96.277 ;
     RECT  4.992 95.509 5.016 96.371 ;
     RECT  50.688 95.653 51.624 96.899 ;
     RECT  99.6 87.827 99.912 97.429 ;
     RECT  97.152 95.219 97.176 98.533 ;
     RECT  98.736 97.429 99.912 98.675 ;
     RECT  6.624 97.669 6.648 99.157 ;
     RECT  7.8 88.595 8.112 99.157 ;
     RECT  6.624 99.157 8.112 99.203 ;
     RECT  52.8 96.277 53.304 99.541 ;
     RECT  4.56 98.581 4.584 99.925 ;
     RECT  4.56 99.925 4.824 99.971 ;
     RECT  96.336 98.533 97.176 100.117 ;
     RECT  4.8 99.971 4.824 100.645 ;
     RECT  51 96.899 51.624 100.837 ;
     RECT  96.336 100.117 97.272 101.027 ;
     RECT  4.8 100.645 5.304 101.173 ;
     RECT  50.688 100.837 51.624 102.229 ;
     RECT  52.8 99.541 53.592 102.275 ;
     RECT  98.304 100.309 98.328 102.371 ;
     RECT  97.248 101.027 97.272 102.613 ;
     RECT  6.912 99.203 8.112 102.659 ;
     RECT  50.688 102.229 51.816 102.659 ;
     RECT  97.248 102.613 98.088 103.475 ;
     RECT  4.752 101.173 5.304 103.763 ;
     RECT  5.28 103.763 5.304 104.821 ;
     RECT  51 102.659 51.816 105.397 ;
     RECT  50.16 105.397 51.816 105.587 ;
     RECT  52.8 102.275 52.824 105.635 ;
     RECT  97.248 103.475 97.272 105.877 ;
     RECT  50.16 105.587 51.624 106.451 ;
     RECT  7.8 102.659 8.112 106.549 ;
     RECT  4.56 104.821 5.304 106.691 ;
     RECT  96.912 105.877 97.272 107.171 ;
     RECT  50.4 106.451 51.624 107.701 ;
     RECT  99.6 98.675 99.912 107.701 ;
     RECT  49.584 107.701 51.624 108.181 ;
     RECT  7.056 106.549 8.112 108.227 ;
     RECT  53.088 105.973 53.112 108.227 ;
     RECT  97.248 107.171 97.272 108.805 ;
     RECT  97.056 108.805 97.272 108.851 ;
     RECT  99.168 107.701 99.912 109.043 ;
     RECT  7.344 108.227 8.112 109.475 ;
     RECT  49.584 108.181 52.008 109.955 ;
     RECT  94.2 92.579 94.512 110.485 ;
     RECT  97.056 108.851 97.08 111.685 ;
     RECT  6.72 111.685 6.744 112.643 ;
     RECT  99.6 109.043 99.912 113.941 ;
     RECT  7.8 109.475 8.112 114.373 ;
     RECT  97.056 111.685 97.512 114.563 ;
     RECT  98.64 113.941 99.912 114.563 ;
     RECT  94.2 110.485 95.352 114.611 ;
     RECT  5.28 106.691 5.304 115.093 ;
     RECT  4.608 115.093 5.304 115.525 ;
     RECT  4.608 115.525 5.688 115.571 ;
     RECT  50.4 109.955 52.008 115.619 ;
     RECT  4.608 115.571 4.632 116.197 ;
     RECT  4.512 116.197 4.632 116.243 ;
     RECT  97.056 114.563 97.08 116.339 ;
     RECT  50.4 115.619 51.624 117.109 ;
     RECT  4.512 116.243 4.536 117.443 ;
     RECT  2.4 2.151 2.712 117.637 ;
     RECT  49.68 117.109 51.624 117.925 ;
     RECT  7.2 114.373 8.112 118.019 ;
     RECT  94.2 114.611 94.512 118.165 ;
     RECT  2.4 117.637 3.432 118.595 ;
     RECT  49.68 117.925 52.488 119.029 ;
     RECT  49.68 119.029 52.728 119.075 ;
     RECT  5.664 115.571 5.688 119.077 ;
     RECT  98.736 114.563 99.912 119.699 ;
     RECT  94.2 118.165 95.064 120.179 ;
     RECT  7.8 118.019 8.112 120.229 ;
     RECT  4.8 119.077 5.688 120.275 ;
     RECT  5.664 120.275 5.688 120.323 ;
     RECT  49.68 119.075 51.624 120.323 ;
     RECT  49.824 120.323 51.624 120.899 ;
     RECT  7.8 120.229 8.232 121.619 ;
     RECT  49.824 120.899 49.848 124.307 ;
     RECT  52.704 119.075 52.728 125.459 ;
     RECT  2.4 118.595 2.712 127.449 ;
     RECT  7.8 121.619 8.112 127.449 ;
     RECT  13.2 2.151 13.512 127.449 ;
     RECT  18.6 2.151 18.912 127.449 ;
     RECT  24 2.151 24.312 127.449 ;
     RECT  29.4 2.151 29.712 127.449 ;
     RECT  34.8 2.151 35.112 127.449 ;
     RECT  40.2 2.151 40.512 127.449 ;
     RECT  45.6 2.151 45.912 127.449 ;
     RECT  56.4 2.151 56.712 127.449 ;
     RECT  61.8 2.151 62.112 127.449 ;
     RECT  67.2 2.151 67.512 127.449 ;
     RECT  72.6 2.151 72.912 127.449 ;
     RECT  78 2.151 78.312 127.449 ;
     RECT  83.4 2.151 83.712 127.449 ;
     RECT  88.8 2.151 89.112 127.449 ;
     RECT  94.2 120.179 94.512 127.449 ;
     RECT  99.6 119.699 99.912 127.449 ;
     RECT  2.4 127.449 2.52 127.463 ;
     RECT  7.8 127.449 7.92 127.463 ;
     RECT  13.2 127.449 13.32 127.463 ;
     RECT  18.6 127.449 18.72 127.463 ;
     RECT  24 127.449 24.12 127.463 ;
     RECT  29.4 127.449 29.52 127.463 ;
     RECT  34.8 127.449 34.92 127.463 ;
     RECT  40.2 127.449 40.32 127.463 ;
     RECT  45.6 127.449 45.72 127.463 ;
     RECT  51 120.899 51.624 127.463 ;
     RECT  56.4 127.449 56.52 127.463 ;
     RECT  61.8 127.449 61.92 127.463 ;
     RECT  67.2 127.449 67.32 127.463 ;
     RECT  72.6 127.449 72.72 127.463 ;
     RECT  78 127.449 78.12 127.463 ;
     RECT  83.4 127.449 83.52 127.463 ;
     RECT  88.8 127.449 88.92 127.463 ;
     RECT  94.2 127.449 94.32 127.463 ;
     RECT  99.6 127.449 99.72 127.463 ;
     RECT  51.6 127.463 51.624 127.621 ;
     RECT  51.6 127.621 52.056 129.552 ;
     RECT  51.312 9.061 52.368 10.355 ;
     RECT  6.312 9.637 7.8 11.315 ;
     RECT  49.608 9.637 51 10.883 ;
     RECT  51.312 10.355 52.392 10.789 ;
     RECT  51.312 10.789 52.416 13.669 ;
     RECT  4.296 10.837 5.664 10.883 ;
     RECT  5.472 10.883 5.664 12.035 ;
     RECT  50.256 10.883 51 11.365 ;
     RECT  96.648 11.845 98.016 11.941 ;
     RECT  5.472 12.035 5.688 12.373 ;
     RECT  5.496 12.373 5.688 13.045 ;
     RECT  5.376 15.395 5.472 16.501 ;
     RECT  4.392 16.501 5.472 18.851 ;
     RECT  5.496 18.037 6.576 19.427 ;
     RECT  6.6 18.037 7.8 19.427 ;
     RECT  97.128 18.419 97.416 19.669 ;
     RECT  4.368 18.851 5.472 19.141 ;
     RECT  4.344 19.141 5.472 19.909 ;
     RECT  97.368 19.669 97.416 19.909 ;
     RECT  4.344 19.909 5.328 20.051 ;
     RECT  98.088 19.909 99.6 20.579 ;
     RECT  51.312 23.363 51.72 24.469 ;
     RECT  94.512 23.365 95.808 26.483 ;
     RECT  95.832 23.365 97.344 26.483 ;
     RECT  97.368 24.229 98.592 26.243 ;
     RECT  98.616 24.229 99.6 26.243 ;
     RECT  5.352 24.469 6.864 26.387 ;
     RECT  51.312 24.469 52.8 25.861 ;
     RECT  97.368 26.243 99.6 26.725 ;
     RECT  5.352 26.387 5.928 26.677 ;
     RECT  4.584 26.723 5.904 27.347 ;
     RECT  98.376 26.725 99.6 27.635 ;
     RECT  5.232 27.347 5.904 27.733 ;
     RECT  97.464 27.635 99.6 28.405 ;
     RECT  97.464 28.405 98.592 30.035 ;
     RECT  98.616 28.405 99.6 30.035 ;
     RECT  94.512 29.605 95.76 30.323 ;
     RECT  97.464 30.035 98.04 30.949 ;
     RECT  95.976 30.277 97.44 31.667 ;
     RECT  94.512 30.323 95.952 31.667 ;
     RECT  97.464 31.667 97.8 33.013 ;
     RECT  5.928 32.293 7.2 32.483 ;
     RECT  97.08 34.211 97.8 35.317 ;
     RECT  2.712 34.789 3.84 37.619 ;
     RECT  6.312 34.835 7.8 38.147 ;
     RECT  97.08 35.317 98.064 36.803 ;
     RECT  98.088 35.317 99.6 36.803 ;
     RECT  2.712 37.619 3.864 38.149 ;
     RECT  2.712 38.149 4.224 39.203 ;
     RECT  51.312 38.819 51.864 39.877 ;
     RECT  2.712 39.203 4.008 39.877 ;
     RECT  97.272 39.589 98.592 39.923 ;
     RECT  98.616 39.589 99.6 39.923 ;
     RECT  2.712 39.877 3.984 41.075 ;
     RECT  51.312 39.877 52.416 43.285 ;
     RECT  5.928 40.405 7.056 42.227 ;
     RECT  94.512 40.405 95.808 42.709 ;
     RECT  95.832 40.405 97.056 41.603 ;
     RECT  4.584 41.029 5.904 41.651 ;
     RECT  4.512 41.075 4.56 41.651 ;
     RECT  4.512 41.651 5.904 42.133 ;
     RECT  4.536 42.133 5.904 43.285 ;
     RECT  5.928 42.227 7.8 43.331 ;
     RECT  94.632 42.709 95.808 42.755 ;
     RECT  94.632 42.755 94.728 42.805 ;
     RECT  5.496 43.331 7.8 43.333 ;
     RECT  5.496 43.333 6.864 43.955 ;
     RECT  5.496 43.955 7.8 45.109 ;
     RECT  6.456 45.109 7.8 47.315 ;
     RECT  97.416 45.301 98.496 46.787 ;
     RECT  98.52 45.301 99.6 46.741 ;
     RECT  98.616 46.741 99.6 46.885 ;
     RECT  97.416 46.787 98.592 46.931 ;
     RECT  97.416 46.931 98.832 48.083 ;
     RECT  96.864 47.507 97.392 48.805 ;
     RECT  97.416 48.083 99.6 48.851 ;
     RECT  96.888 48.851 99.6 49.045 ;
     RECT  96.888 49.045 98.304 51.635 ;
     RECT  98.328 49.045 99.6 51.635 ;
     RECT  51.312 50.291 52.56 52.405 ;
     RECT  96.888 51.635 97.032 52.981 ;
     RECT  5.688 59.269 7.056 61.043 ;
     RECT  51.312 59.459 52.56 63.493 ;
     RECT  6.864 61.043 7.056 61.525 ;
     RECT  51.432 63.493 52.56 65.509 ;
     RECT  94.512 64.211 95.712 66.275 ;
     RECT  5.136 66.755 5.664 67.669 ;
     RECT  4.632 67.669 5.664 68.915 ;
     RECT  4.608 68.915 5.664 69.493 ;
     RECT  4.584 69.493 5.664 70.213 ;
     RECT  96.168 70.693 97.248 71.843 ;
     RECT  5.688 71.221 7.152 71.651 ;
     RECT  97.272 71.749 98.64 72.995 ;
     RECT  96.912 76.979 97.248 77.173 ;
     RECT  94.512 77.173 95.712 78.707 ;
     RECT  95.736 77.173 97.248 78.707 ;
     RECT  5.664 78.083 5.76 79.189 ;
     RECT  4.536 79.189 5.76 80.675 ;
     RECT  97.272 79.573 98.64 81.491 ;
     RECT  97.272 81.491 97.8 82.837 ;
     RECT  94.512 82.597 95.52 85.909 ;
     RECT  4.344 83.125 5.712 84.851 ;
     RECT  97.272 84.323 97.8 85.379 ;
     RECT  4.344 84.851 5.76 88.115 ;
     RECT  97.248 85.379 97.8 85.477 ;
     RECT  97.224 85.477 98.64 87.827 ;
     RECT  5.784 85.669 7.104 86.629 ;
     RECT  5.784 86.629 7.056 88.595 ;
     RECT  97.224 87.827 99.6 88.309 ;
     RECT  98.088 88.309 99.6 89.941 ;
     RECT  5.784 88.595 5.976 90.037 ;
     RECT  96.072 89.269 97.2 89.987 ;
     RECT  98.328 89.941 99.6 90.901 ;
     RECT  97.224 89.987 98.304 90.947 ;
     RECT  45.912 90.565 47.328 95.219 ;
     RECT  51.624 90.659 52.8 102.229 ;
     RECT  98.616 90.901 99.6 92.915 ;
     RECT  97.224 90.947 98.592 92.675 ;
     RECT  94.512 92.579 95.208 93.349 ;
     RECT  97.2 92.675 98.592 92.869 ;
     RECT  97.176 92.869 98.592 92.915 ;
     RECT  97.176 92.915 97.272 94.069 ;
     RECT  94.512 93.349 95.616 94.115 ;
     RECT  95.64 93.349 97.152 94.115 ;
     RECT  6.648 97.669 7.8 99.157 ;
     RECT  4.752 99.971 4.8 101.173 ;
     RECT  97.272 100.309 98.304 102.371 ;
     RECT  98.328 100.309 99.6 102.371 ;
     RECT  51.816 102.229 52.8 105.587 ;
     RECT  97.272 102.371 99.6 102.613 ;
     RECT  98.088 102.613 99.6 103.475 ;
     RECT  4.752 103.763 5.28 104.821 ;
     RECT  51.624 105.587 52.8 105.635 ;
     RECT  51.624 105.635 52.824 105.973 ;
     RECT  51.624 105.973 53.088 108.181 ;
     RECT  50.16 106.451 50.4 107.701 ;
     RECT  52.008 108.181 53.088 108.227 ;
     RECT  5.304 111.685 6.72 112.643 ;
     RECT  6.744 111.685 7.8 112.643 ;
     RECT  97.512 113.941 98.64 114.563 ;
     RECT  5.688 115.525 7.2 118.019 ;
     RECT  4.632 115.571 5.664 116.243 ;
     RECT  4.536 116.243 5.664 117.443 ;
     RECT  51.624 119.075 52.704 125.459 ;
     RECT  49.848 120.899 51 124.307 ;
  END
END dsfd_vm_static_read_q7_p
END LIBRARY
